VERSION 5.8 ;
BUSBITCHARS "[]" ;
DIVIDERCHAR "/" ;
UNITS
    DATABASE MICRONS 1000 ;
END UNITS

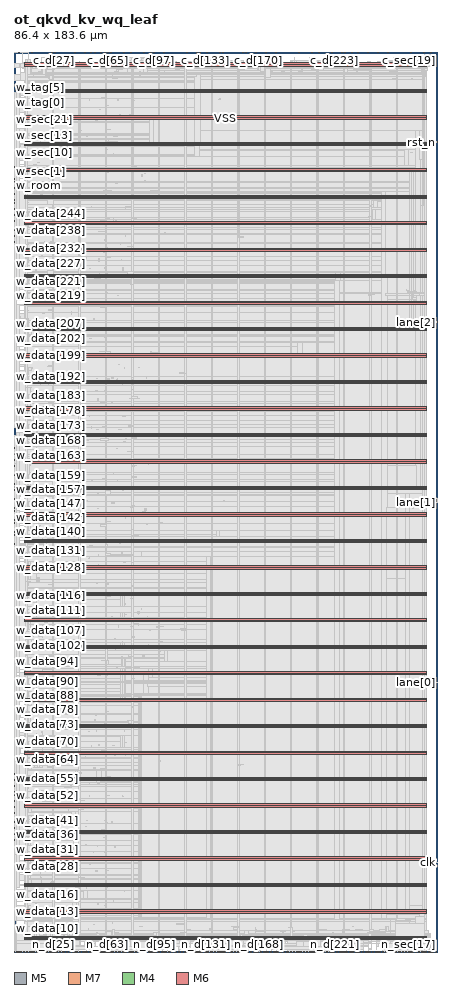
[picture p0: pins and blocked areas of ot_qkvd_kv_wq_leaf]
MACRO ot_qkvd_kv_wq_leaf
  FOREIGN ot_qkvd_kv_wq_leaf 0 0 ;
  CLASS BLOCK ;
  SIZE 86.4 BY 183.6 ;
  PIN c_d[0]
    DIRECTION INPUT ;
    USE SIGNAL ;
    PORT
      LAYER M5 ;
        RECT  0.144 183.516 0.168 183.6 ;
    END
  END c_d[0]
  PIN c_d[100]
    DIRECTION INPUT ;
    USE SIGNAL ;
    PORT
      LAYER M7 ;
        RECT  29.44 183.53 29.472 183.6 ;
    END
  END c_d[100]
  PIN c_d[101]
    DIRECTION INPUT ;
    USE SIGNAL ;
    PORT
      LAYER M7 ;
        RECT  29.696 183.53 29.728 183.6 ;
    END
  END c_d[101]
  PIN c_d[102]
    DIRECTION INPUT ;
    USE SIGNAL ;
    PORT
      LAYER M7 ;
        RECT  30.016 183.53 30.048 183.6 ;
    END
  END c_d[102]
  PIN c_d[103]
    DIRECTION INPUT ;
    USE SIGNAL ;
    PORT
      LAYER M7 ;
        RECT  30.272 183.53 30.304 183.6 ;
    END
  END c_d[103]
  PIN c_d[104]
    DIRECTION INPUT ;
    USE SIGNAL ;
    PORT
      LAYER M7 ;
        RECT  30.592 183.53 30.624 183.6 ;
    END
  END c_d[104]
  PIN c_d[105]
    DIRECTION INPUT ;
    USE SIGNAL ;
    PORT
      LAYER M7 ;
        RECT  30.912 183.53 30.944 183.6 ;
    END
  END c_d[105]
  PIN c_d[106]
    DIRECTION INPUT ;
    USE SIGNAL ;
    PORT
      LAYER M7 ;
        RECT  31.168 183.53 31.2 183.6 ;
    END
  END c_d[106]
  PIN c_d[107]
    DIRECTION INPUT ;
    USE SIGNAL ;
    PORT
      LAYER M7 ;
        RECT  31.488 183.53 31.52 183.6 ;
    END
  END c_d[107]
  PIN c_d[108]
    DIRECTION INPUT ;
    USE SIGNAL ;
    PORT
      LAYER M7 ;
        RECT  31.744 183.53 31.776 183.6 ;
    END
  END c_d[108]
  PIN c_d[109]
    DIRECTION INPUT ;
    USE SIGNAL ;
    PORT
      LAYER M7 ;
        RECT  32.064 183.53 32.096 183.6 ;
    END
  END c_d[109]
  PIN c_d[10]
    DIRECTION INPUT ;
    USE SIGNAL ;
    PORT
      LAYER M5 ;
        RECT  3.072 183.516 3.096 183.6 ;
    END
  END c_d[10]
  PIN c_d[110]
    DIRECTION INPUT ;
    USE SIGNAL ;
    PORT
      LAYER M7 ;
        RECT  32.32 183.53 32.352 183.6 ;
    END
  END c_d[110]
  PIN c_d[111]
    DIRECTION INPUT ;
    USE SIGNAL ;
    PORT
      LAYER M7 ;
        RECT  32.64 183.53 32.672 183.6 ;
    END
  END c_d[111]
  PIN c_d[112]
    DIRECTION INPUT ;
    USE SIGNAL ;
    PORT
      LAYER M7 ;
        RECT  32.96 183.53 32.992 183.6 ;
    END
  END c_d[112]
  PIN c_d[113]
    DIRECTION INPUT ;
    USE SIGNAL ;
    PORT
      LAYER M7 ;
        RECT  33.216 183.53 33.248 183.6 ;
    END
  END c_d[113]
  PIN c_d[114]
    DIRECTION INPUT ;
    USE SIGNAL ;
    PORT
      LAYER M7 ;
        RECT  33.536 183.53 33.568 183.6 ;
    END
  END c_d[114]
  PIN c_d[115]
    DIRECTION INPUT ;
    USE SIGNAL ;
    PORT
      LAYER M7 ;
        RECT  33.792 183.53 33.824 183.6 ;
    END
  END c_d[115]
  PIN c_d[116]
    DIRECTION INPUT ;
    USE SIGNAL ;
    PORT
      LAYER M7 ;
        RECT  34.112 183.53 34.144 183.6 ;
    END
  END c_d[116]
  PIN c_d[117]
    DIRECTION INPUT ;
    USE SIGNAL ;
    PORT
      LAYER M7 ;
        RECT  34.368 183.53 34.4 183.6 ;
    END
  END c_d[117]
  PIN c_d[118]
    DIRECTION INPUT ;
    USE SIGNAL ;
    PORT
      LAYER M7 ;
        RECT  34.688 183.53 34.72 183.6 ;
    END
  END c_d[118]
  PIN c_d[119]
    DIRECTION INPUT ;
    USE SIGNAL ;
    PORT
      LAYER M7 ;
        RECT  35.008 183.53 35.04 183.6 ;
    END
  END c_d[119]
  PIN c_d[11]
    DIRECTION INPUT ;
    USE SIGNAL ;
    PORT
      LAYER M5 ;
        RECT  3.36 183.516 3.384 183.6 ;
    END
  END c_d[11]
  PIN c_d[120]
    DIRECTION INPUT ;
    USE SIGNAL ;
    PORT
      LAYER M7 ;
        RECT  35.264 183.53 35.296 183.6 ;
    END
  END c_d[120]
  PIN c_d[121]
    DIRECTION INPUT ;
    USE SIGNAL ;
    PORT
      LAYER M7 ;
        RECT  35.584 183.53 35.616 183.6 ;
    END
  END c_d[121]
  PIN c_d[122]
    DIRECTION INPUT ;
    USE SIGNAL ;
    PORT
      LAYER M7 ;
        RECT  35.84 183.53 35.872 183.6 ;
    END
  END c_d[122]
  PIN c_d[123]
    DIRECTION INPUT ;
    USE SIGNAL ;
    PORT
      LAYER M7 ;
        RECT  36.16 183.53 36.192 183.6 ;
    END
  END c_d[123]
  PIN c_d[124]
    DIRECTION INPUT ;
    USE SIGNAL ;
    PORT
      LAYER M7 ;
        RECT  36.48 183.53 36.512 183.6 ;
    END
  END c_d[124]
  PIN c_d[125]
    DIRECTION INPUT ;
    USE SIGNAL ;
    PORT
      LAYER M7 ;
        RECT  36.736 183.53 36.768 183.6 ;
    END
  END c_d[125]
  PIN c_d[126]
    DIRECTION INPUT ;
    USE SIGNAL ;
    PORT
      LAYER M7 ;
        RECT  37.056 183.53 37.088 183.6 ;
    END
  END c_d[126]
  PIN c_d[127]
    DIRECTION INPUT ;
    USE SIGNAL ;
    PORT
      LAYER M7 ;
        RECT  37.312 183.53 37.344 183.6 ;
    END
  END c_d[127]
  PIN c_d[128]
    DIRECTION INPUT ;
    USE SIGNAL ;
    PORT
      LAYER M5 ;
        RECT  37.632 183.516 37.656 183.6 ;
    END
  END c_d[128]
  PIN c_d[129]
    DIRECTION INPUT ;
    USE SIGNAL ;
    PORT
      LAYER M5 ;
        RECT  37.92 183.516 37.944 183.6 ;
    END
  END c_d[129]
  PIN c_d[12]
    DIRECTION INPUT ;
    USE SIGNAL ;
    PORT
      LAYER M5 ;
        RECT  3.648 183.516 3.672 183.6 ;
    END
  END c_d[12]
  PIN c_d[130]
    DIRECTION INPUT ;
    USE SIGNAL ;
    PORT
      LAYER M5 ;
        RECT  38.208 183.516 38.232 183.6 ;
    END
  END c_d[130]
  PIN c_d[131]
    DIRECTION INPUT ;
    USE SIGNAL ;
    PORT
      LAYER M5 ;
        RECT  38.496 183.516 38.52 183.6 ;
    END
  END c_d[131]
  PIN c_d[132]
    DIRECTION INPUT ;
    USE SIGNAL ;
    PORT
      LAYER M5 ;
        RECT  38.784 183.516 38.808 183.6 ;
    END
  END c_d[132]
  PIN c_d[133]
    DIRECTION INPUT ;
    USE SIGNAL ;
    PORT
      LAYER M5 ;
        RECT  39.072 183.516 39.096 183.6 ;
    END
  END c_d[133]
  PIN c_d[134]
    DIRECTION INPUT ;
    USE SIGNAL ;
    PORT
      LAYER M5 ;
        RECT  39.36 183.516 39.384 183.6 ;
    END
  END c_d[134]
  PIN c_d[135]
    DIRECTION INPUT ;
    USE SIGNAL ;
    PORT
      LAYER M5 ;
        RECT  39.696 183.516 39.72 183.6 ;
    END
  END c_d[135]
  PIN c_d[136]
    DIRECTION INPUT ;
    USE SIGNAL ;
    PORT
      LAYER M5 ;
        RECT  39.984 183.516 40.008 183.6 ;
    END
  END c_d[136]
  PIN c_d[137]
    DIRECTION INPUT ;
    USE SIGNAL ;
    PORT
      LAYER M5 ;
        RECT  40.272 183.516 40.296 183.6 ;
    END
  END c_d[137]
  PIN c_d[138]
    DIRECTION INPUT ;
    USE SIGNAL ;
    PORT
      LAYER M5 ;
        RECT  40.56 183.516 40.584 183.6 ;
    END
  END c_d[138]
  PIN c_d[139]
    DIRECTION INPUT ;
    USE SIGNAL ;
    PORT
      LAYER M5 ;
        RECT  40.848 183.516 40.872 183.6 ;
    END
  END c_d[139]
  PIN c_d[13]
    DIRECTION INPUT ;
    USE SIGNAL ;
    PORT
      LAYER M5 ;
        RECT  3.936 183.516 3.96 183.6 ;
    END
  END c_d[13]
  PIN c_d[140]
    DIRECTION INPUT ;
    USE SIGNAL ;
    PORT
      LAYER M5 ;
        RECT  41.136 183.516 41.16 183.6 ;
    END
  END c_d[140]
  PIN c_d[141]
    DIRECTION INPUT ;
    USE SIGNAL ;
    PORT
      LAYER M5 ;
        RECT  41.424 183.516 41.448 183.6 ;
    END
  END c_d[141]
  PIN c_d[142]
    DIRECTION INPUT ;
    USE SIGNAL ;
    PORT
      LAYER M5 ;
        RECT  41.712 183.516 41.736 183.6 ;
    END
  END c_d[142]
  PIN c_d[143]
    DIRECTION INPUT ;
    USE SIGNAL ;
    PORT
      LAYER M5 ;
        RECT  42 183.516 42.024 183.6 ;
    END
  END c_d[143]
  PIN c_d[144]
    DIRECTION INPUT ;
    USE SIGNAL ;
    PORT
      LAYER M5 ;
        RECT  42.288 183.516 42.312 183.6 ;
    END
  END c_d[144]
  PIN c_d[145]
    DIRECTION INPUT ;
    USE SIGNAL ;
    PORT
      LAYER M5 ;
        RECT  42.624 183.516 42.648 183.6 ;
    END
  END c_d[145]
  PIN c_d[146]
    DIRECTION INPUT ;
    USE SIGNAL ;
    PORT
      LAYER M5 ;
        RECT  42.912 183.516 42.936 183.6 ;
    END
  END c_d[146]
  PIN c_d[147]
    DIRECTION INPUT ;
    USE SIGNAL ;
    PORT
      LAYER M5 ;
        RECT  43.2 183.516 43.224 183.6 ;
    END
  END c_d[147]
  PIN c_d[148]
    DIRECTION INPUT ;
    USE SIGNAL ;
    PORT
      LAYER M5 ;
        RECT  43.488 183.516 43.512 183.6 ;
    END
  END c_d[148]
  PIN c_d[149]
    DIRECTION INPUT ;
    USE SIGNAL ;
    PORT
      LAYER M5 ;
        RECT  43.776 183.516 43.8 183.6 ;
    END
  END c_d[149]
  PIN c_d[14]
    DIRECTION INPUT ;
    USE SIGNAL ;
    PORT
      LAYER M5 ;
        RECT  4.224 183.516 4.248 183.6 ;
    END
  END c_d[14]
  PIN c_d[150]
    DIRECTION INPUT ;
    USE SIGNAL ;
    PORT
      LAYER M5 ;
        RECT  44.064 183.516 44.088 183.6 ;
    END
  END c_d[150]
  PIN c_d[151]
    DIRECTION INPUT ;
    USE SIGNAL ;
    PORT
      LAYER M5 ;
        RECT  44.352 183.516 44.376 183.6 ;
    END
  END c_d[151]
  PIN c_d[152]
    DIRECTION INPUT ;
    USE SIGNAL ;
    PORT
      LAYER M5 ;
        RECT  44.64 183.516 44.664 183.6 ;
    END
  END c_d[152]
  PIN c_d[153]
    DIRECTION INPUT ;
    USE SIGNAL ;
    PORT
      LAYER M5 ;
        RECT  44.928 183.516 44.952 183.6 ;
    END
  END c_d[153]
  PIN c_d[154]
    DIRECTION INPUT ;
    USE SIGNAL ;
    PORT
      LAYER M5 ;
        RECT  45.216 183.516 45.24 183.6 ;
    END
  END c_d[154]
  PIN c_d[155]
    DIRECTION INPUT ;
    USE SIGNAL ;
    PORT
      LAYER M5 ;
        RECT  45.552 183.516 45.576 183.6 ;
    END
  END c_d[155]
  PIN c_d[156]
    DIRECTION INPUT ;
    USE SIGNAL ;
    PORT
      LAYER M5 ;
        RECT  45.84 183.516 45.864 183.6 ;
    END
  END c_d[156]
  PIN c_d[157]
    DIRECTION INPUT ;
    USE SIGNAL ;
    PORT
      LAYER M5 ;
        RECT  46.128 183.516 46.152 183.6 ;
    END
  END c_d[157]
  PIN c_d[158]
    DIRECTION INPUT ;
    USE SIGNAL ;
    PORT
      LAYER M5 ;
        RECT  46.416 183.516 46.44 183.6 ;
    END
  END c_d[158]
  PIN c_d[159]
    DIRECTION INPUT ;
    USE SIGNAL ;
    PORT
      LAYER M5 ;
        RECT  46.704 183.516 46.728 183.6 ;
    END
  END c_d[159]
  PIN c_d[15]
    DIRECTION INPUT ;
    USE SIGNAL ;
    PORT
      LAYER M5 ;
        RECT  4.512 183.516 4.536 183.6 ;
    END
  END c_d[15]
  PIN c_d[160]
    DIRECTION INPUT ;
    USE SIGNAL ;
    PORT
      LAYER M7 ;
        RECT  46.976 183.53 47.008 183.6 ;
    END
  END c_d[160]
  PIN c_d[161]
    DIRECTION INPUT ;
    USE SIGNAL ;
    PORT
      LAYER M7 ;
        RECT  47.296 183.53 47.328 183.6 ;
    END
  END c_d[161]
  PIN c_d[162]
    DIRECTION INPUT ;
    USE SIGNAL ;
    PORT
      LAYER M7 ;
        RECT  47.552 183.53 47.584 183.6 ;
    END
  END c_d[162]
  PIN c_d[163]
    DIRECTION INPUT ;
    USE SIGNAL ;
    PORT
      LAYER M7 ;
        RECT  47.872 183.53 47.904 183.6 ;
    END
  END c_d[163]
  PIN c_d[164]
    DIRECTION INPUT ;
    USE SIGNAL ;
    PORT
      LAYER M7 ;
        RECT  48.192 183.53 48.224 183.6 ;
    END
  END c_d[164]
  PIN c_d[165]
    DIRECTION INPUT ;
    USE SIGNAL ;
    PORT
      LAYER M7 ;
        RECT  48.448 183.53 48.48 183.6 ;
    END
  END c_d[165]
  PIN c_d[166]
    DIRECTION INPUT ;
    USE SIGNAL ;
    PORT
      LAYER M7 ;
        RECT  48.768 183.53 48.8 183.6 ;
    END
  END c_d[166]
  PIN c_d[167]
    DIRECTION INPUT ;
    USE SIGNAL ;
    PORT
      LAYER M7 ;
        RECT  49.024 183.53 49.056 183.6 ;
    END
  END c_d[167]
  PIN c_d[168]
    DIRECTION INPUT ;
    USE SIGNAL ;
    PORT
      LAYER M7 ;
        RECT  49.344 183.53 49.376 183.6 ;
    END
  END c_d[168]
  PIN c_d[169]
    DIRECTION INPUT ;
    USE SIGNAL ;
    PORT
      LAYER M7 ;
        RECT  49.6 183.53 49.632 183.6 ;
    END
  END c_d[169]
  PIN c_d[16]
    DIRECTION INPUT ;
    USE SIGNAL ;
    PORT
      LAYER M5 ;
        RECT  4.8 183.516 4.824 183.6 ;
    END
  END c_d[16]
  PIN c_d[170]
    DIRECTION INPUT ;
    USE SIGNAL ;
    PORT
      LAYER M7 ;
        RECT  49.92 183.53 49.952 183.6 ;
    END
  END c_d[170]
  PIN c_d[171]
    DIRECTION INPUT ;
    USE SIGNAL ;
    PORT
      LAYER M7 ;
        RECT  50.24 183.53 50.272 183.6 ;
    END
  END c_d[171]
  PIN c_d[172]
    DIRECTION INPUT ;
    USE SIGNAL ;
    PORT
      LAYER M7 ;
        RECT  50.496 183.53 50.528 183.6 ;
    END
  END c_d[172]
  PIN c_d[173]
    DIRECTION INPUT ;
    USE SIGNAL ;
    PORT
      LAYER M7 ;
        RECT  50.816 183.53 50.848 183.6 ;
    END
  END c_d[173]
  PIN c_d[174]
    DIRECTION INPUT ;
    USE SIGNAL ;
    PORT
      LAYER M7 ;
        RECT  51.072 183.53 51.104 183.6 ;
    END
  END c_d[174]
  PIN c_d[175]
    DIRECTION INPUT ;
    USE SIGNAL ;
    PORT
      LAYER M7 ;
        RECT  51.392 183.53 51.424 183.6 ;
    END
  END c_d[175]
  PIN c_d[176]
    DIRECTION INPUT ;
    USE SIGNAL ;
    PORT
      LAYER M7 ;
        RECT  51.648 183.53 51.68 183.6 ;
    END
  END c_d[176]
  PIN c_d[177]
    DIRECTION INPUT ;
    USE SIGNAL ;
    PORT
      LAYER M7 ;
        RECT  51.968 183.53 52 183.6 ;
    END
  END c_d[177]
  PIN c_d[178]
    DIRECTION INPUT ;
    USE SIGNAL ;
    PORT
      LAYER M7 ;
        RECT  52.288 183.53 52.32 183.6 ;
    END
  END c_d[178]
  PIN c_d[179]
    DIRECTION INPUT ;
    USE SIGNAL ;
    PORT
      LAYER M7 ;
        RECT  52.544 183.53 52.576 183.6 ;
    END
  END c_d[179]
  PIN c_d[17]
    DIRECTION INPUT ;
    USE SIGNAL ;
    PORT
      LAYER M5 ;
        RECT  5.136 183.516 5.16 183.6 ;
    END
  END c_d[17]
  PIN c_d[180]
    DIRECTION INPUT ;
    USE SIGNAL ;
    PORT
      LAYER M7 ;
        RECT  52.864 183.53 52.896 183.6 ;
    END
  END c_d[180]
  PIN c_d[181]
    DIRECTION INPUT ;
    USE SIGNAL ;
    PORT
      LAYER M7 ;
        RECT  53.12 183.53 53.152 183.6 ;
    END
  END c_d[181]
  PIN c_d[182]
    DIRECTION INPUT ;
    USE SIGNAL ;
    PORT
      LAYER M7 ;
        RECT  53.44 183.53 53.472 183.6 ;
    END
  END c_d[182]
  PIN c_d[183]
    DIRECTION INPUT ;
    USE SIGNAL ;
    PORT
      LAYER M7 ;
        RECT  53.76 183.53 53.792 183.6 ;
    END
  END c_d[183]
  PIN c_d[184]
    DIRECTION INPUT ;
    USE SIGNAL ;
    PORT
      LAYER M7 ;
        RECT  54.016 183.53 54.048 183.6 ;
    END
  END c_d[184]
  PIN c_d[185]
    DIRECTION INPUT ;
    USE SIGNAL ;
    PORT
      LAYER M7 ;
        RECT  54.336 183.53 54.368 183.6 ;
    END
  END c_d[185]
  PIN c_d[186]
    DIRECTION INPUT ;
    USE SIGNAL ;
    PORT
      LAYER M7 ;
        RECT  54.592 183.53 54.624 183.6 ;
    END
  END c_d[186]
  PIN c_d[187]
    DIRECTION INPUT ;
    USE SIGNAL ;
    PORT
      LAYER M7 ;
        RECT  54.912 183.53 54.944 183.6 ;
    END
  END c_d[187]
  PIN c_d[188]
    DIRECTION INPUT ;
    USE SIGNAL ;
    PORT
      LAYER M7 ;
        RECT  55.168 183.53 55.2 183.6 ;
    END
  END c_d[188]
  PIN c_d[189]
    DIRECTION INPUT ;
    USE SIGNAL ;
    PORT
      LAYER M7 ;
        RECT  55.488 183.53 55.52 183.6 ;
    END
  END c_d[189]
  PIN c_d[18]
    DIRECTION INPUT ;
    USE SIGNAL ;
    PORT
      LAYER M5 ;
        RECT  5.424 183.516 5.448 183.6 ;
    END
  END c_d[18]
  PIN c_d[190]
    DIRECTION INPUT ;
    USE SIGNAL ;
    PORT
      LAYER M7 ;
        RECT  55.808 183.53 55.84 183.6 ;
    END
  END c_d[190]
  PIN c_d[191]
    DIRECTION INPUT ;
    USE SIGNAL ;
    PORT
      LAYER M7 ;
        RECT  56.064 183.53 56.096 183.6 ;
    END
  END c_d[191]
  PIN c_d[192]
    DIRECTION INPUT ;
    USE SIGNAL ;
    PORT
      LAYER M5 ;
        RECT  56.352 183.516 56.376 183.6 ;
    END
  END c_d[192]
  PIN c_d[193]
    DIRECTION INPUT ;
    USE SIGNAL ;
    PORT
      LAYER M5 ;
        RECT  56.64 183.516 56.664 183.6 ;
    END
  END c_d[193]
  PIN c_d[194]
    DIRECTION INPUT ;
    USE SIGNAL ;
    PORT
      LAYER M5 ;
        RECT  56.976 183.516 57 183.6 ;
    END
  END c_d[194]
  PIN c_d[195]
    DIRECTION INPUT ;
    USE SIGNAL ;
    PORT
      LAYER M5 ;
        RECT  57.264 183.516 57.288 183.6 ;
    END
  END c_d[195]
  PIN c_d[196]
    DIRECTION INPUT ;
    USE SIGNAL ;
    PORT
      LAYER M5 ;
        RECT  57.552 183.516 57.576 183.6 ;
    END
  END c_d[196]
  PIN c_d[197]
    DIRECTION INPUT ;
    USE SIGNAL ;
    PORT
      LAYER M5 ;
        RECT  57.84 183.516 57.864 183.6 ;
    END
  END c_d[197]
  PIN c_d[198]
    DIRECTION INPUT ;
    USE SIGNAL ;
    PORT
      LAYER M5 ;
        RECT  58.128 183.516 58.152 183.6 ;
    END
  END c_d[198]
  PIN c_d[199]
    DIRECTION INPUT ;
    USE SIGNAL ;
    PORT
      LAYER M5 ;
        RECT  58.416 183.516 58.44 183.6 ;
    END
  END c_d[199]
  PIN c_d[19]
    DIRECTION INPUT ;
    USE SIGNAL ;
    PORT
      LAYER M5 ;
        RECT  5.712 183.516 5.736 183.6 ;
    END
  END c_d[19]
  PIN c_d[1]
    DIRECTION INPUT ;
    USE SIGNAL ;
    PORT
      LAYER M5 ;
        RECT  0.432 183.516 0.456 183.6 ;
    END
  END c_d[1]
  PIN c_d[200]
    DIRECTION INPUT ;
    USE SIGNAL ;
    PORT
      LAYER M5 ;
        RECT  58.704 183.516 58.728 183.6 ;
    END
  END c_d[200]
  PIN c_d[201]
    DIRECTION INPUT ;
    USE SIGNAL ;
    PORT
      LAYER M5 ;
        RECT  58.992 183.516 59.016 183.6 ;
    END
  END c_d[201]
  PIN c_d[202]
    DIRECTION INPUT ;
    USE SIGNAL ;
    PORT
      LAYER M5 ;
        RECT  59.28 183.516 59.304 183.6 ;
    END
  END c_d[202]
  PIN c_d[203]
    DIRECTION INPUT ;
    USE SIGNAL ;
    PORT
      LAYER M5 ;
        RECT  59.568 183.516 59.592 183.6 ;
    END
  END c_d[203]
  PIN c_d[204]
    DIRECTION INPUT ;
    USE SIGNAL ;
    PORT
      LAYER M5 ;
        RECT  59.904 183.516 59.928 183.6 ;
    END
  END c_d[204]
  PIN c_d[205]
    DIRECTION INPUT ;
    USE SIGNAL ;
    PORT
      LAYER M5 ;
        RECT  60.192 183.516 60.216 183.6 ;
    END
  END c_d[205]
  PIN c_d[206]
    DIRECTION INPUT ;
    USE SIGNAL ;
    PORT
      LAYER M5 ;
        RECT  60.48 183.516 60.504 183.6 ;
    END
  END c_d[206]
  PIN c_d[207]
    DIRECTION INPUT ;
    USE SIGNAL ;
    PORT
      LAYER M5 ;
        RECT  60.768 183.516 60.792 183.6 ;
    END
  END c_d[207]
  PIN c_d[208]
    DIRECTION INPUT ;
    USE SIGNAL ;
    PORT
      LAYER M5 ;
        RECT  61.056 183.516 61.08 183.6 ;
    END
  END c_d[208]
  PIN c_d[209]
    DIRECTION INPUT ;
    USE SIGNAL ;
    PORT
      LAYER M5 ;
        RECT  61.344 183.516 61.368 183.6 ;
    END
  END c_d[209]
  PIN c_d[20]
    DIRECTION INPUT ;
    USE SIGNAL ;
    PORT
      LAYER M5 ;
        RECT  6 183.516 6.024 183.6 ;
    END
  END c_d[20]
  PIN c_d[210]
    DIRECTION INPUT ;
    USE SIGNAL ;
    PORT
      LAYER M5 ;
        RECT  61.632 183.516 61.656 183.6 ;
    END
  END c_d[210]
  PIN c_d[211]
    DIRECTION INPUT ;
    USE SIGNAL ;
    PORT
      LAYER M5 ;
        RECT  61.92 183.516 61.944 183.6 ;
    END
  END c_d[211]
  PIN c_d[212]
    DIRECTION INPUT ;
    USE SIGNAL ;
    PORT
      LAYER M5 ;
        RECT  62.208 183.516 62.232 183.6 ;
    END
  END c_d[212]
  PIN c_d[213]
    DIRECTION INPUT ;
    USE SIGNAL ;
    PORT
      LAYER M5 ;
        RECT  62.496 183.516 62.52 183.6 ;
    END
  END c_d[213]
  PIN c_d[214]
    DIRECTION INPUT ;
    USE SIGNAL ;
    PORT
      LAYER M5 ;
        RECT  62.832 183.516 62.856 183.6 ;
    END
  END c_d[214]
  PIN c_d[215]
    DIRECTION INPUT ;
    USE SIGNAL ;
    PORT
      LAYER M5 ;
        RECT  63.12 183.516 63.144 183.6 ;
    END
  END c_d[215]
  PIN c_d[216]
    DIRECTION INPUT ;
    USE SIGNAL ;
    PORT
      LAYER M5 ;
        RECT  63.408 183.516 63.432 183.6 ;
    END
  END c_d[216]
  PIN c_d[217]
    DIRECTION INPUT ;
    USE SIGNAL ;
    PORT
      LAYER M5 ;
        RECT  63.696 183.516 63.72 183.6 ;
    END
  END c_d[217]
  PIN c_d[218]
    DIRECTION INPUT ;
    USE SIGNAL ;
    PORT
      LAYER M5 ;
        RECT  63.984 183.516 64.008 183.6 ;
    END
  END c_d[218]
  PIN c_d[219]
    DIRECTION INPUT ;
    USE SIGNAL ;
    PORT
      LAYER M5 ;
        RECT  64.272 183.516 64.296 183.6 ;
    END
  END c_d[219]
  PIN c_d[21]
    DIRECTION INPUT ;
    USE SIGNAL ;
    PORT
      LAYER M5 ;
        RECT  6.288 183.516 6.312 183.6 ;
    END
  END c_d[21]
  PIN c_d[220]
    DIRECTION INPUT ;
    USE SIGNAL ;
    PORT
      LAYER M5 ;
        RECT  64.56 183.516 64.584 183.6 ;
    END
  END c_d[220]
  PIN c_d[221]
    DIRECTION INPUT ;
    USE SIGNAL ;
    PORT
      LAYER M5 ;
        RECT  64.848 183.516 64.872 183.6 ;
    END
  END c_d[221]
  PIN c_d[222]
    DIRECTION INPUT ;
    USE SIGNAL ;
    PORT
      LAYER M5 ;
        RECT  65.136 183.516 65.16 183.6 ;
    END
  END c_d[222]
  PIN c_d[223]
    DIRECTION INPUT ;
    USE SIGNAL ;
    PORT
      LAYER M5 ;
        RECT  65.424 183.516 65.448 183.6 ;
    END
  END c_d[223]
  PIN c_d[224]
    DIRECTION INPUT ;
    USE SIGNAL ;
    PORT
      LAYER M7 ;
        RECT  65.728 183.53 65.76 183.6 ;
    END
  END c_d[224]
  PIN c_d[225]
    DIRECTION INPUT ;
    USE SIGNAL ;
    PORT
      LAYER M7 ;
        RECT  66.048 183.53 66.08 183.6 ;
    END
  END c_d[225]
  PIN c_d[226]
    DIRECTION INPUT ;
    USE SIGNAL ;
    PORT
      LAYER M7 ;
        RECT  66.304 183.53 66.336 183.6 ;
    END
  END c_d[226]
  PIN c_d[227]
    DIRECTION INPUT ;
    USE SIGNAL ;
    PORT
      LAYER M7 ;
        RECT  66.624 183.53 66.656 183.6 ;
    END
  END c_d[227]
  PIN c_d[228]
    DIRECTION INPUT ;
    USE SIGNAL ;
    PORT
      LAYER M7 ;
        RECT  66.88 183.53 66.912 183.6 ;
    END
  END c_d[228]
  PIN c_d[229]
    DIRECTION INPUT ;
    USE SIGNAL ;
    PORT
      LAYER M7 ;
        RECT  67.2 183.53 67.232 183.6 ;
    END
  END c_d[229]
  PIN c_d[22]
    DIRECTION INPUT ;
    USE SIGNAL ;
    PORT
      LAYER M5 ;
        RECT  6.576 183.516 6.6 183.6 ;
    END
  END c_d[22]
  PIN c_d[230]
    DIRECTION INPUT ;
    USE SIGNAL ;
    PORT
      LAYER M7 ;
        RECT  67.52 183.53 67.552 183.6 ;
    END
  END c_d[230]
  PIN c_d[231]
    DIRECTION INPUT ;
    USE SIGNAL ;
    PORT
      LAYER M7 ;
        RECT  67.776 183.53 67.808 183.6 ;
    END
  END c_d[231]
  PIN c_d[232]
    DIRECTION INPUT ;
    USE SIGNAL ;
    PORT
      LAYER M7 ;
        RECT  68.096 183.53 68.128 183.6 ;
    END
  END c_d[232]
  PIN c_d[233]
    DIRECTION INPUT ;
    USE SIGNAL ;
    PORT
      LAYER M7 ;
        RECT  68.352 183.53 68.384 183.6 ;
    END
  END c_d[233]
  PIN c_d[234]
    DIRECTION INPUT ;
    USE SIGNAL ;
    PORT
      LAYER M7 ;
        RECT  68.672 183.53 68.704 183.6 ;
    END
  END c_d[234]
  PIN c_d[235]
    DIRECTION INPUT ;
    USE SIGNAL ;
    PORT
      LAYER M7 ;
        RECT  68.928 183.53 68.96 183.6 ;
    END
  END c_d[235]
  PIN c_d[236]
    DIRECTION INPUT ;
    USE SIGNAL ;
    PORT
      LAYER M7 ;
        RECT  69.248 183.53 69.28 183.6 ;
    END
  END c_d[236]
  PIN c_d[237]
    DIRECTION INPUT ;
    USE SIGNAL ;
    PORT
      LAYER M7 ;
        RECT  69.568 183.53 69.6 183.6 ;
    END
  END c_d[237]
  PIN c_d[238]
    DIRECTION INPUT ;
    USE SIGNAL ;
    PORT
      LAYER M7 ;
        RECT  69.824 183.53 69.856 183.6 ;
    END
  END c_d[238]
  PIN c_d[239]
    DIRECTION INPUT ;
    USE SIGNAL ;
    PORT
      LAYER M7 ;
        RECT  70.144 183.53 70.176 183.6 ;
    END
  END c_d[239]
  PIN c_d[23]
    DIRECTION INPUT ;
    USE SIGNAL ;
    PORT
      LAYER M5 ;
        RECT  6.864 183.516 6.888 183.6 ;
    END
  END c_d[23]
  PIN c_d[240]
    DIRECTION INPUT ;
    USE SIGNAL ;
    PORT
      LAYER M7 ;
        RECT  70.4 183.53 70.432 183.6 ;
    END
  END c_d[240]
  PIN c_d[241]
    DIRECTION INPUT ;
    USE SIGNAL ;
    PORT
      LAYER M7 ;
        RECT  70.72 183.53 70.752 183.6 ;
    END
  END c_d[241]
  PIN c_d[242]
    DIRECTION INPUT ;
    USE SIGNAL ;
    PORT
      LAYER M7 ;
        RECT  71.04 183.53 71.072 183.6 ;
    END
  END c_d[242]
  PIN c_d[243]
    DIRECTION INPUT ;
    USE SIGNAL ;
    PORT
      LAYER M7 ;
        RECT  71.296 183.53 71.328 183.6 ;
    END
  END c_d[243]
  PIN c_d[244]
    DIRECTION INPUT ;
    USE SIGNAL ;
    PORT
      LAYER M7 ;
        RECT  71.616 183.53 71.648 183.6 ;
    END
  END c_d[244]
  PIN c_d[245]
    DIRECTION INPUT ;
    USE SIGNAL ;
    PORT
      LAYER M7 ;
        RECT  71.872 183.53 71.904 183.6 ;
    END
  END c_d[245]
  PIN c_d[246]
    DIRECTION INPUT ;
    USE SIGNAL ;
    PORT
      LAYER M7 ;
        RECT  72.192 183.53 72.224 183.6 ;
    END
  END c_d[246]
  PIN c_d[247]
    DIRECTION INPUT ;
    USE SIGNAL ;
    PORT
      LAYER M7 ;
        RECT  72.448 183.53 72.48 183.6 ;
    END
  END c_d[247]
  PIN c_d[248]
    DIRECTION INPUT ;
    USE SIGNAL ;
    PORT
      LAYER M7 ;
        RECT  72.768 183.53 72.8 183.6 ;
    END
  END c_d[248]
  PIN c_d[249]
    DIRECTION INPUT ;
    USE SIGNAL ;
    PORT
      LAYER M7 ;
        RECT  73.088 183.53 73.12 183.6 ;
    END
  END c_d[249]
  PIN c_d[24]
    DIRECTION INPUT ;
    USE SIGNAL ;
    PORT
      LAYER M5 ;
        RECT  7.152 183.516 7.176 183.6 ;
    END
  END c_d[24]
  PIN c_d[250]
    DIRECTION INPUT ;
    USE SIGNAL ;
    PORT
      LAYER M7 ;
        RECT  73.344 183.53 73.376 183.6 ;
    END
  END c_d[250]
  PIN c_d[251]
    DIRECTION INPUT ;
    USE SIGNAL ;
    PORT
      LAYER M7 ;
        RECT  73.664 183.53 73.696 183.6 ;
    END
  END c_d[251]
  PIN c_d[252]
    DIRECTION INPUT ;
    USE SIGNAL ;
    PORT
      LAYER M7 ;
        RECT  73.92 183.53 73.952 183.6 ;
    END
  END c_d[252]
  PIN c_d[253]
    DIRECTION INPUT ;
    USE SIGNAL ;
    PORT
      LAYER M7 ;
        RECT  74.24 183.53 74.272 183.6 ;
    END
  END c_d[253]
  PIN c_d[254]
    DIRECTION INPUT ;
    USE SIGNAL ;
    PORT
      LAYER M7 ;
        RECT  74.496 183.53 74.528 183.6 ;
    END
  END c_d[254]
  PIN c_d[255]
    DIRECTION INPUT ;
    USE SIGNAL ;
    PORT
      LAYER M7 ;
        RECT  74.816 183.53 74.848 183.6 ;
    END
  END c_d[255]
  PIN c_d[25]
    DIRECTION INPUT ;
    USE SIGNAL ;
    PORT
      LAYER M5 ;
        RECT  7.44 183.516 7.464 183.6 ;
    END
  END c_d[25]
  PIN c_d[26]
    DIRECTION INPUT ;
    USE SIGNAL ;
    PORT
      LAYER M5 ;
        RECT  7.728 183.516 7.752 183.6 ;
    END
  END c_d[26]
  PIN c_d[27]
    DIRECTION INPUT ;
    USE SIGNAL ;
    PORT
      LAYER M5 ;
        RECT  8.064 183.516 8.088 183.6 ;
    END
  END c_d[27]
  PIN c_d[28]
    DIRECTION INPUT ;
    USE SIGNAL ;
    PORT
      LAYER M5 ;
        RECT  8.352 183.516 8.376 183.6 ;
    END
  END c_d[28]
  PIN c_d[29]
    DIRECTION INPUT ;
    USE SIGNAL ;
    PORT
      LAYER M5 ;
        RECT  8.64 183.516 8.664 183.6 ;
    END
  END c_d[29]
  PIN c_d[2]
    DIRECTION INPUT ;
    USE SIGNAL ;
    PORT
      LAYER M5 ;
        RECT  0.72 183.516 0.744 183.6 ;
    END
  END c_d[2]
  PIN c_d[30]
    DIRECTION INPUT ;
    USE SIGNAL ;
    PORT
      LAYER M5 ;
        RECT  8.928 183.516 8.952 183.6 ;
    END
  END c_d[30]
  PIN c_d[31]
    DIRECTION INPUT ;
    USE SIGNAL ;
    PORT
      LAYER M5 ;
        RECT  9.216 183.516 9.24 183.6 ;
    END
  END c_d[31]
  PIN c_d[32]
    DIRECTION INPUT ;
    USE SIGNAL ;
    PORT
      LAYER M7 ;
        RECT  9.472 183.53 9.504 183.6 ;
    END
  END c_d[32]
  PIN c_d[33]
    DIRECTION INPUT ;
    USE SIGNAL ;
    PORT
      LAYER M7 ;
        RECT  9.792 183.53 9.824 183.6 ;
    END
  END c_d[33]
  PIN c_d[34]
    DIRECTION INPUT ;
    USE SIGNAL ;
    PORT
      LAYER M7 ;
        RECT  10.112 183.53 10.144 183.6 ;
    END
  END c_d[34]
  PIN c_d[35]
    DIRECTION INPUT ;
    USE SIGNAL ;
    PORT
      LAYER M7 ;
        RECT  10.368 183.53 10.4 183.6 ;
    END
  END c_d[35]
  PIN c_d[36]
    DIRECTION INPUT ;
    USE SIGNAL ;
    PORT
      LAYER M7 ;
        RECT  10.688 183.53 10.72 183.6 ;
    END
  END c_d[36]
  PIN c_d[37]
    DIRECTION INPUT ;
    USE SIGNAL ;
    PORT
      LAYER M7 ;
        RECT  10.944 183.53 10.976 183.6 ;
    END
  END c_d[37]
  PIN c_d[38]
    DIRECTION INPUT ;
    USE SIGNAL ;
    PORT
      LAYER M7 ;
        RECT  11.264 183.53 11.296 183.6 ;
    END
  END c_d[38]
  PIN c_d[39]
    DIRECTION INPUT ;
    USE SIGNAL ;
    PORT
      LAYER M7 ;
        RECT  11.584 183.53 11.616 183.6 ;
    END
  END c_d[39]
  PIN c_d[3]
    DIRECTION INPUT ;
    USE SIGNAL ;
    PORT
      LAYER M5 ;
        RECT  1.008 183.516 1.032 183.6 ;
    END
  END c_d[3]
  PIN c_d[40]
    DIRECTION INPUT ;
    USE SIGNAL ;
    PORT
      LAYER M7 ;
        RECT  11.84 183.53 11.872 183.6 ;
    END
  END c_d[40]
  PIN c_d[41]
    DIRECTION INPUT ;
    USE SIGNAL ;
    PORT
      LAYER M7 ;
        RECT  12.16 183.53 12.192 183.6 ;
    END
  END c_d[41]
  PIN c_d[42]
    DIRECTION INPUT ;
    USE SIGNAL ;
    PORT
      LAYER M7 ;
        RECT  12.416 183.53 12.448 183.6 ;
    END
  END c_d[42]
  PIN c_d[43]
    DIRECTION INPUT ;
    USE SIGNAL ;
    PORT
      LAYER M7 ;
        RECT  12.736 183.53 12.768 183.6 ;
    END
  END c_d[43]
  PIN c_d[44]
    DIRECTION INPUT ;
    USE SIGNAL ;
    PORT
      LAYER M7 ;
        RECT  12.992 183.53 13.024 183.6 ;
    END
  END c_d[44]
  PIN c_d[45]
    DIRECTION INPUT ;
    USE SIGNAL ;
    PORT
      LAYER M7 ;
        RECT  13.312 183.53 13.344 183.6 ;
    END
  END c_d[45]
  PIN c_d[46]
    DIRECTION INPUT ;
    USE SIGNAL ;
    PORT
      LAYER M7 ;
        RECT  13.632 183.53 13.664 183.6 ;
    END
  END c_d[46]
  PIN c_d[47]
    DIRECTION INPUT ;
    USE SIGNAL ;
    PORT
      LAYER M7 ;
        RECT  13.888 183.53 13.92 183.6 ;
    END
  END c_d[47]
  PIN c_d[48]
    DIRECTION INPUT ;
    USE SIGNAL ;
    PORT
      LAYER M7 ;
        RECT  14.208 183.53 14.24 183.6 ;
    END
  END c_d[48]
  PIN c_d[49]
    DIRECTION INPUT ;
    USE SIGNAL ;
    PORT
      LAYER M7 ;
        RECT  14.464 183.53 14.496 183.6 ;
    END
  END c_d[49]
  PIN c_d[4]
    DIRECTION INPUT ;
    USE SIGNAL ;
    PORT
      LAYER M5 ;
        RECT  1.296 183.516 1.32 183.6 ;
    END
  END c_d[4]
  PIN c_d[50]
    DIRECTION INPUT ;
    USE SIGNAL ;
    PORT
      LAYER M7 ;
        RECT  14.784 183.53 14.816 183.6 ;
    END
  END c_d[50]
  PIN c_d[51]
    DIRECTION INPUT ;
    USE SIGNAL ;
    PORT
      LAYER M7 ;
        RECT  15.04 183.53 15.072 183.6 ;
    END
  END c_d[51]
  PIN c_d[52]
    DIRECTION INPUT ;
    USE SIGNAL ;
    PORT
      LAYER M7 ;
        RECT  15.36 183.53 15.392 183.6 ;
    END
  END c_d[52]
  PIN c_d[53]
    DIRECTION INPUT ;
    USE SIGNAL ;
    PORT
      LAYER M7 ;
        RECT  15.68 183.53 15.712 183.6 ;
    END
  END c_d[53]
  PIN c_d[54]
    DIRECTION INPUT ;
    USE SIGNAL ;
    PORT
      LAYER M7 ;
        RECT  15.936 183.53 15.968 183.6 ;
    END
  END c_d[54]
  PIN c_d[55]
    DIRECTION INPUT ;
    USE SIGNAL ;
    PORT
      LAYER M7 ;
        RECT  16.256 183.53 16.288 183.6 ;
    END
  END c_d[55]
  PIN c_d[56]
    DIRECTION INPUT ;
    USE SIGNAL ;
    PORT
      LAYER M7 ;
        RECT  16.512 183.53 16.544 183.6 ;
    END
  END c_d[56]
  PIN c_d[57]
    DIRECTION INPUT ;
    USE SIGNAL ;
    PORT
      LAYER M7 ;
        RECT  16.832 183.53 16.864 183.6 ;
    END
  END c_d[57]
  PIN c_d[58]
    DIRECTION INPUT ;
    USE SIGNAL ;
    PORT
      LAYER M7 ;
        RECT  17.088 183.53 17.12 183.6 ;
    END
  END c_d[58]
  PIN c_d[59]
    DIRECTION INPUT ;
    USE SIGNAL ;
    PORT
      LAYER M7 ;
        RECT  17.408 183.53 17.44 183.6 ;
    END
  END c_d[59]
  PIN c_d[5]
    DIRECTION INPUT ;
    USE SIGNAL ;
    PORT
      LAYER M5 ;
        RECT  1.584 183.516 1.608 183.6 ;
    END
  END c_d[5]
  PIN c_d[60]
    DIRECTION INPUT ;
    USE SIGNAL ;
    PORT
      LAYER M7 ;
        RECT  17.728 183.53 17.76 183.6 ;
    END
  END c_d[60]
  PIN c_d[61]
    DIRECTION INPUT ;
    USE SIGNAL ;
    PORT
      LAYER M7 ;
        RECT  17.984 183.53 18.016 183.6 ;
    END
  END c_d[61]
  PIN c_d[62]
    DIRECTION INPUT ;
    USE SIGNAL ;
    PORT
      LAYER M7 ;
        RECT  18.304 183.53 18.336 183.6 ;
    END
  END c_d[62]
  PIN c_d[63]
    DIRECTION INPUT ;
    USE SIGNAL ;
    PORT
      LAYER M7 ;
        RECT  18.56 183.53 18.592 183.6 ;
    END
  END c_d[63]
  PIN c_d[64]
    DIRECTION INPUT ;
    USE SIGNAL ;
    PORT
      LAYER M5 ;
        RECT  18.864 183.516 18.888 183.6 ;
    END
  END c_d[64]
  PIN c_d[65]
    DIRECTION INPUT ;
    USE SIGNAL ;
    PORT
      LAYER M5 ;
        RECT  19.152 183.516 19.176 183.6 ;
    END
  END c_d[65]
  PIN c_d[66]
    DIRECTION INPUT ;
    USE SIGNAL ;
    PORT
      LAYER M5 ;
        RECT  19.488 183.516 19.512 183.6 ;
    END
  END c_d[66]
  PIN c_d[67]
    DIRECTION INPUT ;
    USE SIGNAL ;
    PORT
      LAYER M5 ;
        RECT  19.776 183.516 19.8 183.6 ;
    END
  END c_d[67]
  PIN c_d[68]
    DIRECTION INPUT ;
    USE SIGNAL ;
    PORT
      LAYER M5 ;
        RECT  20.064 183.516 20.088 183.6 ;
    END
  END c_d[68]
  PIN c_d[69]
    DIRECTION INPUT ;
    USE SIGNAL ;
    PORT
      LAYER M5 ;
        RECT  20.352 183.516 20.376 183.6 ;
    END
  END c_d[69]
  PIN c_d[6]
    DIRECTION INPUT ;
    USE SIGNAL ;
    PORT
      LAYER M5 ;
        RECT  1.872 183.516 1.896 183.6 ;
    END
  END c_d[6]
  PIN c_d[70]
    DIRECTION INPUT ;
    USE SIGNAL ;
    PORT
      LAYER M5 ;
        RECT  20.64 183.516 20.664 183.6 ;
    END
  END c_d[70]
  PIN c_d[71]
    DIRECTION INPUT ;
    USE SIGNAL ;
    PORT
      LAYER M5 ;
        RECT  20.928 183.516 20.952 183.6 ;
    END
  END c_d[71]
  PIN c_d[72]
    DIRECTION INPUT ;
    USE SIGNAL ;
    PORT
      LAYER M5 ;
        RECT  21.216 183.516 21.24 183.6 ;
    END
  END c_d[72]
  PIN c_d[73]
    DIRECTION INPUT ;
    USE SIGNAL ;
    PORT
      LAYER M5 ;
        RECT  21.504 183.516 21.528 183.6 ;
    END
  END c_d[73]
  PIN c_d[74]
    DIRECTION INPUT ;
    USE SIGNAL ;
    PORT
      LAYER M5 ;
        RECT  21.792 183.516 21.816 183.6 ;
    END
  END c_d[74]
  PIN c_d[75]
    DIRECTION INPUT ;
    USE SIGNAL ;
    PORT
      LAYER M5 ;
        RECT  22.08 183.516 22.104 183.6 ;
    END
  END c_d[75]
  PIN c_d[76]
    DIRECTION INPUT ;
    USE SIGNAL ;
    PORT
      LAYER M5 ;
        RECT  22.416 183.516 22.44 183.6 ;
    END
  END c_d[76]
  PIN c_d[77]
    DIRECTION INPUT ;
    USE SIGNAL ;
    PORT
      LAYER M5 ;
        RECT  22.704 183.516 22.728 183.6 ;
    END
  END c_d[77]
  PIN c_d[78]
    DIRECTION INPUT ;
    USE SIGNAL ;
    PORT
      LAYER M5 ;
        RECT  22.992 183.516 23.016 183.6 ;
    END
  END c_d[78]
  PIN c_d[79]
    DIRECTION INPUT ;
    USE SIGNAL ;
    PORT
      LAYER M5 ;
        RECT  23.28 183.516 23.304 183.6 ;
    END
  END c_d[79]
  PIN c_d[7]
    DIRECTION INPUT ;
    USE SIGNAL ;
    PORT
      LAYER M5 ;
        RECT  2.208 183.516 2.232 183.6 ;
    END
  END c_d[7]
  PIN c_d[80]
    DIRECTION INPUT ;
    USE SIGNAL ;
    PORT
      LAYER M5 ;
        RECT  23.568 183.516 23.592 183.6 ;
    END
  END c_d[80]
  PIN c_d[81]
    DIRECTION INPUT ;
    USE SIGNAL ;
    PORT
      LAYER M5 ;
        RECT  23.856 183.516 23.88 183.6 ;
    END
  END c_d[81]
  PIN c_d[82]
    DIRECTION INPUT ;
    USE SIGNAL ;
    PORT
      LAYER M5 ;
        RECT  24.144 183.516 24.168 183.6 ;
    END
  END c_d[82]
  PIN c_d[83]
    DIRECTION INPUT ;
    USE SIGNAL ;
    PORT
      LAYER M5 ;
        RECT  24.432 183.516 24.456 183.6 ;
    END
  END c_d[83]
  PIN c_d[84]
    DIRECTION INPUT ;
    USE SIGNAL ;
    PORT
      LAYER M5 ;
        RECT  24.72 183.516 24.744 183.6 ;
    END
  END c_d[84]
  PIN c_d[85]
    DIRECTION INPUT ;
    USE SIGNAL ;
    PORT
      LAYER M5 ;
        RECT  25.008 183.516 25.032 183.6 ;
    END
  END c_d[85]
  PIN c_d[86]
    DIRECTION INPUT ;
    USE SIGNAL ;
    PORT
      LAYER M5 ;
        RECT  25.344 183.516 25.368 183.6 ;
    END
  END c_d[86]
  PIN c_d[87]
    DIRECTION INPUT ;
    USE SIGNAL ;
    PORT
      LAYER M5 ;
        RECT  25.632 183.516 25.656 183.6 ;
    END
  END c_d[87]
  PIN c_d[88]
    DIRECTION INPUT ;
    USE SIGNAL ;
    PORT
      LAYER M5 ;
        RECT  25.92 183.516 25.944 183.6 ;
    END
  END c_d[88]
  PIN c_d[89]
    DIRECTION INPUT ;
    USE SIGNAL ;
    PORT
      LAYER M5 ;
        RECT  26.208 183.516 26.232 183.6 ;
    END
  END c_d[89]
  PIN c_d[8]
    DIRECTION INPUT ;
    USE SIGNAL ;
    PORT
      LAYER M5 ;
        RECT  2.496 183.516 2.52 183.6 ;
    END
  END c_d[8]
  PIN c_d[90]
    DIRECTION INPUT ;
    USE SIGNAL ;
    PORT
      LAYER M5 ;
        RECT  26.496 183.516 26.52 183.6 ;
    END
  END c_d[90]
  PIN c_d[91]
    DIRECTION INPUT ;
    USE SIGNAL ;
    PORT
      LAYER M5 ;
        RECT  26.784 183.516 26.808 183.6 ;
    END
  END c_d[91]
  PIN c_d[92]
    DIRECTION INPUT ;
    USE SIGNAL ;
    PORT
      LAYER M5 ;
        RECT  27.072 183.516 27.096 183.6 ;
    END
  END c_d[92]
  PIN c_d[93]
    DIRECTION INPUT ;
    USE SIGNAL ;
    PORT
      LAYER M5 ;
        RECT  27.36 183.516 27.384 183.6 ;
    END
  END c_d[93]
  PIN c_d[94]
    DIRECTION INPUT ;
    USE SIGNAL ;
    PORT
      LAYER M5 ;
        RECT  27.648 183.516 27.672 183.6 ;
    END
  END c_d[94]
  PIN c_d[95]
    DIRECTION INPUT ;
    USE SIGNAL ;
    PORT
      LAYER M5 ;
        RECT  27.936 183.516 27.96 183.6 ;
    END
  END c_d[95]
  PIN c_d[96]
    DIRECTION INPUT ;
    USE SIGNAL ;
    PORT
      LAYER M7 ;
        RECT  28.224 183.53 28.256 183.6 ;
    END
  END c_d[96]
  PIN c_d[97]
    DIRECTION INPUT ;
    USE SIGNAL ;
    PORT
      LAYER M7 ;
        RECT  28.544 183.53 28.576 183.6 ;
    END
  END c_d[97]
  PIN c_d[98]
    DIRECTION INPUT ;
    USE SIGNAL ;
    PORT
      LAYER M7 ;
        RECT  28.864 183.53 28.896 183.6 ;
    END
  END c_d[98]
  PIN c_d[99]
    DIRECTION INPUT ;
    USE SIGNAL ;
    PORT
      LAYER M7 ;
        RECT  29.12 183.53 29.152 183.6 ;
    END
  END c_d[99]
  PIN c_d[9]
    DIRECTION INPUT ;
    USE SIGNAL ;
    PORT
      LAYER M5 ;
        RECT  2.784 183.516 2.808 183.6 ;
    END
  END c_d[9]
  PIN c_lane[0]
    DIRECTION INPUT ;
    USE SIGNAL ;
    PORT
      LAYER M5 ;
        RECT  75.12 183.516 75.144 183.6 ;
    END
  END c_lane[0]
  PIN c_lane[1]
    DIRECTION INPUT ;
    USE SIGNAL ;
    PORT
      LAYER M5 ;
        RECT  75.408 183.516 75.432 183.6 ;
    END
  END c_lane[1]
  PIN c_lane[2]
    DIRECTION INPUT ;
    USE SIGNAL ;
    PORT
      LAYER M5 ;
        RECT  75.696 183.516 75.72 183.6 ;
    END
  END c_lane[2]
  PIN c_sec[0]
    DIRECTION INPUT ;
    USE SIGNAL ;
    PORT
      LAYER M5 ;
        RECT  75.984 183.516 76.008 183.6 ;
    END
  END c_sec[0]
  PIN c_sec[10]
    DIRECTION INPUT ;
    USE SIGNAL ;
    PORT
      LAYER M5 ;
        RECT  78.912 183.516 78.936 183.6 ;
    END
  END c_sec[10]
  PIN c_sec[11]
    DIRECTION INPUT ;
    USE SIGNAL ;
    PORT
      LAYER M5 ;
        RECT  79.2 183.516 79.224 183.6 ;
    END
  END c_sec[11]
  PIN c_sec[12]
    DIRECTION INPUT ;
    USE SIGNAL ;
    PORT
      LAYER M5 ;
        RECT  79.488 183.516 79.512 183.6 ;
    END
  END c_sec[12]
  PIN c_sec[13]
    DIRECTION INPUT ;
    USE SIGNAL ;
    PORT
      LAYER M5 ;
        RECT  79.776 183.516 79.8 183.6 ;
    END
  END c_sec[13]
  PIN c_sec[14]
    DIRECTION INPUT ;
    USE SIGNAL ;
    PORT
      LAYER M5 ;
        RECT  80.112 183.516 80.136 183.6 ;
    END
  END c_sec[14]
  PIN c_sec[15]
    DIRECTION INPUT ;
    USE SIGNAL ;
    PORT
      LAYER M5 ;
        RECT  80.4 183.516 80.424 183.6 ;
    END
  END c_sec[15]
  PIN c_sec[16]
    DIRECTION INPUT ;
    USE SIGNAL ;
    PORT
      LAYER M5 ;
        RECT  80.688 183.516 80.712 183.6 ;
    END
  END c_sec[16]
  PIN c_sec[17]
    DIRECTION INPUT ;
    USE SIGNAL ;
    PORT
      LAYER M5 ;
        RECT  80.976 183.516 81 183.6 ;
    END
  END c_sec[17]
  PIN c_sec[18]
    DIRECTION INPUT ;
    USE SIGNAL ;
    PORT
      LAYER M5 ;
        RECT  81.264 183.516 81.288 183.6 ;
    END
  END c_sec[18]
  PIN c_sec[19]
    DIRECTION INPUT ;
    USE SIGNAL ;
    PORT
      LAYER M5 ;
        RECT  81.552 183.516 81.576 183.6 ;
    END
  END c_sec[19]
  PIN c_sec[1]
    DIRECTION INPUT ;
    USE SIGNAL ;
    PORT
      LAYER M5 ;
        RECT  76.272 183.516 76.296 183.6 ;
    END
  END c_sec[1]
  PIN c_sec[20]
    DIRECTION INPUT ;
    USE SIGNAL ;
    PORT
      LAYER M5 ;
        RECT  81.84 183.516 81.864 183.6 ;
    END
  END c_sec[20]
  PIN c_sec[21]
    DIRECTION INPUT ;
    USE SIGNAL ;
    PORT
      LAYER M5 ;
        RECT  82.128 183.516 82.152 183.6 ;
    END
  END c_sec[21]
  PIN c_sec[22]
    DIRECTION INPUT ;
    USE SIGNAL ;
    PORT
      LAYER M5 ;
        RECT  82.416 183.516 82.44 183.6 ;
    END
  END c_sec[22]
  PIN c_sec[23]
    DIRECTION INPUT ;
    USE SIGNAL ;
    PORT
      LAYER M5 ;
        RECT  82.704 183.516 82.728 183.6 ;
    END
  END c_sec[23]
  PIN c_sec[2]
    DIRECTION INPUT ;
    USE SIGNAL ;
    PORT
      LAYER M5 ;
        RECT  76.56 183.516 76.584 183.6 ;
    END
  END c_sec[2]
  PIN c_sec[3]
    DIRECTION INPUT ;
    USE SIGNAL ;
    PORT
      LAYER M5 ;
        RECT  76.848 183.516 76.872 183.6 ;
    END
  END c_sec[3]
  PIN c_sec[4]
    DIRECTION INPUT ;
    USE SIGNAL ;
    PORT
      LAYER M5 ;
        RECT  77.184 183.516 77.208 183.6 ;
    END
  END c_sec[4]
  PIN c_sec[5]
    DIRECTION INPUT ;
    USE SIGNAL ;
    PORT
      LAYER M5 ;
        RECT  77.472 183.516 77.496 183.6 ;
    END
  END c_sec[5]
  PIN c_sec[6]
    DIRECTION INPUT ;
    USE SIGNAL ;
    PORT
      LAYER M5 ;
        RECT  77.76 183.516 77.784 183.6 ;
    END
  END c_sec[6]
  PIN c_sec[7]
    DIRECTION INPUT ;
    USE SIGNAL ;
    PORT
      LAYER M5 ;
        RECT  78.048 183.516 78.072 183.6 ;
    END
  END c_sec[7]
  PIN c_sec[8]
    DIRECTION INPUT ;
    USE SIGNAL ;
    PORT
      LAYER M5 ;
        RECT  78.336 183.516 78.36 183.6 ;
    END
  END c_sec[8]
  PIN c_sec[9]
    DIRECTION INPUT ;
    USE SIGNAL ;
    PORT
      LAYER M5 ;
        RECT  78.624 183.516 78.648 183.6 ;
    END
  END c_sec[9]
  PIN c_tag[0]
    DIRECTION INPUT ;
    USE SIGNAL ;
    PORT
      LAYER M5 ;
        RECT  83.04 183.516 83.064 183.6 ;
    END
  END c_tag[0]
  PIN c_tag[1]
    DIRECTION INPUT ;
    USE SIGNAL ;
    PORT
      LAYER M5 ;
        RECT  83.328 183.516 83.352 183.6 ;
    END
  END c_tag[1]
  PIN c_tag[2]
    DIRECTION INPUT ;
    USE SIGNAL ;
    PORT
      LAYER M5 ;
        RECT  83.616 183.516 83.64 183.6 ;
    END
  END c_tag[2]
  PIN c_tag[3]
    DIRECTION INPUT ;
    USE SIGNAL ;
    PORT
      LAYER M5 ;
        RECT  83.904 183.516 83.928 183.6 ;
    END
  END c_tag[3]
  PIN c_tag[4]
    DIRECTION INPUT ;
    USE SIGNAL ;
    PORT
      LAYER M5 ;
        RECT  84.192 183.516 84.216 183.6 ;
    END
  END c_tag[4]
  PIN c_tag[5]
    DIRECTION INPUT ;
    USE SIGNAL ;
    PORT
      LAYER M7 ;
        RECT  84.48 183.53 84.512 183.6 ;
    END
  END c_tag[5]
  PIN c_tag[6]
    DIRECTION INPUT ;
    USE SIGNAL ;
    PORT
      LAYER M7 ;
        RECT  84.8 183.53 84.832 183.6 ;
    END
  END c_tag[6]
  PIN c_tag[7]
    DIRECTION INPUT ;
    USE SIGNAL ;
    PORT
      LAYER M7 ;
        RECT  85.056 183.53 85.088 183.6 ;
    END
  END c_tag[7]
  PIN c_tag[8]
    DIRECTION INPUT ;
    USE SIGNAL ;
    PORT
      LAYER M7 ;
        RECT  85.376 183.53 85.408 183.6 ;
    END
  END c_tag[8]
  PIN c_v
    DIRECTION INPUT ;
    USE SIGNAL ;
    PORT
      LAYER M7 ;
        RECT  85.632 183.53 85.664 183.6 ;
    END
  END c_v
  PIN clk
    DIRECTION INPUT ;
    USE SIGNAL ;
    PORT
      LAYER M4 ;
        RECT  86.316 18.336 86.4 18.36 ;
    END
  END clk
  PIN dn_bad
    DIRECTION INPUT ;
    USE SIGNAL ;
    PORT
      LAYER M5 ;
        RECT  0.144 0 0.168 0.084 ;
    END
  END dn_bad
  PIN dn_v
    DIRECTION INPUT ;
    USE SIGNAL ;
    PORT
      LAYER M5 ;
        RECT  0.432 0 0.456 0.084 ;
    END
  END dn_v
  PIN dp_bad
    DIRECTION OUTPUT ;
    USE SIGNAL ;
    PORT
      LAYER M7 ;
        RECT  85.952 183.53 85.984 183.6 ;
    END
  END dp_bad
  PIN dp_v
    DIRECTION OUTPUT ;
    USE SIGNAL ;
    PORT
      LAYER M7 ;
        RECT  86.208 183.53 86.24 183.6 ;
    END
  END dp_v
  PIN lane[0]
    DIRECTION INPUT ;
    USE SIGNAL ;
    PORT
      LAYER M4 ;
        RECT  86.316 55.056 86.4 55.08 ;
    END
  END lane[0]
  PIN lane[1]
    DIRECTION INPUT ;
    USE SIGNAL ;
    PORT
      LAYER M4 ;
        RECT  86.316 91.776 86.4 91.8 ;
    END
  END lane[1]
  PIN lane[2]
    DIRECTION INPUT ;
    USE SIGNAL ;
    PORT
      LAYER M4 ;
        RECT  86.316 128.496 86.4 128.52 ;
    END
  END lane[2]
  PIN n_d[0]
    DIRECTION OUTPUT ;
    USE SIGNAL ;
    PORT
      LAYER M5 ;
        RECT  0.72 0 0.744 0.084 ;
    END
  END n_d[0]
  PIN n_d[100]
    DIRECTION OUTPUT ;
    USE SIGNAL ;
    PORT
      LAYER M7 ;
        RECT  30.016 0 30.048 0.07 ;
    END
  END n_d[100]
  PIN n_d[101]
    DIRECTION OUTPUT ;
    USE SIGNAL ;
    PORT
      LAYER M7 ;
        RECT  30.272 0 30.304 0.07 ;
    END
  END n_d[101]
  PIN n_d[102]
    DIRECTION OUTPUT ;
    USE SIGNAL ;
    PORT
      LAYER M7 ;
        RECT  30.592 0 30.624 0.07 ;
    END
  END n_d[102]
  PIN n_d[103]
    DIRECTION OUTPUT ;
    USE SIGNAL ;
    PORT
      LAYER M7 ;
        RECT  30.912 0 30.944 0.07 ;
    END
  END n_d[103]
  PIN n_d[104]
    DIRECTION OUTPUT ;
    USE SIGNAL ;
    PORT
      LAYER M7 ;
        RECT  31.168 0 31.2 0.07 ;
    END
  END n_d[104]
  PIN n_d[105]
    DIRECTION OUTPUT ;
    USE SIGNAL ;
    PORT
      LAYER M7 ;
        RECT  31.488 0 31.52 0.07 ;
    END
  END n_d[105]
  PIN n_d[106]
    DIRECTION OUTPUT ;
    USE SIGNAL ;
    PORT
      LAYER M7 ;
        RECT  31.744 0 31.776 0.07 ;
    END
  END n_d[106]
  PIN n_d[107]
    DIRECTION OUTPUT ;
    USE SIGNAL ;
    PORT
      LAYER M7 ;
        RECT  32.064 0 32.096 0.07 ;
    END
  END n_d[107]
  PIN n_d[108]
    DIRECTION OUTPUT ;
    USE SIGNAL ;
    PORT
      LAYER M7 ;
        RECT  32.32 0 32.352 0.07 ;
    END
  END n_d[108]
  PIN n_d[109]
    DIRECTION OUTPUT ;
    USE SIGNAL ;
    PORT
      LAYER M7 ;
        RECT  32.64 0 32.672 0.07 ;
    END
  END n_d[109]
  PIN n_d[10]
    DIRECTION OUTPUT ;
    USE SIGNAL ;
    PORT
      LAYER M5 ;
        RECT  3.648 0 3.672 0.084 ;
    END
  END n_d[10]
  PIN n_d[110]
    DIRECTION OUTPUT ;
    USE SIGNAL ;
    PORT
      LAYER M7 ;
        RECT  32.96 0 32.992 0.07 ;
    END
  END n_d[110]
  PIN n_d[111]
    DIRECTION OUTPUT ;
    USE SIGNAL ;
    PORT
      LAYER M7 ;
        RECT  33.216 0 33.248 0.07 ;
    END
  END n_d[111]
  PIN n_d[112]
    DIRECTION OUTPUT ;
    USE SIGNAL ;
    PORT
      LAYER M7 ;
        RECT  33.536 0 33.568 0.07 ;
    END
  END n_d[112]
  PIN n_d[113]
    DIRECTION OUTPUT ;
    USE SIGNAL ;
    PORT
      LAYER M7 ;
        RECT  33.792 0 33.824 0.07 ;
    END
  END n_d[113]
  PIN n_d[114]
    DIRECTION OUTPUT ;
    USE SIGNAL ;
    PORT
      LAYER M7 ;
        RECT  34.112 0 34.144 0.07 ;
    END
  END n_d[114]
  PIN n_d[115]
    DIRECTION OUTPUT ;
    USE SIGNAL ;
    PORT
      LAYER M7 ;
        RECT  34.368 0 34.4 0.07 ;
    END
  END n_d[115]
  PIN n_d[116]
    DIRECTION OUTPUT ;
    USE SIGNAL ;
    PORT
      LAYER M7 ;
        RECT  34.688 0 34.72 0.07 ;
    END
  END n_d[116]
  PIN n_d[117]
    DIRECTION OUTPUT ;
    USE SIGNAL ;
    PORT
      LAYER M7 ;
        RECT  35.008 0 35.04 0.07 ;
    END
  END n_d[117]
  PIN n_d[118]
    DIRECTION OUTPUT ;
    USE SIGNAL ;
    PORT
      LAYER M7 ;
        RECT  35.264 0 35.296 0.07 ;
    END
  END n_d[118]
  PIN n_d[119]
    DIRECTION OUTPUT ;
    USE SIGNAL ;
    PORT
      LAYER M7 ;
        RECT  35.584 0 35.616 0.07 ;
    END
  END n_d[119]
  PIN n_d[11]
    DIRECTION OUTPUT ;
    USE SIGNAL ;
    PORT
      LAYER M5 ;
        RECT  3.936 0 3.96 0.084 ;
    END
  END n_d[11]
  PIN n_d[120]
    DIRECTION OUTPUT ;
    USE SIGNAL ;
    PORT
      LAYER M7 ;
        RECT  35.84 0 35.872 0.07 ;
    END
  END n_d[120]
  PIN n_d[121]
    DIRECTION OUTPUT ;
    USE SIGNAL ;
    PORT
      LAYER M7 ;
        RECT  36.16 0 36.192 0.07 ;
    END
  END n_d[121]
  PIN n_d[122]
    DIRECTION OUTPUT ;
    USE SIGNAL ;
    PORT
      LAYER M7 ;
        RECT  36.48 0 36.512 0.07 ;
    END
  END n_d[122]
  PIN n_d[123]
    DIRECTION OUTPUT ;
    USE SIGNAL ;
    PORT
      LAYER M7 ;
        RECT  36.736 0 36.768 0.07 ;
    END
  END n_d[123]
  PIN n_d[124]
    DIRECTION OUTPUT ;
    USE SIGNAL ;
    PORT
      LAYER M7 ;
        RECT  37.056 0 37.088 0.07 ;
    END
  END n_d[124]
  PIN n_d[125]
    DIRECTION OUTPUT ;
    USE SIGNAL ;
    PORT
      LAYER M7 ;
        RECT  37.312 0 37.344 0.07 ;
    END
  END n_d[125]
  PIN n_d[126]
    DIRECTION OUTPUT ;
    USE SIGNAL ;
    PORT
      LAYER M5 ;
        RECT  37.632 0 37.656 0.084 ;
    END
  END n_d[126]
  PIN n_d[127]
    DIRECTION OUTPUT ;
    USE SIGNAL ;
    PORT
      LAYER M5 ;
        RECT  37.92 0 37.944 0.084 ;
    END
  END n_d[127]
  PIN n_d[128]
    DIRECTION OUTPUT ;
    USE SIGNAL ;
    PORT
      LAYER M5 ;
        RECT  38.208 0 38.232 0.084 ;
    END
  END n_d[128]
  PIN n_d[129]
    DIRECTION OUTPUT ;
    USE SIGNAL ;
    PORT
      LAYER M5 ;
        RECT  38.496 0 38.52 0.084 ;
    END
  END n_d[129]
  PIN n_d[12]
    DIRECTION OUTPUT ;
    USE SIGNAL ;
    PORT
      LAYER M5 ;
        RECT  4.224 0 4.248 0.084 ;
    END
  END n_d[12]
  PIN n_d[130]
    DIRECTION OUTPUT ;
    USE SIGNAL ;
    PORT
      LAYER M5 ;
        RECT  38.784 0 38.808 0.084 ;
    END
  END n_d[130]
  PIN n_d[131]
    DIRECTION OUTPUT ;
    USE SIGNAL ;
    PORT
      LAYER M5 ;
        RECT  39.072 0 39.096 0.084 ;
    END
  END n_d[131]
  PIN n_d[132]
    DIRECTION OUTPUT ;
    USE SIGNAL ;
    PORT
      LAYER M5 ;
        RECT  39.36 0 39.384 0.084 ;
    END
  END n_d[132]
  PIN n_d[133]
    DIRECTION OUTPUT ;
    USE SIGNAL ;
    PORT
      LAYER M5 ;
        RECT  39.696 0 39.72 0.084 ;
    END
  END n_d[133]
  PIN n_d[134]
    DIRECTION OUTPUT ;
    USE SIGNAL ;
    PORT
      LAYER M5 ;
        RECT  39.984 0 40.008 0.084 ;
    END
  END n_d[134]
  PIN n_d[135]
    DIRECTION OUTPUT ;
    USE SIGNAL ;
    PORT
      LAYER M5 ;
        RECT  40.272 0 40.296 0.084 ;
    END
  END n_d[135]
  PIN n_d[136]
    DIRECTION OUTPUT ;
    USE SIGNAL ;
    PORT
      LAYER M5 ;
        RECT  40.56 0 40.584 0.084 ;
    END
  END n_d[136]
  PIN n_d[137]
    DIRECTION OUTPUT ;
    USE SIGNAL ;
    PORT
      LAYER M5 ;
        RECT  40.848 0 40.872 0.084 ;
    END
  END n_d[137]
  PIN n_d[138]
    DIRECTION OUTPUT ;
    USE SIGNAL ;
    PORT
      LAYER M5 ;
        RECT  41.136 0 41.16 0.084 ;
    END
  END n_d[138]
  PIN n_d[139]
    DIRECTION OUTPUT ;
    USE SIGNAL ;
    PORT
      LAYER M5 ;
        RECT  41.424 0 41.448 0.084 ;
    END
  END n_d[139]
  PIN n_d[13]
    DIRECTION OUTPUT ;
    USE SIGNAL ;
    PORT
      LAYER M5 ;
        RECT  4.512 0 4.536 0.084 ;
    END
  END n_d[13]
  PIN n_d[140]
    DIRECTION OUTPUT ;
    USE SIGNAL ;
    PORT
      LAYER M5 ;
        RECT  41.712 0 41.736 0.084 ;
    END
  END n_d[140]
  PIN n_d[141]
    DIRECTION OUTPUT ;
    USE SIGNAL ;
    PORT
      LAYER M5 ;
        RECT  42 0 42.024 0.084 ;
    END
  END n_d[141]
  PIN n_d[142]
    DIRECTION OUTPUT ;
    USE SIGNAL ;
    PORT
      LAYER M5 ;
        RECT  42.288 0 42.312 0.084 ;
    END
  END n_d[142]
  PIN n_d[143]
    DIRECTION OUTPUT ;
    USE SIGNAL ;
    PORT
      LAYER M5 ;
        RECT  42.624 0 42.648 0.084 ;
    END
  END n_d[143]
  PIN n_d[144]
    DIRECTION OUTPUT ;
    USE SIGNAL ;
    PORT
      LAYER M5 ;
        RECT  42.912 0 42.936 0.084 ;
    END
  END n_d[144]
  PIN n_d[145]
    DIRECTION OUTPUT ;
    USE SIGNAL ;
    PORT
      LAYER M5 ;
        RECT  43.2 0 43.224 0.084 ;
    END
  END n_d[145]
  PIN n_d[146]
    DIRECTION OUTPUT ;
    USE SIGNAL ;
    PORT
      LAYER M5 ;
        RECT  43.488 0 43.512 0.084 ;
    END
  END n_d[146]
  PIN n_d[147]
    DIRECTION OUTPUT ;
    USE SIGNAL ;
    PORT
      LAYER M5 ;
        RECT  43.776 0 43.8 0.084 ;
    END
  END n_d[147]
  PIN n_d[148]
    DIRECTION OUTPUT ;
    USE SIGNAL ;
    PORT
      LAYER M5 ;
        RECT  44.064 0 44.088 0.084 ;
    END
  END n_d[148]
  PIN n_d[149]
    DIRECTION OUTPUT ;
    USE SIGNAL ;
    PORT
      LAYER M5 ;
        RECT  44.352 0 44.376 0.084 ;
    END
  END n_d[149]
  PIN n_d[14]
    DIRECTION OUTPUT ;
    USE SIGNAL ;
    PORT
      LAYER M5 ;
        RECT  4.8 0 4.824 0.084 ;
    END
  END n_d[14]
  PIN n_d[150]
    DIRECTION OUTPUT ;
    USE SIGNAL ;
    PORT
      LAYER M5 ;
        RECT  44.64 0 44.664 0.084 ;
    END
  END n_d[150]
  PIN n_d[151]
    DIRECTION OUTPUT ;
    USE SIGNAL ;
    PORT
      LAYER M5 ;
        RECT  44.928 0 44.952 0.084 ;
    END
  END n_d[151]
  PIN n_d[152]
    DIRECTION OUTPUT ;
    USE SIGNAL ;
    PORT
      LAYER M5 ;
        RECT  45.216 0 45.24 0.084 ;
    END
  END n_d[152]
  PIN n_d[153]
    DIRECTION OUTPUT ;
    USE SIGNAL ;
    PORT
      LAYER M5 ;
        RECT  45.552 0 45.576 0.084 ;
    END
  END n_d[153]
  PIN n_d[154]
    DIRECTION OUTPUT ;
    USE SIGNAL ;
    PORT
      LAYER M5 ;
        RECT  45.84 0 45.864 0.084 ;
    END
  END n_d[154]
  PIN n_d[155]
    DIRECTION OUTPUT ;
    USE SIGNAL ;
    PORT
      LAYER M5 ;
        RECT  46.128 0 46.152 0.084 ;
    END
  END n_d[155]
  PIN n_d[156]
    DIRECTION OUTPUT ;
    USE SIGNAL ;
    PORT
      LAYER M5 ;
        RECT  46.416 0 46.44 0.084 ;
    END
  END n_d[156]
  PIN n_d[157]
    DIRECTION OUTPUT ;
    USE SIGNAL ;
    PORT
      LAYER M5 ;
        RECT  46.704 0 46.728 0.084 ;
    END
  END n_d[157]
  PIN n_d[158]
    DIRECTION OUTPUT ;
    USE SIGNAL ;
    PORT
      LAYER M7 ;
        RECT  46.976 0 47.008 0.07 ;
    END
  END n_d[158]
  PIN n_d[159]
    DIRECTION OUTPUT ;
    USE SIGNAL ;
    PORT
      LAYER M7 ;
        RECT  47.296 0 47.328 0.07 ;
    END
  END n_d[159]
  PIN n_d[15]
    DIRECTION OUTPUT ;
    USE SIGNAL ;
    PORT
      LAYER M5 ;
        RECT  5.136 0 5.16 0.084 ;
    END
  END n_d[15]
  PIN n_d[160]
    DIRECTION OUTPUT ;
    USE SIGNAL ;
    PORT
      LAYER M7 ;
        RECT  47.552 0 47.584 0.07 ;
    END
  END n_d[160]
  PIN n_d[161]
    DIRECTION OUTPUT ;
    USE SIGNAL ;
    PORT
      LAYER M7 ;
        RECT  47.872 0 47.904 0.07 ;
    END
  END n_d[161]
  PIN n_d[162]
    DIRECTION OUTPUT ;
    USE SIGNAL ;
    PORT
      LAYER M7 ;
        RECT  48.192 0 48.224 0.07 ;
    END
  END n_d[162]
  PIN n_d[163]
    DIRECTION OUTPUT ;
    USE SIGNAL ;
    PORT
      LAYER M7 ;
        RECT  48.448 0 48.48 0.07 ;
    END
  END n_d[163]
  PIN n_d[164]
    DIRECTION OUTPUT ;
    USE SIGNAL ;
    PORT
      LAYER M7 ;
        RECT  48.768 0 48.8 0.07 ;
    END
  END n_d[164]
  PIN n_d[165]
    DIRECTION OUTPUT ;
    USE SIGNAL ;
    PORT
      LAYER M7 ;
        RECT  49.024 0 49.056 0.07 ;
    END
  END n_d[165]
  PIN n_d[166]
    DIRECTION OUTPUT ;
    USE SIGNAL ;
    PORT
      LAYER M7 ;
        RECT  49.344 0 49.376 0.07 ;
    END
  END n_d[166]
  PIN n_d[167]
    DIRECTION OUTPUT ;
    USE SIGNAL ;
    PORT
      LAYER M7 ;
        RECT  49.6 0 49.632 0.07 ;
    END
  END n_d[167]
  PIN n_d[168]
    DIRECTION OUTPUT ;
    USE SIGNAL ;
    PORT
      LAYER M7 ;
        RECT  49.92 0 49.952 0.07 ;
    END
  END n_d[168]
  PIN n_d[169]
    DIRECTION OUTPUT ;
    USE SIGNAL ;
    PORT
      LAYER M7 ;
        RECT  50.24 0 50.272 0.07 ;
    END
  END n_d[169]
  PIN n_d[16]
    DIRECTION OUTPUT ;
    USE SIGNAL ;
    PORT
      LAYER M5 ;
        RECT  5.424 0 5.448 0.084 ;
    END
  END n_d[16]
  PIN n_d[170]
    DIRECTION OUTPUT ;
    USE SIGNAL ;
    PORT
      LAYER M7 ;
        RECT  50.496 0 50.528 0.07 ;
    END
  END n_d[170]
  PIN n_d[171]
    DIRECTION OUTPUT ;
    USE SIGNAL ;
    PORT
      LAYER M7 ;
        RECT  50.816 0 50.848 0.07 ;
    END
  END n_d[171]
  PIN n_d[172]
    DIRECTION OUTPUT ;
    USE SIGNAL ;
    PORT
      LAYER M7 ;
        RECT  51.072 0 51.104 0.07 ;
    END
  END n_d[172]
  PIN n_d[173]
    DIRECTION OUTPUT ;
    USE SIGNAL ;
    PORT
      LAYER M7 ;
        RECT  51.392 0 51.424 0.07 ;
    END
  END n_d[173]
  PIN n_d[174]
    DIRECTION OUTPUT ;
    USE SIGNAL ;
    PORT
      LAYER M7 ;
        RECT  51.648 0 51.68 0.07 ;
    END
  END n_d[174]
  PIN n_d[175]
    DIRECTION OUTPUT ;
    USE SIGNAL ;
    PORT
      LAYER M7 ;
        RECT  51.968 0 52 0.07 ;
    END
  END n_d[175]
  PIN n_d[176]
    DIRECTION OUTPUT ;
    USE SIGNAL ;
    PORT
      LAYER M7 ;
        RECT  52.288 0 52.32 0.07 ;
    END
  END n_d[176]
  PIN n_d[177]
    DIRECTION OUTPUT ;
    USE SIGNAL ;
    PORT
      LAYER M7 ;
        RECT  52.544 0 52.576 0.07 ;
    END
  END n_d[177]
  PIN n_d[178]
    DIRECTION OUTPUT ;
    USE SIGNAL ;
    PORT
      LAYER M7 ;
        RECT  52.864 0 52.896 0.07 ;
    END
  END n_d[178]
  PIN n_d[179]
    DIRECTION OUTPUT ;
    USE SIGNAL ;
    PORT
      LAYER M7 ;
        RECT  53.12 0 53.152 0.07 ;
    END
  END n_d[179]
  PIN n_d[17]
    DIRECTION OUTPUT ;
    USE SIGNAL ;
    PORT
      LAYER M5 ;
        RECT  5.712 0 5.736 0.084 ;
    END
  END n_d[17]
  PIN n_d[180]
    DIRECTION OUTPUT ;
    USE SIGNAL ;
    PORT
      LAYER M7 ;
        RECT  53.44 0 53.472 0.07 ;
    END
  END n_d[180]
  PIN n_d[181]
    DIRECTION OUTPUT ;
    USE SIGNAL ;
    PORT
      LAYER M7 ;
        RECT  53.76 0 53.792 0.07 ;
    END
  END n_d[181]
  PIN n_d[182]
    DIRECTION OUTPUT ;
    USE SIGNAL ;
    PORT
      LAYER M7 ;
        RECT  54.016 0 54.048 0.07 ;
    END
  END n_d[182]
  PIN n_d[183]
    DIRECTION OUTPUT ;
    USE SIGNAL ;
    PORT
      LAYER M7 ;
        RECT  54.336 0 54.368 0.07 ;
    END
  END n_d[183]
  PIN n_d[184]
    DIRECTION OUTPUT ;
    USE SIGNAL ;
    PORT
      LAYER M7 ;
        RECT  54.592 0 54.624 0.07 ;
    END
  END n_d[184]
  PIN n_d[185]
    DIRECTION OUTPUT ;
    USE SIGNAL ;
    PORT
      LAYER M7 ;
        RECT  54.912 0 54.944 0.07 ;
    END
  END n_d[185]
  PIN n_d[186]
    DIRECTION OUTPUT ;
    USE SIGNAL ;
    PORT
      LAYER M7 ;
        RECT  55.168 0 55.2 0.07 ;
    END
  END n_d[186]
  PIN n_d[187]
    DIRECTION OUTPUT ;
    USE SIGNAL ;
    PORT
      LAYER M7 ;
        RECT  55.488 0 55.52 0.07 ;
    END
  END n_d[187]
  PIN n_d[188]
    DIRECTION OUTPUT ;
    USE SIGNAL ;
    PORT
      LAYER M7 ;
        RECT  55.808 0 55.84 0.07 ;
    END
  END n_d[188]
  PIN n_d[189]
    DIRECTION OUTPUT ;
    USE SIGNAL ;
    PORT
      LAYER M7 ;
        RECT  56.064 0 56.096 0.07 ;
    END
  END n_d[189]
  PIN n_d[18]
    DIRECTION OUTPUT ;
    USE SIGNAL ;
    PORT
      LAYER M5 ;
        RECT  6 0 6.024 0.084 ;
    END
  END n_d[18]
  PIN n_d[190]
    DIRECTION OUTPUT ;
    USE SIGNAL ;
    PORT
      LAYER M5 ;
        RECT  56.352 0 56.376 0.084 ;
    END
  END n_d[190]
  PIN n_d[191]
    DIRECTION OUTPUT ;
    USE SIGNAL ;
    PORT
      LAYER M5 ;
        RECT  56.64 0 56.664 0.084 ;
    END
  END n_d[191]
  PIN n_d[192]
    DIRECTION OUTPUT ;
    USE SIGNAL ;
    PORT
      LAYER M5 ;
        RECT  56.976 0 57 0.084 ;
    END
  END n_d[192]
  PIN n_d[193]
    DIRECTION OUTPUT ;
    USE SIGNAL ;
    PORT
      LAYER M5 ;
        RECT  57.264 0 57.288 0.084 ;
    END
  END n_d[193]
  PIN n_d[194]
    DIRECTION OUTPUT ;
    USE SIGNAL ;
    PORT
      LAYER M5 ;
        RECT  57.552 0 57.576 0.084 ;
    END
  END n_d[194]
  PIN n_d[195]
    DIRECTION OUTPUT ;
    USE SIGNAL ;
    PORT
      LAYER M5 ;
        RECT  57.84 0 57.864 0.084 ;
    END
  END n_d[195]
  PIN n_d[196]
    DIRECTION OUTPUT ;
    USE SIGNAL ;
    PORT
      LAYER M5 ;
        RECT  58.128 0 58.152 0.084 ;
    END
  END n_d[196]
  PIN n_d[197]
    DIRECTION OUTPUT ;
    USE SIGNAL ;
    PORT
      LAYER M5 ;
        RECT  58.416 0 58.44 0.084 ;
    END
  END n_d[197]
  PIN n_d[198]
    DIRECTION OUTPUT ;
    USE SIGNAL ;
    PORT
      LAYER M5 ;
        RECT  58.704 0 58.728 0.084 ;
    END
  END n_d[198]
  PIN n_d[199]
    DIRECTION OUTPUT ;
    USE SIGNAL ;
    PORT
      LAYER M5 ;
        RECT  58.992 0 59.016 0.084 ;
    END
  END n_d[199]
  PIN n_d[19]
    DIRECTION OUTPUT ;
    USE SIGNAL ;
    PORT
      LAYER M5 ;
        RECT  6.288 0 6.312 0.084 ;
    END
  END n_d[19]
  PIN n_d[1]
    DIRECTION OUTPUT ;
    USE SIGNAL ;
    PORT
      LAYER M5 ;
        RECT  1.008 0 1.032 0.084 ;
    END
  END n_d[1]
  PIN n_d[200]
    DIRECTION OUTPUT ;
    USE SIGNAL ;
    PORT
      LAYER M5 ;
        RECT  59.28 0 59.304 0.084 ;
    END
  END n_d[200]
  PIN n_d[201]
    DIRECTION OUTPUT ;
    USE SIGNAL ;
    PORT
      LAYER M5 ;
        RECT  59.568 0 59.592 0.084 ;
    END
  END n_d[201]
  PIN n_d[202]
    DIRECTION OUTPUT ;
    USE SIGNAL ;
    PORT
      LAYER M5 ;
        RECT  59.904 0 59.928 0.084 ;
    END
  END n_d[202]
  PIN n_d[203]
    DIRECTION OUTPUT ;
    USE SIGNAL ;
    PORT
      LAYER M5 ;
        RECT  60.192 0 60.216 0.084 ;
    END
  END n_d[203]
  PIN n_d[204]
    DIRECTION OUTPUT ;
    USE SIGNAL ;
    PORT
      LAYER M5 ;
        RECT  60.48 0 60.504 0.084 ;
    END
  END n_d[204]
  PIN n_d[205]
    DIRECTION OUTPUT ;
    USE SIGNAL ;
    PORT
      LAYER M5 ;
        RECT  60.768 0 60.792 0.084 ;
    END
  END n_d[205]
  PIN n_d[206]
    DIRECTION OUTPUT ;
    USE SIGNAL ;
    PORT
      LAYER M5 ;
        RECT  61.056 0 61.08 0.084 ;
    END
  END n_d[206]
  PIN n_d[207]
    DIRECTION OUTPUT ;
    USE SIGNAL ;
    PORT
      LAYER M5 ;
        RECT  61.344 0 61.368 0.084 ;
    END
  END n_d[207]
  PIN n_d[208]
    DIRECTION OUTPUT ;
    USE SIGNAL ;
    PORT
      LAYER M5 ;
        RECT  61.632 0 61.656 0.084 ;
    END
  END n_d[208]
  PIN n_d[209]
    DIRECTION OUTPUT ;
    USE SIGNAL ;
    PORT
      LAYER M5 ;
        RECT  61.92 0 61.944 0.084 ;
    END
  END n_d[209]
  PIN n_d[20]
    DIRECTION OUTPUT ;
    USE SIGNAL ;
    PORT
      LAYER M5 ;
        RECT  6.576 0 6.6 0.084 ;
    END
  END n_d[20]
  PIN n_d[210]
    DIRECTION OUTPUT ;
    USE SIGNAL ;
    PORT
      LAYER M5 ;
        RECT  62.208 0 62.232 0.084 ;
    END
  END n_d[210]
  PIN n_d[211]
    DIRECTION OUTPUT ;
    USE SIGNAL ;
    PORT
      LAYER M5 ;
        RECT  62.496 0 62.52 0.084 ;
    END
  END n_d[211]
  PIN n_d[212]
    DIRECTION OUTPUT ;
    USE SIGNAL ;
    PORT
      LAYER M5 ;
        RECT  62.832 0 62.856 0.084 ;
    END
  END n_d[212]
  PIN n_d[213]
    DIRECTION OUTPUT ;
    USE SIGNAL ;
    PORT
      LAYER M5 ;
        RECT  63.12 0 63.144 0.084 ;
    END
  END n_d[213]
  PIN n_d[214]
    DIRECTION OUTPUT ;
    USE SIGNAL ;
    PORT
      LAYER M5 ;
        RECT  63.408 0 63.432 0.084 ;
    END
  END n_d[214]
  PIN n_d[215]
    DIRECTION OUTPUT ;
    USE SIGNAL ;
    PORT
      LAYER M5 ;
        RECT  63.696 0 63.72 0.084 ;
    END
  END n_d[215]
  PIN n_d[216]
    DIRECTION OUTPUT ;
    USE SIGNAL ;
    PORT
      LAYER M5 ;
        RECT  63.984 0 64.008 0.084 ;
    END
  END n_d[216]
  PIN n_d[217]
    DIRECTION OUTPUT ;
    USE SIGNAL ;
    PORT
      LAYER M5 ;
        RECT  64.272 0 64.296 0.084 ;
    END
  END n_d[217]
  PIN n_d[218]
    DIRECTION OUTPUT ;
    USE SIGNAL ;
    PORT
      LAYER M5 ;
        RECT  64.56 0 64.584 0.084 ;
    END
  END n_d[218]
  PIN n_d[219]
    DIRECTION OUTPUT ;
    USE SIGNAL ;
    PORT
      LAYER M5 ;
        RECT  64.848 0 64.872 0.084 ;
    END
  END n_d[219]
  PIN n_d[21]
    DIRECTION OUTPUT ;
    USE SIGNAL ;
    PORT
      LAYER M5 ;
        RECT  6.864 0 6.888 0.084 ;
    END
  END n_d[21]
  PIN n_d[220]
    DIRECTION OUTPUT ;
    USE SIGNAL ;
    PORT
      LAYER M5 ;
        RECT  65.136 0 65.16 0.084 ;
    END
  END n_d[220]
  PIN n_d[221]
    DIRECTION OUTPUT ;
    USE SIGNAL ;
    PORT
      LAYER M5 ;
        RECT  65.424 0 65.448 0.084 ;
    END
  END n_d[221]
  PIN n_d[222]
    DIRECTION OUTPUT ;
    USE SIGNAL ;
    PORT
      LAYER M7 ;
        RECT  65.728 0 65.76 0.07 ;
    END
  END n_d[222]
  PIN n_d[223]
    DIRECTION OUTPUT ;
    USE SIGNAL ;
    PORT
      LAYER M7 ;
        RECT  66.048 0 66.08 0.07 ;
    END
  END n_d[223]
  PIN n_d[224]
    DIRECTION OUTPUT ;
    USE SIGNAL ;
    PORT
      LAYER M7 ;
        RECT  66.304 0 66.336 0.07 ;
    END
  END n_d[224]
  PIN n_d[225]
    DIRECTION OUTPUT ;
    USE SIGNAL ;
    PORT
      LAYER M7 ;
        RECT  66.624 0 66.656 0.07 ;
    END
  END n_d[225]
  PIN n_d[226]
    DIRECTION OUTPUT ;
    USE SIGNAL ;
    PORT
      LAYER M7 ;
        RECT  66.88 0 66.912 0.07 ;
    END
  END n_d[226]
  PIN n_d[227]
    DIRECTION OUTPUT ;
    USE SIGNAL ;
    PORT
      LAYER M7 ;
        RECT  67.2 0 67.232 0.07 ;
    END
  END n_d[227]
  PIN n_d[228]
    DIRECTION OUTPUT ;
    USE SIGNAL ;
    PORT
      LAYER M7 ;
        RECT  67.52 0 67.552 0.07 ;
    END
  END n_d[228]
  PIN n_d[229]
    DIRECTION OUTPUT ;
    USE SIGNAL ;
    PORT
      LAYER M7 ;
        RECT  67.776 0 67.808 0.07 ;
    END
  END n_d[229]
  PIN n_d[22]
    DIRECTION OUTPUT ;
    USE SIGNAL ;
    PORT
      LAYER M5 ;
        RECT  7.152 0 7.176 0.084 ;
    END
  END n_d[22]
  PIN n_d[230]
    DIRECTION OUTPUT ;
    USE SIGNAL ;
    PORT
      LAYER M7 ;
        RECT  68.096 0 68.128 0.07 ;
    END
  END n_d[230]
  PIN n_d[231]
    DIRECTION OUTPUT ;
    USE SIGNAL ;
    PORT
      LAYER M7 ;
        RECT  68.352 0 68.384 0.07 ;
    END
  END n_d[231]
  PIN n_d[232]
    DIRECTION OUTPUT ;
    USE SIGNAL ;
    PORT
      LAYER M7 ;
        RECT  68.672 0 68.704 0.07 ;
    END
  END n_d[232]
  PIN n_d[233]
    DIRECTION OUTPUT ;
    USE SIGNAL ;
    PORT
      LAYER M7 ;
        RECT  68.928 0 68.96 0.07 ;
    END
  END n_d[233]
  PIN n_d[234]
    DIRECTION OUTPUT ;
    USE SIGNAL ;
    PORT
      LAYER M7 ;
        RECT  69.248 0 69.28 0.07 ;
    END
  END n_d[234]
  PIN n_d[235]
    DIRECTION OUTPUT ;
    USE SIGNAL ;
    PORT
      LAYER M7 ;
        RECT  69.568 0 69.6 0.07 ;
    END
  END n_d[235]
  PIN n_d[236]
    DIRECTION OUTPUT ;
    USE SIGNAL ;
    PORT
      LAYER M7 ;
        RECT  69.824 0 69.856 0.07 ;
    END
  END n_d[236]
  PIN n_d[237]
    DIRECTION OUTPUT ;
    USE SIGNAL ;
    PORT
      LAYER M7 ;
        RECT  70.144 0 70.176 0.07 ;
    END
  END n_d[237]
  PIN n_d[238]
    DIRECTION OUTPUT ;
    USE SIGNAL ;
    PORT
      LAYER M7 ;
        RECT  70.4 0 70.432 0.07 ;
    END
  END n_d[238]
  PIN n_d[239]
    DIRECTION OUTPUT ;
    USE SIGNAL ;
    PORT
      LAYER M7 ;
        RECT  70.72 0 70.752 0.07 ;
    END
  END n_d[239]
  PIN n_d[23]
    DIRECTION OUTPUT ;
    USE SIGNAL ;
    PORT
      LAYER M5 ;
        RECT  7.44 0 7.464 0.084 ;
    END
  END n_d[23]
  PIN n_d[240]
    DIRECTION OUTPUT ;
    USE SIGNAL ;
    PORT
      LAYER M7 ;
        RECT  71.04 0 71.072 0.07 ;
    END
  END n_d[240]
  PIN n_d[241]
    DIRECTION OUTPUT ;
    USE SIGNAL ;
    PORT
      LAYER M7 ;
        RECT  71.296 0 71.328 0.07 ;
    END
  END n_d[241]
  PIN n_d[242]
    DIRECTION OUTPUT ;
    USE SIGNAL ;
    PORT
      LAYER M7 ;
        RECT  71.616 0 71.648 0.07 ;
    END
  END n_d[242]
  PIN n_d[243]
    DIRECTION OUTPUT ;
    USE SIGNAL ;
    PORT
      LAYER M7 ;
        RECT  71.872 0 71.904 0.07 ;
    END
  END n_d[243]
  PIN n_d[244]
    DIRECTION OUTPUT ;
    USE SIGNAL ;
    PORT
      LAYER M7 ;
        RECT  72.192 0 72.224 0.07 ;
    END
  END n_d[244]
  PIN n_d[245]
    DIRECTION OUTPUT ;
    USE SIGNAL ;
    PORT
      LAYER M7 ;
        RECT  72.448 0 72.48 0.07 ;
    END
  END n_d[245]
  PIN n_d[246]
    DIRECTION OUTPUT ;
    USE SIGNAL ;
    PORT
      LAYER M7 ;
        RECT  72.768 0 72.8 0.07 ;
    END
  END n_d[246]
  PIN n_d[247]
    DIRECTION OUTPUT ;
    USE SIGNAL ;
    PORT
      LAYER M7 ;
        RECT  73.088 0 73.12 0.07 ;
    END
  END n_d[247]
  PIN n_d[248]
    DIRECTION OUTPUT ;
    USE SIGNAL ;
    PORT
      LAYER M7 ;
        RECT  73.344 0 73.376 0.07 ;
    END
  END n_d[248]
  PIN n_d[249]
    DIRECTION OUTPUT ;
    USE SIGNAL ;
    PORT
      LAYER M7 ;
        RECT  73.664 0 73.696 0.07 ;
    END
  END n_d[249]
  PIN n_d[24]
    DIRECTION OUTPUT ;
    USE SIGNAL ;
    PORT
      LAYER M5 ;
        RECT  7.728 0 7.752 0.084 ;
    END
  END n_d[24]
  PIN n_d[250]
    DIRECTION OUTPUT ;
    USE SIGNAL ;
    PORT
      LAYER M7 ;
        RECT  73.92 0 73.952 0.07 ;
    END
  END n_d[250]
  PIN n_d[251]
    DIRECTION OUTPUT ;
    USE SIGNAL ;
    PORT
      LAYER M7 ;
        RECT  74.24 0 74.272 0.07 ;
    END
  END n_d[251]
  PIN n_d[252]
    DIRECTION OUTPUT ;
    USE SIGNAL ;
    PORT
      LAYER M7 ;
        RECT  74.496 0 74.528 0.07 ;
    END
  END n_d[252]
  PIN n_d[253]
    DIRECTION OUTPUT ;
    USE SIGNAL ;
    PORT
      LAYER M7 ;
        RECT  74.816 0 74.848 0.07 ;
    END
  END n_d[253]
  PIN n_d[254]
    DIRECTION OUTPUT ;
    USE SIGNAL ;
    PORT
      LAYER M5 ;
        RECT  75.12 0 75.144 0.084 ;
    END
  END n_d[254]
  PIN n_d[255]
    DIRECTION OUTPUT ;
    USE SIGNAL ;
    PORT
      LAYER M5 ;
        RECT  75.408 0 75.432 0.084 ;
    END
  END n_d[255]
  PIN n_d[25]
    DIRECTION OUTPUT ;
    USE SIGNAL ;
    PORT
      LAYER M5 ;
        RECT  8.064 0 8.088 0.084 ;
    END
  END n_d[25]
  PIN n_d[26]
    DIRECTION OUTPUT ;
    USE SIGNAL ;
    PORT
      LAYER M5 ;
        RECT  8.352 0 8.376 0.084 ;
    END
  END n_d[26]
  PIN n_d[27]
    DIRECTION OUTPUT ;
    USE SIGNAL ;
    PORT
      LAYER M5 ;
        RECT  8.64 0 8.664 0.084 ;
    END
  END n_d[27]
  PIN n_d[28]
    DIRECTION OUTPUT ;
    USE SIGNAL ;
    PORT
      LAYER M5 ;
        RECT  8.928 0 8.952 0.084 ;
    END
  END n_d[28]
  PIN n_d[29]
    DIRECTION OUTPUT ;
    USE SIGNAL ;
    PORT
      LAYER M5 ;
        RECT  9.216 0 9.24 0.084 ;
    END
  END n_d[29]
  PIN n_d[2]
    DIRECTION OUTPUT ;
    USE SIGNAL ;
    PORT
      LAYER M5 ;
        RECT  1.296 0 1.32 0.084 ;
    END
  END n_d[2]
  PIN n_d[30]
    DIRECTION OUTPUT ;
    USE SIGNAL ;
    PORT
      LAYER M7 ;
        RECT  9.472 0 9.504 0.07 ;
    END
  END n_d[30]
  PIN n_d[31]
    DIRECTION OUTPUT ;
    USE SIGNAL ;
    PORT
      LAYER M7 ;
        RECT  9.792 0 9.824 0.07 ;
    END
  END n_d[31]
  PIN n_d[32]
    DIRECTION OUTPUT ;
    USE SIGNAL ;
    PORT
      LAYER M7 ;
        RECT  10.112 0 10.144 0.07 ;
    END
  END n_d[32]
  PIN n_d[33]
    DIRECTION OUTPUT ;
    USE SIGNAL ;
    PORT
      LAYER M7 ;
        RECT  10.368 0 10.4 0.07 ;
    END
  END n_d[33]
  PIN n_d[34]
    DIRECTION OUTPUT ;
    USE SIGNAL ;
    PORT
      LAYER M7 ;
        RECT  10.688 0 10.72 0.07 ;
    END
  END n_d[34]
  PIN n_d[35]
    DIRECTION OUTPUT ;
    USE SIGNAL ;
    PORT
      LAYER M7 ;
        RECT  10.944 0 10.976 0.07 ;
    END
  END n_d[35]
  PIN n_d[36]
    DIRECTION OUTPUT ;
    USE SIGNAL ;
    PORT
      LAYER M7 ;
        RECT  11.264 0 11.296 0.07 ;
    END
  END n_d[36]
  PIN n_d[37]
    DIRECTION OUTPUT ;
    USE SIGNAL ;
    PORT
      LAYER M7 ;
        RECT  11.584 0 11.616 0.07 ;
    END
  END n_d[37]
  PIN n_d[38]
    DIRECTION OUTPUT ;
    USE SIGNAL ;
    PORT
      LAYER M7 ;
        RECT  11.84 0 11.872 0.07 ;
    END
  END n_d[38]
  PIN n_d[39]
    DIRECTION OUTPUT ;
    USE SIGNAL ;
    PORT
      LAYER M7 ;
        RECT  12.16 0 12.192 0.07 ;
    END
  END n_d[39]
  PIN n_d[3]
    DIRECTION OUTPUT ;
    USE SIGNAL ;
    PORT
      LAYER M5 ;
        RECT  1.584 0 1.608 0.084 ;
    END
  END n_d[3]
  PIN n_d[40]
    DIRECTION OUTPUT ;
    USE SIGNAL ;
    PORT
      LAYER M7 ;
        RECT  12.416 0 12.448 0.07 ;
    END
  END n_d[40]
  PIN n_d[41]
    DIRECTION OUTPUT ;
    USE SIGNAL ;
    PORT
      LAYER M7 ;
        RECT  12.736 0 12.768 0.07 ;
    END
  END n_d[41]
  PIN n_d[42]
    DIRECTION OUTPUT ;
    USE SIGNAL ;
    PORT
      LAYER M7 ;
        RECT  12.992 0 13.024 0.07 ;
    END
  END n_d[42]
  PIN n_d[43]
    DIRECTION OUTPUT ;
    USE SIGNAL ;
    PORT
      LAYER M7 ;
        RECT  13.312 0 13.344 0.07 ;
    END
  END n_d[43]
  PIN n_d[44]
    DIRECTION OUTPUT ;
    USE SIGNAL ;
    PORT
      LAYER M7 ;
        RECT  13.632 0 13.664 0.07 ;
    END
  END n_d[44]
  PIN n_d[45]
    DIRECTION OUTPUT ;
    USE SIGNAL ;
    PORT
      LAYER M7 ;
        RECT  13.888 0 13.92 0.07 ;
    END
  END n_d[45]
  PIN n_d[46]
    DIRECTION OUTPUT ;
    USE SIGNAL ;
    PORT
      LAYER M7 ;
        RECT  14.208 0 14.24 0.07 ;
    END
  END n_d[46]
  PIN n_d[47]
    DIRECTION OUTPUT ;
    USE SIGNAL ;
    PORT
      LAYER M7 ;
        RECT  14.464 0 14.496 0.07 ;
    END
  END n_d[47]
  PIN n_d[48]
    DIRECTION OUTPUT ;
    USE SIGNAL ;
    PORT
      LAYER M7 ;
        RECT  14.784 0 14.816 0.07 ;
    END
  END n_d[48]
  PIN n_d[49]
    DIRECTION OUTPUT ;
    USE SIGNAL ;
    PORT
      LAYER M7 ;
        RECT  15.04 0 15.072 0.07 ;
    END
  END n_d[49]
  PIN n_d[4]
    DIRECTION OUTPUT ;
    USE SIGNAL ;
    PORT
      LAYER M5 ;
        RECT  1.872 0 1.896 0.084 ;
    END
  END n_d[4]
  PIN n_d[50]
    DIRECTION OUTPUT ;
    USE SIGNAL ;
    PORT
      LAYER M7 ;
        RECT  15.36 0 15.392 0.07 ;
    END
  END n_d[50]
  PIN n_d[51]
    DIRECTION OUTPUT ;
    USE SIGNAL ;
    PORT
      LAYER M7 ;
        RECT  15.68 0 15.712 0.07 ;
    END
  END n_d[51]
  PIN n_d[52]
    DIRECTION OUTPUT ;
    USE SIGNAL ;
    PORT
      LAYER M7 ;
        RECT  15.936 0 15.968 0.07 ;
    END
  END n_d[52]
  PIN n_d[53]
    DIRECTION OUTPUT ;
    USE SIGNAL ;
    PORT
      LAYER M7 ;
        RECT  16.256 0 16.288 0.07 ;
    END
  END n_d[53]
  PIN n_d[54]
    DIRECTION OUTPUT ;
    USE SIGNAL ;
    PORT
      LAYER M7 ;
        RECT  16.512 0 16.544 0.07 ;
    END
  END n_d[54]
  PIN n_d[55]
    DIRECTION OUTPUT ;
    USE SIGNAL ;
    PORT
      LAYER M7 ;
        RECT  16.832 0 16.864 0.07 ;
    END
  END n_d[55]
  PIN n_d[56]
    DIRECTION OUTPUT ;
    USE SIGNAL ;
    PORT
      LAYER M7 ;
        RECT  17.088 0 17.12 0.07 ;
    END
  END n_d[56]
  PIN n_d[57]
    DIRECTION OUTPUT ;
    USE SIGNAL ;
    PORT
      LAYER M7 ;
        RECT  17.408 0 17.44 0.07 ;
    END
  END n_d[57]
  PIN n_d[58]
    DIRECTION OUTPUT ;
    USE SIGNAL ;
    PORT
      LAYER M7 ;
        RECT  17.728 0 17.76 0.07 ;
    END
  END n_d[58]
  PIN n_d[59]
    DIRECTION OUTPUT ;
    USE SIGNAL ;
    PORT
      LAYER M7 ;
        RECT  17.984 0 18.016 0.07 ;
    END
  END n_d[59]
  PIN n_d[5]
    DIRECTION OUTPUT ;
    USE SIGNAL ;
    PORT
      LAYER M5 ;
        RECT  2.208 0 2.232 0.084 ;
    END
  END n_d[5]
  PIN n_d[60]
    DIRECTION OUTPUT ;
    USE SIGNAL ;
    PORT
      LAYER M7 ;
        RECT  18.304 0 18.336 0.07 ;
    END
  END n_d[60]
  PIN n_d[61]
    DIRECTION OUTPUT ;
    USE SIGNAL ;
    PORT
      LAYER M7 ;
        RECT  18.56 0 18.592 0.07 ;
    END
  END n_d[61]
  PIN n_d[62]
    DIRECTION OUTPUT ;
    USE SIGNAL ;
    PORT
      LAYER M5 ;
        RECT  18.864 0 18.888 0.084 ;
    END
  END n_d[62]
  PIN n_d[63]
    DIRECTION OUTPUT ;
    USE SIGNAL ;
    PORT
      LAYER M5 ;
        RECT  19.152 0 19.176 0.084 ;
    END
  END n_d[63]
  PIN n_d[64]
    DIRECTION OUTPUT ;
    USE SIGNAL ;
    PORT
      LAYER M5 ;
        RECT  19.488 0 19.512 0.084 ;
    END
  END n_d[64]
  PIN n_d[65]
    DIRECTION OUTPUT ;
    USE SIGNAL ;
    PORT
      LAYER M5 ;
        RECT  19.776 0 19.8 0.084 ;
    END
  END n_d[65]
  PIN n_d[66]
    DIRECTION OUTPUT ;
    USE SIGNAL ;
    PORT
      LAYER M5 ;
        RECT  20.064 0 20.088 0.084 ;
    END
  END n_d[66]
  PIN n_d[67]
    DIRECTION OUTPUT ;
    USE SIGNAL ;
    PORT
      LAYER M5 ;
        RECT  20.352 0 20.376 0.084 ;
    END
  END n_d[67]
  PIN n_d[68]
    DIRECTION OUTPUT ;
    USE SIGNAL ;
    PORT
      LAYER M5 ;
        RECT  20.64 0 20.664 0.084 ;
    END
  END n_d[68]
  PIN n_d[69]
    DIRECTION OUTPUT ;
    USE SIGNAL ;
    PORT
      LAYER M5 ;
        RECT  20.928 0 20.952 0.084 ;
    END
  END n_d[69]
  PIN n_d[6]
    DIRECTION OUTPUT ;
    USE SIGNAL ;
    PORT
      LAYER M5 ;
        RECT  2.496 0 2.52 0.084 ;
    END
  END n_d[6]
  PIN n_d[70]
    DIRECTION OUTPUT ;
    USE SIGNAL ;
    PORT
      LAYER M5 ;
        RECT  21.216 0 21.24 0.084 ;
    END
  END n_d[70]
  PIN n_d[71]
    DIRECTION OUTPUT ;
    USE SIGNAL ;
    PORT
      LAYER M5 ;
        RECT  21.504 0 21.528 0.084 ;
    END
  END n_d[71]
  PIN n_d[72]
    DIRECTION OUTPUT ;
    USE SIGNAL ;
    PORT
      LAYER M5 ;
        RECT  21.792 0 21.816 0.084 ;
    END
  END n_d[72]
  PIN n_d[73]
    DIRECTION OUTPUT ;
    USE SIGNAL ;
    PORT
      LAYER M5 ;
        RECT  22.08 0 22.104 0.084 ;
    END
  END n_d[73]
  PIN n_d[74]
    DIRECTION OUTPUT ;
    USE SIGNAL ;
    PORT
      LAYER M5 ;
        RECT  22.416 0 22.44 0.084 ;
    END
  END n_d[74]
  PIN n_d[75]
    DIRECTION OUTPUT ;
    USE SIGNAL ;
    PORT
      LAYER M5 ;
        RECT  22.704 0 22.728 0.084 ;
    END
  END n_d[75]
  PIN n_d[76]
    DIRECTION OUTPUT ;
    USE SIGNAL ;
    PORT
      LAYER M5 ;
        RECT  22.992 0 23.016 0.084 ;
    END
  END n_d[76]
  PIN n_d[77]
    DIRECTION OUTPUT ;
    USE SIGNAL ;
    PORT
      LAYER M5 ;
        RECT  23.28 0 23.304 0.084 ;
    END
  END n_d[77]
  PIN n_d[78]
    DIRECTION OUTPUT ;
    USE SIGNAL ;
    PORT
      LAYER M5 ;
        RECT  23.568 0 23.592 0.084 ;
    END
  END n_d[78]
  PIN n_d[79]
    DIRECTION OUTPUT ;
    USE SIGNAL ;
    PORT
      LAYER M5 ;
        RECT  23.856 0 23.88 0.084 ;
    END
  END n_d[79]
  PIN n_d[7]
    DIRECTION OUTPUT ;
    USE SIGNAL ;
    PORT
      LAYER M5 ;
        RECT  2.784 0 2.808 0.084 ;
    END
  END n_d[7]
  PIN n_d[80]
    DIRECTION OUTPUT ;
    USE SIGNAL ;
    PORT
      LAYER M5 ;
        RECT  24.144 0 24.168 0.084 ;
    END
  END n_d[80]
  PIN n_d[81]
    DIRECTION OUTPUT ;
    USE SIGNAL ;
    PORT
      LAYER M5 ;
        RECT  24.432 0 24.456 0.084 ;
    END
  END n_d[81]
  PIN n_d[82]
    DIRECTION OUTPUT ;
    USE SIGNAL ;
    PORT
      LAYER M5 ;
        RECT  24.72 0 24.744 0.084 ;
    END
  END n_d[82]
  PIN n_d[83]
    DIRECTION OUTPUT ;
    USE SIGNAL ;
    PORT
      LAYER M5 ;
        RECT  25.008 0 25.032 0.084 ;
    END
  END n_d[83]
  PIN n_d[84]
    DIRECTION OUTPUT ;
    USE SIGNAL ;
    PORT
      LAYER M5 ;
        RECT  25.344 0 25.368 0.084 ;
    END
  END n_d[84]
  PIN n_d[85]
    DIRECTION OUTPUT ;
    USE SIGNAL ;
    PORT
      LAYER M5 ;
        RECT  25.632 0 25.656 0.084 ;
    END
  END n_d[85]
  PIN n_d[86]
    DIRECTION OUTPUT ;
    USE SIGNAL ;
    PORT
      LAYER M5 ;
        RECT  25.92 0 25.944 0.084 ;
    END
  END n_d[86]
  PIN n_d[87]
    DIRECTION OUTPUT ;
    USE SIGNAL ;
    PORT
      LAYER M5 ;
        RECT  26.208 0 26.232 0.084 ;
    END
  END n_d[87]
  PIN n_d[88]
    DIRECTION OUTPUT ;
    USE SIGNAL ;
    PORT
      LAYER M5 ;
        RECT  26.496 0 26.52 0.084 ;
    END
  END n_d[88]
  PIN n_d[89]
    DIRECTION OUTPUT ;
    USE SIGNAL ;
    PORT
      LAYER M5 ;
        RECT  26.784 0 26.808 0.084 ;
    END
  END n_d[89]
  PIN n_d[8]
    DIRECTION OUTPUT ;
    USE SIGNAL ;
    PORT
      LAYER M5 ;
        RECT  3.072 0 3.096 0.084 ;
    END
  END n_d[8]
  PIN n_d[90]
    DIRECTION OUTPUT ;
    USE SIGNAL ;
    PORT
      LAYER M5 ;
        RECT  27.072 0 27.096 0.084 ;
    END
  END n_d[90]
  PIN n_d[91]
    DIRECTION OUTPUT ;
    USE SIGNAL ;
    PORT
      LAYER M5 ;
        RECT  27.36 0 27.384 0.084 ;
    END
  END n_d[91]
  PIN n_d[92]
    DIRECTION OUTPUT ;
    USE SIGNAL ;
    PORT
      LAYER M5 ;
        RECT  27.648 0 27.672 0.084 ;
    END
  END n_d[92]
  PIN n_d[93]
    DIRECTION OUTPUT ;
    USE SIGNAL ;
    PORT
      LAYER M5 ;
        RECT  27.936 0 27.96 0.084 ;
    END
  END n_d[93]
  PIN n_d[94]
    DIRECTION OUTPUT ;
    USE SIGNAL ;
    PORT
      LAYER M7 ;
        RECT  28.224 0 28.256 0.07 ;
    END
  END n_d[94]
  PIN n_d[95]
    DIRECTION OUTPUT ;
    USE SIGNAL ;
    PORT
      LAYER M7 ;
        RECT  28.544 0 28.576 0.07 ;
    END
  END n_d[95]
  PIN n_d[96]
    DIRECTION OUTPUT ;
    USE SIGNAL ;
    PORT
      LAYER M7 ;
        RECT  28.864 0 28.896 0.07 ;
    END
  END n_d[96]
  PIN n_d[97]
    DIRECTION OUTPUT ;
    USE SIGNAL ;
    PORT
      LAYER M7 ;
        RECT  29.12 0 29.152 0.07 ;
    END
  END n_d[97]
  PIN n_d[98]
    DIRECTION OUTPUT ;
    USE SIGNAL ;
    PORT
      LAYER M7 ;
        RECT  29.44 0 29.472 0.07 ;
    END
  END n_d[98]
  PIN n_d[99]
    DIRECTION OUTPUT ;
    USE SIGNAL ;
    PORT
      LAYER M7 ;
        RECT  29.696 0 29.728 0.07 ;
    END
  END n_d[99]
  PIN n_d[9]
    DIRECTION OUTPUT ;
    USE SIGNAL ;
    PORT
      LAYER M5 ;
        RECT  3.36 0 3.384 0.084 ;
    END
  END n_d[9]
  PIN n_lane[0]
    DIRECTION OUTPUT ;
    USE SIGNAL ;
    PORT
      LAYER M5 ;
        RECT  75.696 0 75.72 0.084 ;
    END
  END n_lane[0]
  PIN n_lane[1]
    DIRECTION OUTPUT ;
    USE SIGNAL ;
    PORT
      LAYER M5 ;
        RECT  75.984 0 76.008 0.084 ;
    END
  END n_lane[1]
  PIN n_lane[2]
    DIRECTION OUTPUT ;
    USE SIGNAL ;
    PORT
      LAYER M5 ;
        RECT  76.272 0 76.296 0.084 ;
    END
  END n_lane[2]
  PIN n_sec[0]
    DIRECTION OUTPUT ;
    USE SIGNAL ;
    PORT
      LAYER M5 ;
        RECT  76.56 0 76.584 0.084 ;
    END
  END n_sec[0]
  PIN n_sec[10]
    DIRECTION OUTPUT ;
    USE SIGNAL ;
    PORT
      LAYER M5 ;
        RECT  79.488 0 79.512 0.084 ;
    END
  END n_sec[10]
  PIN n_sec[11]
    DIRECTION OUTPUT ;
    USE SIGNAL ;
    PORT
      LAYER M5 ;
        RECT  79.776 0 79.8 0.084 ;
    END
  END n_sec[11]
  PIN n_sec[12]
    DIRECTION OUTPUT ;
    USE SIGNAL ;
    PORT
      LAYER M5 ;
        RECT  80.112 0 80.136 0.084 ;
    END
  END n_sec[12]
  PIN n_sec[13]
    DIRECTION OUTPUT ;
    USE SIGNAL ;
    PORT
      LAYER M5 ;
        RECT  80.4 0 80.424 0.084 ;
    END
  END n_sec[13]
  PIN n_sec[14]
    DIRECTION OUTPUT ;
    USE SIGNAL ;
    PORT
      LAYER M5 ;
        RECT  80.688 0 80.712 0.084 ;
    END
  END n_sec[14]
  PIN n_sec[15]
    DIRECTION OUTPUT ;
    USE SIGNAL ;
    PORT
      LAYER M5 ;
        RECT  80.976 0 81 0.084 ;
    END
  END n_sec[15]
  PIN n_sec[16]
    DIRECTION OUTPUT ;
    USE SIGNAL ;
    PORT
      LAYER M5 ;
        RECT  81.264 0 81.288 0.084 ;
    END
  END n_sec[16]
  PIN n_sec[17]
    DIRECTION OUTPUT ;
    USE SIGNAL ;
    PORT
      LAYER M5 ;
        RECT  81.552 0 81.576 0.084 ;
    END
  END n_sec[17]
  PIN n_sec[18]
    DIRECTION OUTPUT ;
    USE SIGNAL ;
    PORT
      LAYER M5 ;
        RECT  81.84 0 81.864 0.084 ;
    END
  END n_sec[18]
  PIN n_sec[19]
    DIRECTION OUTPUT ;
    USE SIGNAL ;
    PORT
      LAYER M5 ;
        RECT  82.128 0 82.152 0.084 ;
    END
  END n_sec[19]
  PIN n_sec[1]
    DIRECTION OUTPUT ;
    USE SIGNAL ;
    PORT
      LAYER M5 ;
        RECT  76.848 0 76.872 0.084 ;
    END
  END n_sec[1]
  PIN n_sec[20]
    DIRECTION OUTPUT ;
    USE SIGNAL ;
    PORT
      LAYER M5 ;
        RECT  82.416 0 82.44 0.084 ;
    END
  END n_sec[20]
  PIN n_sec[21]
    DIRECTION OUTPUT ;
    USE SIGNAL ;
    PORT
      LAYER M5 ;
        RECT  82.704 0 82.728 0.084 ;
    END
  END n_sec[21]
  PIN n_sec[22]
    DIRECTION OUTPUT ;
    USE SIGNAL ;
    PORT
      LAYER M5 ;
        RECT  83.04 0 83.064 0.084 ;
    END
  END n_sec[22]
  PIN n_sec[23]
    DIRECTION OUTPUT ;
    USE SIGNAL ;
    PORT
      LAYER M5 ;
        RECT  83.328 0 83.352 0.084 ;
    END
  END n_sec[23]
  PIN n_sec[2]
    DIRECTION OUTPUT ;
    USE SIGNAL ;
    PORT
      LAYER M5 ;
        RECT  77.184 0 77.208 0.084 ;
    END
  END n_sec[2]
  PIN n_sec[3]
    DIRECTION OUTPUT ;
    USE SIGNAL ;
    PORT
      LAYER M5 ;
        RECT  77.472 0 77.496 0.084 ;
    END
  END n_sec[3]
  PIN n_sec[4]
    DIRECTION OUTPUT ;
    USE SIGNAL ;
    PORT
      LAYER M5 ;
        RECT  77.76 0 77.784 0.084 ;
    END
  END n_sec[4]
  PIN n_sec[5]
    DIRECTION OUTPUT ;
    USE SIGNAL ;
    PORT
      LAYER M5 ;
        RECT  78.048 0 78.072 0.084 ;
    END
  END n_sec[5]
  PIN n_sec[6]
    DIRECTION OUTPUT ;
    USE SIGNAL ;
    PORT
      LAYER M5 ;
        RECT  78.336 0 78.36 0.084 ;
    END
  END n_sec[6]
  PIN n_sec[7]
    DIRECTION OUTPUT ;
    USE SIGNAL ;
    PORT
      LAYER M5 ;
        RECT  78.624 0 78.648 0.084 ;
    END
  END n_sec[7]
  PIN n_sec[8]
    DIRECTION OUTPUT ;
    USE SIGNAL ;
    PORT
      LAYER M5 ;
        RECT  78.912 0 78.936 0.084 ;
    END
  END n_sec[8]
  PIN n_sec[9]
    DIRECTION OUTPUT ;
    USE SIGNAL ;
    PORT
      LAYER M5 ;
        RECT  79.2 0 79.224 0.084 ;
    END
  END n_sec[9]
  PIN n_tag[0]
    DIRECTION OUTPUT ;
    USE SIGNAL ;
    PORT
      LAYER M5 ;
        RECT  83.616 0 83.64 0.084 ;
    END
  END n_tag[0]
  PIN n_tag[1]
    DIRECTION OUTPUT ;
    USE SIGNAL ;
    PORT
      LAYER M5 ;
        RECT  83.904 0 83.928 0.084 ;
    END
  END n_tag[1]
  PIN n_tag[2]
    DIRECTION OUTPUT ;
    USE SIGNAL ;
    PORT
      LAYER M5 ;
        RECT  84.192 0 84.216 0.084 ;
    END
  END n_tag[2]
  PIN n_tag[3]
    DIRECTION OUTPUT ;
    USE SIGNAL ;
    PORT
      LAYER M7 ;
        RECT  84.48 0 84.512 0.07 ;
    END
  END n_tag[3]
  PIN n_tag[4]
    DIRECTION OUTPUT ;
    USE SIGNAL ;
    PORT
      LAYER M7 ;
        RECT  84.8 0 84.832 0.07 ;
    END
  END n_tag[4]
  PIN n_tag[5]
    DIRECTION OUTPUT ;
    USE SIGNAL ;
    PORT
      LAYER M7 ;
        RECT  85.056 0 85.088 0.07 ;
    END
  END n_tag[5]
  PIN n_tag[6]
    DIRECTION OUTPUT ;
    USE SIGNAL ;
    PORT
      LAYER M7 ;
        RECT  85.376 0 85.408 0.07 ;
    END
  END n_tag[6]
  PIN n_tag[7]
    DIRECTION OUTPUT ;
    USE SIGNAL ;
    PORT
      LAYER M7 ;
        RECT  85.632 0 85.664 0.07 ;
    END
  END n_tag[7]
  PIN n_tag[8]
    DIRECTION OUTPUT ;
    USE SIGNAL ;
    PORT
      LAYER M7 ;
        RECT  85.952 0 85.984 0.07 ;
    END
  END n_tag[8]
  PIN n_v
    DIRECTION OUTPUT ;
    USE SIGNAL ;
    PORT
      LAYER M7 ;
        RECT  86.208 0 86.24 0.07 ;
    END
  END n_v
  PIN rst_n
    DIRECTION INPUT ;
    USE SIGNAL ;
    PORT
      LAYER M4 ;
        RECT  86.316 165.216 86.4 165.24 ;
    END
  END rst_n
  PIN w_data[0]
    DIRECTION OUTPUT ;
    USE SIGNAL ;
    PORT
      LAYER M4 ;
        RECT  0 0.288 0.084 0.312 ;
    END
  END w_data[0]
  PIN w_data[100]
    DIRECTION OUTPUT ;
    USE SIGNAL ;
    PORT
      LAYER M6 ;
        RECT  0 61.312 0.07 61.344 ;
    END
  END w_data[100]
  PIN w_data[101]
    DIRECTION OUTPUT ;
    USE SIGNAL ;
    PORT
      LAYER M6 ;
        RECT  0 61.888 0.07 61.92 ;
    END
  END w_data[101]
  PIN w_data[102]
    DIRECTION OUTPUT ;
    USE SIGNAL ;
    PORT
      LAYER M6 ;
        RECT  0 62.528 0.07 62.56 ;
    END
  END w_data[102]
  PIN w_data[103]
    DIRECTION OUTPUT ;
    USE SIGNAL ;
    PORT
      LAYER M6 ;
        RECT  0 63.104 0.07 63.136 ;
    END
  END w_data[103]
  PIN w_data[104]
    DIRECTION OUTPUT ;
    USE SIGNAL ;
    PORT
      LAYER M6 ;
        RECT  0 63.744 0.07 63.776 ;
    END
  END w_data[104]
  PIN w_data[105]
    DIRECTION OUTPUT ;
    USE SIGNAL ;
    PORT
      LAYER M6 ;
        RECT  0 64.32 0.07 64.352 ;
    END
  END w_data[105]
  PIN w_data[106]
    DIRECTION OUTPUT ;
    USE SIGNAL ;
    PORT
      LAYER M6 ;
        RECT  0 64.96 0.07 64.992 ;
    END
  END w_data[106]
  PIN w_data[107]
    DIRECTION OUTPUT ;
    USE SIGNAL ;
    PORT
      LAYER M6 ;
        RECT  0 65.536 0.07 65.568 ;
    END
  END w_data[107]
  PIN w_data[108]
    DIRECTION OUTPUT ;
    USE SIGNAL ;
    PORT
      LAYER M6 ;
        RECT  0 66.176 0.07 66.208 ;
    END
  END w_data[108]
  PIN w_data[109]
    DIRECTION OUTPUT ;
    USE SIGNAL ;
    PORT
      LAYER M6 ;
        RECT  0 66.752 0.07 66.784 ;
    END
  END w_data[109]
  PIN w_data[10]
    DIRECTION OUTPUT ;
    USE SIGNAL ;
    PORT
      LAYER M4 ;
        RECT  0 6.384 0.084 6.408 ;
    END
  END w_data[10]
  PIN w_data[110]
    DIRECTION OUTPUT ;
    USE SIGNAL ;
    PORT
      LAYER M6 ;
        RECT  0 67.392 0.07 67.424 ;
    END
  END w_data[110]
  PIN w_data[111]
    DIRECTION OUTPUT ;
    USE SIGNAL ;
    PORT
      LAYER M6 ;
        RECT  0 67.968 0.07 68 ;
    END
  END w_data[111]
  PIN w_data[112]
    DIRECTION OUTPUT ;
    USE SIGNAL ;
    PORT
      LAYER M6 ;
        RECT  0 68.608 0.07 68.64 ;
    END
  END w_data[112]
  PIN w_data[113]
    DIRECTION OUTPUT ;
    USE SIGNAL ;
    PORT
      LAYER M6 ;
        RECT  0 69.184 0.07 69.216 ;
    END
  END w_data[113]
  PIN w_data[114]
    DIRECTION OUTPUT ;
    USE SIGNAL ;
    PORT
      LAYER M6 ;
        RECT  0 69.824 0.07 69.856 ;
    END
  END w_data[114]
  PIN w_data[115]
    DIRECTION OUTPUT ;
    USE SIGNAL ;
    PORT
      LAYER M6 ;
        RECT  0 70.464 0.07 70.496 ;
    END
  END w_data[115]
  PIN w_data[116]
    DIRECTION OUTPUT ;
    USE SIGNAL ;
    PORT
      LAYER M6 ;
        RECT  0 71.04 0.07 71.072 ;
    END
  END w_data[116]
  PIN w_data[117]
    DIRECTION OUTPUT ;
    USE SIGNAL ;
    PORT
      LAYER M6 ;
        RECT  0 71.68 0.07 71.712 ;
    END
  END w_data[117]
  PIN w_data[118]
    DIRECTION OUTPUT ;
    USE SIGNAL ;
    PORT
      LAYER M6 ;
        RECT  0 72.256 0.07 72.288 ;
    END
  END w_data[118]
  PIN w_data[119]
    DIRECTION OUTPUT ;
    USE SIGNAL ;
    PORT
      LAYER M6 ;
        RECT  0 72.896 0.07 72.928 ;
    END
  END w_data[119]
  PIN w_data[11]
    DIRECTION OUTPUT ;
    USE SIGNAL ;
    PORT
      LAYER M4 ;
        RECT  0 7.008 0.084 7.032 ;
    END
  END w_data[11]
  PIN w_data[120]
    DIRECTION OUTPUT ;
    USE SIGNAL ;
    PORT
      LAYER M6 ;
        RECT  0 73.472 0.07 73.504 ;
    END
  END w_data[120]
  PIN w_data[121]
    DIRECTION OUTPUT ;
    USE SIGNAL ;
    PORT
      LAYER M6 ;
        RECT  0 74.112 0.07 74.144 ;
    END
  END w_data[121]
  PIN w_data[122]
    DIRECTION OUTPUT ;
    USE SIGNAL ;
    PORT
      LAYER M6 ;
        RECT  0 74.688 0.07 74.72 ;
    END
  END w_data[122]
  PIN w_data[123]
    DIRECTION OUTPUT ;
    USE SIGNAL ;
    PORT
      LAYER M6 ;
        RECT  0 75.328 0.07 75.36 ;
    END
  END w_data[123]
  PIN w_data[124]
    DIRECTION OUTPUT ;
    USE SIGNAL ;
    PORT
      LAYER M6 ;
        RECT  0 75.904 0.07 75.936 ;
    END
  END w_data[124]
  PIN w_data[125]
    DIRECTION OUTPUT ;
    USE SIGNAL ;
    PORT
      LAYER M6 ;
        RECT  0 76.544 0.07 76.576 ;
    END
  END w_data[125]
  PIN w_data[126]
    DIRECTION OUTPUT ;
    USE SIGNAL ;
    PORT
      LAYER M6 ;
        RECT  0 77.12 0.07 77.152 ;
    END
  END w_data[126]
  PIN w_data[127]
    DIRECTION OUTPUT ;
    USE SIGNAL ;
    PORT
      LAYER M6 ;
        RECT  0 77.76 0.07 77.792 ;
    END
  END w_data[127]
  PIN w_data[128]
    DIRECTION OUTPUT ;
    USE SIGNAL ;
    PORT
      LAYER M4 ;
        RECT  0 78.384 0.084 78.408 ;
    END
  END w_data[128]
  PIN w_data[129]
    DIRECTION OUTPUT ;
    USE SIGNAL ;
    PORT
      LAYER M4 ;
        RECT  0 78.96 0.084 78.984 ;
    END
  END w_data[129]
  PIN w_data[12]
    DIRECTION OUTPUT ;
    USE SIGNAL ;
    PORT
      LAYER M4 ;
        RECT  0 7.632 0.084 7.656 ;
    END
  END w_data[12]
  PIN w_data[130]
    DIRECTION OUTPUT ;
    USE SIGNAL ;
    PORT
      LAYER M4 ;
        RECT  0 79.584 0.084 79.608 ;
    END
  END w_data[130]
  PIN w_data[131]
    DIRECTION OUTPUT ;
    USE SIGNAL ;
    PORT
      LAYER M4 ;
        RECT  0 80.208 0.084 80.232 ;
    END
  END w_data[131]
  PIN w_data[132]
    DIRECTION OUTPUT ;
    USE SIGNAL ;
    PORT
      LAYER M4 ;
        RECT  0 80.832 0.084 80.856 ;
    END
  END w_data[132]
  PIN w_data[133]
    DIRECTION OUTPUT ;
    USE SIGNAL ;
    PORT
      LAYER M4 ;
        RECT  0 81.408 0.084 81.432 ;
    END
  END w_data[133]
  PIN w_data[134]
    DIRECTION OUTPUT ;
    USE SIGNAL ;
    PORT
      LAYER M4 ;
        RECT  0 82.032 0.084 82.056 ;
    END
  END w_data[134]
  PIN w_data[135]
    DIRECTION OUTPUT ;
    USE SIGNAL ;
    PORT
      LAYER M4 ;
        RECT  0 82.656 0.084 82.68 ;
    END
  END w_data[135]
  PIN w_data[136]
    DIRECTION OUTPUT ;
    USE SIGNAL ;
    PORT
      LAYER M4 ;
        RECT  0 83.232 0.084 83.256 ;
    END
  END w_data[136]
  PIN w_data[137]
    DIRECTION OUTPUT ;
    USE SIGNAL ;
    PORT
      LAYER M4 ;
        RECT  0 83.856 0.084 83.88 ;
    END
  END w_data[137]
  PIN w_data[138]
    DIRECTION OUTPUT ;
    USE SIGNAL ;
    PORT
      LAYER M4 ;
        RECT  0 84.48 0.084 84.504 ;
    END
  END w_data[138]
  PIN w_data[139]
    DIRECTION OUTPUT ;
    USE SIGNAL ;
    PORT
      LAYER M4 ;
        RECT  0 85.056 0.084 85.08 ;
    END
  END w_data[139]
  PIN w_data[13]
    DIRECTION OUTPUT ;
    USE SIGNAL ;
    PORT
      LAYER M4 ;
        RECT  0 8.208 0.084 8.232 ;
    END
  END w_data[13]
  PIN w_data[140]
    DIRECTION OUTPUT ;
    USE SIGNAL ;
    PORT
      LAYER M4 ;
        RECT  0 85.68 0.084 85.704 ;
    END
  END w_data[140]
  PIN w_data[141]
    DIRECTION OUTPUT ;
    USE SIGNAL ;
    PORT
      LAYER M4 ;
        RECT  0 86.304 0.084 86.328 ;
    END
  END w_data[141]
  PIN w_data[142]
    DIRECTION OUTPUT ;
    USE SIGNAL ;
    PORT
      LAYER M4 ;
        RECT  0 86.928 0.084 86.952 ;
    END
  END w_data[142]
  PIN w_data[143]
    DIRECTION OUTPUT ;
    USE SIGNAL ;
    PORT
      LAYER M4 ;
        RECT  0 87.504 0.084 87.528 ;
    END
  END w_data[143]
  PIN w_data[144]
    DIRECTION OUTPUT ;
    USE SIGNAL ;
    PORT
      LAYER M4 ;
        RECT  0 88.128 0.084 88.152 ;
    END
  END w_data[144]
  PIN w_data[145]
    DIRECTION OUTPUT ;
    USE SIGNAL ;
    PORT
      LAYER M4 ;
        RECT  0 88.752 0.084 88.776 ;
    END
  END w_data[145]
  PIN w_data[146]
    DIRECTION OUTPUT ;
    USE SIGNAL ;
    PORT
      LAYER M4 ;
        RECT  0 89.328 0.084 89.352 ;
    END
  END w_data[146]
  PIN w_data[147]
    DIRECTION OUTPUT ;
    USE SIGNAL ;
    PORT
      LAYER M4 ;
        RECT  0 89.952 0.084 89.976 ;
    END
  END w_data[147]
  PIN w_data[148]
    DIRECTION OUTPUT ;
    USE SIGNAL ;
    PORT
      LAYER M4 ;
        RECT  0 90.576 0.084 90.6 ;
    END
  END w_data[148]
  PIN w_data[149]
    DIRECTION OUTPUT ;
    USE SIGNAL ;
    PORT
      LAYER M4 ;
        RECT  0 91.2 0.084 91.224 ;
    END
  END w_data[149]
  PIN w_data[14]
    DIRECTION OUTPUT ;
    USE SIGNAL ;
    PORT
      LAYER M4 ;
        RECT  0 8.832 0.084 8.856 ;
    END
  END w_data[14]
  PIN w_data[150]
    DIRECTION OUTPUT ;
    USE SIGNAL ;
    PORT
      LAYER M4 ;
        RECT  0 91.776 0.084 91.8 ;
    END
  END w_data[150]
  PIN w_data[151]
    DIRECTION OUTPUT ;
    USE SIGNAL ;
    PORT
      LAYER M4 ;
        RECT  0 92.4 0.084 92.424 ;
    END
  END w_data[151]
  PIN w_data[152]
    DIRECTION OUTPUT ;
    USE SIGNAL ;
    PORT
      LAYER M4 ;
        RECT  0 93.024 0.084 93.048 ;
    END
  END w_data[152]
  PIN w_data[153]
    DIRECTION OUTPUT ;
    USE SIGNAL ;
    PORT
      LAYER M4 ;
        RECT  0 93.6 0.084 93.624 ;
    END
  END w_data[153]
  PIN w_data[154]
    DIRECTION OUTPUT ;
    USE SIGNAL ;
    PORT
      LAYER M4 ;
        RECT  0 94.224 0.084 94.248 ;
    END
  END w_data[154]
  PIN w_data[155]
    DIRECTION OUTPUT ;
    USE SIGNAL ;
    PORT
      LAYER M4 ;
        RECT  0 94.848 0.084 94.872 ;
    END
  END w_data[155]
  PIN w_data[156]
    DIRECTION OUTPUT ;
    USE SIGNAL ;
    PORT
      LAYER M4 ;
        RECT  0 95.472 0.084 95.496 ;
    END
  END w_data[156]
  PIN w_data[157]
    DIRECTION OUTPUT ;
    USE SIGNAL ;
    PORT
      LAYER M4 ;
        RECT  0 96.048 0.084 96.072 ;
    END
  END w_data[157]
  PIN w_data[158]
    DIRECTION OUTPUT ;
    USE SIGNAL ;
    PORT
      LAYER M4 ;
        RECT  0 96.672 0.084 96.696 ;
    END
  END w_data[158]
  PIN w_data[159]
    DIRECTION OUTPUT ;
    USE SIGNAL ;
    PORT
      LAYER M4 ;
        RECT  0 97.296 0.084 97.32 ;
    END
  END w_data[159]
  PIN w_data[15]
    DIRECTION OUTPUT ;
    USE SIGNAL ;
    PORT
      LAYER M4 ;
        RECT  0 9.456 0.084 9.48 ;
    END
  END w_data[15]
  PIN w_data[160]
    DIRECTION OUTPUT ;
    USE SIGNAL ;
    PORT
      LAYER M6 ;
        RECT  0 97.856 0.07 97.888 ;
    END
  END w_data[160]
  PIN w_data[161]
    DIRECTION OUTPUT ;
    USE SIGNAL ;
    PORT
      LAYER M6 ;
        RECT  0 98.496 0.07 98.528 ;
    END
  END w_data[161]
  PIN w_data[162]
    DIRECTION OUTPUT ;
    USE SIGNAL ;
    PORT
      LAYER M6 ;
        RECT  0 99.136 0.07 99.168 ;
    END
  END w_data[162]
  PIN w_data[163]
    DIRECTION OUTPUT ;
    USE SIGNAL ;
    PORT
      LAYER M6 ;
        RECT  0 99.712 0.07 99.744 ;
    END
  END w_data[163]
  PIN w_data[164]
    DIRECTION OUTPUT ;
    USE SIGNAL ;
    PORT
      LAYER M6 ;
        RECT  0 100.352 0.07 100.384 ;
    END
  END w_data[164]
  PIN w_data[165]
    DIRECTION OUTPUT ;
    USE SIGNAL ;
    PORT
      LAYER M6 ;
        RECT  0 100.928 0.07 100.96 ;
    END
  END w_data[165]
  PIN w_data[166]
    DIRECTION OUTPUT ;
    USE SIGNAL ;
    PORT
      LAYER M6 ;
        RECT  0 101.568 0.07 101.6 ;
    END
  END w_data[166]
  PIN w_data[167]
    DIRECTION OUTPUT ;
    USE SIGNAL ;
    PORT
      LAYER M6 ;
        RECT  0 102.144 0.07 102.176 ;
    END
  END w_data[167]
  PIN w_data[168]
    DIRECTION OUTPUT ;
    USE SIGNAL ;
    PORT
      LAYER M6 ;
        RECT  0 102.784 0.07 102.816 ;
    END
  END w_data[168]
  PIN w_data[169]
    DIRECTION OUTPUT ;
    USE SIGNAL ;
    PORT
      LAYER M6 ;
        RECT  0 103.36 0.07 103.392 ;
    END
  END w_data[169]
  PIN w_data[16]
    DIRECTION OUTPUT ;
    USE SIGNAL ;
    PORT
      LAYER M4 ;
        RECT  0 10.032 0.084 10.056 ;
    END
  END w_data[16]
  PIN w_data[170]
    DIRECTION OUTPUT ;
    USE SIGNAL ;
    PORT
      LAYER M6 ;
        RECT  0 104 0.07 104.032 ;
    END
  END w_data[170]
  PIN w_data[171]
    DIRECTION OUTPUT ;
    USE SIGNAL ;
    PORT
      LAYER M6 ;
        RECT  0 104.576 0.07 104.608 ;
    END
  END w_data[171]
  PIN w_data[172]
    DIRECTION OUTPUT ;
    USE SIGNAL ;
    PORT
      LAYER M6 ;
        RECT  0 105.216 0.07 105.248 ;
    END
  END w_data[172]
  PIN w_data[173]
    DIRECTION OUTPUT ;
    USE SIGNAL ;
    PORT
      LAYER M6 ;
        RECT  0 105.792 0.07 105.824 ;
    END
  END w_data[173]
  PIN w_data[174]
    DIRECTION OUTPUT ;
    USE SIGNAL ;
    PORT
      LAYER M6 ;
        RECT  0 106.432 0.07 106.464 ;
    END
  END w_data[174]
  PIN w_data[175]
    DIRECTION OUTPUT ;
    USE SIGNAL ;
    PORT
      LAYER M6 ;
        RECT  0 107.008 0.07 107.04 ;
    END
  END w_data[175]
  PIN w_data[176]
    DIRECTION OUTPUT ;
    USE SIGNAL ;
    PORT
      LAYER M6 ;
        RECT  0 107.648 0.07 107.68 ;
    END
  END w_data[176]
  PIN w_data[177]
    DIRECTION OUTPUT ;
    USE SIGNAL ;
    PORT
      LAYER M6 ;
        RECT  0 108.224 0.07 108.256 ;
    END
  END w_data[177]
  PIN w_data[178]
    DIRECTION OUTPUT ;
    USE SIGNAL ;
    PORT
      LAYER M6 ;
        RECT  0 108.864 0.07 108.896 ;
    END
  END w_data[178]
  PIN w_data[179]
    DIRECTION OUTPUT ;
    USE SIGNAL ;
    PORT
      LAYER M6 ;
        RECT  0 109.504 0.07 109.536 ;
    END
  END w_data[179]
  PIN w_data[17]
    DIRECTION OUTPUT ;
    USE SIGNAL ;
    PORT
      LAYER M4 ;
        RECT  0 10.656 0.084 10.68 ;
    END
  END w_data[17]
  PIN w_data[180]
    DIRECTION OUTPUT ;
    USE SIGNAL ;
    PORT
      LAYER M6 ;
        RECT  0 110.08 0.07 110.112 ;
    END
  END w_data[180]
  PIN w_data[181]
    DIRECTION OUTPUT ;
    USE SIGNAL ;
    PORT
      LAYER M6 ;
        RECT  0 110.72 0.07 110.752 ;
    END
  END w_data[181]
  PIN w_data[182]
    DIRECTION OUTPUT ;
    USE SIGNAL ;
    PORT
      LAYER M6 ;
        RECT  0 111.296 0.07 111.328 ;
    END
  END w_data[182]
  PIN w_data[183]
    DIRECTION OUTPUT ;
    USE SIGNAL ;
    PORT
      LAYER M6 ;
        RECT  0 111.936 0.07 111.968 ;
    END
  END w_data[183]
  PIN w_data[184]
    DIRECTION OUTPUT ;
    USE SIGNAL ;
    PORT
      LAYER M6 ;
        RECT  0 112.512 0.07 112.544 ;
    END
  END w_data[184]
  PIN w_data[185]
    DIRECTION OUTPUT ;
    USE SIGNAL ;
    PORT
      LAYER M6 ;
        RECT  0 113.152 0.07 113.184 ;
    END
  END w_data[185]
  PIN w_data[186]
    DIRECTION OUTPUT ;
    USE SIGNAL ;
    PORT
      LAYER M6 ;
        RECT  0 113.728 0.07 113.76 ;
    END
  END w_data[186]
  PIN w_data[187]
    DIRECTION OUTPUT ;
    USE SIGNAL ;
    PORT
      LAYER M6 ;
        RECT  0 114.368 0.07 114.4 ;
    END
  END w_data[187]
  PIN w_data[188]
    DIRECTION OUTPUT ;
    USE SIGNAL ;
    PORT
      LAYER M6 ;
        RECT  0 114.944 0.07 114.976 ;
    END
  END w_data[188]
  PIN w_data[189]
    DIRECTION OUTPUT ;
    USE SIGNAL ;
    PORT
      LAYER M6 ;
        RECT  0 115.584 0.07 115.616 ;
    END
  END w_data[189]
  PIN w_data[18]
    DIRECTION OUTPUT ;
    USE SIGNAL ;
    PORT
      LAYER M4 ;
        RECT  0 11.28 0.084 11.304 ;
    END
  END w_data[18]
  PIN w_data[190]
    DIRECTION OUTPUT ;
    USE SIGNAL ;
    PORT
      LAYER M6 ;
        RECT  0 116.16 0.07 116.192 ;
    END
  END w_data[190]
  PIN w_data[191]
    DIRECTION OUTPUT ;
    USE SIGNAL ;
    PORT
      LAYER M6 ;
        RECT  0 116.8 0.07 116.832 ;
    END
  END w_data[191]
  PIN w_data[192]
    DIRECTION OUTPUT ;
    USE SIGNAL ;
    PORT
      LAYER M4 ;
        RECT  0 117.408 0.084 117.432 ;
    END
  END w_data[192]
  PIN w_data[193]
    DIRECTION OUTPUT ;
    USE SIGNAL ;
    PORT
      LAYER M4 ;
        RECT  0 118.032 0.084 118.056 ;
    END
  END w_data[193]
  PIN w_data[194]
    DIRECTION OUTPUT ;
    USE SIGNAL ;
    PORT
      LAYER M4 ;
        RECT  0 118.608 0.084 118.632 ;
    END
  END w_data[194]
  PIN w_data[195]
    DIRECTION OUTPUT ;
    USE SIGNAL ;
    PORT
      LAYER M4 ;
        RECT  0 119.232 0.084 119.256 ;
    END
  END w_data[195]
  PIN w_data[196]
    DIRECTION OUTPUT ;
    USE SIGNAL ;
    PORT
      LAYER M4 ;
        RECT  0 119.856 0.084 119.88 ;
    END
  END w_data[196]
  PIN w_data[197]
    DIRECTION OUTPUT ;
    USE SIGNAL ;
    PORT
      LAYER M4 ;
        RECT  0 120.48 0.084 120.504 ;
    END
  END w_data[197]
  PIN w_data[198]
    DIRECTION OUTPUT ;
    USE SIGNAL ;
    PORT
      LAYER M4 ;
        RECT  0 121.056 0.084 121.08 ;
    END
  END w_data[198]
  PIN w_data[199]
    DIRECTION OUTPUT ;
    USE SIGNAL ;
    PORT
      LAYER M4 ;
        RECT  0 121.68 0.084 121.704 ;
    END
  END w_data[199]
  PIN w_data[19]
    DIRECTION OUTPUT ;
    USE SIGNAL ;
    PORT
      LAYER M4 ;
        RECT  0 11.904 0.084 11.928 ;
    END
  END w_data[19]
  PIN w_data[1]
    DIRECTION OUTPUT ;
    USE SIGNAL ;
    PORT
      LAYER M4 ;
        RECT  0 0.912 0.084 0.936 ;
    END
  END w_data[1]
  PIN w_data[200]
    DIRECTION OUTPUT ;
    USE SIGNAL ;
    PORT
      LAYER M4 ;
        RECT  0 122.304 0.084 122.328 ;
    END
  END w_data[200]
  PIN w_data[201]
    DIRECTION OUTPUT ;
    USE SIGNAL ;
    PORT
      LAYER M4 ;
        RECT  0 122.88 0.084 122.904 ;
    END
  END w_data[201]
  PIN w_data[202]
    DIRECTION OUTPUT ;
    USE SIGNAL ;
    PORT
      LAYER M4 ;
        RECT  0 123.504 0.084 123.528 ;
    END
  END w_data[202]
  PIN w_data[203]
    DIRECTION OUTPUT ;
    USE SIGNAL ;
    PORT
      LAYER M4 ;
        RECT  0 124.128 0.084 124.152 ;
    END
  END w_data[203]
  PIN w_data[204]
    DIRECTION OUTPUT ;
    USE SIGNAL ;
    PORT
      LAYER M4 ;
        RECT  0 124.704 0.084 124.728 ;
    END
  END w_data[204]
  PIN w_data[205]
    DIRECTION OUTPUT ;
    USE SIGNAL ;
    PORT
      LAYER M4 ;
        RECT  0 125.328 0.084 125.352 ;
    END
  END w_data[205]
  PIN w_data[206]
    DIRECTION OUTPUT ;
    USE SIGNAL ;
    PORT
      LAYER M4 ;
        RECT  0 125.952 0.084 125.976 ;
    END
  END w_data[206]
  PIN w_data[207]
    DIRECTION OUTPUT ;
    USE SIGNAL ;
    PORT
      LAYER M4 ;
        RECT  0 126.576 0.084 126.6 ;
    END
  END w_data[207]
  PIN w_data[208]
    DIRECTION OUTPUT ;
    USE SIGNAL ;
    PORT
      LAYER M4 ;
        RECT  0 127.152 0.084 127.176 ;
    END
  END w_data[208]
  PIN w_data[209]
    DIRECTION OUTPUT ;
    USE SIGNAL ;
    PORT
      LAYER M4 ;
        RECT  0 127.776 0.084 127.8 ;
    END
  END w_data[209]
  PIN w_data[20]
    DIRECTION OUTPUT ;
    USE SIGNAL ;
    PORT
      LAYER M4 ;
        RECT  0 12.48 0.084 12.504 ;
    END
  END w_data[20]
  PIN w_data[210]
    DIRECTION OUTPUT ;
    USE SIGNAL ;
    PORT
      LAYER M4 ;
        RECT  0 128.4 0.084 128.424 ;
    END
  END w_data[210]
  PIN w_data[211]
    DIRECTION OUTPUT ;
    USE SIGNAL ;
    PORT
      LAYER M4 ;
        RECT  0 128.976 0.084 129 ;
    END
  END w_data[211]
  PIN w_data[212]
    DIRECTION OUTPUT ;
    USE SIGNAL ;
    PORT
      LAYER M4 ;
        RECT  0 129.6 0.084 129.624 ;
    END
  END w_data[212]
  PIN w_data[213]
    DIRECTION OUTPUT ;
    USE SIGNAL ;
    PORT
      LAYER M4 ;
        RECT  0 130.224 0.084 130.248 ;
    END
  END w_data[213]
  PIN w_data[214]
    DIRECTION OUTPUT ;
    USE SIGNAL ;
    PORT
      LAYER M4 ;
        RECT  0 130.848 0.084 130.872 ;
    END
  END w_data[214]
  PIN w_data[215]
    DIRECTION OUTPUT ;
    USE SIGNAL ;
    PORT
      LAYER M4 ;
        RECT  0 131.424 0.084 131.448 ;
    END
  END w_data[215]
  PIN w_data[216]
    DIRECTION OUTPUT ;
    USE SIGNAL ;
    PORT
      LAYER M4 ;
        RECT  0 132.048 0.084 132.072 ;
    END
  END w_data[216]
  PIN w_data[217]
    DIRECTION OUTPUT ;
    USE SIGNAL ;
    PORT
      LAYER M4 ;
        RECT  0 132.672 0.084 132.696 ;
    END
  END w_data[217]
  PIN w_data[218]
    DIRECTION OUTPUT ;
    USE SIGNAL ;
    PORT
      LAYER M4 ;
        RECT  0 133.248 0.084 133.272 ;
    END
  END w_data[218]
  PIN w_data[219]
    DIRECTION OUTPUT ;
    USE SIGNAL ;
    PORT
      LAYER M4 ;
        RECT  0 133.872 0.084 133.896 ;
    END
  END w_data[219]
  PIN w_data[21]
    DIRECTION OUTPUT ;
    USE SIGNAL ;
    PORT
      LAYER M4 ;
        RECT  0 13.104 0.084 13.128 ;
    END
  END w_data[21]
  PIN w_data[220]
    DIRECTION OUTPUT ;
    USE SIGNAL ;
    PORT
      LAYER M4 ;
        RECT  0 134.496 0.084 134.52 ;
    END
  END w_data[220]
  PIN w_data[221]
    DIRECTION OUTPUT ;
    USE SIGNAL ;
    PORT
      LAYER M4 ;
        RECT  0 135.12 0.084 135.144 ;
    END
  END w_data[221]
  PIN w_data[222]
    DIRECTION OUTPUT ;
    USE SIGNAL ;
    PORT
      LAYER M4 ;
        RECT  0 135.696 0.084 135.72 ;
    END
  END w_data[222]
  PIN w_data[223]
    DIRECTION OUTPUT ;
    USE SIGNAL ;
    PORT
      LAYER M4 ;
        RECT  0 136.32 0.084 136.344 ;
    END
  END w_data[223]
  PIN w_data[224]
    DIRECTION OUTPUT ;
    USE SIGNAL ;
    PORT
      LAYER M6 ;
        RECT  0 136.896 0.07 136.928 ;
    END
  END w_data[224]
  PIN w_data[225]
    DIRECTION OUTPUT ;
    USE SIGNAL ;
    PORT
      LAYER M6 ;
        RECT  0 137.536 0.07 137.568 ;
    END
  END w_data[225]
  PIN w_data[226]
    DIRECTION OUTPUT ;
    USE SIGNAL ;
    PORT
      LAYER M6 ;
        RECT  0 138.112 0.07 138.144 ;
    END
  END w_data[226]
  PIN w_data[227]
    DIRECTION OUTPUT ;
    USE SIGNAL ;
    PORT
      LAYER M6 ;
        RECT  0 138.752 0.07 138.784 ;
    END
  END w_data[227]
  PIN w_data[228]
    DIRECTION OUTPUT ;
    USE SIGNAL ;
    PORT
      LAYER M6 ;
        RECT  0 139.392 0.07 139.424 ;
    END
  END w_data[228]
  PIN w_data[229]
    DIRECTION OUTPUT ;
    USE SIGNAL ;
    PORT
      LAYER M6 ;
        RECT  0 139.968 0.07 140 ;
    END
  END w_data[229]
  PIN w_data[22]
    DIRECTION OUTPUT ;
    USE SIGNAL ;
    PORT
      LAYER M4 ;
        RECT  0 13.728 0.084 13.752 ;
    END
  END w_data[22]
  PIN w_data[230]
    DIRECTION OUTPUT ;
    USE SIGNAL ;
    PORT
      LAYER M6 ;
        RECT  0 140.608 0.07 140.64 ;
    END
  END w_data[230]
  PIN w_data[231]
    DIRECTION OUTPUT ;
    USE SIGNAL ;
    PORT
      LAYER M6 ;
        RECT  0 141.184 0.07 141.216 ;
    END
  END w_data[231]
  PIN w_data[232]
    DIRECTION OUTPUT ;
    USE SIGNAL ;
    PORT
      LAYER M6 ;
        RECT  0 141.824 0.07 141.856 ;
    END
  END w_data[232]
  PIN w_data[233]
    DIRECTION OUTPUT ;
    USE SIGNAL ;
    PORT
      LAYER M6 ;
        RECT  0 142.4 0.07 142.432 ;
    END
  END w_data[233]
  PIN w_data[234]
    DIRECTION OUTPUT ;
    USE SIGNAL ;
    PORT
      LAYER M6 ;
        RECT  0 143.04 0.07 143.072 ;
    END
  END w_data[234]
  PIN w_data[235]
    DIRECTION OUTPUT ;
    USE SIGNAL ;
    PORT
      LAYER M6 ;
        RECT  0 143.616 0.07 143.648 ;
    END
  END w_data[235]
  PIN w_data[236]
    DIRECTION OUTPUT ;
    USE SIGNAL ;
    PORT
      LAYER M6 ;
        RECT  0 144.256 0.07 144.288 ;
    END
  END w_data[236]
  PIN w_data[237]
    DIRECTION OUTPUT ;
    USE SIGNAL ;
    PORT
      LAYER M6 ;
        RECT  0 144.832 0.07 144.864 ;
    END
  END w_data[237]
  PIN w_data[238]
    DIRECTION OUTPUT ;
    USE SIGNAL ;
    PORT
      LAYER M6 ;
        RECT  0 145.472 0.07 145.504 ;
    END
  END w_data[238]
  PIN w_data[239]
    DIRECTION OUTPUT ;
    USE SIGNAL ;
    PORT
      LAYER M6 ;
        RECT  0 146.048 0.07 146.08 ;
    END
  END w_data[239]
  PIN w_data[23]
    DIRECTION OUTPUT ;
    USE SIGNAL ;
    PORT
      LAYER M4 ;
        RECT  0 14.304 0.084 14.328 ;
    END
  END w_data[23]
  PIN w_data[240]
    DIRECTION OUTPUT ;
    USE SIGNAL ;
    PORT
      LAYER M6 ;
        RECT  0 146.688 0.07 146.72 ;
    END
  END w_data[240]
  PIN w_data[241]
    DIRECTION OUTPUT ;
    USE SIGNAL ;
    PORT
      LAYER M6 ;
        RECT  0 147.264 0.07 147.296 ;
    END
  END w_data[241]
  PIN w_data[242]
    DIRECTION OUTPUT ;
    USE SIGNAL ;
    PORT
      LAYER M6 ;
        RECT  0 147.904 0.07 147.936 ;
    END
  END w_data[242]
  PIN w_data[243]
    DIRECTION OUTPUT ;
    USE SIGNAL ;
    PORT
      LAYER M6 ;
        RECT  0 148.48 0.07 148.512 ;
    END
  END w_data[243]
  PIN w_data[244]
    DIRECTION OUTPUT ;
    USE SIGNAL ;
    PORT
      LAYER M6 ;
        RECT  0 149.12 0.07 149.152 ;
    END
  END w_data[244]
  PIN w_data[245]
    DIRECTION OUTPUT ;
    USE SIGNAL ;
    PORT
      LAYER M6 ;
        RECT  0 149.76 0.07 149.792 ;
    END
  END w_data[245]
  PIN w_data[246]
    DIRECTION OUTPUT ;
    USE SIGNAL ;
    PORT
      LAYER M6 ;
        RECT  0 150.336 0.07 150.368 ;
    END
  END w_data[246]
  PIN w_data[247]
    DIRECTION OUTPUT ;
    USE SIGNAL ;
    PORT
      LAYER M6 ;
        RECT  0 150.976 0.07 151.008 ;
    END
  END w_data[247]
  PIN w_data[248]
    DIRECTION OUTPUT ;
    USE SIGNAL ;
    PORT
      LAYER M6 ;
        RECT  0 151.552 0.07 151.584 ;
    END
  END w_data[248]
  PIN w_data[249]
    DIRECTION OUTPUT ;
    USE SIGNAL ;
    PORT
      LAYER M6 ;
        RECT  0 152.192 0.07 152.224 ;
    END
  END w_data[249]
  PIN w_data[24]
    DIRECTION OUTPUT ;
    USE SIGNAL ;
    PORT
      LAYER M4 ;
        RECT  0 14.928 0.084 14.952 ;
    END
  END w_data[24]
  PIN w_data[250]
    DIRECTION OUTPUT ;
    USE SIGNAL ;
    PORT
      LAYER M6 ;
        RECT  0 152.768 0.07 152.8 ;
    END
  END w_data[250]
  PIN w_data[251]
    DIRECTION OUTPUT ;
    USE SIGNAL ;
    PORT
      LAYER M6 ;
        RECT  0 153.408 0.07 153.44 ;
    END
  END w_data[251]
  PIN w_data[252]
    DIRECTION OUTPUT ;
    USE SIGNAL ;
    PORT
      LAYER M6 ;
        RECT  0 153.984 0.07 154.016 ;
    END
  END w_data[252]
  PIN w_data[253]
    DIRECTION OUTPUT ;
    USE SIGNAL ;
    PORT
      LAYER M6 ;
        RECT  0 154.624 0.07 154.656 ;
    END
  END w_data[253]
  PIN w_data[254]
    DIRECTION OUTPUT ;
    USE SIGNAL ;
    PORT
      LAYER M6 ;
        RECT  0 155.2 0.07 155.232 ;
    END
  END w_data[254]
  PIN w_data[255]
    DIRECTION OUTPUT ;
    USE SIGNAL ;
    PORT
      LAYER M6 ;
        RECT  0 155.84 0.07 155.872 ;
    END
  END w_data[255]
  PIN w_data[25]
    DIRECTION OUTPUT ;
    USE SIGNAL ;
    PORT
      LAYER M4 ;
        RECT  0 15.552 0.084 15.576 ;
    END
  END w_data[25]
  PIN w_data[26]
    DIRECTION OUTPUT ;
    USE SIGNAL ;
    PORT
      LAYER M4 ;
        RECT  0 16.176 0.084 16.2 ;
    END
  END w_data[26]
  PIN w_data[27]
    DIRECTION OUTPUT ;
    USE SIGNAL ;
    PORT
      LAYER M4 ;
        RECT  0 16.752 0.084 16.776 ;
    END
  END w_data[27]
  PIN w_data[28]
    DIRECTION OUTPUT ;
    USE SIGNAL ;
    PORT
      LAYER M4 ;
        RECT  0 17.376 0.084 17.4 ;
    END
  END w_data[28]
  PIN w_data[29]
    DIRECTION OUTPUT ;
    USE SIGNAL ;
    PORT
      LAYER M4 ;
        RECT  0 18 0.084 18.024 ;
    END
  END w_data[29]
  PIN w_data[2]
    DIRECTION OUTPUT ;
    USE SIGNAL ;
    PORT
      LAYER M4 ;
        RECT  0 1.536 0.084 1.56 ;
    END
  END w_data[2]
  PIN w_data[30]
    DIRECTION OUTPUT ;
    USE SIGNAL ;
    PORT
      LAYER M4 ;
        RECT  0 18.576 0.084 18.6 ;
    END
  END w_data[30]
  PIN w_data[31]
    DIRECTION OUTPUT ;
    USE SIGNAL ;
    PORT
      LAYER M4 ;
        RECT  0 19.2 0.084 19.224 ;
    END
  END w_data[31]
  PIN w_data[32]
    DIRECTION OUTPUT ;
    USE SIGNAL ;
    PORT
      LAYER M6 ;
        RECT  0 19.84 0.07 19.872 ;
    END
  END w_data[32]
  PIN w_data[33]
    DIRECTION OUTPUT ;
    USE SIGNAL ;
    PORT
      LAYER M6 ;
        RECT  0 20.416 0.07 20.448 ;
    END
  END w_data[33]
  PIN w_data[34]
    DIRECTION OUTPUT ;
    USE SIGNAL ;
    PORT
      LAYER M6 ;
        RECT  0 21.056 0.07 21.088 ;
    END
  END w_data[34]
  PIN w_data[35]
    DIRECTION OUTPUT ;
    USE SIGNAL ;
    PORT
      LAYER M6 ;
        RECT  0 21.632 0.07 21.664 ;
    END
  END w_data[35]
  PIN w_data[36]
    DIRECTION OUTPUT ;
    USE SIGNAL ;
    PORT
      LAYER M6 ;
        RECT  0 22.272 0.07 22.304 ;
    END
  END w_data[36]
  PIN w_data[37]
    DIRECTION OUTPUT ;
    USE SIGNAL ;
    PORT
      LAYER M6 ;
        RECT  0 22.848 0.07 22.88 ;
    END
  END w_data[37]
  PIN w_data[38]
    DIRECTION OUTPUT ;
    USE SIGNAL ;
    PORT
      LAYER M6 ;
        RECT  0 23.488 0.07 23.52 ;
    END
  END w_data[38]
  PIN w_data[39]
    DIRECTION OUTPUT ;
    USE SIGNAL ;
    PORT
      LAYER M6 ;
        RECT  0 24.064 0.07 24.096 ;
    END
  END w_data[39]
  PIN w_data[3]
    DIRECTION OUTPUT ;
    USE SIGNAL ;
    PORT
      LAYER M4 ;
        RECT  0 2.112 0.084 2.136 ;
    END
  END w_data[3]
  PIN w_data[40]
    DIRECTION OUTPUT ;
    USE SIGNAL ;
    PORT
      LAYER M6 ;
        RECT  0 24.704 0.07 24.736 ;
    END
  END w_data[40]
  PIN w_data[41]
    DIRECTION OUTPUT ;
    USE SIGNAL ;
    PORT
      LAYER M6 ;
        RECT  0 25.28 0.07 25.312 ;
    END
  END w_data[41]
  PIN w_data[42]
    DIRECTION OUTPUT ;
    USE SIGNAL ;
    PORT
      LAYER M6 ;
        RECT  0 25.92 0.07 25.952 ;
    END
  END w_data[42]
  PIN w_data[43]
    DIRECTION OUTPUT ;
    USE SIGNAL ;
    PORT
      LAYER M6 ;
        RECT  0 26.496 0.07 26.528 ;
    END
  END w_data[43]
  PIN w_data[44]
    DIRECTION OUTPUT ;
    USE SIGNAL ;
    PORT
      LAYER M6 ;
        RECT  0 27.136 0.07 27.168 ;
    END
  END w_data[44]
  PIN w_data[45]
    DIRECTION OUTPUT ;
    USE SIGNAL ;
    PORT
      LAYER M6 ;
        RECT  0 27.712 0.07 27.744 ;
    END
  END w_data[45]
  PIN w_data[46]
    DIRECTION OUTPUT ;
    USE SIGNAL ;
    PORT
      LAYER M6 ;
        RECT  0 28.352 0.07 28.384 ;
    END
  END w_data[46]
  PIN w_data[47]
    DIRECTION OUTPUT ;
    USE SIGNAL ;
    PORT
      LAYER M6 ;
        RECT  0 28.928 0.07 28.96 ;
    END
  END w_data[47]
  PIN w_data[48]
    DIRECTION OUTPUT ;
    USE SIGNAL ;
    PORT
      LAYER M6 ;
        RECT  0 29.568 0.07 29.6 ;
    END
  END w_data[48]
  PIN w_data[49]
    DIRECTION OUTPUT ;
    USE SIGNAL ;
    PORT
      LAYER M6 ;
        RECT  0 30.208 0.07 30.24 ;
    END
  END w_data[49]
  PIN w_data[4]
    DIRECTION OUTPUT ;
    USE SIGNAL ;
    PORT
      LAYER M4 ;
        RECT  0 2.736 0.084 2.76 ;
    END
  END w_data[4]
  PIN w_data[50]
    DIRECTION OUTPUT ;
    USE SIGNAL ;
    PORT
      LAYER M6 ;
        RECT  0 30.784 0.07 30.816 ;
    END
  END w_data[50]
  PIN w_data[51]
    DIRECTION OUTPUT ;
    USE SIGNAL ;
    PORT
      LAYER M6 ;
        RECT  0 31.424 0.07 31.456 ;
    END
  END w_data[51]
  PIN w_data[52]
    DIRECTION OUTPUT ;
    USE SIGNAL ;
    PORT
      LAYER M6 ;
        RECT  0 32 0.07 32.032 ;
    END
  END w_data[52]
  PIN w_data[53]
    DIRECTION OUTPUT ;
    USE SIGNAL ;
    PORT
      LAYER M6 ;
        RECT  0 32.64 0.07 32.672 ;
    END
  END w_data[53]
  PIN w_data[54]
    DIRECTION OUTPUT ;
    USE SIGNAL ;
    PORT
      LAYER M6 ;
        RECT  0 33.216 0.07 33.248 ;
    END
  END w_data[54]
  PIN w_data[55]
    DIRECTION OUTPUT ;
    USE SIGNAL ;
    PORT
      LAYER M6 ;
        RECT  0 33.856 0.07 33.888 ;
    END
  END w_data[55]
  PIN w_data[56]
    DIRECTION OUTPUT ;
    USE SIGNAL ;
    PORT
      LAYER M6 ;
        RECT  0 34.432 0.07 34.464 ;
    END
  END w_data[56]
  PIN w_data[57]
    DIRECTION OUTPUT ;
    USE SIGNAL ;
    PORT
      LAYER M6 ;
        RECT  0 35.072 0.07 35.104 ;
    END
  END w_data[57]
  PIN w_data[58]
    DIRECTION OUTPUT ;
    USE SIGNAL ;
    PORT
      LAYER M6 ;
        RECT  0 35.648 0.07 35.68 ;
    END
  END w_data[58]
  PIN w_data[59]
    DIRECTION OUTPUT ;
    USE SIGNAL ;
    PORT
      LAYER M6 ;
        RECT  0 36.288 0.07 36.32 ;
    END
  END w_data[59]
  PIN w_data[5]
    DIRECTION OUTPUT ;
    USE SIGNAL ;
    PORT
      LAYER M4 ;
        RECT  0 3.36 0.084 3.384 ;
    END
  END w_data[5]
  PIN w_data[60]
    DIRECTION OUTPUT ;
    USE SIGNAL ;
    PORT
      LAYER M6 ;
        RECT  0 36.864 0.07 36.896 ;
    END
  END w_data[60]
  PIN w_data[61]
    DIRECTION OUTPUT ;
    USE SIGNAL ;
    PORT
      LAYER M6 ;
        RECT  0 37.504 0.07 37.536 ;
    END
  END w_data[61]
  PIN w_data[62]
    DIRECTION OUTPUT ;
    USE SIGNAL ;
    PORT
      LAYER M6 ;
        RECT  0 38.08 0.07 38.112 ;
    END
  END w_data[62]
  PIN w_data[63]
    DIRECTION OUTPUT ;
    USE SIGNAL ;
    PORT
      LAYER M6 ;
        RECT  0 38.72 0.07 38.752 ;
    END
  END w_data[63]
  PIN w_data[64]
    DIRECTION OUTPUT ;
    USE SIGNAL ;
    PORT
      LAYER M4 ;
        RECT  0 39.312 0.084 39.336 ;
    END
  END w_data[64]
  PIN w_data[65]
    DIRECTION OUTPUT ;
    USE SIGNAL ;
    PORT
      LAYER M4 ;
        RECT  0 39.936 0.084 39.96 ;
    END
  END w_data[65]
  PIN w_data[66]
    DIRECTION OUTPUT ;
    USE SIGNAL ;
    PORT
      LAYER M4 ;
        RECT  0 40.56 0.084 40.584 ;
    END
  END w_data[66]
  PIN w_data[67]
    DIRECTION OUTPUT ;
    USE SIGNAL ;
    PORT
      LAYER M4 ;
        RECT  0 41.184 0.084 41.208 ;
    END
  END w_data[67]
  PIN w_data[68]
    DIRECTION OUTPUT ;
    USE SIGNAL ;
    PORT
      LAYER M4 ;
        RECT  0 41.76 0.084 41.784 ;
    END
  END w_data[68]
  PIN w_data[69]
    DIRECTION OUTPUT ;
    USE SIGNAL ;
    PORT
      LAYER M4 ;
        RECT  0 42.384 0.084 42.408 ;
    END
  END w_data[69]
  PIN w_data[6]
    DIRECTION OUTPUT ;
    USE SIGNAL ;
    PORT
      LAYER M4 ;
        RECT  0 3.936 0.084 3.96 ;
    END
  END w_data[6]
  PIN w_data[70]
    DIRECTION OUTPUT ;
    USE SIGNAL ;
    PORT
      LAYER M4 ;
        RECT  0 43.008 0.084 43.032 ;
    END
  END w_data[70]
  PIN w_data[71]
    DIRECTION OUTPUT ;
    USE SIGNAL ;
    PORT
      LAYER M4 ;
        RECT  0 43.584 0.084 43.608 ;
    END
  END w_data[71]
  PIN w_data[72]
    DIRECTION OUTPUT ;
    USE SIGNAL ;
    PORT
      LAYER M4 ;
        RECT  0 44.208 0.084 44.232 ;
    END
  END w_data[72]
  PIN w_data[73]
    DIRECTION OUTPUT ;
    USE SIGNAL ;
    PORT
      LAYER M4 ;
        RECT  0 44.832 0.084 44.856 ;
    END
  END w_data[73]
  PIN w_data[74]
    DIRECTION OUTPUT ;
    USE SIGNAL ;
    PORT
      LAYER M4 ;
        RECT  0 45.408 0.084 45.432 ;
    END
  END w_data[74]
  PIN w_data[75]
    DIRECTION OUTPUT ;
    USE SIGNAL ;
    PORT
      LAYER M4 ;
        RECT  0 46.032 0.084 46.056 ;
    END
  END w_data[75]
  PIN w_data[76]
    DIRECTION OUTPUT ;
    USE SIGNAL ;
    PORT
      LAYER M4 ;
        RECT  0 46.656 0.084 46.68 ;
    END
  END w_data[76]
  PIN w_data[77]
    DIRECTION OUTPUT ;
    USE SIGNAL ;
    PORT
      LAYER M4 ;
        RECT  0 47.28 0.084 47.304 ;
    END
  END w_data[77]
  PIN w_data[78]
    DIRECTION OUTPUT ;
    USE SIGNAL ;
    PORT
      LAYER M4 ;
        RECT  0 47.856 0.084 47.88 ;
    END
  END w_data[78]
  PIN w_data[79]
    DIRECTION OUTPUT ;
    USE SIGNAL ;
    PORT
      LAYER M4 ;
        RECT  0 48.48 0.084 48.504 ;
    END
  END w_data[79]
  PIN w_data[7]
    DIRECTION OUTPUT ;
    USE SIGNAL ;
    PORT
      LAYER M4 ;
        RECT  0 4.56 0.084 4.584 ;
    END
  END w_data[7]
  PIN w_data[80]
    DIRECTION OUTPUT ;
    USE SIGNAL ;
    PORT
      LAYER M4 ;
        RECT  0 49.104 0.084 49.128 ;
    END
  END w_data[80]
  PIN w_data[81]
    DIRECTION OUTPUT ;
    USE SIGNAL ;
    PORT
      LAYER M4 ;
        RECT  0 49.68 0.084 49.704 ;
    END
  END w_data[81]
  PIN w_data[82]
    DIRECTION OUTPUT ;
    USE SIGNAL ;
    PORT
      LAYER M4 ;
        RECT  0 50.304 0.084 50.328 ;
    END
  END w_data[82]
  PIN w_data[83]
    DIRECTION OUTPUT ;
    USE SIGNAL ;
    PORT
      LAYER M4 ;
        RECT  0 50.928 0.084 50.952 ;
    END
  END w_data[83]
  PIN w_data[84]
    DIRECTION OUTPUT ;
    USE SIGNAL ;
    PORT
      LAYER M4 ;
        RECT  0 51.552 0.084 51.576 ;
    END
  END w_data[84]
  PIN w_data[85]
    DIRECTION OUTPUT ;
    USE SIGNAL ;
    PORT
      LAYER M4 ;
        RECT  0 52.128 0.084 52.152 ;
    END
  END w_data[85]
  PIN w_data[86]
    DIRECTION OUTPUT ;
    USE SIGNAL ;
    PORT
      LAYER M4 ;
        RECT  0 52.752 0.084 52.776 ;
    END
  END w_data[86]
  PIN w_data[87]
    DIRECTION OUTPUT ;
    USE SIGNAL ;
    PORT
      LAYER M4 ;
        RECT  0 53.376 0.084 53.4 ;
    END
  END w_data[87]
  PIN w_data[88]
    DIRECTION OUTPUT ;
    USE SIGNAL ;
    PORT
      LAYER M4 ;
        RECT  0 53.952 0.084 53.976 ;
    END
  END w_data[88]
  PIN w_data[89]
    DIRECTION OUTPUT ;
    USE SIGNAL ;
    PORT
      LAYER M4 ;
        RECT  0 54.576 0.084 54.6 ;
    END
  END w_data[89]
  PIN w_data[8]
    DIRECTION OUTPUT ;
    USE SIGNAL ;
    PORT
      LAYER M4 ;
        RECT  0 5.184 0.084 5.208 ;
    END
  END w_data[8]
  PIN w_data[90]
    DIRECTION OUTPUT ;
    USE SIGNAL ;
    PORT
      LAYER M4 ;
        RECT  0 55.2 0.084 55.224 ;
    END
  END w_data[90]
  PIN w_data[91]
    DIRECTION OUTPUT ;
    USE SIGNAL ;
    PORT
      LAYER M4 ;
        RECT  0 55.824 0.084 55.848 ;
    END
  END w_data[91]
  PIN w_data[92]
    DIRECTION OUTPUT ;
    USE SIGNAL ;
    PORT
      LAYER M4 ;
        RECT  0 56.4 0.084 56.424 ;
    END
  END w_data[92]
  PIN w_data[93]
    DIRECTION OUTPUT ;
    USE SIGNAL ;
    PORT
      LAYER M4 ;
        RECT  0 57.024 0.084 57.048 ;
    END
  END w_data[93]
  PIN w_data[94]
    DIRECTION OUTPUT ;
    USE SIGNAL ;
    PORT
      LAYER M4 ;
        RECT  0 57.648 0.084 57.672 ;
    END
  END w_data[94]
  PIN w_data[95]
    DIRECTION OUTPUT ;
    USE SIGNAL ;
    PORT
      LAYER M4 ;
        RECT  0 58.224 0.084 58.248 ;
    END
  END w_data[95]
  PIN w_data[96]
    DIRECTION OUTPUT ;
    USE SIGNAL ;
    PORT
      LAYER M6 ;
        RECT  0 58.816 0.07 58.848 ;
    END
  END w_data[96]
  PIN w_data[97]
    DIRECTION OUTPUT ;
    USE SIGNAL ;
    PORT
      LAYER M6 ;
        RECT  0 59.456 0.07 59.488 ;
    END
  END w_data[97]
  PIN w_data[98]
    DIRECTION OUTPUT ;
    USE SIGNAL ;
    PORT
      LAYER M6 ;
        RECT  0 60.096 0.07 60.128 ;
    END
  END w_data[98]
  PIN w_data[99]
    DIRECTION OUTPUT ;
    USE SIGNAL ;
    PORT
      LAYER M6 ;
        RECT  0 60.672 0.07 60.704 ;
    END
  END w_data[99]
  PIN w_data[9]
    DIRECTION OUTPUT ;
    USE SIGNAL ;
    PORT
      LAYER M4 ;
        RECT  0 5.76 0.084 5.784 ;
    END
  END w_data[9]
  PIN w_room
    DIRECTION INPUT ;
    USE SIGNAL ;
    PORT
      LAYER M4 ;
        RECT  0 156.432 0.084 156.456 ;
    END
  END w_room
  PIN w_sec[0]
    DIRECTION OUTPUT ;
    USE SIGNAL ;
    PORT
      LAYER M4 ;
        RECT  0 157.056 0.084 157.08 ;
    END
  END w_sec[0]
  PIN w_sec[10]
    DIRECTION OUTPUT ;
    USE SIGNAL ;
    PORT
      LAYER M4 ;
        RECT  0 163.152 0.084 163.176 ;
    END
  END w_sec[10]
  PIN w_sec[11]
    DIRECTION OUTPUT ;
    USE SIGNAL ;
    PORT
      LAYER M4 ;
        RECT  0 163.776 0.084 163.8 ;
    END
  END w_sec[11]
  PIN w_sec[12]
    DIRECTION OUTPUT ;
    USE SIGNAL ;
    PORT
      LAYER M4 ;
        RECT  0 164.352 0.084 164.376 ;
    END
  END w_sec[12]
  PIN w_sec[13]
    DIRECTION OUTPUT ;
    USE SIGNAL ;
    PORT
      LAYER M4 ;
        RECT  0 164.976 0.084 165 ;
    END
  END w_sec[13]
  PIN w_sec[14]
    DIRECTION OUTPUT ;
    USE SIGNAL ;
    PORT
      LAYER M4 ;
        RECT  0 165.6 0.084 165.624 ;
    END
  END w_sec[14]
  PIN w_sec[15]
    DIRECTION OUTPUT ;
    USE SIGNAL ;
    PORT
      LAYER M4 ;
        RECT  0 166.224 0.084 166.248 ;
    END
  END w_sec[15]
  PIN w_sec[16]
    DIRECTION OUTPUT ;
    USE SIGNAL ;
    PORT
      LAYER M4 ;
        RECT  0 166.8 0.084 166.824 ;
    END
  END w_sec[16]
  PIN w_sec[17]
    DIRECTION OUTPUT ;
    USE SIGNAL ;
    PORT
      LAYER M4 ;
        RECT  0 167.424 0.084 167.448 ;
    END
  END w_sec[17]
  PIN w_sec[18]
    DIRECTION OUTPUT ;
    USE SIGNAL ;
    PORT
      LAYER M4 ;
        RECT  0 168.048 0.084 168.072 ;
    END
  END w_sec[18]
  PIN w_sec[19]
    DIRECTION OUTPUT ;
    USE SIGNAL ;
    PORT
      LAYER M4 ;
        RECT  0 168.624 0.084 168.648 ;
    END
  END w_sec[19]
  PIN w_sec[1]
    DIRECTION OUTPUT ;
    USE SIGNAL ;
    PORT
      LAYER M4 ;
        RECT  0 157.68 0.084 157.704 ;
    END
  END w_sec[1]
  PIN w_sec[20]
    DIRECTION OUTPUT ;
    USE SIGNAL ;
    PORT
      LAYER M4 ;
        RECT  0 169.248 0.084 169.272 ;
    END
  END w_sec[20]
  PIN w_sec[21]
    DIRECTION OUTPUT ;
    USE SIGNAL ;
    PORT
      LAYER M4 ;
        RECT  0 169.872 0.084 169.896 ;
    END
  END w_sec[21]
  PIN w_sec[22]
    DIRECTION OUTPUT ;
    USE SIGNAL ;
    PORT
      LAYER M4 ;
        RECT  0 170.496 0.084 170.52 ;
    END
  END w_sec[22]
  PIN w_sec[23]
    DIRECTION OUTPUT ;
    USE SIGNAL ;
    PORT
      LAYER M4 ;
        RECT  0 171.072 0.084 171.096 ;
    END
  END w_sec[23]
  PIN w_sec[2]
    DIRECTION OUTPUT ;
    USE SIGNAL ;
    PORT
      LAYER M4 ;
        RECT  0 158.256 0.084 158.28 ;
    END
  END w_sec[2]
  PIN w_sec[3]
    DIRECTION OUTPUT ;
    USE SIGNAL ;
    PORT
      LAYER M4 ;
        RECT  0 158.88 0.084 158.904 ;
    END
  END w_sec[3]
  PIN w_sec[4]
    DIRECTION OUTPUT ;
    USE SIGNAL ;
    PORT
      LAYER M4 ;
        RECT  0 159.504 0.084 159.528 ;
    END
  END w_sec[4]
  PIN w_sec[5]
    DIRECTION OUTPUT ;
    USE SIGNAL ;
    PORT
      LAYER M4 ;
        RECT  0 160.128 0.084 160.152 ;
    END
  END w_sec[5]
  PIN w_sec[6]
    DIRECTION OUTPUT ;
    USE SIGNAL ;
    PORT
      LAYER M4 ;
        RECT  0 160.704 0.084 160.728 ;
    END
  END w_sec[6]
  PIN w_sec[7]
    DIRECTION OUTPUT ;
    USE SIGNAL ;
    PORT
      LAYER M4 ;
        RECT  0 161.328 0.084 161.352 ;
    END
  END w_sec[7]
  PIN w_sec[8]
    DIRECTION OUTPUT ;
    USE SIGNAL ;
    PORT
      LAYER M4 ;
        RECT  0 161.952 0.084 161.976 ;
    END
  END w_sec[8]
  PIN w_sec[9]
    DIRECTION OUTPUT ;
    USE SIGNAL ;
    PORT
      LAYER M4 ;
        RECT  0 162.528 0.084 162.552 ;
    END
  END w_sec[9]
  PIN w_tag[0]
    DIRECTION OUTPUT ;
    USE SIGNAL ;
    PORT
      LAYER M4 ;
        RECT  0 171.696 0.084 171.72 ;
    END
  END w_tag[0]
  PIN w_tag[1]
    DIRECTION OUTPUT ;
    USE SIGNAL ;
    PORT
      LAYER M4 ;
        RECT  0 172.32 0.084 172.344 ;
    END
  END w_tag[1]
  PIN w_tag[2]
    DIRECTION OUTPUT ;
    USE SIGNAL ;
    PORT
      LAYER M4 ;
        RECT  0 172.896 0.084 172.92 ;
    END
  END w_tag[2]
  PIN w_tag[3]
    DIRECTION OUTPUT ;
    USE SIGNAL ;
    PORT
      LAYER M4 ;
        RECT  0 173.52 0.084 173.544 ;
    END
  END w_tag[3]
  PIN w_tag[4]
    DIRECTION OUTPUT ;
    USE SIGNAL ;
    PORT
      LAYER M4 ;
        RECT  0 174.144 0.084 174.168 ;
    END
  END w_tag[4]
  PIN w_tag[5]
    DIRECTION OUTPUT ;
    USE SIGNAL ;
    PORT
      LAYER M4 ;
        RECT  0 174.72 0.084 174.744 ;
    END
  END w_tag[5]
  PIN w_tag[6]
    DIRECTION OUTPUT ;
    USE SIGNAL ;
    PORT
      LAYER M4 ;
        RECT  0 175.344 0.084 175.368 ;
    END
  END w_tag[6]
  PIN w_tag[7]
    DIRECTION OUTPUT ;
    USE SIGNAL ;
    PORT
      LAYER M6 ;
        RECT  0 175.936 0.07 175.968 ;
    END
  END w_tag[7]
  PIN w_tag[8]
    DIRECTION OUTPUT ;
    USE SIGNAL ;
    PORT
      LAYER M6 ;
        RECT  0 176.576 0.07 176.608 ;
    END
  END w_tag[8]
  PIN w_v
    DIRECTION OUTPUT ;
    USE SIGNAL ;
    PORT
      LAYER M6 ;
        RECT  0 177.152 0.07 177.184 ;
    END
  END w_v
  PIN wd_tag[0]
    DIRECTION INPUT ;
    USE SIGNAL ;
    PORT
      LAYER M6 ;
        RECT  0 177.792 0.07 177.824 ;
    END
  END wd_tag[0]
  PIN wd_tag[1]
    DIRECTION INPUT ;
    USE SIGNAL ;
    PORT
      LAYER M6 ;
        RECT  0 178.368 0.07 178.4 ;
    END
  END wd_tag[1]
  PIN wd_tag[2]
    DIRECTION INPUT ;
    USE SIGNAL ;
    PORT
      LAYER M6 ;
        RECT  0 179.008 0.07 179.04 ;
    END
  END wd_tag[2]
  PIN wd_tag[3]
    DIRECTION INPUT ;
    USE SIGNAL ;
    PORT
      LAYER M6 ;
        RECT  0 179.648 0.07 179.68 ;
    END
  END wd_tag[3]
  PIN wd_tag[4]
    DIRECTION INPUT ;
    USE SIGNAL ;
    PORT
      LAYER M6 ;
        RECT  0 180.224 0.07 180.256 ;
    END
  END wd_tag[4]
  PIN wd_tag[5]
    DIRECTION INPUT ;
    USE SIGNAL ;
    PORT
      LAYER M6 ;
        RECT  0 180.864 0.07 180.896 ;
    END
  END wd_tag[5]
  PIN wd_tag[6]
    DIRECTION INPUT ;
    USE SIGNAL ;
    PORT
      LAYER M6 ;
        RECT  0 181.44 0.07 181.472 ;
    END
  END wd_tag[6]
  PIN wd_tag[7]
    DIRECTION INPUT ;
    USE SIGNAL ;
    PORT
      LAYER M6 ;
        RECT  0 182.08 0.07 182.112 ;
    END
  END wd_tag[7]
  PIN wd_tag[8]
    DIRECTION INPUT ;
    USE SIGNAL ;
    PORT
      LAYER M6 ;
        RECT  0 182.656 0.07 182.688 ;
    END
  END wd_tag[8]
  PIN wd_v
    DIRECTION INPUT ;
    USE SIGNAL ;
    PORT
      LAYER M6 ;
        RECT  0 183.296 0.07 183.328 ;
    END
  END wd_v
  PIN VDD
    DIRECTION INOUT ;
    USE POWER ;
    PORT
      LAYER M6 ;
        RECT  2.16 181.113 84.24 181.401 ;
        RECT  2.16 175.713 84.24 176.001 ;
        RECT  2.16 170.313 84.24 170.601 ;
        RECT  2.16 164.913 84.24 165.201 ;
        RECT  2.16 159.513 84.24 159.801 ;
        RECT  2.16 154.113 84.24 154.401 ;
        RECT  2.16 148.713 84.24 149.001 ;
        RECT  2.16 143.313 84.24 143.601 ;
        RECT  2.16 137.913 84.24 138.201 ;
        RECT  2.16 132.513 84.24 132.801 ;
        RECT  2.16 127.113 84.24 127.401 ;
        RECT  2.16 121.713 84.24 122.001 ;
        RECT  2.16 116.313 84.24 116.601 ;
        RECT  2.16 110.913 84.24 111.201 ;
        RECT  2.16 105.513 84.24 105.801 ;
        RECT  2.16 100.113 84.24 100.401 ;
        RECT  2.16 94.713 84.24 95.001 ;
        RECT  2.16 89.313 84.24 89.601 ;
        RECT  2.16 83.913 84.24 84.201 ;
        RECT  2.16 78.513 84.24 78.801 ;
        RECT  2.16 73.113 84.24 73.401 ;
        RECT  2.16 67.713 84.24 68.001 ;
        RECT  2.16 62.313 84.24 62.601 ;
        RECT  2.16 56.913 84.24 57.201 ;
        RECT  2.16 51.513 84.24 51.801 ;
        RECT  2.16 46.113 84.24 46.401 ;
        RECT  2.16 40.713 84.24 41.001 ;
        RECT  2.16 35.313 84.24 35.601 ;
        RECT  2.16 29.913 84.24 30.201 ;
        RECT  2.16 24.513 84.24 24.801 ;
        RECT  2.16 19.113 84.24 19.401 ;
        RECT  2.16 13.713 84.24 14.001 ;
        RECT  2.16 8.313 84.24 8.601 ;
        RECT  2.16 2.913 84.24 3.201 ;
    END
  END VDD
  PIN VSS
    DIRECTION INOUT ;
    USE GROUND ;
    PORT
      LAYER M6 ;
        RECT  2.16 180.729 84.24 181.017 ;
        RECT  2.16 175.329 84.24 175.617 ;
        RECT  2.16 169.929 84.24 170.217 ;
        RECT  2.16 164.529 84.24 164.817 ;
        RECT  2.16 159.129 84.24 159.417 ;
        RECT  2.16 153.729 84.24 154.017 ;
        RECT  2.16 148.329 84.24 148.617 ;
        RECT  2.16 142.929 84.24 143.217 ;
        RECT  2.16 137.529 84.24 137.817 ;
        RECT  2.16 132.129 84.24 132.417 ;
        RECT  2.16 126.729 84.24 127.017 ;
        RECT  2.16 121.329 84.24 121.617 ;
        RECT  2.16 115.929 84.24 116.217 ;
        RECT  2.16 110.529 84.24 110.817 ;
        RECT  2.16 105.129 84.24 105.417 ;
        RECT  2.16 99.729 84.24 100.017 ;
        RECT  2.16 94.329 84.24 94.617 ;
        RECT  2.16 88.929 84.24 89.217 ;
        RECT  2.16 83.529 84.24 83.817 ;
        RECT  2.16 78.129 84.24 78.417 ;
        RECT  2.16 72.729 84.24 73.017 ;
        RECT  2.16 67.329 84.24 67.617 ;
        RECT  2.16 61.929 84.24 62.217 ;
        RECT  2.16 56.529 84.24 56.817 ;
        RECT  2.16 51.129 84.24 51.417 ;
        RECT  2.16 45.729 84.24 46.017 ;
        RECT  2.16 40.329 84.24 40.617 ;
        RECT  2.16 34.929 84.24 35.217 ;
        RECT  2.16 29.529 84.24 29.817 ;
        RECT  2.16 24.129 84.24 24.417 ;
        RECT  2.16 18.729 84.24 19.017 ;
        RECT  2.16 13.329 84.24 13.617 ;
        RECT  2.16 7.929 84.24 8.217 ;
        RECT  2.16 2.529 84.24 2.817 ;
    END
  END VSS
  OBS
    LAYER RVTN ;
     RECT  2.16 2.16 84.24 2.295 ;
     RECT  2.16 2.565 84.24 2.835 ;
     RECT  2.16 3.105 84.24 3.375 ;
     RECT  2.16 3.645 84.24 3.915 ;
     RECT  2.16 4.185 84.24 4.455 ;
     RECT  2.16 4.725 84.24 4.995 ;
     RECT  2.16 5.265 84.24 5.535 ;
     RECT  2.16 5.805 84.24 6.075 ;
     RECT  2.16 6.345 84.24 6.615 ;
     RECT  2.16 6.885 84.24 7.155 ;
     RECT  2.16 7.425 84.24 7.695 ;
     RECT  2.16 7.965 84.24 8.235 ;
     RECT  2.16 8.505 84.24 8.775 ;
     RECT  2.16 9.045 84.24 9.315 ;
     RECT  2.16 9.585 84.24 9.855 ;
     RECT  2.16 10.125 84.24 10.395 ;
     RECT  2.16 10.665 84.24 10.935 ;
     RECT  2.16 11.205 84.24 11.475 ;
     RECT  2.16 11.745 84.24 12.015 ;
     RECT  2.16 12.285 84.24 12.555 ;
     RECT  2.16 12.825 84.24 13.095 ;
     RECT  2.16 13.365 84.24 13.635 ;
     RECT  2.16 13.905 84.24 14.175 ;
     RECT  2.16 14.445 84.24 14.715 ;
     RECT  2.16 14.985 84.24 15.255 ;
     RECT  2.16 15.525 84.24 15.795 ;
     RECT  2.16 16.065 84.24 16.335 ;
     RECT  2.16 16.605 84.24 16.875 ;
     RECT  2.16 17.145 84.24 17.415 ;
     RECT  2.16 17.685 84.24 17.955 ;
     RECT  2.16 18.225 84.24 18.495 ;
     RECT  2.16 18.765 84.24 19.035 ;
     RECT  2.16 19.305 84.24 19.575 ;
     RECT  2.16 19.845 84.24 20.115 ;
     RECT  2.16 20.385 84.24 20.655 ;
     RECT  2.16 20.925 84.24 21.195 ;
     RECT  2.16 21.465 84.24 21.735 ;
     RECT  2.16 22.005 84.24 22.275 ;
     RECT  2.16 22.545 84.24 22.815 ;
     RECT  2.16 23.085 84.24 23.355 ;
     RECT  2.16 23.625 84.24 23.895 ;
     RECT  2.16 24.165 84.24 24.435 ;
     RECT  2.16 24.705 84.24 24.975 ;
     RECT  2.16 25.245 84.24 25.515 ;
     RECT  2.16 25.785 84.24 26.055 ;
     RECT  2.16 26.325 84.24 26.595 ;
     RECT  2.16 26.865 84.24 27.135 ;
     RECT  2.16 27.405 84.24 27.675 ;
     RECT  2.16 27.945 84.24 28.215 ;
     RECT  2.16 28.485 84.24 28.755 ;
     RECT  2.16 29.025 84.24 29.295 ;
     RECT  2.16 29.565 84.24 29.835 ;
     RECT  2.16 30.105 84.24 30.375 ;
     RECT  2.16 30.645 84.24 30.915 ;
     RECT  2.16 31.185 84.24 31.455 ;
     RECT  2.16 31.725 84.24 31.995 ;
     RECT  2.16 32.265 84.24 32.535 ;
     RECT  2.16 32.805 84.24 33.075 ;
     RECT  2.16 33.345 84.24 33.615 ;
     RECT  2.16 33.885 84.24 34.155 ;
     RECT  2.16 34.425 84.24 34.695 ;
     RECT  2.16 34.965 84.24 35.235 ;
     RECT  2.16 35.505 84.24 35.775 ;
     RECT  2.16 36.045 84.24 36.315 ;
     RECT  2.16 36.585 84.24 36.855 ;
     RECT  2.16 37.125 84.24 37.395 ;
     RECT  2.16 37.665 84.24 37.935 ;
     RECT  2.16 38.205 84.24 38.475 ;
     RECT  2.16 38.745 84.24 39.015 ;
     RECT  2.16 39.285 84.24 39.555 ;
     RECT  2.16 39.825 84.24 40.095 ;
     RECT  2.16 40.365 84.24 40.635 ;
     RECT  2.16 40.905 84.24 41.175 ;
     RECT  2.16 41.445 84.24 41.715 ;
     RECT  2.16 41.985 84.24 42.255 ;
     RECT  2.16 42.525 84.24 42.795 ;
     RECT  2.16 43.065 84.24 43.335 ;
     RECT  2.16 43.605 84.24 43.875 ;
     RECT  2.16 44.145 84.24 44.415 ;
     RECT  2.16 44.685 84.24 44.955 ;
     RECT  2.16 45.225 84.24 45.495 ;
     RECT  2.16 45.765 84.24 46.035 ;
     RECT  2.16 46.305 84.24 46.575 ;
     RECT  2.16 46.845 84.24 47.115 ;
     RECT  2.16 47.385 84.24 47.655 ;
     RECT  2.16 47.925 84.24 48.195 ;
     RECT  2.16 48.465 84.24 48.735 ;
     RECT  2.16 49.005 84.24 49.275 ;
     RECT  2.16 49.545 84.24 49.815 ;
     RECT  2.16 50.085 84.24 50.355 ;
     RECT  2.16 50.625 84.24 50.895 ;
     RECT  2.16 51.165 84.24 51.435 ;
     RECT  2.16 51.705 84.24 51.975 ;
     RECT  2.16 52.245 84.24 52.515 ;
     RECT  2.16 52.785 84.24 53.055 ;
     RECT  2.16 53.325 84.24 53.595 ;
     RECT  2.16 53.865 84.24 54.135 ;
     RECT  2.16 54.405 84.24 54.675 ;
     RECT  2.16 54.945 84.24 55.215 ;
     RECT  2.16 55.485 84.24 55.755 ;
     RECT  2.16 56.025 84.24 56.295 ;
     RECT  2.16 56.565 84.24 56.835 ;
     RECT  2.16 57.105 84.24 57.375 ;
     RECT  2.16 57.645 84.24 57.915 ;
     RECT  2.16 58.185 84.24 58.455 ;
     RECT  2.16 58.725 84.24 58.995 ;
     RECT  2.16 59.265 84.24 59.535 ;
     RECT  2.16 59.805 84.24 60.075 ;
     RECT  2.16 60.345 84.24 60.615 ;
     RECT  2.16 60.885 84.24 61.155 ;
     RECT  2.16 61.425 84.24 61.695 ;
     RECT  2.16 61.965 84.24 62.235 ;
     RECT  2.16 62.505 84.24 62.775 ;
     RECT  2.16 63.045 84.24 63.315 ;
     RECT  2.16 63.585 84.24 63.855 ;
     RECT  2.16 64.125 84.24 64.395 ;
     RECT  2.16 64.665 84.24 64.935 ;
     RECT  2.16 65.205 84.24 65.475 ;
     RECT  2.16 65.745 84.24 66.015 ;
     RECT  2.16 66.285 84.24 66.555 ;
     RECT  2.16 66.825 84.24 67.095 ;
     RECT  2.16 67.365 84.24 67.635 ;
     RECT  2.16 67.905 84.24 68.175 ;
     RECT  2.16 68.445 84.24 68.715 ;
     RECT  2.16 68.985 84.24 69.255 ;
     RECT  2.16 69.525 84.24 69.795 ;
     RECT  2.16 70.065 84.24 70.335 ;
     RECT  2.16 70.605 84.24 70.875 ;
     RECT  2.16 71.145 84.24 71.415 ;
     RECT  2.16 71.685 84.24 71.955 ;
     RECT  2.16 72.225 84.24 72.495 ;
     RECT  2.16 72.765 84.24 73.035 ;
     RECT  2.16 73.305 84.24 73.575 ;
     RECT  2.16 73.845 84.24 74.115 ;
     RECT  2.16 74.385 84.24 74.655 ;
     RECT  2.16 74.925 84.24 75.195 ;
     RECT  2.16 75.465 84.24 75.735 ;
     RECT  2.16 76.005 84.24 76.275 ;
     RECT  2.16 76.545 84.24 76.815 ;
     RECT  2.16 77.085 84.24 77.355 ;
     RECT  2.16 77.625 84.24 77.895 ;
     RECT  2.16 78.165 84.24 78.435 ;
     RECT  2.16 78.705 84.24 78.975 ;
     RECT  2.16 79.245 84.24 79.515 ;
     RECT  2.16 79.785 84.24 80.055 ;
     RECT  2.16 80.325 84.24 80.595 ;
     RECT  2.16 80.865 84.24 81.135 ;
     RECT  2.16 81.405 84.24 81.675 ;
     RECT  2.16 81.945 84.24 82.215 ;
     RECT  2.16 82.485 84.24 82.755 ;
     RECT  2.16 83.025 84.24 83.295 ;
     RECT  2.16 83.565 84.24 83.835 ;
     RECT  2.16 84.105 84.24 84.375 ;
     RECT  2.16 84.645 84.24 84.915 ;
     RECT  2.16 85.185 84.24 85.455 ;
     RECT  2.16 85.725 84.24 85.995 ;
     RECT  2.16 86.265 84.24 86.535 ;
     RECT  2.16 86.805 84.24 87.075 ;
     RECT  2.16 87.345 84.24 87.615 ;
     RECT  2.16 87.885 84.24 88.155 ;
     RECT  2.16 88.425 84.24 88.695 ;
     RECT  2.16 88.965 84.24 89.235 ;
     RECT  2.16 89.505 84.24 89.775 ;
     RECT  2.16 90.045 84.24 90.315 ;
     RECT  2.16 90.585 84.24 90.855 ;
     RECT  2.16 91.125 84.24 91.395 ;
     RECT  2.16 91.665 84.24 91.935 ;
     RECT  2.16 92.205 84.24 92.475 ;
     RECT  2.16 92.745 84.24 93.015 ;
     RECT  2.16 93.285 84.24 93.555 ;
     RECT  2.16 93.825 84.24 94.095 ;
     RECT  2.16 94.365 84.24 94.635 ;
     RECT  2.16 94.905 84.24 95.175 ;
     RECT  2.16 95.445 84.24 95.715 ;
     RECT  2.16 95.985 84.24 96.255 ;
     RECT  2.16 96.525 84.24 96.795 ;
     RECT  2.16 97.065 84.24 97.335 ;
     RECT  2.16 97.605 84.24 97.875 ;
     RECT  2.16 98.145 84.24 98.415 ;
     RECT  2.16 98.685 84.24 98.955 ;
     RECT  2.16 99.225 84.24 99.495 ;
     RECT  2.16 99.765 84.24 100.035 ;
     RECT  2.16 100.305 84.24 100.575 ;
     RECT  2.16 100.845 84.24 101.115 ;
     RECT  2.16 101.385 84.24 101.655 ;
     RECT  2.16 101.925 84.24 102.195 ;
     RECT  2.16 102.465 84.24 102.735 ;
     RECT  2.16 103.005 84.24 103.275 ;
     RECT  2.16 103.545 84.24 103.815 ;
     RECT  2.16 104.085 84.24 104.355 ;
     RECT  2.16 104.625 84.24 104.895 ;
     RECT  2.16 105.165 84.24 105.435 ;
     RECT  2.16 105.705 84.24 105.975 ;
     RECT  2.16 106.245 84.24 106.515 ;
     RECT  2.16 106.785 84.24 107.055 ;
     RECT  2.16 107.325 84.24 107.595 ;
     RECT  2.16 107.865 84.24 108.135 ;
     RECT  2.16 108.405 84.24 108.675 ;
     RECT  2.16 108.945 84.24 109.215 ;
     RECT  2.16 109.485 84.24 109.755 ;
     RECT  2.16 110.025 84.24 110.295 ;
     RECT  2.16 110.565 84.24 110.835 ;
     RECT  2.16 111.105 84.24 111.375 ;
     RECT  2.16 111.645 84.24 111.915 ;
     RECT  2.16 112.185 84.24 112.455 ;
     RECT  2.16 112.725 84.24 112.995 ;
     RECT  2.16 113.265 84.24 113.535 ;
     RECT  2.16 113.805 84.24 114.075 ;
     RECT  2.16 114.345 84.24 114.615 ;
     RECT  2.16 114.885 84.24 115.155 ;
     RECT  2.16 115.425 84.24 115.695 ;
     RECT  2.16 115.965 84.24 116.235 ;
     RECT  2.16 116.505 84.24 116.775 ;
     RECT  2.16 117.045 84.24 117.315 ;
     RECT  2.16 117.585 84.24 117.855 ;
     RECT  2.16 118.125 84.24 118.395 ;
     RECT  2.16 118.665 84.24 118.935 ;
     RECT  2.16 119.205 84.24 119.475 ;
     RECT  2.16 119.745 84.24 120.015 ;
     RECT  2.16 120.285 84.24 120.555 ;
     RECT  2.16 120.825 84.24 121.095 ;
     RECT  2.16 121.365 84.24 121.635 ;
     RECT  2.16 121.905 84.24 122.175 ;
     RECT  2.16 122.445 84.24 122.715 ;
     RECT  2.16 122.985 84.24 123.255 ;
     RECT  2.16 123.525 84.24 123.795 ;
     RECT  2.16 124.065 84.24 124.335 ;
     RECT  2.16 124.605 84.24 124.875 ;
     RECT  2.16 125.145 84.24 125.415 ;
     RECT  2.16 125.685 84.24 125.955 ;
     RECT  2.16 126.225 84.24 126.495 ;
     RECT  2.16 126.765 84.24 127.035 ;
     RECT  2.16 127.305 84.24 127.575 ;
     RECT  2.16 127.845 84.24 128.115 ;
     RECT  2.16 128.385 84.24 128.655 ;
     RECT  2.16 128.925 84.24 129.195 ;
     RECT  2.16 129.465 84.24 129.735 ;
     RECT  2.16 130.005 84.24 130.275 ;
     RECT  2.16 130.545 84.24 130.815 ;
     RECT  2.16 131.085 84.24 131.355 ;
     RECT  2.16 131.625 84.24 131.895 ;
     RECT  2.16 132.165 84.24 132.435 ;
     RECT  2.16 132.705 84.24 132.975 ;
     RECT  2.16 133.245 84.24 133.515 ;
     RECT  2.16 133.785 84.24 134.055 ;
     RECT  2.16 134.325 84.24 134.595 ;
     RECT  2.16 134.865 84.24 135.135 ;
     RECT  2.16 135.405 84.24 135.675 ;
     RECT  2.16 135.945 84.24 136.215 ;
     RECT  2.16 136.485 84.24 136.755 ;
     RECT  2.16 137.025 84.24 137.295 ;
     RECT  2.16 137.565 84.24 137.835 ;
     RECT  2.16 138.105 84.24 138.375 ;
     RECT  2.16 138.645 84.24 138.915 ;
     RECT  2.16 139.185 84.24 139.455 ;
     RECT  2.16 139.725 84.24 139.995 ;
     RECT  2.16 140.265 84.24 140.535 ;
     RECT  2.16 140.805 84.24 141.075 ;
     RECT  2.16 141.345 84.24 141.615 ;
     RECT  2.16 141.885 84.24 142.155 ;
     RECT  2.16 142.425 84.24 142.695 ;
     RECT  2.16 142.965 84.24 143.235 ;
     RECT  2.16 143.505 84.24 143.775 ;
     RECT  2.16 144.045 84.24 144.315 ;
     RECT  2.16 144.585 84.24 144.855 ;
     RECT  2.16 145.125 84.24 145.395 ;
     RECT  2.16 145.665 84.24 145.935 ;
     RECT  2.16 146.205 84.24 146.475 ;
     RECT  2.16 146.745 84.24 147.015 ;
     RECT  2.16 147.285 84.24 147.555 ;
     RECT  2.16 147.825 84.24 148.095 ;
     RECT  2.16 148.365 84.24 148.635 ;
     RECT  2.16 148.905 84.24 149.175 ;
     RECT  2.16 149.445 84.24 149.715 ;
     RECT  2.16 149.985 84.24 150.255 ;
     RECT  2.16 150.525 84.24 150.795 ;
     RECT  2.16 151.065 84.24 151.335 ;
     RECT  2.16 151.605 84.24 151.875 ;
     RECT  2.16 152.145 84.24 152.415 ;
     RECT  2.16 152.685 84.24 152.955 ;
     RECT  2.16 153.225 84.24 153.495 ;
     RECT  2.16 153.765 84.24 154.035 ;
     RECT  2.16 154.305 84.24 154.575 ;
     RECT  2.16 154.845 84.24 155.115 ;
     RECT  2.16 155.385 84.24 155.655 ;
     RECT  2.16 155.925 84.24 156.195 ;
     RECT  2.16 156.465 84.24 156.735 ;
     RECT  2.16 157.005 84.24 157.275 ;
     RECT  2.16 157.545 84.24 157.815 ;
     RECT  2.16 158.085 84.24 158.355 ;
     RECT  2.16 158.625 84.24 158.895 ;
     RECT  2.16 159.165 84.24 159.435 ;
     RECT  2.16 159.705 84.24 159.975 ;
     RECT  2.16 160.245 84.24 160.515 ;
     RECT  2.16 160.785 84.24 161.055 ;
     RECT  2.16 161.325 84.24 161.595 ;
     RECT  2.16 161.865 84.24 162.135 ;
     RECT  2.16 162.405 84.24 162.675 ;
     RECT  2.16 162.945 84.24 163.215 ;
     RECT  2.16 163.485 84.24 163.755 ;
     RECT  2.16 164.025 84.24 164.295 ;
     RECT  2.16 164.565 84.24 164.835 ;
     RECT  2.16 165.105 84.24 165.375 ;
     RECT  2.16 165.645 84.24 165.915 ;
     RECT  2.16 166.185 84.24 166.455 ;
     RECT  2.16 166.725 84.24 166.995 ;
     RECT  2.16 167.265 84.24 167.535 ;
     RECT  2.16 167.805 84.24 168.075 ;
     RECT  2.16 168.345 84.24 168.615 ;
     RECT  2.16 168.885 84.24 169.155 ;
     RECT  2.16 169.425 84.24 169.695 ;
     RECT  2.16 169.965 84.24 170.235 ;
     RECT  2.16 170.505 84.24 170.775 ;
     RECT  2.16 171.045 84.24 171.315 ;
     RECT  2.16 171.585 84.24 171.855 ;
     RECT  2.16 172.125 84.24 172.395 ;
     RECT  2.16 172.665 84.24 172.935 ;
     RECT  2.16 173.205 84.24 173.475 ;
     RECT  2.16 173.745 84.24 174.015 ;
     RECT  2.16 174.285 84.24 174.555 ;
     RECT  2.16 174.825 84.24 175.095 ;
     RECT  2.16 175.365 84.24 175.635 ;
     RECT  2.16 175.905 84.24 176.175 ;
     RECT  2.16 176.445 84.24 176.715 ;
     RECT  2.16 176.985 84.24 177.255 ;
     RECT  2.16 177.525 84.24 177.795 ;
     RECT  2.16 178.065 84.24 178.335 ;
     RECT  2.16 178.605 84.24 178.875 ;
     RECT  2.16 179.145 84.24 179.415 ;
     RECT  2.16 179.685 84.24 179.955 ;
     RECT  2.16 180.225 84.24 180.495 ;
     RECT  2.16 180.765 84.24 181.035 ;
     RECT  2.16 181.305 84.24 181.44 ;
    LAYER RVTP ;
     RECT  2.16 2.295 84.24 2.565 ;
     RECT  2.16 2.835 84.24 3.105 ;
     RECT  2.16 3.375 84.24 3.645 ;
     RECT  2.16 3.915 84.24 4.185 ;
     RECT  2.16 4.455 84.24 4.725 ;
     RECT  2.16 4.995 84.24 5.265 ;
     RECT  2.16 5.535 84.24 5.805 ;
     RECT  2.16 6.075 84.24 6.345 ;
     RECT  2.16 6.615 84.24 6.885 ;
     RECT  2.16 7.155 84.24 7.425 ;
     RECT  2.16 7.695 84.24 7.965 ;
     RECT  2.16 8.235 84.24 8.505 ;
     RECT  2.16 8.775 84.24 9.045 ;
     RECT  2.16 9.315 84.24 9.585 ;
     RECT  2.16 9.855 84.24 10.125 ;
     RECT  2.16 10.395 84.24 10.665 ;
     RECT  2.16 10.935 84.24 11.205 ;
     RECT  2.16 11.475 84.24 11.745 ;
     RECT  2.16 12.015 84.24 12.285 ;
     RECT  2.16 12.555 84.24 12.825 ;
     RECT  2.16 13.095 84.24 13.365 ;
     RECT  2.16 13.635 84.24 13.905 ;
     RECT  2.16 14.175 84.24 14.445 ;
     RECT  2.16 14.715 84.24 14.985 ;
     RECT  2.16 15.255 84.24 15.525 ;
     RECT  2.16 15.795 84.24 16.065 ;
     RECT  2.16 16.335 84.24 16.605 ;
     RECT  2.16 16.875 84.24 17.145 ;
     RECT  2.16 17.415 84.24 17.685 ;
     RECT  2.16 17.955 84.24 18.225 ;
     RECT  2.16 18.495 84.24 18.765 ;
     RECT  2.16 19.035 84.24 19.305 ;
     RECT  2.16 19.575 84.24 19.845 ;
     RECT  2.16 20.115 84.24 20.385 ;
     RECT  2.16 20.655 84.24 20.925 ;
     RECT  2.16 21.195 84.24 21.465 ;
     RECT  2.16 21.735 84.24 22.005 ;
     RECT  2.16 22.275 84.24 22.545 ;
     RECT  2.16 22.815 84.24 23.085 ;
     RECT  2.16 23.355 84.24 23.625 ;
     RECT  2.16 23.895 84.24 24.165 ;
     RECT  2.16 24.435 84.24 24.705 ;
     RECT  2.16 24.975 84.24 25.245 ;
     RECT  2.16 25.515 84.24 25.785 ;
     RECT  2.16 26.055 84.24 26.325 ;
     RECT  2.16 26.595 84.24 26.865 ;
     RECT  2.16 27.135 84.24 27.405 ;
     RECT  2.16 27.675 84.24 27.945 ;
     RECT  2.16 28.215 84.24 28.485 ;
     RECT  2.16 28.755 84.24 29.025 ;
     RECT  2.16 29.295 84.24 29.565 ;
     RECT  2.16 29.835 84.24 30.105 ;
     RECT  2.16 30.375 84.24 30.645 ;
     RECT  2.16 30.915 84.24 31.185 ;
     RECT  2.16 31.455 84.24 31.725 ;
     RECT  2.16 31.995 84.24 32.265 ;
     RECT  2.16 32.535 84.24 32.805 ;
     RECT  2.16 33.075 84.24 33.345 ;
     RECT  2.16 33.615 84.24 33.885 ;
     RECT  2.16 34.155 84.24 34.425 ;
     RECT  2.16 34.695 84.24 34.965 ;
     RECT  2.16 35.235 84.24 35.505 ;
     RECT  2.16 35.775 84.24 36.045 ;
     RECT  2.16 36.315 84.24 36.585 ;
     RECT  2.16 36.855 84.24 37.125 ;
     RECT  2.16 37.395 84.24 37.665 ;
     RECT  2.16 37.935 84.24 38.205 ;
     RECT  2.16 38.475 84.24 38.745 ;
     RECT  2.16 39.015 84.24 39.285 ;
     RECT  2.16 39.555 84.24 39.825 ;
     RECT  2.16 40.095 84.24 40.365 ;
     RECT  2.16 40.635 84.24 40.905 ;
     RECT  2.16 41.175 84.24 41.445 ;
     RECT  2.16 41.715 84.24 41.985 ;
     RECT  2.16 42.255 84.24 42.525 ;
     RECT  2.16 42.795 84.24 43.065 ;
     RECT  2.16 43.335 84.24 43.605 ;
     RECT  2.16 43.875 84.24 44.145 ;
     RECT  2.16 44.415 84.24 44.685 ;
     RECT  2.16 44.955 84.24 45.225 ;
     RECT  2.16 45.495 84.24 45.765 ;
     RECT  2.16 46.035 84.24 46.305 ;
     RECT  2.16 46.575 84.24 46.845 ;
     RECT  2.16 47.115 84.24 47.385 ;
     RECT  2.16 47.655 84.24 47.925 ;
     RECT  2.16 48.195 84.24 48.465 ;
     RECT  2.16 48.735 84.24 49.005 ;
     RECT  2.16 49.275 84.24 49.545 ;
     RECT  2.16 49.815 84.24 50.085 ;
     RECT  2.16 50.355 84.24 50.625 ;
     RECT  2.16 50.895 84.24 51.165 ;
     RECT  2.16 51.435 84.24 51.705 ;
     RECT  2.16 51.975 84.24 52.245 ;
     RECT  2.16 52.515 84.24 52.785 ;
     RECT  2.16 53.055 84.24 53.325 ;
     RECT  2.16 53.595 84.24 53.865 ;
     RECT  2.16 54.135 84.24 54.405 ;
     RECT  2.16 54.675 84.24 54.945 ;
     RECT  2.16 55.215 84.24 55.485 ;
     RECT  2.16 55.755 84.24 56.025 ;
     RECT  2.16 56.295 84.24 56.565 ;
     RECT  2.16 56.835 84.24 57.105 ;
     RECT  2.16 57.375 84.24 57.645 ;
     RECT  2.16 57.915 84.24 58.185 ;
     RECT  2.16 58.455 84.24 58.725 ;
     RECT  2.16 58.995 84.24 59.265 ;
     RECT  2.16 59.535 84.24 59.805 ;
     RECT  2.16 60.075 84.24 60.345 ;
     RECT  2.16 60.615 84.24 60.885 ;
     RECT  2.16 61.155 84.24 61.425 ;
     RECT  2.16 61.695 84.24 61.965 ;
     RECT  2.16 62.235 84.24 62.505 ;
     RECT  2.16 62.775 84.24 63.045 ;
     RECT  2.16 63.315 84.24 63.585 ;
     RECT  2.16 63.855 84.24 64.125 ;
     RECT  2.16 64.395 84.24 64.665 ;
     RECT  2.16 64.935 84.24 65.205 ;
     RECT  2.16 65.475 84.24 65.745 ;
     RECT  2.16 66.015 84.24 66.285 ;
     RECT  2.16 66.555 84.24 66.825 ;
     RECT  2.16 67.095 84.24 67.365 ;
     RECT  2.16 67.635 84.24 67.905 ;
     RECT  2.16 68.175 84.24 68.445 ;
     RECT  2.16 68.715 84.24 68.985 ;
     RECT  2.16 69.255 84.24 69.525 ;
     RECT  2.16 69.795 84.24 70.065 ;
     RECT  2.16 70.335 84.24 70.605 ;
     RECT  2.16 70.875 84.24 71.145 ;
     RECT  2.16 71.415 84.24 71.685 ;
     RECT  2.16 71.955 84.24 72.225 ;
     RECT  2.16 72.495 84.24 72.765 ;
     RECT  2.16 73.035 84.24 73.305 ;
     RECT  2.16 73.575 84.24 73.845 ;
     RECT  2.16 74.115 84.24 74.385 ;
     RECT  2.16 74.655 84.24 74.925 ;
     RECT  2.16 75.195 84.24 75.465 ;
     RECT  2.16 75.735 84.24 76.005 ;
     RECT  2.16 76.275 84.24 76.545 ;
     RECT  2.16 76.815 84.24 77.085 ;
     RECT  2.16 77.355 84.24 77.625 ;
     RECT  2.16 77.895 84.24 78.165 ;
     RECT  2.16 78.435 84.24 78.705 ;
     RECT  2.16 78.975 84.24 79.245 ;
     RECT  2.16 79.515 84.24 79.785 ;
     RECT  2.16 80.055 84.24 80.325 ;
     RECT  2.16 80.595 84.24 80.865 ;
     RECT  2.16 81.135 84.24 81.405 ;
     RECT  2.16 81.675 84.24 81.945 ;
     RECT  2.16 82.215 84.24 82.485 ;
     RECT  2.16 82.755 84.24 83.025 ;
     RECT  2.16 83.295 84.24 83.565 ;
     RECT  2.16 83.835 84.24 84.105 ;
     RECT  2.16 84.375 84.24 84.645 ;
     RECT  2.16 84.915 84.24 85.185 ;
     RECT  2.16 85.455 84.24 85.725 ;
     RECT  2.16 85.995 84.24 86.265 ;
     RECT  2.16 86.535 84.24 86.805 ;
     RECT  2.16 87.075 84.24 87.345 ;
     RECT  2.16 87.615 84.24 87.885 ;
     RECT  2.16 88.155 84.24 88.425 ;
     RECT  2.16 88.695 84.24 88.965 ;
     RECT  2.16 89.235 84.24 89.505 ;
     RECT  2.16 89.775 84.24 90.045 ;
     RECT  2.16 90.315 84.24 90.585 ;
     RECT  2.16 90.855 84.24 91.125 ;
     RECT  2.16 91.395 84.24 91.665 ;
     RECT  2.16 91.935 84.24 92.205 ;
     RECT  2.16 92.475 84.24 92.745 ;
     RECT  2.16 93.015 84.24 93.285 ;
     RECT  2.16 93.555 84.24 93.825 ;
     RECT  2.16 94.095 84.24 94.365 ;
     RECT  2.16 94.635 84.24 94.905 ;
     RECT  2.16 95.175 84.24 95.445 ;
     RECT  2.16 95.715 84.24 95.985 ;
     RECT  2.16 96.255 84.24 96.525 ;
     RECT  2.16 96.795 84.24 97.065 ;
     RECT  2.16 97.335 84.24 97.605 ;
     RECT  2.16 97.875 84.24 98.145 ;
     RECT  2.16 98.415 84.24 98.685 ;
     RECT  2.16 98.955 84.24 99.225 ;
     RECT  2.16 99.495 84.24 99.765 ;
     RECT  2.16 100.035 84.24 100.305 ;
     RECT  2.16 100.575 84.24 100.845 ;
     RECT  2.16 101.115 84.24 101.385 ;
     RECT  2.16 101.655 84.24 101.925 ;
     RECT  2.16 102.195 84.24 102.465 ;
     RECT  2.16 102.735 84.24 103.005 ;
     RECT  2.16 103.275 84.24 103.545 ;
     RECT  2.16 103.815 84.24 104.085 ;
     RECT  2.16 104.355 84.24 104.625 ;
     RECT  2.16 104.895 84.24 105.165 ;
     RECT  2.16 105.435 84.24 105.705 ;
     RECT  2.16 105.975 84.24 106.245 ;
     RECT  2.16 106.515 84.24 106.785 ;
     RECT  2.16 107.055 84.24 107.325 ;
     RECT  2.16 107.595 84.24 107.865 ;
     RECT  2.16 108.135 84.24 108.405 ;
     RECT  2.16 108.675 84.24 108.945 ;
     RECT  2.16 109.215 84.24 109.485 ;
     RECT  2.16 109.755 84.24 110.025 ;
     RECT  2.16 110.295 84.24 110.565 ;
     RECT  2.16 110.835 84.24 111.105 ;
     RECT  2.16 111.375 84.24 111.645 ;
     RECT  2.16 111.915 84.24 112.185 ;
     RECT  2.16 112.455 84.24 112.725 ;
     RECT  2.16 112.995 84.24 113.265 ;
     RECT  2.16 113.535 84.24 113.805 ;
     RECT  2.16 114.075 84.24 114.345 ;
     RECT  2.16 114.615 84.24 114.885 ;
     RECT  2.16 115.155 84.24 115.425 ;
     RECT  2.16 115.695 84.24 115.965 ;
     RECT  2.16 116.235 84.24 116.505 ;
     RECT  2.16 116.775 84.24 117.045 ;
     RECT  2.16 117.315 84.24 117.585 ;
     RECT  2.16 117.855 84.24 118.125 ;
     RECT  2.16 118.395 84.24 118.665 ;
     RECT  2.16 118.935 84.24 119.205 ;
     RECT  2.16 119.475 84.24 119.745 ;
     RECT  2.16 120.015 84.24 120.285 ;
     RECT  2.16 120.555 84.24 120.825 ;
     RECT  2.16 121.095 84.24 121.365 ;
     RECT  2.16 121.635 84.24 121.905 ;
     RECT  2.16 122.175 84.24 122.445 ;
     RECT  2.16 122.715 84.24 122.985 ;
     RECT  2.16 123.255 84.24 123.525 ;
     RECT  2.16 123.795 84.24 124.065 ;
     RECT  2.16 124.335 84.24 124.605 ;
     RECT  2.16 124.875 84.24 125.145 ;
     RECT  2.16 125.415 84.24 125.685 ;
     RECT  2.16 125.955 84.24 126.225 ;
     RECT  2.16 126.495 84.24 126.765 ;
     RECT  2.16 127.035 84.24 127.305 ;
     RECT  2.16 127.575 84.24 127.845 ;
     RECT  2.16 128.115 84.24 128.385 ;
     RECT  2.16 128.655 84.24 128.925 ;
     RECT  2.16 129.195 84.24 129.465 ;
     RECT  2.16 129.735 84.24 130.005 ;
     RECT  2.16 130.275 84.24 130.545 ;
     RECT  2.16 130.815 84.24 131.085 ;
     RECT  2.16 131.355 84.24 131.625 ;
     RECT  2.16 131.895 84.24 132.165 ;
     RECT  2.16 132.435 84.24 132.705 ;
     RECT  2.16 132.975 84.24 133.245 ;
     RECT  2.16 133.515 84.24 133.785 ;
     RECT  2.16 134.055 84.24 134.325 ;
     RECT  2.16 134.595 84.24 134.865 ;
     RECT  2.16 135.135 84.24 135.405 ;
     RECT  2.16 135.675 84.24 135.945 ;
     RECT  2.16 136.215 84.24 136.485 ;
     RECT  2.16 136.755 84.24 137.025 ;
     RECT  2.16 137.295 84.24 137.565 ;
     RECT  2.16 137.835 84.24 138.105 ;
     RECT  2.16 138.375 84.24 138.645 ;
     RECT  2.16 138.915 84.24 139.185 ;
     RECT  2.16 139.455 84.24 139.725 ;
     RECT  2.16 139.995 84.24 140.265 ;
     RECT  2.16 140.535 84.24 140.805 ;
     RECT  2.16 141.075 84.24 141.345 ;
     RECT  2.16 141.615 84.24 141.885 ;
     RECT  2.16 142.155 84.24 142.425 ;
     RECT  2.16 142.695 84.24 142.965 ;
     RECT  2.16 143.235 84.24 143.505 ;
     RECT  2.16 143.775 84.24 144.045 ;
     RECT  2.16 144.315 84.24 144.585 ;
     RECT  2.16 144.855 84.24 145.125 ;
     RECT  2.16 145.395 84.24 145.665 ;
     RECT  2.16 145.935 84.24 146.205 ;
     RECT  2.16 146.475 84.24 146.745 ;
     RECT  2.16 147.015 84.24 147.285 ;
     RECT  2.16 147.555 84.24 147.825 ;
     RECT  2.16 148.095 84.24 148.365 ;
     RECT  2.16 148.635 84.24 148.905 ;
     RECT  2.16 149.175 84.24 149.445 ;
     RECT  2.16 149.715 84.24 149.985 ;
     RECT  2.16 150.255 84.24 150.525 ;
     RECT  2.16 150.795 84.24 151.065 ;
     RECT  2.16 151.335 84.24 151.605 ;
     RECT  2.16 151.875 84.24 152.145 ;
     RECT  2.16 152.415 84.24 152.685 ;
     RECT  2.16 152.955 84.24 153.225 ;
     RECT  2.16 153.495 84.24 153.765 ;
     RECT  2.16 154.035 84.24 154.305 ;
     RECT  2.16 154.575 84.24 154.845 ;
     RECT  2.16 155.115 84.24 155.385 ;
     RECT  2.16 155.655 84.24 155.925 ;
     RECT  2.16 156.195 84.24 156.465 ;
     RECT  2.16 156.735 84.24 157.005 ;
     RECT  2.16 157.275 84.24 157.545 ;
     RECT  2.16 157.815 84.24 158.085 ;
     RECT  2.16 158.355 84.24 158.625 ;
     RECT  2.16 158.895 84.24 159.165 ;
     RECT  2.16 159.435 84.24 159.705 ;
     RECT  2.16 159.975 84.24 160.245 ;
     RECT  2.16 160.515 84.24 160.785 ;
     RECT  2.16 161.055 84.24 161.325 ;
     RECT  2.16 161.595 84.24 161.865 ;
     RECT  2.16 162.135 84.24 162.405 ;
     RECT  2.16 162.675 84.24 162.945 ;
     RECT  2.16 163.215 84.24 163.485 ;
     RECT  2.16 163.755 84.24 164.025 ;
     RECT  2.16 164.295 84.24 164.565 ;
     RECT  2.16 164.835 84.24 165.105 ;
     RECT  2.16 165.375 84.24 165.645 ;
     RECT  2.16 165.915 84.24 166.185 ;
     RECT  2.16 166.455 84.24 166.725 ;
     RECT  2.16 166.995 84.24 167.265 ;
     RECT  2.16 167.535 84.24 167.805 ;
     RECT  2.16 168.075 84.24 168.345 ;
     RECT  2.16 168.615 84.24 168.885 ;
     RECT  2.16 169.155 84.24 169.425 ;
     RECT  2.16 169.695 84.24 169.965 ;
     RECT  2.16 170.235 84.24 170.505 ;
     RECT  2.16 170.775 84.24 171.045 ;
     RECT  2.16 171.315 84.24 171.585 ;
     RECT  2.16 171.855 84.24 172.125 ;
     RECT  2.16 172.395 84.24 172.665 ;
     RECT  2.16 172.935 84.24 173.205 ;
     RECT  2.16 173.475 84.24 173.745 ;
     RECT  2.16 174.015 84.24 174.285 ;
     RECT  2.16 174.555 84.24 174.825 ;
     RECT  2.16 175.095 84.24 175.365 ;
     RECT  2.16 175.635 84.24 175.905 ;
     RECT  2.16 176.175 84.24 176.445 ;
     RECT  2.16 176.715 84.24 176.985 ;
     RECT  2.16 177.255 84.24 177.525 ;
     RECT  2.16 177.795 84.24 178.065 ;
     RECT  2.16 178.335 84.24 178.605 ;
     RECT  2.16 178.875 84.24 179.145 ;
     RECT  2.16 179.415 84.24 179.685 ;
     RECT  2.16 179.955 84.24 180.225 ;
     RECT  2.16 180.495 84.24 180.765 ;
     RECT  2.16 181.035 84.24 181.305 ;
    LAYER M1 ;
     RECT  2.16 2.151 84.24 181.449 ;
    LAYER M2 ;
     RECT  0.571 132.876 1.111 132.894 ;
     RECT  0.571 168.786 1.111 168.804 ;
     RECT  0.571 180.972 1.111 180.99 ;
     RECT  0.571 39.366 1.147 39.384 ;
     RECT  1.111 44.226 1.147 44.244 ;
     RECT  0.571 46.206 1.147 46.764 ;
     RECT  0.571 55.926 1.147 56.484 ;
     RECT  0.571 90.756 1.147 90.774 ;
     RECT  1.111 122.256 1.147 122.274 ;
     RECT  1.111 131.976 1.147 131.994 ;
     RECT  1.111 134.406 1.147 134.424 ;
     RECT  1.111 168.786 1.147 169.524 ;
     RECT  1.147 41.886 1.219 41.904 ;
     RECT  1.147 49.176 1.219 49.734 ;
     RECT  1.147 51.066 1.219 51.084 ;
     RECT  1.147 52.686 1.219 55.134 ;
     RECT  1.147 93.726 1.219 93.744 ;
     RECT  0.571 124.506 1.219 124.524 ;
     RECT  1.147 125.316 1.219 126.684 ;
     RECT  1.147 130.212 1.219 130.23 ;
     RECT  1.147 163.926 1.219 163.944 ;
     RECT  1.147 165.816 1.219 166.374 ;
     RECT  1.147 171.216 1.219 171.774 ;
     RECT  1.147 172.836 1.219 173.574 ;
     RECT  1.183 178.92 1.687 178.938 ;
     RECT  1.111 180.972 1.687 181.134 ;
     RECT  1.147 39.366 1.723 40.014 ;
     RECT  1.147 58.356 1.723 58.374 ;
     RECT  1.147 97.236 1.723 97.254 ;
     RECT  1.147 117.486 1.723 117.504 ;
     RECT  1.147 156.402 1.723 157.104 ;
     RECT  1.687 178.92 1.723 179.478 ;
     RECT  1.687 180.432 1.759 181.134 ;
     RECT  0.751 2.646 1.903 2.664 ;
     RECT  1.903 2.106 2.16 2.664 ;
     RECT  0.031 9.288 2.16 9.306 ;
     RECT  0.571 10.296 2.16 10.314 ;
     RECT  0.571 12.186 2.16 12.744 ;
     RECT  1.147 13.536 2.16 13.554 ;
     RECT  1.147 14.616 2.16 15.714 ;
     RECT  1.147 17.046 2.16 17.334 ;
     RECT  1.147 18.126 2.16 18.684 ;
     RECT  1.111 19.656 2.16 19.674 ;
     RECT  1.723 20.556 2.16 21.114 ;
     RECT  1.723 22.086 2.16 22.734 ;
     RECT  1.723 23.526 2.16 23.544 ;
     RECT  1.723 24.336 2.16 26.514 ;
     RECT  1.723 27.306 2.16 28.404 ;
     RECT  1.723 29.196 2.16 30.294 ;
     RECT  1.723 31.356 2.16 31.374 ;
     RECT  1.723 32.166 2.16 32.724 ;
     RECT  1.723 33.786 2.16 33.804 ;
     RECT  1.723 34.596 2.16 35.694 ;
     RECT  1.723 36.666 2.16 37.584 ;
     RECT  1.723 38.646 2.16 40.014 ;
     RECT  1.219 41.526 2.16 42.354 ;
     RECT  1.147 44.226 2.16 44.874 ;
     RECT  1.147 46.206 2.16 47.304 ;
     RECT  1.219 48.816 2.16 49.734 ;
     RECT  1.219 51.066 2.16 55.134 ;
     RECT  1.147 55.926 2.16 57.024 ;
     RECT  1.723 58.356 2.16 58.914 ;
     RECT  1.723 60.786 2.16 60.804 ;
     RECT  1.723 61.776 2.16 64.314 ;
     RECT  1.723 65.106 2.16 66.744 ;
     RECT  1.723 67.716 2.16 69.174 ;
     RECT  1.723 70.956 2.16 71.064 ;
     RECT  1.723 71.856 2.16 71.874 ;
     RECT  1.723 72.936 2.16 72.954 ;
     RECT  1.723 74.286 2.16 74.304 ;
     RECT  1.723 75.636 2.16 75.924 ;
     RECT  1.723 76.896 2.16 76.914 ;
     RECT  1.147 78.336 2.16 78.894 ;
     RECT  1.147 80.226 2.16 80.784 ;
     RECT  0.571 81.576 2.16 81.594 ;
     RECT  1.147 82.926 2.16 82.944 ;
     RECT  1.147 84.006 2.16 84.024 ;
     RECT  1.147 85.086 2.16 85.644 ;
     RECT  1.147 86.436 2.16 86.454 ;
     RECT  1.147 87.516 2.16 88.074 ;
     RECT  1.147 89.946 2.16 89.964 ;
     RECT  1.147 90.756 2.16 91.314 ;
     RECT  1.147 92.376 2.16 92.394 ;
     RECT  1.219 93.366 2.16 93.744 ;
     RECT  1.147 95.076 2.16 96.174 ;
     RECT  1.723 97.236 2.16 97.794 ;
     RECT  1.723 99.666 2.16 99.684 ;
     RECT  1.723 100.656 2.16 100.674 ;
     RECT  1.723 101.556 2.16 101.574 ;
     RECT  1.723 102.546 2.16 103.464 ;
     RECT  1.723 104.526 2.16 104.544 ;
     RECT  1.723 106.956 2.16 106.974 ;
     RECT  1.723 107.766 2.16 108.324 ;
     RECT  1.723 109.656 2.16 110.934 ;
     RECT  1.723 112.266 2.16 113.364 ;
     RECT  1.723 114.426 2.16 115.614 ;
     RECT  1.723 116.946 2.16 117.504 ;
     RECT  1.147 119.376 2.16 119.934 ;
     RECT  1.147 122.256 2.16 122.904 ;
     RECT  1.219 124.506 2.16 127.872 ;
     RECT  1.219 129.276 2.16 130.23 ;
     RECT  1.147 131.976 2.16 132.084 ;
     RECT  1.111 132.876 2.16 133.614 ;
     RECT  1.147 134.406 2.16 134.514 ;
     RECT  1.147 136.566 2.16 136.584 ;
     RECT  1.723 138.816 2.16 139.914 ;
     RECT  1.723 141.786 2.16 141.804 ;
     RECT  1.723 143.676 2.16 143.694 ;
     RECT  1.723 144.486 2.16 144.504 ;
     RECT  1.723 146.646 2.16 147.204 ;
     RECT  1.723 148.716 2.16 149.094 ;
     RECT  1.723 149.886 2.16 149.904 ;
     RECT  1.723 151.236 2.16 151.524 ;
     RECT  1.723 152.496 2.16 152.514 ;
     RECT  1.723 153.396 2.16 153.414 ;
     RECT  1.723 154.746 2.16 154.764 ;
     RECT  1.723 155.826 2.16 157.104 ;
     RECT  1.147 158.256 2.16 158.814 ;
     RECT  0.571 159.606 2.16 159.624 ;
     RECT  1.147 160.686 2.16 160.704 ;
     RECT  1.147 161.496 2.16 162.054 ;
     RECT  1.147 163.116 2.16 163.134 ;
     RECT  1.219 163.926 2.16 164.664 ;
     RECT  1.219 165.816 2.16 166.68 ;
     RECT  1.147 167.436 2.16 167.994 ;
     RECT  1.147 168.786 2.16 169.884 ;
     RECT  1.219 171.216 2.16 173.574 ;
     RECT  1.219 174.366 2.16 174.384 ;
     RECT  1.723 177.732 2.16 179.478 ;
     RECT  1.759 180.27 2.16 181.134 ;
     RECT  2.16 2.106 2.875 181.449 ;
     RECT  2.875 2.034 4.387 181.449 ;
     RECT  4.387 1.962 7.043 181.449 ;
     RECT  7.043 2.151 19.831 181.449 ;
     RECT  19.831 2.106 20.147 181.449 ;
     RECT  20.147 2.151 20.947 181.449 ;
     RECT  20.947 2.106 21.227 181.449 ;
     RECT  21.227 2.151 22.099 181.449 ;
     RECT  22.099 2.106 22.487 181.449 ;
     RECT  22.487 2.151 23.287 181.449 ;
     RECT  23.287 2.106 23.603 181.449 ;
     RECT  23.603 2.151 25.627 181.449 ;
     RECT  25.627 2.106 25.835 181.449 ;
     RECT  25.835 2.151 40.855 181.449 ;
     RECT  40.855 2.106 41.207 181.449 ;
     RECT  41.207 2.151 44.383 181.449 ;
     RECT  44.383 2.106 44.663 181.449 ;
     RECT  44.663 2.151 45.571 181.449 ;
     RECT  45.571 2.106 45.959 181.449 ;
     RECT  45.959 2.151 61.987 181.449 ;
     RECT  61.987 2.106 62.267 181.449 ;
     RECT  62.267 2.151 80.671 181.449 ;
     RECT  80.671 2.106 81.095 181.449 ;
     RECT  81.095 2.151 83.263 181.449 ;
     RECT  83.263 2.106 83.551 181.449 ;
     RECT  83.551 2.034 84.24 181.449 ;
     RECT  84.24 179.73 84.407 179.748 ;
     RECT  84.24 3.546 84.479 4.374 ;
     RECT  84.24 181.08 84.479 181.26 ;
     RECT  84.479 3.546 84.875 3.834 ;
     RECT  84.24 2.034 84.911 2.394 ;
     RECT  84.875 3.546 84.911 3.564 ;
     RECT  84.24 56.034 84.911 56.052 ;
     RECT  84.479 181.242 85.487 181.26 ;
     RECT  84.911 2.376 86.207 2.394 ;
     RECT  84.24 92.52 86.315 92.538 ;
    LAYER M3 ;
     RECT  9.216 0.043 9.234 0.091 ;
     RECT  3.78 0.091 3.798 0.283 ;
     RECT  19.8 0.091 19.818 0.571 ;
     RECT  26.46 0.091 27.558 0.571 ;
     RECT  37.908 0.091 39.762 0.571 ;
     RECT  41.472 0.091 43.11 0.571 ;
     RECT  45.504 0.091 45.522 0.571 ;
     RECT  59.184 0.091 59.454 0.571 ;
     RECT  60.624 0.091 60.642 0.571 ;
     RECT  65.34 0.091 65.358 0.571 ;
     RECT  76.248 0.091 76.266 0.571 ;
     RECT  77.328 0.091 77.346 0.571 ;
     RECT  81.756 0.091 81.774 0.571 ;
     RECT  83.376 0.091 84.222 0.571 ;
     RECT  83.088 0.571 84.834 0.667 ;
     RECT  9.216 0.091 9.666 0.907 ;
     RECT  3.024 0.571 3.042 1.147 ;
     RECT  3.78 0.283 4.482 1.147 ;
     RECT  6.588 0.571 7.29 1.147 ;
     RECT  18.144 0.619 18.162 1.147 ;
     RECT  19.368 0.571 19.818 1.147 ;
     RECT  37.908 0.571 43.686 1.147 ;
     RECT  44.82 0.571 45.522 1.147 ;
     RECT  46.692 0.091 46.71 1.147 ;
     RECT  56.808 0.091 56.826 1.147 ;
     RECT  58.032 0.091 58.338 1.147 ;
     RECT  59.184 0.571 60.642 1.147 ;
     RECT  61.38 0.091 61.974 1.147 ;
     RECT  63.072 0.091 63.63 1.147 ;
     RECT  64.836 0.571 65.358 1.147 ;
     RECT  68.292 0.619 68.31 1.147 ;
     RECT  70.56 0.619 70.578 1.147 ;
     RECT  14.4 1.147 14.418 1.195 ;
     RECT  17.676 1.147 18.162 1.195 ;
     RECT  19.044 1.147 19.854 1.195 ;
     RECT  28.296 0.091 28.314 1.195 ;
     RECT  29.664 1.147 29.682 1.195 ;
     RECT  30.816 1.147 30.834 1.195 ;
     RECT  34.272 1.147 34.29 1.195 ;
     RECT  36.648 0.619 36.666 1.195 ;
     RECT  46.692 1.147 47.322 1.195 ;
     RECT  48.456 1.147 48.474 1.195 ;
     RECT  49.68 1.147 49.698 1.195 ;
     RECT  66.24 1.147 66.258 1.195 ;
     RECT  68.184 1.147 68.31 1.195 ;
     RECT  69.228 1.147 69.246 1.195 ;
     RECT  70.56 1.147 70.722 1.195 ;
     RECT  35.748 1.147 35.766 1.243 ;
     RECT  46.692 1.195 48.654 1.243 ;
     RECT  53.388 1.147 53.406 1.243 ;
     RECT  8.316 0.091 8.334 1.531 ;
     RECT  9.216 0.907 9.702 1.531 ;
     RECT  79.056 0.571 79.074 1.723 ;
     RECT  83.088 0.667 84.87 1.723 ;
     RECT  8.316 1.531 9.702 1.771 ;
     RECT  10.836 1.147 10.854 1.771 ;
     RECT  13.176 1.147 13.194 1.771 ;
     RECT  14.4 1.195 14.742 1.771 ;
     RECT  15.696 1.147 15.714 1.771 ;
     RECT  16.524 1.147 16.542 1.771 ;
     RECT  28.296 1.195 29.97 1.771 ;
     RECT  30.816 1.195 31.158 1.771 ;
     RECT  33.372 1.195 33.39 1.771 ;
     RECT  34.272 1.195 34.614 1.771 ;
     RECT  35.712 1.243 35.766 1.771 ;
     RECT  36.648 1.195 37.134 1.771 ;
     RECT  37.908 1.147 45.594 1.771 ;
     RECT  46.692 1.243 48.834 1.771 ;
     RECT  49.68 1.195 49.806 1.771 ;
     RECT  52.164 1.195 52.182 1.771 ;
     RECT  53.352 1.243 53.406 1.771 ;
     RECT  54.216 1.147 54.234 1.771 ;
     RECT  55.44 1.147 55.458 1.771 ;
     RECT  66.24 1.195 66.438 1.771 ;
     RECT  70.56 1.195 71.226 1.771 ;
     RECT  72.072 1.195 72.09 1.771 ;
     RECT  72.936 0.619 72.954 1.771 ;
     RECT  74.304 1.147 74.322 1.771 ;
     RECT  75.6 0.571 77.994 1.771 ;
     RECT  50.688 1.771 50.706 1.867 ;
     RECT  3.78 1.147 4.554 2.029 ;
     RECT  1.908 1.147 1.926 2.059 ;
     RECT  2.736 1.147 3.042 2.059 ;
     RECT  3.78 2.029 4.662 2.101 ;
     RECT  5.508 0.571 5.778 2.101 ;
     RECT  17.676 1.195 19.854 2.101 ;
     RECT  20.844 0.571 27.558 2.101 ;
     RECT  32.976 1.771 45.594 2.101 ;
     RECT  81.756 0.571 82.35 2.101 ;
     RECT  1.908 2.059 3.042 2.129 ;
     RECT  6.588 1.147 7.362 2.143 ;
     RECT  8.316 1.771 9.954 2.143 ;
     RECT  50.652 1.867 50.706 2.143 ;
     RECT  51.552 1.771 55.458 2.143 ;
     RECT  56.556 1.147 63.63 2.143 ;
     RECT  66.24 1.771 67.014 2.143 ;
     RECT  74.016 1.771 77.994 2.143 ;
     RECT  80.676 2.101 82.35 2.191 ;
     RECT  83.088 1.723 84.906 2.191 ;
     RECT  14.4 1.771 16.542 2.219 ;
     RECT  2.304 2.129 3.042 2.227 ;
     RECT  3.78 2.101 5.778 2.227 ;
     RECT  10.728 1.771 11.358 2.227 ;
     RECT  12.132 1.147 12.15 2.227 ;
     RECT  28.296 1.771 31.158 2.227 ;
     RECT  31.896 1.771 31.914 2.227 ;
     RECT  32.976 2.101 45.954 2.227 ;
     RECT  56.415 2.143 63.63 2.227 ;
     RECT  64.368 1.147 65.502 2.227 ;
     RECT  66.24 2.143 67.305 2.227 ;
     RECT  32.868 2.227 45.954 2.251 ;
     RECT  46.692 1.771 49.806 2.251 ;
     RECT  2.304 2.227 5.778 2.263 ;
     RECT  6.588 2.143 9.954 2.263 ;
     RECT  17.676 2.101 27.558 2.263 ;
     RECT  70.56 1.771 72.954 2.263 ;
     RECT  0.108 2.107 0.126 2.285 ;
     RECT  74.016 2.143 78.105 2.299 ;
     RECT  79.056 1.723 79.722 2.299 ;
     RECT  50.652 2.143 55.458 2.335 ;
     RECT  56.376 2.227 63.63 2.335 ;
     RECT  64.368 2.227 67.305 2.335 ;
     RECT  10.728 2.227 12.15 2.371 ;
     RECT  14.58 2.219 16.542 2.371 ;
     RECT  17.46 2.263 27.558 2.371 ;
     RECT  74.016 2.299 79.722 2.371 ;
     RECT  80.676 2.191 84.906 2.371 ;
     RECT  86.184 0.571 86.202 2.399 ;
     RECT  56.376 2.335 67.305 2.413 ;
     RECT  68.184 1.195 69.678 2.413 ;
     RECT  28.296 2.227 31.914 2.461 ;
     RECT  32.868 2.251 49.806 2.461 ;
     RECT  10.728 2.371 12.438 2.497 ;
     RECT  13.176 1.771 13.626 2.497 ;
     RECT  28.296 2.461 49.806 2.605 ;
     RECT  50.652 2.335 55.638 2.605 ;
     RECT  56.376 2.413 69.678 2.605 ;
     RECT  70.488 2.263 72.954 2.605 ;
     RECT  2.304 2.263 9.954 2.641 ;
     RECT  10.692 2.497 13.626 2.641 ;
     RECT  28.296 2.605 69.678 2.641 ;
     RECT  70.452 2.605 72.954 2.641 ;
     RECT  0.756 2.299 0.774 2.669 ;
     RECT  2.304 2.641 13.626 2.759 ;
     RECT  2.304 2.759 10.278 2.795 ;
     RECT  14.58 2.371 27.558 2.875 ;
     RECT  28.296 2.641 72.954 2.875 ;
     RECT  74.016 2.371 84.906 2.911 ;
     RECT  2.34 2.795 10.278 3.029 ;
     RECT  14.58 2.875 72.954 3.145 ;
     RECT  14.544 3.145 72.954 3.181 ;
     RECT  73.728 2.911 84.906 3.181 ;
     RECT  11.016 2.759 13.626 3.343 ;
     RECT  14.544 3.181 84.906 3.343 ;
     RECT  11.016 3.343 84.906 3.569 ;
     RECT  2.376 3.029 10.278 3.649 ;
     RECT  11.016 3.569 84.87 3.649 ;
     RECT  2.376 3.649 84.87 3.749 ;
     RECT  2.415 3.749 84.87 3.839 ;
     RECT  2.415 3.839 84.474 4.379 ;
     RECT  0.108 4.555 0.126 4.685 ;
     RECT  0.108 5.755 0.126 6.235 ;
     RECT  0.036 6.235 0.126 6.269 ;
     RECT  2.415 4.379 84.222 6.283 ;
     RECT  2.268 6.283 84.222 6.719 ;
     RECT  2.268 6.719 65.394 6.809 ;
     RECT  66.348 6.719 84.222 6.809 ;
     RECT  66.348 6.809 74.934 6.845 ;
     RECT  2.268 6.809 39.366 7.115 ;
     RECT  2.268 7.115 25.326 7.385 ;
     RECT  75.924 6.809 84.222 7.655 ;
     RECT  2.268 7.385 11.898 8.131 ;
     RECT  12.636 7.385 25.326 8.131 ;
     RECT  2.268 8.131 25.326 8.339 ;
     RECT  80.676 7.655 84.222 8.699 ;
     RECT  80.676 8.699 83.862 8.735 ;
     RECT  2.415 8.339 25.326 8.843 ;
     RECT  0.036 6.269 0.054 9.311 ;
     RECT  80.676 8.735 83.79 9.419 ;
     RECT  0.108 9.451 0.126 9.581 ;
     RECT  2.415 8.843 11.898 10.021 ;
     RECT  12.672 8.843 25.326 10.021 ;
     RECT  0.576 10.027 0.594 10.319 ;
     RECT  2.415 10.021 25.326 10.661 ;
     RECT  12.672 10.661 25.326 10.859 ;
     RECT  0.108 11.179 0.126 11.309 ;
     RECT  2.415 10.661 11.898 12.325 ;
     RECT  12.672 10.859 14.202 12.325 ;
     RECT  2.415 12.325 14.202 12.631 ;
     RECT  14.976 10.859 25.326 12.631 ;
     RECT  0.576 11.899 0.594 12.749 ;
     RECT  1.152 13.099 1.17 13.559 ;
     RECT  2.415 12.631 25.326 13.631 ;
     RECT  2.415 13.631 2.697 14.755 ;
     RECT  3.528 13.631 25.326 14.755 ;
     RECT  2.415 14.755 25.326 14.909 ;
     RECT  2.415 14.909 2.697 15.691 ;
     RECT  3.42 14.909 25.326 15.691 ;
     RECT  1.152 14.299 1.17 15.719 ;
     RECT  2.415 15.691 25.326 15.863 ;
     RECT  2.415 15.863 2.697 16.171 ;
     RECT  2.304 16.171 2.697 16.259 ;
     RECT  2.415 16.259 2.697 16.951 ;
     RECT  3.528 15.863 25.326 16.951 ;
     RECT  2.415 16.951 25.326 17.105 ;
     RECT  2.415 17.105 2.697 18.121 ;
     RECT  3.42 17.105 25.326 18.121 ;
     RECT  2.415 18.121 25.326 18.221 ;
     RECT  86.22 18.235 86.238 18.365 ;
     RECT  1.152 16.747 1.17 18.689 ;
     RECT  2.415 18.221 2.697 19.309 ;
     RECT  3.42 18.221 25.326 19.309 ;
     RECT  2.415 19.309 25.326 19.381 ;
     RECT  2.304 19.381 25.326 19.535 ;
     RECT  1.116 19.195 1.134 19.679 ;
     RECT  2.415 19.535 25.326 20.443 ;
     RECT  1.728 20.443 25.326 21.659 ;
     RECT  1.728 21.659 2.697 22.711 ;
     RECT  3.42 21.659 25.326 22.711 ;
     RECT  1.728 22.711 25.326 22.739 ;
     RECT  2.304 22.739 25.326 22.811 ;
     RECT  2.304 22.811 2.697 23.512 ;
     RECT  1.728 23.512 2.697 24.043 ;
     RECT  3.528 22.811 25.326 24.043 ;
     RECT  1.728 24.043 25.326 24.467 ;
     RECT  3.42 24.467 25.326 24.701 ;
     RECT  3.528 24.701 25.326 26.249 ;
     RECT  1.728 24.467 2.697 26.599 ;
     RECT  3.528 26.249 11.826 26.599 ;
     RECT  1.728 26.599 11.826 27.059 ;
     RECT  1.728 27.059 2.697 27.841 ;
     RECT  3.528 27.059 11.826 27.841 ;
     RECT  1.728 27.841 11.826 28.481 ;
     RECT  3.528 28.481 11.826 28.651 ;
     RECT  12.6 26.249 25.326 28.651 ;
     RECT  1.728 28.481 2.697 29.263 ;
     RECT  3.528 28.651 25.326 29.263 ;
     RECT  1.728 29.263 25.326 30.299 ;
     RECT  2.415 30.299 25.326 31.351 ;
     RECT  1.728 31.351 25.326 32.729 ;
     RECT  2.415 32.729 25.326 33.781 ;
     RECT  1.728 33.781 25.326 34.187 ;
     RECT  3.42 34.187 25.326 34.655 ;
     RECT  17.676 34.655 25.326 34.799 ;
     RECT  1.728 34.187 2.697 35.131 ;
     RECT  3.42 34.655 16.902 35.131 ;
     RECT  1.728 35.131 16.902 36.931 ;
     RECT  17.748 34.799 25.326 36.931 ;
     RECT  1.728 36.931 25.326 37.193 ;
     RECT  1.728 37.193 2.79 37.589 ;
     RECT  2.415 37.589 2.79 38.101 ;
     RECT  3.528 37.193 25.326 38.101 ;
     RECT  2.415 38.101 25.326 38.641 ;
     RECT  1.728 38.641 25.326 38.717 ;
     RECT  0.576 39.307 0.594 39.389 ;
     RECT  2.376 38.717 25.326 39.487 ;
     RECT  2.304 39.487 25.326 39.659 ;
     RECT  1.152 39.931 1.17 40.019 ;
     RECT  2.415 39.659 25.326 41.251 ;
     RECT  2.304 41.251 25.326 41.405 ;
     RECT  1.224 41.179 1.242 41.549 ;
     RECT  2.415 41.405 25.326 41.639 ;
     RECT  1.152 41.755 1.17 41.909 ;
     RECT  2.415 41.639 2.697 42.331 ;
     RECT  1.224 42.331 1.242 42.413 ;
     RECT  2.412 42.331 2.697 42.457 ;
     RECT  2.304 42.457 2.697 42.629 ;
     RECT  2.415 42.629 2.697 43.003 ;
     RECT  3.42 41.639 21.762 43.003 ;
     RECT  2.415 43.003 21.762 43.951 ;
     RECT  2.304 43.951 21.762 44.105 ;
     RECT  1.116 43.579 1.134 44.203 ;
     RECT  2.415 44.105 21.762 44.221 ;
     RECT  22.5 41.639 25.326 44.221 ;
     RECT  1.116 44.203 1.17 44.249 ;
     RECT  1.152 44.249 1.17 44.879 ;
     RECT  2.415 44.221 25.326 45.391 ;
     RECT  2.304 45.391 25.326 45.437 ;
     RECT  0.576 46.027 0.594 46.769 ;
     RECT  2.415 45.437 25.326 46.913 ;
     RECT  3.42 46.913 25.326 47.075 ;
     RECT  1.152 47.272 1.17 47.309 ;
     RECT  2.415 46.913 2.697 48.433 ;
     RECT  3.456 47.075 25.326 48.433 ;
     RECT  2.415 48.433 25.326 48.541 ;
     RECT  2.304 48.541 25.326 48.695 ;
     RECT  1.224 48.475 1.242 48.839 ;
     RECT  1.152 49.099 1.17 49.739 ;
     RECT  2.415 48.695 25.326 50.333 ;
     RECT  3.528 50.333 25.326 50.891 ;
     RECT  2.415 50.333 2.697 51.061 ;
     RECT  1.152 50.923 1.17 51.089 ;
     RECT  3.528 50.891 21.798 51.205 ;
     RECT  2.415 51.061 2.754 51.331 ;
     RECT  3.492 51.205 21.798 51.331 ;
     RECT  26.064 7.115 39.366 51.359 ;
     RECT  22.644 50.891 25.326 52.051 ;
     RECT  1.224 51.547 1.242 52.157 ;
     RECT  2.304 51.331 21.798 52.213 ;
     RECT  22.608 52.051 25.326 52.213 ;
     RECT  2.304 52.213 25.326 52.249 ;
     RECT  26.1 51.359 39.366 52.249 ;
     RECT  2.304 52.249 39.366 52.313 ;
     RECT  2.304 52.313 2.697 52.349 ;
     RECT  3.528 52.313 39.366 52.589 ;
     RECT  22.644 52.589 39.366 52.817 ;
     RECT  2.415 52.349 2.697 53.221 ;
     RECT  3.528 52.589 21.798 53.221 ;
     RECT  2.304 53.221 21.798 53.699 ;
     RECT  2.304 53.699 2.754 54.095 ;
     RECT  27.36 52.817 39.366 54.187 ;
     RECT  2.415 54.095 2.754 54.571 ;
     RECT  3.528 53.699 21.798 54.571 ;
     RECT  2.415 54.571 21.798 54.671 ;
     RECT  22.644 52.817 26.514 54.751 ;
     RECT  27.252 54.187 39.366 54.751 ;
     RECT  3.528 54.671 21.798 54.877 ;
     RECT  22.644 54.751 39.366 54.877 ;
     RECT  3.528 54.877 39.366 55.175 ;
     RECT  1.152 52.681 1.17 55.229 ;
     RECT  22.644 55.175 39.366 55.319 ;
     RECT  2.415 54.671 2.697 55.831 ;
     RECT  3.528 55.175 21.798 55.831 ;
     RECT  27.36 55.319 39.366 55.949 ;
     RECT  84.888 55.051 84.906 56.057 ;
     RECT  0.576 55.819 0.594 56.489 ;
     RECT  22.644 55.319 26.442 56.767 ;
     RECT  27.36 55.949 27.486 56.767 ;
     RECT  1.152 57.001 1.17 57.053 ;
     RECT  22.644 56.767 27.486 57.811 ;
     RECT  28.332 55.949 39.366 57.811 ;
     RECT  2.415 55.831 21.798 57.847 ;
     RECT  22.644 57.811 39.366 57.847 ;
     RECT  2.415 57.847 39.366 58.253 ;
     RECT  1.152 58.219 1.17 58.379 ;
     RECT  2.415 58.253 21.87 58.649 ;
     RECT  2.415 58.649 2.697 58.843 ;
     RECT  1.728 58.843 2.697 58.919 ;
     RECT  22.644 58.253 39.366 59.261 ;
     RECT  2.304 58.919 2.697 59.639 ;
     RECT  3.42 58.649 21.87 59.971 ;
     RECT  22.644 59.261 30.654 59.971 ;
     RECT  2.415 59.639 2.697 60.091 ;
     RECT  3.42 59.971 30.654 60.091 ;
     RECT  2.415 60.091 30.654 60.715 ;
     RECT  1.728 60.715 30.654 61.465 ;
     RECT  31.392 59.261 39.366 61.465 ;
     RECT  1.728 61.465 39.366 61.529 ;
     RECT  3.492 61.529 39.366 62.033 ;
     RECT  3.492 62.033 21.798 63.049 ;
     RECT  22.572 62.033 39.366 63.049 ;
     RECT  1.728 61.529 2.697 63.661 ;
     RECT  3.492 63.049 39.366 63.661 ;
     RECT  1.728 63.661 39.366 65.813 ;
     RECT  1.728 65.813 2.697 66.793 ;
     RECT  3.456 65.813 39.366 66.793 ;
     RECT  1.728 66.793 39.366 66.893 ;
     RECT  3.456 66.893 39.366 67.909 ;
     RECT  1.728 66.893 2.697 67.981 ;
     RECT  3.42 67.909 39.366 67.981 ;
     RECT  1.728 67.981 39.366 68.207 ;
     RECT  1.728 68.207 21.798 68.285 ;
     RECT  3.456 68.285 21.798 69.187 ;
     RECT  22.572 68.207 39.366 69.187 ;
     RECT  1.728 68.285 2.697 69.197 ;
     RECT  2.415 69.197 2.697 69.223 ;
     RECT  3.456 69.187 39.366 69.223 ;
     RECT  2.415 69.223 39.366 70.439 ;
     RECT  2.415 70.439 21.798 70.507 ;
     RECT  1.728 70.507 21.798 71.879 ;
     RECT  2.415 71.879 21.798 72.841 ;
     RECT  22.572 70.439 39.366 72.841 ;
     RECT  2.415 72.841 39.366 72.907 ;
     RECT  1.728 72.907 39.366 72.959 ;
     RECT  2.268 72.959 39.366 74.155 ;
     RECT  1.728 74.155 39.366 74.309 ;
     RECT  2.415 74.309 39.366 75.355 ;
     RECT  1.728 75.355 39.366 76.073 ;
     RECT  75.924 7.655 79.866 76.271 ;
     RECT  1.728 76.073 2.697 76.919 ;
     RECT  2.415 76.919 2.697 77.131 ;
     RECT  3.456 76.073 39.366 77.131 ;
     RECT  2.415 77.131 39.366 77.971 ;
     RECT  2.304 77.971 39.366 78.125 ;
     RECT  1.152 78.331 1.17 78.989 ;
     RECT  2.415 78.125 2.697 79.591 ;
     RECT  3.456 78.125 39.366 79.591 ;
     RECT  2.415 79.591 39.366 80.671 ;
     RECT  40.104 6.809 65.394 80.671 ;
     RECT  1.152 80.203 1.17 80.861 ;
     RECT  0.576 81.403 0.594 81.599 ;
     RECT  2.415 80.671 65.394 81.743 ;
     RECT  2.415 81.743 2.697 82.027 ;
     RECT  2.304 82.027 2.697 82.139 ;
     RECT  2.415 82.139 2.697 82.561 ;
     RECT  3.456 81.743 65.394 82.561 ;
     RECT  2.415 82.561 65.394 82.679 ;
     RECT  1.152 82.651 1.17 82.949 ;
     RECT  2.415 82.679 5.958 83.191 ;
     RECT  2.304 83.191 5.958 83.261 ;
     RECT  1.152 83.851 1.17 84.029 ;
     RECT  2.415 83.261 5.958 84.173 ;
     RECT  3.456 84.173 5.958 84.181 ;
     RECT  6.696 82.679 65.394 84.181 ;
     RECT  3.456 84.181 65.394 84.839 ;
     RECT  2.415 84.173 2.697 85.225 ;
     RECT  3.456 84.839 41.238 85.225 ;
     RECT  2.415 85.225 41.238 85.927 ;
     RECT  42.012 84.839 65.394 85.927 ;
     RECT  2.415 85.927 65.394 86.063 ;
     RECT  1.152 85.051 1.17 86.459 ;
     RECT  2.415 86.063 2.697 86.923 ;
     RECT  2.304 86.923 2.697 86.999 ;
     RECT  2.415 86.999 2.697 87.511 ;
     RECT  3.456 86.063 65.394 87.511 ;
     RECT  1.152 87.499 1.17 88.157 ;
     RECT  1.152 89.941 1.17 89.981 ;
     RECT  75.996 76.271 79.866 90.653 ;
     RECT  0.576 90.571 0.594 90.779 ;
     RECT  2.415 87.511 65.394 90.923 ;
     RECT  1.152 91.195 1.17 91.319 ;
     RECT  2.415 90.923 2.697 91.831 ;
     RECT  3.456 90.923 65.394 91.831 ;
     RECT  0.108 91.771 0.126 91.901 ;
     RECT  1.152 92.371 1.17 92.429 ;
     RECT  86.292 91.771 86.31 92.543 ;
     RECT  2.415 91.831 65.394 93.091 ;
     RECT  2.304 93.091 65.394 93.245 ;
     RECT  1.224 93.019 1.242 93.389 ;
     RECT  76.176 90.653 79.866 93.595 ;
     RECT  80.676 9.419 83.697 93.595 ;
     RECT  1.152 93.595 1.17 93.749 ;
     RECT  2.415 93.245 65.394 93.821 ;
     RECT  76.176 93.595 83.697 94.289 ;
     RECT  2.415 93.821 2.697 94.981 ;
     RECT  3.456 93.821 65.394 94.981 ;
     RECT  2.415 94.981 65.394 95.021 ;
     RECT  2.415 95.021 2.697 96.061 ;
     RECT  3.42 95.021 65.394 96.061 ;
     RECT  1.152 94.843 1.17 96.179 ;
     RECT  2.415 96.061 65.394 96.323 ;
     RECT  2.415 96.323 2.697 96.667 ;
     RECT  2.304 96.667 2.697 96.719 ;
     RECT  1.152 97.231 1.17 97.325 ;
     RECT  2.415 96.719 2.697 97.411 ;
     RECT  3.456 96.323 65.394 97.411 ;
     RECT  2.415 97.411 65.394 97.771 ;
     RECT  1.728 97.771 65.394 97.853 ;
     RECT  76.176 94.289 82.134 99.149 ;
     RECT  2.415 97.853 65.394 99.643 ;
     RECT  1.728 99.643 65.394 100.679 ;
     RECT  2.415 100.679 65.394 101.551 ;
     RECT  1.728 101.551 65.394 103.073 ;
     RECT  1.728 103.073 2.697 103.469 ;
     RECT  2.415 103.469 2.697 103.981 ;
     RECT  3.42 103.073 65.394 103.981 ;
     RECT  2.415 103.981 65.394 104.521 ;
     RECT  1.728 104.521 65.394 104.573 ;
     RECT  2.304 104.573 65.394 105.389 ;
     RECT  2.304 105.389 2.697 105.935 ;
     RECT  2.376 105.935 2.697 105.965 ;
     RECT  2.415 105.965 2.697 106.951 ;
     RECT  3.492 105.389 65.394 107.095 ;
     RECT  1.728 106.951 2.697 107.563 ;
     RECT  3.456 107.095 65.394 107.563 ;
     RECT  1.728 107.563 65.394 108.329 ;
     RECT  2.415 108.329 65.394 109.531 ;
     RECT  1.728 109.531 65.394 110.363 ;
     RECT  3.42 110.363 65.394 110.399 ;
     RECT  1.728 110.363 2.697 110.939 ;
     RECT  2.415 110.939 2.697 111.307 ;
     RECT  3.492 110.399 65.394 111.307 ;
     RECT  2.415 111.307 65.394 111.883 ;
     RECT  2.304 111.883 65.394 111.979 ;
     RECT  1.728 111.979 65.394 112.289 ;
     RECT  1.728 112.289 2.697 113.369 ;
     RECT  2.415 113.369 2.697 113.701 ;
     RECT  3.492 112.289 65.394 113.701 ;
     RECT  2.415 113.701 65.394 114.313 ;
     RECT  2.304 114.313 65.394 114.379 ;
     RECT  1.728 114.379 65.394 115.619 ;
     RECT  2.415 115.619 65.394 116.189 ;
     RECT  2.415 116.189 2.697 116.827 ;
     RECT  1.728 116.827 2.697 116.969 ;
     RECT  2.415 116.969 2.697 117.391 ;
     RECT  3.492 116.189 65.394 117.391 ;
     RECT  1.152 117.403 1.17 117.509 ;
     RECT  1.152 119.227 1.17 119.939 ;
     RECT  2.415 117.391 65.394 121.981 ;
     RECT  2.304 121.981 65.394 122.099 ;
     RECT  2.304 122.099 57.906 122.135 ;
     RECT  1.116 121.675 1.134 122.279 ;
     RECT  1.152 122.299 1.17 122.909 ;
     RECT  2.415 122.135 57.906 123.533 ;
     RECT  3.492 123.533 57.906 124.375 ;
     RECT  3.456 124.375 57.906 124.411 ;
     RECT  58.752 122.099 65.394 124.411 ;
     RECT  0.576 124.123 0.594 124.529 ;
     RECT  3.456 124.411 65.394 124.529 ;
     RECT  2.415 123.533 2.697 124.573 ;
     RECT  2.376 124.573 2.697 124.681 ;
     RECT  1.224 124.573 1.242 124.733 ;
     RECT  2.304 124.681 2.697 124.835 ;
     RECT  2.415 124.835 2.697 125.653 ;
     RECT  3.492 124.529 65.394 125.653 ;
     RECT  2.415 125.653 65.394 125.761 ;
     RECT  2.304 125.761 65.394 125.879 ;
     RECT  2.304 125.879 2.697 125.923 ;
     RECT  2.232 125.923 2.697 126.059 ;
     RECT  1.152 125.311 1.17 126.689 ;
     RECT  76.176 99.149 81.918 126.689 ;
     RECT  82.908 94.289 83.697 126.697 ;
     RECT  2.415 126.059 2.697 127.075 ;
     RECT  3.492 125.879 65.394 127.075 ;
     RECT  2.415 127.075 65.394 127.111 ;
     RECT  2.304 127.111 65.394 127.337 ;
     RECT  81.54 126.689 81.918 127.651 ;
     RECT  82.656 126.697 83.697 127.651 ;
     RECT  1.224 127.147 1.242 127.877 ;
     RECT  2.304 127.337 2.697 127.949 ;
     RECT  81.54 127.651 83.697 128.381 ;
     RECT  2.415 127.949 2.697 128.395 ;
     RECT  3.492 127.337 65.394 128.395 ;
     RECT  86.292 128.347 86.31 128.525 ;
     RECT  2.415 128.395 65.394 128.821 ;
     RECT  1.224 128.971 1.242 129.629 ;
     RECT  1.152 130.207 1.17 130.253 ;
     RECT  2.304 128.821 65.394 130.505 ;
     RECT  2.415 130.505 65.394 131.701 ;
     RECT  2.304 131.701 65.394 131.855 ;
     RECT  1.116 131.419 1.134 132.043 ;
     RECT  1.116 132.043 1.17 132.089 ;
     RECT  81.54 128.381 81.918 132.871 ;
     RECT  0.576 132.667 0.594 132.899 ;
     RECT  76.176 126.689 80.766 133.045 ;
     RECT  81.54 132.871 82.098 133.045 ;
     RECT  76.176 133.045 82.098 133.085 ;
     RECT  2.415 131.855 65.394 133.321 ;
     RECT  76.176 133.085 80.766 133.861 ;
     RECT  81.54 133.085 82.098 133.861 ;
     RECT  76.176 133.861 82.098 133.901 ;
     RECT  76.176 133.901 80.766 133.963 ;
     RECT  81.504 133.901 82.098 133.963 ;
     RECT  82.908 128.381 83.697 133.963 ;
     RECT  75.852 133.963 80.766 134.249 ;
     RECT  2.304 133.321 65.394 134.285 ;
     RECT  66.42 6.845 74.934 134.401 ;
     RECT  1.116 133.243 1.134 134.429 ;
     RECT  66.42 134.401 74.97 134.477 ;
     RECT  81.504 133.963 83.697 134.477 ;
     RECT  1.152 134.485 1.17 134.525 ;
     RECT  81.504 134.477 82.17 134.789 ;
     RECT  2.415 134.285 65.394 135.031 ;
     RECT  2.304 135.031 65.394 135.149 ;
     RECT  2.415 135.149 65.394 136.291 ;
     RECT  2.304 136.291 65.394 136.489 ;
     RECT  1.152 136.315 1.17 136.589 ;
     RECT  2.304 136.489 65.43 136.687 ;
     RECT  2.304 136.687 65.466 136.921 ;
     RECT  66.42 134.477 74.934 136.921 ;
     RECT  2.304 136.921 74.934 137.057 ;
     RECT  2.304 137.057 65.61 137.129 ;
     RECT  76.176 134.249 80.766 137.911 ;
     RECT  66.6 137.057 74.934 138.145 ;
     RECT  2.415 137.129 65.61 138.685 ;
     RECT  66.528 138.145 74.934 138.685 ;
     RECT  2.415 138.685 74.934 138.763 ;
     RECT  1.728 138.763 74.934 139.997 ;
     RECT  2.415 139.997 74.934 141.151 ;
     RECT  2.304 141.151 74.934 141.781 ;
     RECT  1.728 141.781 74.934 141.821 ;
     RECT  2.415 141.821 74.934 143.611 ;
     RECT  1.728 143.611 74.934 144.509 ;
     RECT  2.304 144.509 74.934 144.797 ;
     RECT  2.415 144.797 74.934 146.281 ;
     RECT  2.304 146.281 74.934 146.641 ;
     RECT  1.728 146.641 74.934 147.293 ;
     RECT  2.415 147.293 74.934 147.749 ;
     RECT  2.415 147.749 74.898 148.441 ;
     RECT  2.304 148.441 74.898 148.507 ;
     RECT  1.728 148.507 74.898 149.369 ;
     RECT  1.728 149.369 73.062 149.909 ;
     RECT  2.415 149.909 73.062 151.003 ;
     RECT  1.728 151.003 73.062 151.375 ;
     RECT  73.8 149.369 74.898 151.375 ;
     RECT  1.728 151.375 74.898 151.907 ;
     RECT  1.728 151.907 73.422 152.519 ;
     RECT  74.16 151.907 74.898 153.031 ;
     RECT  2.415 152.519 73.422 153.301 ;
     RECT  74.16 153.031 74.934 153.301 ;
     RECT  2.415 153.301 74.934 153.391 ;
     RECT  1.728 153.391 74.934 153.437 ;
     RECT  2.304 153.437 74.934 154.651 ;
     RECT  1.728 154.651 74.934 154.769 ;
     RECT  2.415 154.769 74.934 154.885 ;
     RECT  2.415 154.885 75.042 155.047 ;
     RECT  75.852 137.911 80.766 155.047 ;
     RECT  2.415 155.047 80.766 155.821 ;
     RECT  1.728 155.821 80.766 155.885 ;
     RECT  2.415 155.885 80.766 156.901 ;
     RECT  1.152 156.397 1.17 157.109 ;
     RECT  2.304 156.901 80.766 157.235 ;
     RECT  0.108 157.675 0.126 157.805 ;
     RECT  1.152 158.251 1.17 158.909 ;
     RECT  0.576 159.499 0.594 159.629 ;
     RECT  2.415 157.235 80.766 160.015 ;
     RECT  81.54 134.789 81.918 160.015 ;
     RECT  2.415 160.015 81.918 160.439 ;
     RECT  82.908 134.477 83.697 161.635 ;
     RECT  1.152 160.681 1.17 162.059 ;
     RECT  2.415 160.439 79.722 162.329 ;
     RECT  2.415 162.329 36.846 162.523 ;
     RECT  2.304 162.523 36.846 162.599 ;
     RECT  37.8 162.329 79.722 163.409 ;
     RECT  37.872 163.409 79.722 163.795 ;
     RECT  80.532 160.439 81.918 163.795 ;
     RECT  1.152 163.111 1.17 163.949 ;
     RECT  2.415 162.599 36.846 164.371 ;
     RECT  2.304 164.371 36.846 164.489 ;
     RECT  37.872 163.795 81.918 164.489 ;
     RECT  2.304 164.489 27.63 164.525 ;
     RECT  1.224 164.347 1.242 164.669 ;
     RECT  82.692 161.635 83.697 165.073 ;
     RECT  82.656 165.073 83.697 165.149 ;
     RECT  2.415 164.525 27.63 165.721 ;
     RECT  2.34 165.721 27.63 165.875 ;
     RECT  1.152 165.595 1.17 166.379 ;
     RECT  2.415 165.875 27.63 166.657 ;
     RECT  2.376 166.657 27.63 166.801 ;
     RECT  1.224 166.657 1.242 166.829 ;
     RECT  2.304 166.801 27.63 166.955 ;
     RECT  38.016 164.489 81.918 167.659 ;
     RECT  82.692 165.149 83.697 167.659 ;
     RECT  1.152 167.419 1.17 168.077 ;
     RECT  0.576 168.619 0.594 168.809 ;
     RECT  2.415 166.955 27.63 169.231 ;
     RECT  2.304 169.231 27.63 169.385 ;
     RECT  1.116 169.243 1.134 169.529 ;
     RECT  1.152 169.861 1.17 169.901 ;
     RECT  2.415 169.385 27.63 170.401 ;
     RECT  2.412 170.401 27.63 170.437 ;
     RECT  28.368 164.489 36.846 170.437 ;
     RECT  2.412 170.437 36.846 170.525 ;
     RECT  1.152 171.067 1.17 171.779 ;
     RECT  2.415 170.525 36.846 172.201 ;
     RECT  2.304 172.201 36.846 172.355 ;
     RECT  1.224 172.315 1.242 172.499 ;
     RECT  1.152 172.831 1.17 173.579 ;
     RECT  2.415 172.355 36.846 174.091 ;
     RECT  1.224 174.139 1.242 174.389 ;
     RECT  2.304 174.091 36.846 175.517 ;
     RECT  2.415 175.517 36.846 177.295 ;
     RECT  2.376 177.295 36.846 177.565 ;
     RECT  2.34 177.565 36.846 177.727 ;
     RECT  38.016 167.659 83.697 177.997 ;
     RECT  1.728 177.727 36.846 178.403 ;
     RECT  2.34 178.403 36.846 178.645 ;
     RECT  2.34 178.645 36.954 178.681 ;
     RECT  38.016 177.997 83.754 178.681 ;
     RECT  2.34 178.681 37.242 178.915 ;
     RECT  38.016 178.681 83.862 178.915 ;
     RECT  1.188 178.915 1.206 178.973 ;
     RECT  2.34 178.915 83.862 179.185 ;
     RECT  2.34 179.185 83.97 179.221 ;
     RECT  2.34 179.221 84.042 179.339 ;
     RECT  2.34 179.339 26.514 179.455 ;
     RECT  1.692 179.455 26.514 179.501 ;
     RECT  27.288 179.339 84.042 179.725 ;
     RECT  2.34 179.501 26.514 180.265 ;
     RECT  1.764 180.265 26.514 180.301 ;
     RECT  27.288 179.725 84.402 180.301 ;
     RECT  1.764 180.301 84.402 180.427 ;
     RECT  1.692 180.427 84.402 181.075 ;
     RECT  0.576 180.967 0.594 181.111 ;
     RECT  1.692 181.075 84.474 181.111 ;
     RECT  0.576 181.111 84.474 181.181 ;
     RECT  1.764 181.181 84.474 181.229 ;
     RECT  1.764 181.229 3.726 181.265 ;
     RECT  5.688 181.229 84.474 181.265 ;
     RECT  0.576 181.181 0.594 181.277 ;
     RECT  6.552 181.265 84.474 181.277 ;
     RECT  28.872 181.277 29.79 181.337 ;
     RECT  5.688 181.265 5.742 181.409 ;
     RECT  68.364 181.277 68.382 181.421 ;
     RECT  1.764 181.265 3.402 181.457 ;
     RECT  13.215 181.277 13.374 181.457 ;
     RECT  18.615 181.277 27.954 181.457 ;
     RECT  51.015 181.277 51.174 181.457 ;
     RECT  67.215 181.277 67.554 181.457 ;
     RECT  28.872 181.337 29.754 181.517 ;
     RECT  72.18 181.277 72.774 181.565 ;
     RECT  13.356 181.457 13.374 181.613 ;
     RECT  28.872 181.517 29.574 181.613 ;
     RECT  51.156 181.457 51.174 181.613 ;
     RECT  10.944 181.277 10.962 181.757 ;
     RECT  12.132 181.277 12.15 181.757 ;
     RECT  14.724 181.277 15.39 181.757 ;
     RECT  16.236 181.277 16.254 181.757 ;
     RECT  17.424 181.277 17.442 181.757 ;
     RECT  28.872 181.613 28.89 181.757 ;
     RECT  30.924 181.277 30.942 181.757 ;
     RECT  32.652 181.277 32.994 181.757 ;
     RECT  34.38 181.277 35.586 181.757 ;
     RECT  49.932 181.277 50.274 181.757 ;
     RECT  54.036 181.277 54.054 181.757 ;
     RECT  67.536 181.457 67.554 181.757 ;
     RECT  69.588 181.277 69.606 181.757 ;
     RECT  72.18 181.565 72.198 181.757 ;
     RECT  74.232 181.277 74.25 181.757 ;
     RECT  75.132 181.277 84.474 181.757 ;
     RECT  4.5 181.229 4.518 181.853 ;
     RECT  6.552 181.277 9.234 181.853 ;
     RECT  18.936 181.457 27.954 181.853 ;
     RECT  36.468 181.277 46.746 181.853 ;
     RECT  56.376 181.277 65.502 181.853 ;
     RECT  75.132 181.757 84.402 181.853 ;
     RECT  2.88 181.457 3.402 182.093 ;
     RECT  6.552 181.853 7.182 182.381 ;
     RECT  9.216 181.853 9.234 182.381 ;
     RECT  19.476 181.853 19.494 182.381 ;
     RECT  22.716 181.853 22.734 182.381 ;
     RECT  23.58 181.853 23.598 182.381 ;
     RECT  24.444 181.853 24.462 182.381 ;
     RECT  25.308 181.853 27.378 182.381 ;
     RECT  37.62 181.853 38.574 182.381 ;
     RECT  39.996 181.853 40.014 182.381 ;
     RECT  40.86 181.853 41.562 182.381 ;
     RECT  42.588 181.853 42.93 182.381 ;
     RECT  57.276 181.853 57.294 182.381 ;
     RECT  60.192 181.853 60.21 182.381 ;
     RECT  76.284 181.853 76.302 182.381 ;
     RECT  77.472 181.853 77.49 182.381 ;
     RECT  78.336 181.853 78.354 182.381 ;
     RECT  79.2 181.853 80.406 182.381 ;
     RECT  81.252 181.853 81.27 182.381 ;
     RECT  85.464 181.237 85.482 182.381 ;
     RECT  5.688 181.409 5.706 182.429 ;
     RECT  6.552 182.381 6.57 182.429 ;
     RECT  26.208 182.381 26.766 182.429 ;
     RECT  41.544 182.381 41.562 182.429 ;
     RECT  82.548 181.853 84.042 182.429 ;
     RECT  38.124 182.381 38.574 182.477 ;
     RECT  83.736 182.429 84.042 182.525 ;
     RECT  1.764 181.457 1.782 182.957 ;
     RECT  82.548 182.429 82.566 182.957 ;
     RECT  84.024 182.525 84.042 183.005 ;
     RECT  2.88 182.093 2.898 183.485 ;
    LAYER M4 ;
     RECT  0.025 6.24 0.06 6.264 ;
     RECT  0.06 0.288 0.085 19.224 ;
     RECT  0.06 39.312 0.085 58.248 ;
     RECT  0.06 78.384 0.085 97.32 ;
     RECT  0.06 117.408 0.085 136.344 ;
     RECT  0.06 156.432 0.085 175.368 ;
     RECT  0.085 0.288 0.133 105.384 ;
     RECT  0.133 0.144 0.137 105.384 ;
     RECT  0.137 0.144 0.229 5.208 ;
     RECT  0.137 6.384 0.517 105.384 ;
     RECT  0.085 106.992 0.517 175.368 ;
     RECT  0.517 6.384 0.605 105.96 ;
     RECT  0.517 106.992 0.605 175.512 ;
     RECT  0.085 180.48 1.141 181.272 ;
     RECT  0.605 13.104 1.145 38.712 ;
     RECT  0.605 39.936 1.145 45.432 ;
     RECT  0.605 106.992 1.145 123.528 ;
     RECT  0.605 124.704 1.145 132.072 ;
     RECT  0.605 133.248 1.145 158.904 ;
     RECT  0.605 169.248 1.145 175.512 ;
     RECT  1.145 13.104 1.181 18.6 ;
     RECT  1.145 39.936 1.181 43.032 ;
     RECT  1.145 44.208 1.181 45.432 ;
     RECT  0.605 47.28 1.181 55.224 ;
     RECT  0.605 57.024 1.181 80.856 ;
     RECT  0.605 82.032 1.181 89.976 ;
     RECT  0.605 91.2 1.181 105.96 ;
     RECT  1.145 106.992 1.181 121.08 ;
     RECT  1.145 122.304 1.181 123.528 ;
     RECT  1.145 124.704 1.181 130.872 ;
     RECT  1.145 132.048 1.181 132.072 ;
     RECT  1.145 134.496 1.181 158.904 ;
     RECT  0.605 160.128 1.181 168.072 ;
     RECT  1.145 169.872 1.181 175.512 ;
     RECT  0.085 177.792 1.237 179.112 ;
     RECT  1.141 180.336 1.237 181.272 ;
     RECT  1.181 40.56 1.253 41.208 ;
     RECT  1.181 42.384 1.253 43.032 ;
     RECT  1.181 47.856 1.253 48.504 ;
     RECT  1.181 51.552 1.253 52.152 ;
     RECT  1.181 93.024 1.253 93.048 ;
     RECT  1.181 124.704 1.253 124.728 ;
     RECT  1.181 127.152 1.253 129.624 ;
     RECT  1.181 164.352 1.253 165 ;
     RECT  1.181 166.8 1.253 166.824 ;
     RECT  1.181 172.32 1.253 172.344 ;
     RECT  1.181 174.144 1.253 175.512 ;
     RECT  1.237 177.792 1.283 181.272 ;
     RECT  0.133 183.456 1.709 183.48 ;
     RECT  1.709 182.928 1.793 183.48 ;
     RECT  0.605 6.384 2.197 9.576 ;
     RECT  1.181 135.12 2.293 135.72 ;
     RECT  1.181 136.896 2.293 155.88 ;
     RECT  1.283 180.48 2.341 181.272 ;
     RECT  0.229 0.048 2.408 5.208 ;
     RECT  2.197 6.288 2.408 9.576 ;
     RECT  0.605 10.656 2.408 11.208 ;
     RECT  1.181 13.728 2.408 13.752 ;
     RECT  1.181 16.176 2.408 16.2 ;
     RECT  1.145 19.872 2.408 38.712 ;
     RECT  1.253 40.56 2.408 40.584 ;
     RECT  1.253 43.008 2.408 43.032 ;
     RECT  1.181 45.408 2.408 45.432 ;
     RECT  1.253 47.856 2.408 47.88 ;
     RECT  1.181 50.304 2.408 50.328 ;
     RECT  1.181 57.648 2.408 57.672 ;
     RECT  1.181 58.848 2.408 78.072 ;
     RECT  1.181 79.584 2.408 79.608 ;
     RECT  1.181 82.032 2.408 82.056 ;
     RECT  1.181 83.232 2.408 83.256 ;
     RECT  1.181 84.48 2.408 84.504 ;
     RECT  1.181 86.928 2.408 86.952 ;
     RECT  1.181 88.752 2.408 89.352 ;
     RECT  1.181 91.872 2.408 91.896 ;
     RECT  1.181 94.224 2.408 94.248 ;
     RECT  1.181 96.672 2.408 96.696 ;
     RECT  1.181 97.824 2.408 105.96 ;
     RECT  1.181 106.992 2.408 116.856 ;
     RECT  1.181 118.032 2.408 118.632 ;
     RECT  1.181 120.48 2.408 121.08 ;
     RECT  1.181 123.504 2.408 123.528 ;
     RECT  1.253 128.4 2.408 128.424 ;
     RECT  1.181 130.848 2.408 130.872 ;
     RECT  2.293 135.12 2.408 155.88 ;
     RECT  1.181 157.776 2.408 157.8 ;
     RECT  1.181 160.128 2.408 160.152 ;
     RECT  1.181 162.528 2.408 162.552 ;
     RECT  1.253 164.976 2.408 165 ;
     RECT  1.181 170.496 2.408 170.52 ;
     RECT  1.253 174.72 2.408 175.512 ;
     RECT  1.283 177.792 2.408 179.496 ;
     RECT  2.341 180.48 2.408 182.088 ;
     RECT  1.793 183.408 2.531 183.48 ;
     RECT  2.408 0.048 2.704 182.088 ;
     RECT  2.704 6.384 2.765 9.576 ;
     RECT  2.704 178.848 2.801 182.088 ;
     RECT  2.704 60.096 2.819 60.648 ;
     RECT  2.704 77.136 2.819 77.928 ;
     RECT  2.704 26.736 2.867 26.76 ;
     RECT  2.704 54.096 2.867 54.12 ;
     RECT  2.704 120.48 2.867 121.992 ;
     RECT  2.704 128.4 2.867 129.144 ;
     RECT  2.704 140.592 2.867 143.016 ;
     RECT  2.704 144.288 2.867 144.312 ;
     RECT  2.704 148.032 2.867 148.344 ;
     RECT  2.765 7.632 2.873 9.576 ;
     RECT  2.704 10.656 2.873 11.208 ;
     RECT  2.704 19.872 2.873 19.896 ;
     RECT  2.704 33.264 2.873 34.008 ;
     RECT  2.704 38.16 2.873 38.184 ;
     RECT  2.704 40.56 2.873 41.304 ;
     RECT  2.704 57.648 2.873 58.104 ;
     RECT  2.819 60.096 2.873 60.12 ;
     RECT  2.704 69.84 2.873 69.864 ;
     RECT  2.704 72.24 2.873 72.264 ;
     RECT  2.704 74.688 2.873 75.576 ;
     RECT  2.819 77.136 2.873 77.16 ;
     RECT  2.704 91.872 2.873 91.896 ;
     RECT  2.704 104.016 2.873 104.04 ;
     RECT  2.704 116.16 2.873 116.184 ;
     RECT  2.704 130.848 2.873 130.872 ;
     RECT  2.704 137.52 2.873 138.168 ;
     RECT  2.867 140.592 2.873 140.616 ;
     RECT  2.867 142.368 2.873 143.016 ;
     RECT  2.704 145.584 2.873 145.608 ;
     RECT  2.867 148.032 2.873 148.056 ;
     RECT  2.704 150.288 2.873 150.984 ;
     RECT  2.704 152.88 2.873 152.904 ;
     RECT  2.531 183.456 2.909 183.48 ;
     RECT  2.867 120.48 2.981 121.08 ;
     RECT  2.873 142.368 2.981 142.392 ;
     RECT  2.704 117.936 3.059 119.208 ;
     RECT  2.704 101.04 3.089 101.064 ;
     RECT  2.704 50.304 3.161 50.328 ;
     RECT  2.704 97.488 3.161 99.72 ;
     RECT  2.704 48.96 3.203 48.984 ;
     RECT  2.873 9.552 3.269 9.576 ;
     RECT  2.704 43.008 3.269 43.032 ;
     RECT  2.704 113.76 3.269 115.128 ;
     RECT  2.704 135.696 3.269 135.72 ;
     RECT  2.704 17.04 3.299 17.064 ;
     RECT  2.704 24.048 3.299 24.072 ;
     RECT  2.704 30.864 3.299 31.56 ;
     RECT  2.873 33.984 3.299 34.008 ;
     RECT  2.873 41.28 3.299 41.304 ;
     RECT  2.704 63.696 3.299 63.72 ;
     RECT  2.704 65.328 3.299 65.352 ;
     RECT  2.704 68.256 3.299 68.28 ;
     RECT  2.873 75.552 3.299 75.576 ;
     RECT  2.704 82.608 3.299 82.632 ;
     RECT  2.704 89.856 3.299 89.976 ;
     RECT  2.704 94.992 3.299 95.016 ;
     RECT  2.704 108.72 3.299 109.32 ;
     RECT  2.704 131.952 3.299 131.976 ;
     RECT  2.873 150.96 3.299 150.984 ;
     RECT  2.704 170.88 3.299 170.904 ;
     RECT  3.299 30.864 3.305 30.888 ;
     RECT  2.704 123.504 3.305 123.528 ;
     RECT  2.704 155.328 3.305 155.352 ;
     RECT  2.801 178.944 3.305 182.088 ;
     RECT  2.704 111.312 3.341 112.392 ;
     RECT  2.704 87.936 3.377 88.776 ;
     RECT  3.161 99.168 3.377 99.72 ;
     RECT  2.704 35.952 3.395 35.976 ;
     RECT  2.981 121.056 3.413 121.08 ;
     RECT  2.867 128.4 3.413 128.424 ;
     RECT  3.305 178.944 3.413 181.08 ;
     RECT  3.305 182.064 3.413 182.088 ;
     RECT  2.873 58.08 3.443 58.104 ;
     RECT  2.704 81.456 3.443 81.48 ;
     RECT  3.341 112.032 3.443 112.392 ;
     RECT  2.704 134.4 3.443 134.424 ;
     RECT  3.299 108.72 3.449 108.744 ;
     RECT  3.269 114.528 3.449 115.128 ;
     RECT  3.059 118.608 3.485 119.208 ;
     RECT  2.704 175.008 3.491 175.032 ;
     RECT  3.413 178.944 3.521 180.648 ;
     RECT  2.704 47.856 3.593 47.88 ;
     RECT  2.704 157.776 3.629 158.472 ;
     RECT  2.704 177.168 3.629 177.192 ;
     RECT  3.449 115.104 3.635 115.128 ;
     RECT  3.692 12.192 3.733 12.216 ;
     RECT  3.299 89.952 3.737 89.976 ;
     RECT  3.485 119.184 3.737 119.208 ;
     RECT  3.733 12.192 3.779 12.552 ;
     RECT  3.74 123.936 3.827 123.96 ;
     RECT  2.765 6.384 3.836 6.408 ;
     RECT  2.873 7.632 3.836 8.232 ;
     RECT  3.521 180.144 3.845 180.648 ;
     RECT  3.521 178.944 3.905 178.968 ;
     RECT  3.836 6.384 3.923 8.232 ;
     RECT  2.704 56.4 3.953 56.424 ;
     RECT  3.769 14.784 3.971 14.808 ;
     RECT  3.443 112.368 3.971 112.392 ;
     RECT  3.877 134.544 3.98 134.568 ;
     RECT  3.98 134.544 3.989 134.952 ;
     RECT  3.905 178.416 3.989 178.968 ;
     RECT  2.704 102.576 4.021 102.6 ;
     RECT  3.973 106.416 4.061 106.44 ;
     RECT  3.989 178.944 4.061 178.968 ;
     RECT  3.98 109.968 4.067 109.992 ;
     RECT  3.98 128.016 4.067 128.04 ;
     RECT  3.989 134.928 4.067 134.952 ;
     RECT  4.085 38.784 4.169 38.808 ;
     RECT  4.193 60.624 4.277 60.648 ;
     RECT  3.161 97.488 4.277 97.704 ;
     RECT  4.021 102.528 4.277 102.6 ;
     RECT  4.22 132.336 4.307 132.36 ;
     RECT  3.845 180.288 4.313 180.648 ;
     RECT  3.779 12.528 4.421 12.552 ;
     RECT  4.357 173.52 4.444 173.544 ;
     RECT  3.973 26.784 4.481 26.808 ;
     RECT  4.405 125.328 4.493 125.352 ;
     RECT  4.405 177.024 4.493 177.048 ;
     RECT  4.412 9.744 4.499 9.768 ;
     RECT  4.021 160.704 4.499 160.728 ;
     RECT  4.412 166.848 4.499 166.872 ;
     RECT  4.129 46.512 4.501 46.536 ;
     RECT  2.704 86.016 4.501 86.04 ;
     RECT  4.277 102.576 4.501 102.6 ;
     RECT  2.704 51.504 4.525 51.528 ;
     RECT  2.704 71.232 4.525 71.256 ;
     RECT  2.704 105.36 4.525 105.384 ;
     RECT  3.973 144.288 4.525 144.312 ;
     RECT  4.313 180.528 4.525 180.648 ;
     RECT  4.46 181.824 4.525 181.848 ;
     RECT  4.501 102.576 4.529 102.84 ;
     RECT  3.949 107.952 4.529 107.976 ;
     RECT  4.453 139.104 4.537 139.128 ;
     RECT  4.453 151.536 4.54 151.56 ;
     RECT  4.453 44.448 4.547 44.472 ;
     RECT  4.501 85.344 4.547 86.04 ;
     RECT  4.46 90.24 4.547 90.264 ;
     RECT  4.165 96.288 4.547 96.312 ;
     RECT  4.381 128.592 4.547 128.616 ;
     RECT  4.46 136.752 4.547 136.776 ;
     RECT  4.525 180.528 4.547 181.848 ;
     RECT  2.704 0.048 4.549 5.208 ;
     RECT  3.923 6.384 4.549 6.408 ;
     RECT  4.481 26.784 4.565 27.336 ;
     RECT  4.525 51.504 4.565 52.488 ;
     RECT  4.481 61.488 4.565 61.512 ;
     RECT  4.525 71.232 4.565 71.832 ;
     RECT  4.261 93.456 4.565 93.48 ;
     RECT  4.277 97.488 4.565 97.512 ;
     RECT  4.525 105.36 4.565 106.392 ;
     RECT  4.525 144.288 4.565 144.792 ;
     RECT  4.481 146.4 4.565 146.424 ;
     RECT  4.489 100.704 4.573 100.728 ;
     RECT  4.501 32.928 4.588 32.952 ;
     RECT  4.501 42.096 4.588 42.12 ;
     RECT  4.501 46.512 4.588 46.68 ;
     RECT  4.501 53.952 4.588 54.12 ;
     RECT  4.501 68.352 4.588 68.376 ;
     RECT  4.501 78.048 4.588 78.072 ;
     RECT  3.973 82.656 4.588 82.68 ;
     RECT  4.547 85.344 4.588 85.368 ;
     RECT  4.529 102.816 4.588 102.84 ;
     RECT  4.501 129.6 4.588 129.624 ;
     RECT  4.501 141.504 4.588 141.528 ;
     RECT  4.501 149.856 4.588 149.88 ;
     RECT  4.501 168.432 4.588 168.456 ;
     RECT  4.501 176.544 4.588 176.568 ;
     RECT  3.377 87.936 4.593 87.96 ;
     RECT  3.629 158.448 4.593 158.472 ;
     RECT  4.549 0.048 4.601 6.408 ;
     RECT  4.549 34.896 4.636 34.92 ;
     RECT  4.601 2.592 4.637 6.408 ;
     RECT  4.588 46.512 4.637 46.536 ;
     RECT  4.556 23.568 4.643 23.592 ;
     RECT  4.481 122.496 4.709 122.52 ;
     RECT  4.565 105.456 4.739 106.392 ;
     RECT  4.789 170.976 4.876 171 ;
     RECT  4.796 156.48 4.883 156.504 ;
     RECT  4.079 37.584 4.885 37.608 ;
     RECT  3.921 64.56 4.988 64.584 ;
     RECT  4.981 86.4 5.029 86.424 ;
     RECT  5.029 86.4 5.069 86.712 ;
     RECT  4.988 64.32 5.075 64.584 ;
     RECT  4.929 153.36 5.075 153.384 ;
     RECT  4.885 37.584 5.123 38.424 ;
     RECT  5.069 86.688 5.123 86.712 ;
     RECT  4.501 76.128 5.125 76.488 ;
     RECT  5.125 75.552 5.141 76.488 ;
     RECT  4.565 52.464 5.209 52.488 ;
     RECT  2.704 73.488 5.213 73.512 ;
     RECT  5.141 75.552 5.249 75.672 ;
     RECT  4.777 160.992 5.249 161.016 ;
     RECT  5.173 165.792 5.26 165.816 ;
     RECT  5.249 75.648 5.267 75.672 ;
     RECT  5.18 110.496 5.267 110.52 ;
     RECT  5.18 159.504 5.267 159.528 ;
     RECT  4.637 2.592 5.285 5.208 ;
     RECT  5.209 52.464 5.293 53.016 ;
     RECT  5.065 164.4 5.317 164.712 ;
     RECT  4.993 179.52 5.353 179.544 ;
     RECT  5.276 86.928 5.363 86.952 ;
     RECT  5.324 143.328 5.365 143.352 ;
     RECT  5.317 164.4 5.401 165.384 ;
     RECT  5.317 115.632 5.404 115.656 ;
     RECT  5.324 88.896 5.411 88.92 ;
     RECT  5.365 143.184 5.411 143.352 ;
     RECT  5.353 91.248 5.437 91.272 ;
     RECT  5.365 16.176 5.452 16.2 ;
     RECT  5.381 171.024 5.465 171.048 ;
     RECT  5.42 147.36 5.507 147.384 ;
     RECT  5.42 169.2 5.507 169.224 ;
     RECT  5.245 19.248 5.569 19.272 ;
     RECT  5.317 93.552 5.651 93.576 ;
     RECT  4.957 17.616 5.653 17.64 ;
     RECT  5.569 18.816 5.653 19.272 ;
     RECT  5.365 15.072 5.673 15.096 ;
     RECT  5.353 178.944 5.677 179.544 ;
     RECT  4.547 180.528 5.677 180.984 ;
     RECT  5.293 52.464 5.681 52.488 ;
     RECT  5.605 13.584 5.692 13.608 ;
     RECT  5.605 157.152 5.692 157.272 ;
     RECT  5.653 17.616 5.699 19.272 ;
     RECT  5.425 59.28 5.699 59.304 ;
     RECT  4.525 39.888 5.701 39.912 ;
     RECT  4.565 71.808 5.708 71.832 ;
     RECT  4.588 54.096 5.713 54.12 ;
     RECT  5.353 154.464 5.717 154.488 ;
     RECT  5.692 157.152 5.725 157.176 ;
     RECT  5.701 39.888 5.747 40.2 ;
     RECT  5.701 35.136 5.749 35.16 ;
     RECT  5.708 57.168 5.749 57.192 ;
     RECT  4.412 48.96 5.753 48.984 ;
     RECT  5.713 54.096 5.753 54.648 ;
     RECT  5.701 27.84 5.789 27.864 ;
     RECT  5.701 32.88 5.789 32.904 ;
     RECT  5.749 35.136 5.789 35.352 ;
     RECT  5.747 40.176 5.789 40.2 ;
     RECT  5.701 42.192 5.789 42.216 ;
     RECT  5.701 44.88 5.789 44.904 ;
     RECT  5.701 61.872 5.789 61.896 ;
     RECT  5.708 71.808 5.789 72.024 ;
     RECT  5.701 81.6 5.789 81.624 ;
     RECT  5.701 96.288 5.789 96.312 ;
     RECT  5.701 103.2 5.789 103.224 ;
     RECT  4.739 105.456 5.789 105.48 ;
     RECT  5.701 113.184 5.789 113.208 ;
     RECT  5.701 124.8 5.789 124.824 ;
     RECT  5.701 135.024 5.789 135.048 ;
     RECT  5.701 139.92 5.789 139.944 ;
     RECT  5.701 142.08 5.789 142.104 ;
     RECT  5.701 149.424 5.789 149.448 ;
     RECT  5.677 178.944 5.789 180.984 ;
     RECT  5.123 37.584 5.795 37.608 ;
     RECT  5.749 57.168 5.795 57.576 ;
     RECT  5.708 64.272 5.795 64.296 ;
     RECT  5.708 66.48 5.795 66.504 ;
     RECT  5.708 68.88 5.795 68.904 ;
     RECT  5.789 72 5.795 72.024 ;
     RECT  5.708 84.192 5.795 84.216 ;
     RECT  5.708 108.192 5.795 108.216 ;
     RECT  5.708 128.016 5.795 128.04 ;
     RECT  5.845 116.688 5.932 116.712 ;
     RECT  5.821 122.544 5.933 122.568 ;
     RECT  4.601 0.048 5.965 1.56 ;
     RECT  5.285 2.592 5.965 4.536 ;
     RECT  5.753 54.624 5.987 54.648 ;
     RECT  5.749 30.72 6.073 30.744 ;
     RECT  5.713 47.28 6.221 47.304 ;
     RECT  6.073 30.72 6.275 30.84 ;
     RECT  5.749 121.2 6.275 121.224 ;
     RECT  5.749 130.224 6.275 130.248 ;
     RECT  5.749 132.768 6.275 132.792 ;
     RECT  4.565 144.768 6.275 144.792 ;
     RECT  5.701 166.944 6.275 166.968 ;
     RECT  5.749 16.368 6.329 16.392 ;
     RECT  5.701 100.752 6.329 100.776 ;
     RECT  6.073 149.904 6.365 149.928 ;
     RECT  5.789 178.944 6.505 180.6 ;
     RECT  3.923 7.632 6.545 8.232 ;
     RECT  6.505 59.232 6.617 59.256 ;
     RECT  6.505 178.8 6.617 180.6 ;
     RECT  6.001 33.024 6.725 33.048 ;
     RECT  5.789 35.328 6.757 35.352 ;
     RECT  6.617 180 6.793 180.6 ;
     RECT  6.709 87.696 6.796 87.72 ;
     RECT  6.709 160.32 6.796 160.344 ;
     RECT  6.277 67.296 6.797 67.32 ;
     RECT  6.541 52.512 6.803 52.536 ;
     RECT  5.749 162.432 6.829 162.456 ;
     RECT  5.401 164.4 6.829 164.424 ;
     RECT  6.757 38.16 6.853 38.184 ;
     RECT  5.66 182.4 6.899 182.424 ;
     RECT  6.793 25.44 7.004 25.464 ;
     RECT  3.377 99.696 7.004 99.72 ;
     RECT  7.093 176.304 7.117 176.328 ;
     RECT  6.617 178.8 7.117 178.824 ;
     RECT  7.109 182.352 7.193 182.376 ;
     RECT  7.117 178.272 7.237 178.824 ;
     RECT  6.829 23.568 7.369 23.592 ;
     RECT  5.965 0.048 7.388 4.536 ;
     RECT  6.829 26.496 7.429 26.52 ;
     RECT  4.637 6.384 7.573 6.408 ;
     RECT  7.388 0.048 7.808 5.064 ;
     RECT  7.573 6.384 7.808 6.84 ;
     RECT  6.545 7.968 7.808 8.232 ;
     RECT  7.477 14.208 7.808 14.232 ;
     RECT  5.699 18.192 7.808 18.216 ;
     RECT  5.699 19.248 7.808 19.272 ;
     RECT  7.369 23.568 7.808 23.928 ;
     RECT  7.004 25.392 7.808 25.464 ;
     RECT  7.429 26.496 7.808 27 ;
     RECT  6.997 28.416 7.808 28.44 ;
     RECT  6.275 30.816 7.808 30.84 ;
     RECT  6.757 35.328 7.808 35.448 ;
     RECT  6.853 37.776 7.808 38.184 ;
     RECT  7.004 42.96 7.808 42.984 ;
     RECT  6.853 51.312 7.808 51.336 ;
     RECT  5.795 57.552 7.808 57.576 ;
     RECT  6.853 60.384 7.808 60.408 ;
     RECT  6.829 62.4 7.808 62.424 ;
     RECT  6.853 65.28 7.808 65.304 ;
     RECT  7.045 70.656 7.808 70.68 ;
     RECT  7.004 72.96 7.808 72.984 ;
     RECT  7.004 74.976 7.808 75 ;
     RECT  6.829 78.048 7.808 78.072 ;
     RECT  7.004 80.64 7.808 80.664 ;
     RECT  6.764 82.32 7.808 82.344 ;
     RECT  6.853 84.288 7.808 84.312 ;
     RECT  6.853 89.76 7.808 89.784 ;
     RECT  6.829 92.832 7.808 92.856 ;
     RECT  7.004 95.136 7.808 95.16 ;
     RECT  7.429 96.624 7.808 96.648 ;
     RECT  7.004 99.6 7.808 99.72 ;
     RECT  7.004 106.32 7.808 106.344 ;
     RECT  7.004 109.344 7.808 109.368 ;
     RECT  7.004 112.08 7.808 112.104 ;
     RECT  7.004 113.472 7.808 113.496 ;
     RECT  7.004 116.16 7.808 116.184 ;
     RECT  6.829 119.52 7.808 119.544 ;
     RECT  7.669 121.152 7.808 121.176 ;
     RECT  7.045 124.272 7.808 124.296 ;
     RECT  6.853 125.904 7.808 125.928 ;
     RECT  7.669 128.592 7.808 128.616 ;
     RECT  7.004 130.896 7.808 130.92 ;
     RECT  7.004 133.44 7.808 133.464 ;
     RECT  6.721 135.696 7.808 135.72 ;
     RECT  6.829 137.904 7.808 138.6 ;
     RECT  6.901 141.264 7.808 141.288 ;
     RECT  5.411 143.184 7.808 143.208 ;
     RECT  7.429 145.008 7.808 145.032 ;
     RECT  7.429 147.744 7.808 147.768 ;
     RECT  6.829 152.592 7.808 152.616 ;
     RECT  6.757 153.6 7.808 153.624 ;
     RECT  7.004 155.04 7.808 155.064 ;
     RECT  7.004 157.728 7.808 157.752 ;
     RECT  6.829 162.432 7.808 162.6 ;
     RECT  6.829 164.4 7.808 165.048 ;
     RECT  6.853 167.088 7.808 167.112 ;
     RECT  6.853 169.728 7.808 169.752 ;
     RECT  7.093 174.384 7.808 174.504 ;
     RECT  7.117 176.304 7.808 176.712 ;
     RECT  7.237 177.984 7.808 178.824 ;
     RECT  6.793 180 7.808 180.84 ;
     RECT  7.429 181.824 7.808 181.848 ;
     RECT  7.808 0.048 8.104 181.848 ;
     RECT  8.104 111.936 8.165 111.96 ;
     RECT  8.104 180 8.165 180.024 ;
     RECT  8.104 16.848 8.243 18.216 ;
     RECT  8.104 45.36 8.243 45.384 ;
     RECT  8.104 97.92 8.243 97.944 ;
     RECT  8.104 104.256 8.243 104.28 ;
     RECT  8.104 8.208 8.309 8.232 ;
     RECT  8.104 58.704 8.309 58.728 ;
     RECT  8.104 151.008 8.309 151.032 ;
     RECT  8.104 176.688 8.309 176.712 ;
     RECT  8.104 0.048 8.417 4.536 ;
     RECT  8.104 146.496 8.525 146.76 ;
     RECT  8.104 149.184 8.525 149.208 ;
     RECT  8.243 16.848 8.561 17.784 ;
     RECT  8.104 23.184 8.572 23.208 ;
     RECT  8.104 26.736 8.597 26.76 ;
     RECT  8.525 146.736 8.597 146.76 ;
     RECT  8.104 25.344 8.812 25.368 ;
     RECT  8.104 38.736 8.813 38.76 ;
     RECT  8.104 181.824 8.963 181.848 ;
     RECT  8.417 0.048 8.993 2.904 ;
     RECT  8.561 17.76 8.993 17.784 ;
     RECT  8.104 21.12 9.107 21.144 ;
     RECT  8.104 96.384 9.107 96.408 ;
     RECT  8.417 3.936 9.137 4.536 ;
     RECT  8.104 19.248 9.155 19.272 ;
     RECT  8.104 143.088 9.155 143.112 ;
     RECT  8.993 0.048 9.173 2.328 ;
     RECT  9.173 0.048 9.245 1.8 ;
     RECT  9.137 3.936 9.281 4.344 ;
     RECT  9.205 182.352 9.289 182.376 ;
     RECT  9.241 66.672 9.353 66.696 ;
     RECT  9.245 0.096 9.677 1.8 ;
     RECT  9.677 0.912 9.713 1.8 ;
     RECT  8.104 36.48 9.713 36.504 ;
     RECT  9.281 3.936 10.097 4.104 ;
     RECT  10.097 3.504 10.289 4.104 ;
     RECT  10.565 42.72 10.649 42.744 ;
     RECT  10.285 33.552 10.835 33.576 ;
     RECT  10.465 36.528 10.835 36.552 ;
     RECT  8.104 99.696 10.901 99.72 ;
     RECT  9.445 181.248 10.933 181.272 ;
     RECT  10.289 3.504 11.005 3.96 ;
     RECT  10.933 181.248 11.017 181.752 ;
     RECT  10.94 31.152 11.027 31.176 ;
     RECT  11.029 26.4 11.116 26.424 ;
     RECT  11.125 177.984 11.212 178.008 ;
     RECT  11.132 28.944 11.219 28.968 ;
     RECT  11.084 168.384 11.267 168.408 ;
     RECT  11.221 170.544 11.293 170.568 ;
     RECT  11.221 165.648 11.305 165.672 ;
     RECT  9.713 1.152 11.369 1.8 ;
     RECT  11.324 21.12 11.411 21.144 ;
     RECT  11.365 132.912 11.449 132.936 ;
     RECT  10.933 124.896 11.564 124.92 ;
     RECT  11.564 34.08 11.651 34.104 ;
     RECT  11.564 124.896 11.651 125.112 ;
     RECT  11.653 130.176 11.689 130.2 ;
     RECT  11.605 177.696 11.692 177.72 ;
     RECT  11.651 124.896 11.729 124.92 ;
     RECT  11.293 170.544 11.729 170.856 ;
     RECT  11.689 130.176 11.74 130.632 ;
     RECT  11.729 170.544 11.765 170.568 ;
     RECT  11.74 130.608 11.773 130.632 ;
     RECT  8.104 6.384 11.837 6.408 ;
     RECT  11.9 128.016 11.987 128.04 ;
     RECT  11.005 3.408 11.989 3.96 ;
     RECT  11.797 18.192 12.053 18.216 ;
     RECT  11.689 42.336 12.089 42.36 ;
     RECT  11.017 181.248 12.121 181.272 ;
     RECT  11.041 179.04 12.161 179.064 ;
     RECT  12.092 10.032 12.179 10.056 ;
     RECT  12.121 181.248 12.205 181.752 ;
     RECT  11.989 36.576 12.325 36.6 ;
     RECT  12.325 36.48 12.517 36.6 ;
     RECT  11.989 26.16 12.553 26.184 ;
     RECT  12.553 26.064 12.625 26.184 ;
     RECT  11.989 2.88 13.208 3.96 ;
     RECT  13.129 4.944 13.208 4.968 ;
     RECT  12.908 10.32 13.208 10.344 ;
     RECT  12.572 13.056 13.208 13.08 ;
     RECT  12.62 15.648 13.208 15.672 ;
     RECT  12.613 17.616 13.208 17.64 ;
     RECT  12.277 20.496 13.208 20.52 ;
     RECT  12.625 25.872 13.208 26.184 ;
     RECT  12.997 31.2 13.208 31.224 ;
     RECT  13.045 33.984 13.208 34.008 ;
     RECT  12.517 36.48 13.208 37.08 ;
     RECT  12.949 39.072 13.208 39.192 ;
     RECT  12.517 41.904 13.208 41.928 ;
     RECT  13.165 139.392 13.208 139.416 ;
     RECT  12.949 141.552 13.208 141.576 ;
     RECT  13.165 162.624 13.208 162.648 ;
     RECT  12.877 180.144 13.208 180.168 ;
     RECT  12.205 181.248 13.208 181.272 ;
     RECT  11.369 1.152 13.333 1.176 ;
     RECT  13.208 2.148 13.333 181.452 ;
     RECT  13.333 1.152 13.42 181.608 ;
     RECT  13.42 1.152 13.504 181.272 ;
     RECT  13.504 139.392 13.619 139.416 ;
     RECT  13.504 1.152 13.637 1.8 ;
     RECT  13.504 36.48 13.715 36.504 ;
     RECT  13.504 127.584 13.753 127.608 ;
     RECT  13.504 132.576 13.763 132.648 ;
     RECT  13.504 167.664 13.859 167.688 ;
     RECT  13.504 30.816 14.033 30.936 ;
     RECT  13.504 3.408 14.177 3.576 ;
     RECT  13.504 28.992 14.243 29.016 ;
     RECT  13.504 15.168 14.332 15.192 ;
     RECT  14.033 30.816 14.429 30.84 ;
     RECT  14.581 39.744 14.668 39.768 ;
     RECT  13.504 181.248 14.713 181.272 ;
     RECT  14.629 94.992 14.716 95.016 ;
     RECT  14.725 12.912 14.749 12.936 ;
     RECT  14.749 12.912 14.812 13.32 ;
     RECT  14.725 141.552 14.812 141.576 ;
     RECT  14.497 21.936 14.819 21.96 ;
     RECT  14.605 25.584 14.819 25.608 ;
     RECT  14.533 170.112 14.819 170.136 ;
     RECT  14.177 3.408 14.821 3.432 ;
     RECT  14.812 13.296 14.933 13.32 ;
     RECT  14.821 130.464 14.933 130.488 ;
     RECT  14.821 92.016 14.969 92.04 ;
     RECT  14.821 166.416 14.969 166.44 ;
     RECT  14.821 26.736 15.005 26.76 ;
     RECT  14.972 27.792 15.059 27.816 ;
     RECT  14.821 2.88 15.077 3.432 ;
     RECT  14.821 104.256 15.185 104.28 ;
     RECT  15.157 4.656 15.244 4.68 ;
     RECT  13.637 1.152 15.317 1.32 ;
     RECT  15.26 44.976 15.347 45 ;
     RECT  15.308 31.824 15.395 31.848 ;
     RECT  15.253 80.304 15.395 80.328 ;
     RECT  15.308 109.296 15.395 109.32 ;
     RECT  15.181 177.792 15.395 177.816 ;
     RECT  15.109 172.32 15.401 172.344 ;
     RECT  15.317 173.808 15.401 173.832 ;
     RECT  15.389 34.272 15.473 34.296 ;
     RECT  15.452 17.856 15.539 17.88 ;
     RECT  15.452 139.392 15.539 139.416 ;
     RECT  15.493 177.648 15.58 177.672 ;
     RECT  13.763 132.624 15.725 132.648 ;
     RECT  15.644 144.48 15.731 144.504 ;
     RECT  15.397 125.136 15.761 125.16 ;
     RECT  15.74 42.048 15.827 42.072 ;
     RECT  15.74 151.968 15.827 151.992 ;
     RECT  15.788 50.112 15.875 50.136 ;
     RECT  15.788 106.848 15.875 106.872 ;
     RECT  15.469 82.896 15.971 82.92 ;
     RECT  15.901 96.288 15.985 96.312 ;
     RECT  15.98 127.632 16.067 127.656 ;
     RECT  16.076 29.472 16.163 29.496 ;
     RECT  16.124 20.4 16.211 20.424 ;
     RECT  14.713 181.248 16.265 181.752 ;
     RECT  16.309 129.12 16.333 129.144 ;
     RECT  15.077 2.88 16.337 2.904 ;
     RECT  16.009 104.592 16.373 104.616 ;
     RECT  16.333 128.832 16.396 129.144 ;
     RECT  16.316 5.616 16.403 5.64 ;
     RECT  16.117 37.536 16.547 37.56 ;
     RECT  16.441 47.328 16.547 47.352 ;
     RECT  16.396 128.832 16.547 128.856 ;
     RECT  15.317 1.152 16.561 1.8 ;
     RECT  13.504 180.144 16.625 180.168 ;
     RECT  16.652 48.384 16.739 48.408 ;
     RECT  16.652 109.392 16.739 109.416 ;
     RECT  16.748 45.12 16.765 45.144 ;
     RECT  16.765 45.12 16.835 45.384 ;
     RECT  16.693 169.536 16.844 169.56 ;
     RECT  16.765 12.576 16.849 12.6 ;
     RECT  16.844 169.488 16.931 169.56 ;
     RECT  16.933 21.648 17.02 21.672 ;
     RECT  16.549 16.512 17.021 16.536 ;
     RECT  16.94 143.952 17.027 143.976 ;
     RECT  16.837 3.984 17.089 4.008 ;
     RECT  17.089 3.84 17.093 4.008 ;
     RECT  16.729 75.264 17.123 75.288 ;
     RECT  16.873 116.976 17.123 117 ;
     RECT  16.931 169.536 17.123 169.56 ;
     RECT  16.693 114.48 17.129 114.504 ;
     RECT  17.077 112.272 17.164 112.872 ;
     RECT  17.077 9.744 17.219 9.768 ;
     RECT  17.132 78.528 17.219 78.552 ;
     RECT  17.132 90.48 17.219 90.504 ;
     RECT  17.132 93.408 17.219 93.432 ;
     RECT  16.873 106.608 17.273 106.632 ;
     RECT  17.221 81.024 17.309 81.048 ;
     RECT  17.125 34.272 17.345 34.296 ;
     RECT  17.276 42.192 17.363 42.216 ;
     RECT  17.276 140.976 17.363 141 ;
     RECT  17.077 51.6 17.377 51.624 ;
     RECT  16.477 137.376 17.413 137.4 ;
     RECT  16.265 181.248 17.413 181.272 ;
     RECT  17.377 51.6 17.417 51.768 ;
     RECT  17.077 56.448 17.457 56.472 ;
     RECT  17.093 3.84 17.459 3.864 ;
     RECT  17.372 152.112 17.459 152.136 ;
     RECT  17.413 181.248 17.497 181.752 ;
     RECT  17.413 137.376 17.561 137.928 ;
     RECT  17.457 56.4 17.603 56.472 ;
     RECT  17.516 128.448 17.603 128.472 ;
     RECT  17.516 171.792 17.603 171.816 ;
     RECT  17.341 2.832 17.653 2.856 ;
     RECT  16.561 1.152 17.749 1.176 ;
     RECT  17.845 41.136 17.941 41.16 ;
     RECT  17.653 2.832 17.989 3.432 ;
     RECT  17.749 24.816 18.092 24.84 ;
     RECT  17.749 0.624 18.173 1.176 ;
     RECT  16.835 45.36 18.277 45.384 ;
     RECT  18.229 142.944 18.313 142.968 ;
     RECT  18.173 1.152 18.325 1.176 ;
     RECT  18.241 179.184 18.601 179.208 ;
     RECT  18.325 1.152 18.608 1.224 ;
     RECT  17.989 2.352 18.608 3.432 ;
     RECT  18.469 9.456 18.608 9.48 ;
     RECT  18.385 18.624 18.608 18.648 ;
     RECT  18.469 20.304 18.608 20.328 ;
     RECT  18.349 23.376 18.608 23.4 ;
     RECT  18.092 24.816 18.608 24.984 ;
     RECT  18.469 26.832 18.608 26.856 ;
     RECT  17.413 37.296 18.608 37.32 ;
     RECT  17.797 39.456 18.608 39.48 ;
     RECT  17.941 41.136 18.608 41.304 ;
     RECT  18.277 45.36 18.608 45.432 ;
     RECT  18.449 46.704 18.608 46.728 ;
     RECT  17.417 51.744 18.608 51.768 ;
     RECT  18.229 56.88 18.608 56.904 ;
     RECT  17.845 59.424 18.608 59.448 ;
     RECT  18.241 61.824 18.608 61.848 ;
     RECT  17.585 68.208 18.608 68.232 ;
     RECT  17.605 86.784 18.608 86.808 ;
     RECT  18.085 96.432 18.608 96.456 ;
     RECT  17.66 104.256 18.608 104.28 ;
     RECT  18.133 107.136 18.608 107.16 ;
     RECT  17.164 112.272 18.608 112.296 ;
     RECT  18.449 114.528 18.608 114.552 ;
     RECT  17.341 122.496 18.608 122.52 ;
     RECT  18.449 125.328 18.608 125.352 ;
     RECT  17.653 131.52 18.608 131.544 ;
     RECT  18.449 136.416 18.608 136.44 ;
     RECT  18.469 139.536 18.608 139.56 ;
     RECT  18.313 142.8 18.608 142.968 ;
     RECT  18.449 145.248 18.608 145.272 ;
     RECT  17.305 146.976 18.608 147 ;
     RECT  17.564 149.184 18.608 149.208 ;
     RECT  18.277 155.28 18.608 155.304 ;
     RECT  18.349 159.648 18.608 159.672 ;
     RECT  18.469 169.872 18.608 169.896 ;
     RECT  17.917 174.192 18.608 174.216 ;
     RECT  18.601 179.184 18.608 180.168 ;
     RECT  17.497 181.248 18.608 181.272 ;
     RECT  18.608 1.152 18.712 181.452 ;
     RECT  18.712 2.418 18.853 181.452 ;
     RECT  18.853 2.418 18.904 181.848 ;
     RECT  18.904 122.304 18.965 122.424 ;
     RECT  18.904 178.992 18.965 180.168 ;
     RECT  18.904 13.296 19.043 13.32 ;
     RECT  18.904 143.04 19.043 143.064 ;
     RECT  18.904 26.448 19.073 26.472 ;
     RECT  18.904 134.496 19.081 134.52 ;
     RECT  18.904 138.528 19.081 138.552 ;
     RECT  18.904 147.408 19.109 147.432 ;
     RECT  18.904 56.4 19.132 56.424 ;
     RECT  18.904 82.8 19.132 82.824 ;
     RECT  18.904 163.68 19.139 163.704 ;
     RECT  18.712 1.152 19.141 1.224 ;
     RECT  18.904 29.424 19.145 29.448 ;
     RECT  18.904 58.704 19.181 59.496 ;
     RECT  18.904 75.12 19.187 75.144 ;
     RECT  18.904 62.16 19.217 62.184 ;
     RECT  18.904 172.752 19.217 172.776 ;
     RECT  19.181 58.704 19.253 58.728 ;
     RECT  18.904 104.784 19.283 104.808 ;
     RECT  18.904 153.36 19.289 153.384 ;
     RECT  18.904 49.056 19.297 49.08 ;
     RECT  18.904 159.024 19.324 160.008 ;
     RECT  18.904 16.608 19.331 16.632 ;
     RECT  19.141 0.576 19.361 1.224 ;
     RECT  18.904 165.264 19.372 165.816 ;
     RECT  19.324 159.024 19.379 159.816 ;
     RECT  19.361 0.576 19.397 1.176 ;
     RECT  18.904 51.648 19.397 51.672 ;
     RECT  18.965 178.992 19.397 179.208 ;
     RECT  18.904 181.824 19.465 181.848 ;
     RECT  18.904 31.872 19.475 31.896 ;
     RECT  18.904 109.392 19.475 109.416 ;
     RECT  18.904 116.448 19.516 116.952 ;
     RECT  19.465 181.824 19.549 182.376 ;
     RECT  18.904 149.76 19.571 149.784 ;
     RECT  18.965 122.304 19.619 122.328 ;
     RECT  18.904 72.576 19.708 72.6 ;
     RECT  18.904 141.792 19.715 141.816 ;
     RECT  18.904 87.84 19.757 87.864 ;
     RECT  18.904 35.808 19.763 35.832 ;
     RECT  18.904 80.976 19.763 81.288 ;
     RECT  18.904 94.032 19.763 94.056 ;
     RECT  18.904 167.856 19.763 167.88 ;
     RECT  18.904 155.376 19.811 155.4 ;
     RECT  19.477 0.096 19.829 0.12 ;
     RECT  19.397 1.152 19.865 1.176 ;
     RECT  18.904 3.408 19.909 4.248 ;
     RECT  19.379 159.648 19.937 159.816 ;
     RECT  19.937 159.792 19.955 159.816 ;
     RECT  19.916 14.784 20.003 14.808 ;
     RECT  19.925 26.496 20.009 26.52 ;
     RECT  19.925 112.128 20.009 112.152 ;
     RECT  19.909 2.832 20.041 4.248 ;
     RECT  19.964 68.352 20.051 68.376 ;
     RECT  20.041 2.832 20.053 4.536 ;
     RECT  20.101 5.952 20.108 5.976 ;
     RECT  19.397 178.992 20.108 179.016 ;
     RECT  20.108 178.224 20.153 179.016 ;
     RECT  20.108 5.952 20.188 6.264 ;
     RECT  20.188 6.24 20.195 6.264 ;
     RECT  19.372 165.264 20.236 165.384 ;
     RECT  20.197 149.328 20.284 149.64 ;
     RECT  20.204 77.28 20.291 77.304 ;
     RECT  20.204 97.68 20.291 97.704 ;
     RECT  20.245 10.368 20.332 10.392 ;
     RECT  20.252 162.768 20.339 162.792 ;
     RECT  19.969 117.072 20.369 117.096 ;
     RECT  19.957 91.584 20.405 91.608 ;
     RECT  20.348 166.32 20.435 166.344 ;
     RECT  20.005 42.192 20.531 42.216 ;
     RECT  20.053 2.304 20.549 4.536 ;
     RECT  20.549 2.304 20.585 4.008 ;
     RECT  20.533 40.176 20.62 40.2 ;
     RECT  20.585 2.832 20.657 4.008 ;
     RECT  20.588 63.984 20.675 64.008 ;
     RECT  20.684 100.128 20.725 100.152 ;
     RECT  20.725 99.744 20.771 100.152 ;
     RECT  20.284 149.328 20.773 149.352 ;
     RECT  20.533 21.408 20.801 21.432 ;
     RECT  20.725 61.536 20.812 61.56 ;
     RECT  20.773 148.992 20.837 149.352 ;
     RECT  20.837 148.992 20.86 149.016 ;
     RECT  20.771 99.744 20.867 99.768 ;
     RECT  20.629 0.576 20.897 0.6 ;
     RECT  20.657 2.832 20.909 2.904 ;
     RECT  20.828 79.68 20.915 79.704 ;
     RECT  20.828 124.8 20.915 124.824 ;
     RECT  20.509 179.52 20.977 179.544 ;
     RECT  20.897 0.576 20.981 1.176 ;
     RECT  20.965 38.016 21.052 38.04 ;
     RECT  20.965 58.128 21.052 58.152 ;
     RECT  20.972 102.672 21.059 102.696 ;
     RECT  20.972 116.832 21.059 116.856 ;
     RECT  20.617 156.768 21.059 156.792 ;
     RECT  20.236 165.264 21.089 165.288 ;
     RECT  20.533 166.416 21.089 166.44 ;
     RECT  20.153 178.224 21.107 178.248 ;
     RECT  19.763 80.976 21.109 81 ;
     RECT  21.049 44.976 21.133 45 ;
     RECT  21.085 114.528 21.169 114.552 ;
     RECT  21.109 47.28 21.197 47.304 ;
     RECT  20.657 3.984 21.233 4.008 ;
     RECT  21.109 133.968 21.233 133.992 ;
     RECT  21.157 96.048 21.244 96.072 ;
     RECT  21.253 66.192 21.341 66.216 ;
     RECT  20.977 179.52 21.341 180.072 ;
     RECT  21.109 136.416 21.377 136.44 ;
     RECT  21.157 173.808 21.377 173.832 ;
     RECT  21.301 74.976 21.388 75 ;
     RECT  21.265 106.656 21.443 106.68 ;
     RECT  21.397 119.904 21.484 119.928 ;
     RECT  21.493 154.896 21.58 154.92 ;
     RECT  21.481 170.736 21.635 170.76 ;
     RECT  21.589 77.136 21.676 77.16 ;
     RECT  21.589 83.328 21.676 83.352 ;
     RECT  21.637 100.848 21.724 100.872 ;
     RECT  20.909 2.88 21.737 2.904 ;
     RECT  21.685 144.432 21.772 144.456 ;
     RECT  21.637 162.432 21.773 162.456 ;
     RECT  21.733 168.432 21.82 168.456 ;
     RECT  21.769 58.704 21.881 58.728 ;
     RECT  21.829 49.728 21.916 49.752 ;
     RECT  21.637 159.312 21.917 159.336 ;
     RECT  21.884 141.168 21.971 141.192 ;
     RECT  21.109 80.976 21.98 81.048 ;
     RECT  21.697 106.608 21.989 106.632 ;
     RECT  22.021 60.24 22.028 60.264 ;
     RECT  20.981 0.576 22.049 0.6 ;
     RECT  21.973 164.88 22.061 164.904 ;
     RECT  21.98 80.976 22.067 81.48 ;
     RECT  22.021 63.216 22.108 63.24 ;
     RECT  22.028 60 22.115 60.264 ;
     RECT  22.049 0.576 22.133 1.176 ;
     RECT  22.115 60.24 22.163 60.264 ;
     RECT  22.076 115.632 22.163 115.656 ;
     RECT  22.076 123.264 22.163 123.288 ;
     RECT  22.117 31.872 22.165 31.896 ;
     RECT  21.341 180.048 22.169 180.072 ;
     RECT  22.165 31.68 22.205 31.896 ;
     RECT  22.124 15.312 22.211 15.336 ;
     RECT  22.124 19.488 22.211 19.512 ;
     RECT  22.124 52.56 22.211 52.584 ;
     RECT  22.129 90.672 22.213 90.696 ;
     RECT  22.129 117.168 22.213 117.192 ;
     RECT  22.157 139.104 22.213 139.128 ;
     RECT  22.205 31.68 22.249 31.704 ;
     RECT  22.213 94.128 22.313 94.152 ;
     RECT  22.261 165.792 22.349 165.816 ;
     RECT  22.213 139.104 22.421 139.608 ;
     RECT  22.412 12.48 22.499 12.504 ;
     RECT  22.489 119.184 22.573 119.208 ;
     RECT  22.508 93.12 22.595 93.144 ;
     RECT  22.549 45.12 22.637 45.144 ;
     RECT  22.556 55.056 22.643 55.08 ;
     RECT  19.549 181.824 22.661 181.848 ;
     RECT  22.201 109.248 22.673 109.272 ;
     RECT  22.7 152.064 22.705 152.088 ;
     RECT  22.652 17.472 22.739 17.496 ;
     RECT  22.693 88.512 22.78 88.536 ;
     RECT  22.693 43.152 22.781 43.176 ;
     RECT  22.273 79.488 22.787 79.512 ;
     RECT  22.381 104.208 22.787 104.232 ;
     RECT  22.7 122.112 22.787 122.136 ;
     RECT  22.705 151.824 22.787 152.088 ;
     RECT  22.787 151.824 22.789 151.992 ;
     RECT  22.733 10.512 22.817 10.536 ;
     RECT  22.733 70.992 22.817 71.016 ;
     RECT  22.733 157.44 22.817 157.464 ;
     RECT  22.813 68.784 22.897 68.808 ;
     RECT  22.693 2.304 22.925 2.328 ;
     RECT  22.813 42.768 22.997 42.792 ;
     RECT  22.813 104.64 22.997 104.664 ;
     RECT  23.132 138.816 23.221 138.84 ;
     RECT  22.133 0.576 23.237 0.6 ;
     RECT  22.921 179.472 23.245 179.496 ;
     RECT  23.245 2.832 23.269 2.856 ;
     RECT  23.237 0.576 23.321 1.176 ;
     RECT  23.209 60.624 23.345 60.648 ;
     RECT  23.209 47.232 23.425 47.256 ;
     RECT  23.804 66.336 23.821 66.36 ;
     RECT  23.821 66.336 23.965 66.456 ;
     RECT  23.269 2.832 24.008 3.432 ;
     RECT  22.669 40.416 24.008 40.44 ;
     RECT  23.425 46.656 24.008 47.256 ;
     RECT  22.789 58.08 24.008 58.104 ;
     RECT  23.345 60.336 24.008 60.648 ;
     RECT  23.965 66.336 24.008 66.888 ;
     RECT  23.852 72.048 24.008 72.072 ;
     RECT  22.067 80.976 24.008 81 ;
     RECT  23.857 90.768 24.008 90.792 ;
     RECT  23.228 102.096 24.008 102.12 ;
     RECT  23.276 107.424 24.008 107.448 ;
     RECT  23.324 110.352 24.008 110.376 ;
     RECT  23.564 112.896 24.008 112.92 ;
     RECT  23.893 115.632 24.008 115.656 ;
     RECT  23.701 136.176 24.008 136.2 ;
     RECT  23.221 138.192 24.008 138.84 ;
     RECT  23.125 143.856 24.008 143.88 ;
     RECT  22.489 146.4 24.008 146.424 ;
     RECT  22.789 151.968 24.008 151.992 ;
     RECT  23.852 154.176 24.008 154.2 ;
     RECT  23.345 159.936 24.008 159.96 ;
     RECT  23.42 165.84 24.008 165.864 ;
     RECT  24.001 168 24.008 168.024 ;
     RECT  23.569 170.928 24.008 170.952 ;
     RECT  23.245 179.472 24.008 180.168 ;
     RECT  22.661 181.824 24.008 182.376 ;
     RECT  24.008 2.148 24.112 182.376 ;
     RECT  24.112 2.418 24.304 182.376 ;
     RECT  23.321 0.576 24.389 0.6 ;
     RECT  24.304 50.016 24.419 50.04 ;
     RECT  24.304 74.592 24.419 74.616 ;
     RECT  24.304 76.032 24.419 76.056 ;
     RECT  24.304 78.48 24.419 78.504 ;
     RECT  24.304 86.208 24.419 86.232 ;
     RECT  24.304 114.816 24.419 114.84 ;
     RECT  24.304 116.736 24.419 116.76 ;
     RECT  24.304 158.4 24.419 158.424 ;
     RECT  24.304 168 24.419 168.024 ;
     RECT  24.389 0.576 24.473 1.176 ;
     RECT  24.304 121.824 24.563 121.848 ;
     RECT  24.304 91.056 24.589 91.08 ;
     RECT  24.304 173.664 24.604 173.688 ;
     RECT  24.304 162.72 24.652 162.744 ;
     RECT  24.304 55.776 24.653 55.8 ;
     RECT  24.304 64.224 24.659 64.248 ;
     RECT  24.304 52.56 24.707 52.584 ;
     RECT  24.304 149.712 24.841 149.88 ;
     RECT  24.304 99.168 24.905 99.192 ;
     RECT  24.304 58.032 24.941 58.152 ;
     RECT  24.304 96.864 24.995 96.888 ;
     RECT  24.304 104.832 25.084 104.856 ;
     RECT  24.841 149.712 25.091 149.736 ;
     RECT  24.304 160.128 25.091 160.152 ;
     RECT  24.304 112.896 25.157 113.256 ;
     RECT  24.304 66.912 25.331 66.936 ;
     RECT  25.285 157.248 25.373 157.272 ;
     RECT  24.304 84.816 25.475 84.84 ;
     RECT  25.484 119.28 25.571 119.304 ;
     RECT  24.473 0.576 25.621 0.6 ;
     RECT  24.304 178.656 25.657 178.68 ;
     RECT  24.941 58.032 25.661 58.056 ;
     RECT  25.573 111.312 25.661 111.336 ;
     RECT  25.157 112.896 25.661 112.92 ;
     RECT  25.285 68.976 25.697 69.48 ;
     RECT  25.621 0.576 25.705 1.176 ;
     RECT  25.657 178.656 25.741 179.64 ;
     RECT  25.82 52.32 25.907 52.344 ;
     RECT  25.964 158.592 25.981 158.616 ;
     RECT  24.304 181.824 25.996 182.376 ;
     RECT  25.916 69.936 26.003 69.96 ;
     RECT  24.304 3.408 26.053 3.432 ;
     RECT  26.053 2.88 26.099 3.432 ;
     RECT  26.099 2.88 26.14 2.904 ;
     RECT  25.996 182.352 26.156 182.376 ;
     RECT  25.705 0.576 26.165 0.6 ;
     RECT  26.101 153.6 26.188 153.624 ;
     RECT  25.669 5.184 26.237 5.208 ;
     RECT  26.053 54.768 26.243 54.792 ;
     RECT  25.981 158.208 26.243 158.616 ;
     RECT  26.243 158.448 26.284 158.616 ;
     RECT  26.341 160.176 26.428 160.2 ;
     RECT  26.197 89.76 26.444 89.784 ;
     RECT  26.444 89.28 26.531 89.784 ;
     RECT  26.305 60.384 26.675 60.408 ;
     RECT  26.531 89.76 26.693 89.784 ;
     RECT  26.197 0.096 26.741 0.168 ;
     RECT  26.693 89.76 26.741 90.456 ;
     RECT  26.677 157.44 26.764 157.464 ;
     RECT  26.684 158.736 26.771 158.76 ;
     RECT  26.741 90.144 26.777 90.456 ;
     RECT  26.701 101.52 26.785 101.544 ;
     RECT  26.156 182.352 26.841 182.424 ;
     RECT  26.777 90.144 27.052 90.168 ;
     RECT  26.841 182.352 27.061 182.376 ;
     RECT  27.013 117.12 27.101 117.144 ;
     RECT  25.741 178.656 27.173 178.68 ;
     RECT  27.109 87.312 27.196 87.336 ;
     RECT  27.164 68.304 27.251 68.328 ;
     RECT  27.241 54.192 27.325 54.216 ;
     RECT  27.061 2.304 27.389 2.328 ;
     RECT  27.349 99.552 27.433 99.576 ;
     RECT  27.349 162 27.433 162.024 ;
     RECT  27.061 181.824 27.433 182.376 ;
     RECT  27.349 84.768 27.461 84.792 ;
     RECT  27.445 62.448 27.533 62.472 ;
     RECT  27.733 65.664 27.821 65.688 ;
     RECT  27.889 155.088 27.925 155.112 ;
     RECT  27.433 181.824 27.971 181.848 ;
     RECT  27.637 2.88 28.037 2.904 ;
     RECT  27.925 155.088 28.073 155.352 ;
     RECT  27.925 122.4 28.145 122.424 ;
     RECT  26.741 0.096 28.325 0.12 ;
     RECT  28.073 155.28 28.361 155.352 ;
     RECT  28.261 1.776 28.549 1.8 ;
     RECT  28.213 181.248 28.901 181.752 ;
     RECT  28.357 3.408 29.077 3.96 ;
     RECT  28.549 1.2 29.125 1.8 ;
     RECT  29.125 1.152 29.408 1.8 ;
     RECT  29.077 2.88 29.408 3.96 ;
     RECT  28.7 54.768 29.408 54.792 ;
     RECT  28.981 66.288 29.408 66.312 ;
     RECT  29.269 85.2 29.408 85.224 ;
     RECT  28.177 122.208 29.408 122.232 ;
     RECT  28.361 155.28 29.408 155.304 ;
     RECT  28.901 181.248 29.408 181.608 ;
     RECT  29.408 1.152 29.596 181.608 ;
     RECT  29.596 1.152 29.704 181.512 ;
     RECT  29.704 181.248 29.788 181.512 ;
     RECT  29.704 38.784 29.843 39 ;
     RECT  29.843 38.784 29.98 38.808 ;
     RECT  29.704 61.344 29.981 61.368 ;
     RECT  29.704 87.504 30.275 87.528 ;
     RECT  29.704 63.312 30.305 63.336 ;
     RECT  29.704 1.152 30.313 2.904 ;
     RECT  29.704 66.432 30.485 66.456 ;
     RECT  30.313 1.152 30.521 2.52 ;
     RECT  29.704 179.328 30.611 179.832 ;
     RECT  29.704 146.544 30.665 146.568 ;
     RECT  30.521 1.152 30.845 1.224 ;
     RECT  29.788 181.248 30.869 181.272 ;
     RECT  30.869 181.248 30.953 181.752 ;
     RECT  30.757 146.688 30.989 146.712 ;
     RECT  30.845 1.2 31.169 1.224 ;
     RECT  30.521 2.496 31.333 2.52 ;
     RECT  31.333 2.496 31.493 2.904 ;
     RECT  31.493 2.496 31.525 2.52 ;
     RECT  31.525 1.776 31.997 2.52 ;
     RECT  30.611 179.328 32.069 179.352 ;
     RECT  32.108 179.616 32.195 179.64 ;
     RECT  31.669 3.792 32.429 3.816 ;
     RECT  30.953 181.248 32.597 181.272 ;
     RECT  32.485 2.88 32.609 3 ;
     RECT  31.997 1.776 32.965 1.8 ;
     RECT  32.597 181.248 33.049 181.752 ;
     RECT  32.965 1.776 33.059 2.424 ;
     RECT  33.059 1.776 33.077 1.848 ;
     RECT  33.077 1.776 33.253 1.8 ;
     RECT  33.637 2.88 33.761 2.904 ;
     RECT  33.037 180.096 33.797 180.12 ;
     RECT  33.685 118.128 33.829 118.152 ;
     RECT  33.253 1.2 34.117 1.8 ;
     RECT  33.836 65.856 34.181 65.88 ;
     RECT  34.117 1.152 34.301 1.8 ;
     RECT  33.049 181.248 34.325 181.272 ;
     RECT  34.301 1.2 34.808 1.8 ;
     RECT  33.932 3.936 34.808 3.96 ;
     RECT  33.181 5.712 34.808 5.736 ;
     RECT  34.181 65.664 34.808 65.88 ;
     RECT  33.829 118.032 34.808 118.152 ;
     RECT  34.325 181.248 34.808 181.752 ;
     RECT  34.808 1.2 35.104 181.752 ;
     RECT  35.104 1.2 35.269 1.8 ;
     RECT  35.104 3.984 35.273 4.536 ;
     RECT  35.269 1.152 35.777 1.8 ;
     RECT  35.273 4.512 35.921 4.536 ;
     RECT  35.104 181.248 36.268 181.752 ;
     RECT  36.268 181.728 36.421 181.752 ;
     RECT  36.517 0.624 36.677 0.648 ;
     RECT  35.777 1.776 37.061 1.8 ;
     RECT  36.133 179.232 37.073 179.256 ;
     RECT  37.061 1.2 37.141 1.8 ;
     RECT  35.104 2.88 37.141 2.904 ;
     RECT  37.141 1.2 37.145 2.904 ;
     RECT  37.145 1.776 37.217 2.904 ;
     RECT  36.421 181.728 37.369 181.848 ;
     RECT  37.217 1.776 37.541 2.664 ;
     RECT  37.369 181.824 37.609 181.848 ;
     RECT  37.621 0.096 37.909 0.12 ;
     RECT  37.609 181.824 38.113 182.376 ;
     RECT  37.541 2.64 38.333 2.664 ;
     RECT  38.113 181.824 38.819 182.472 ;
     RECT  38.773 179.616 38.945 179.64 ;
     RECT  38.819 181.824 39.941 181.848 ;
     RECT  37.909 0.096 39.973 0.168 ;
     RECT  39.685 1.152 39.973 1.176 ;
     RECT  39.877 4.656 40.057 4.68 ;
     RECT  40.069 2.88 40.208 2.904 ;
     RECT  40.057 4.56 40.208 4.68 ;
     RECT  39.301 179.376 40.208 179.4 ;
     RECT  39.941 181.824 40.208 182.376 ;
     RECT  40.208 2.148 40.312 182.376 ;
     RECT  40.312 2.418 40.504 182.376 ;
     RECT  39.973 0.096 40.781 1.176 ;
     RECT  40.781 1.152 40.889 1.176 ;
     RECT  40.504 181.824 41.533 182.376 ;
     RECT  41.533 181.824 41.747 182.424 ;
     RECT  40.504 2.88 41.825 2.904 ;
     RECT  41.641 173.952 41.989 173.976 ;
     RECT  41.989 173.952 42.076 174.12 ;
     RECT  42.076 173.952 42.179 173.976 ;
     RECT  41.989 1.152 42.185 1.176 ;
     RECT  42.421 179.328 42.509 179.352 ;
     RECT  42.613 2.304 42.797 2.328 ;
     RECT  42.793 92.016 42.877 92.04 ;
     RECT  41.747 181.824 42.985 182.376 ;
     RECT  40.781 0.096 43.121 0.12 ;
     RECT  43.037 91.824 43.121 91.848 ;
     RECT  43.189 1.152 43.337 1.176 ;
     RECT  43.477 0.576 44.333 0.6 ;
     RECT  44.333 0.576 44.417 1.176 ;
     RECT  43.765 2.88 44.489 2.904 ;
     RECT  44.449 5.136 44.773 5.16 ;
     RECT  44.417 0.576 44.849 0.6 ;
     RECT  42.985 181.824 45.541 181.848 ;
     RECT  45.521 1.152 45.605 1.176 ;
     RECT  44.917 3.12 45.608 3.144 ;
     RECT  44.773 4.512 45.608 5.16 ;
     RECT  44.305 180.144 45.608 180.168 ;
     RECT  45.541 181.584 45.608 181.848 ;
     RECT  45.608 2.148 45.712 181.848 ;
     RECT  45.712 2.256 45.904 181.848 ;
     RECT  45.904 2.256 45.965 4.536 ;
     RECT  45.965 2.256 46.217 3.576 ;
     RECT  46.217 2.304 46.577 3.576 ;
     RECT  45.205 0.096 46.721 0.12 ;
     RECT  45.904 38.16 46.757 38.184 ;
     RECT  45.904 181.824 46.757 181.848 ;
     RECT  45.904 145.824 46.829 145.848 ;
     RECT  45.904 180 47.081 180.024 ;
     RECT  46.577 3.552 47.113 3.576 ;
     RECT  47.029 38.064 47.116 38.088 ;
     RECT  46.577 2.304 47.153 2.328 ;
     RECT  47.077 146.4 47.267 146.424 ;
     RECT  46.981 1.152 47.557 1.176 ;
     RECT  47.113 3.552 47.801 4.392 ;
     RECT  47.801 3.552 47.893 3.576 ;
     RECT  47.893 2.88 48.017 3.576 ;
     RECT  47.557 1.152 48.469 1.224 ;
     RECT  48.017 3.552 48.997 3.576 ;
     RECT  48.469 1.152 49.045 1.272 ;
     RECT  48.997 2.88 49.097 3.576 ;
     RECT  49.097 3.552 49.285 3.576 ;
     RECT  49.285 3.552 49.349 4.536 ;
     RECT  49.349 4.224 49.372 4.536 ;
     RECT  46.981 181.248 49.597 181.272 ;
     RECT  49.597 180.288 49.621 181.272 ;
     RECT  49.045 1.152 49.709 1.8 ;
     RECT  49.709 1.2 49.817 1.8 ;
     RECT  49.621 179.808 49.877 181.272 ;
     RECT  49.877 179.808 50.281 181.752 ;
     RECT  50.281 179.616 50.329 181.752 ;
     RECT  49.817 1.776 50.533 1.8 ;
     RECT  50.149 2.88 50.533 2.904 ;
     RECT  50.533 1.776 50.813 1.896 ;
     RECT  50.533 2.88 50.813 3.144 ;
     RECT  50.813 1.776 51.008 3.144 ;
     RECT  49.372 4.224 51.008 4.248 ;
     RECT  50.329 179.616 51.008 181.608 ;
     RECT  51.008 1.776 51.196 181.608 ;
     RECT  51.196 1.776 51.304 181.272 ;
     RECT  51.304 1.776 51.973 1.8 ;
     RECT  51.304 178.368 52.307 180.168 ;
     RECT  52.307 179.616 52.373 180.168 ;
     RECT  51.304 2.88 52.517 2.904 ;
     RECT  52.373 179.616 52.769 179.64 ;
     RECT  51.973 1.2 52.841 1.8 ;
     RECT  52.841 1.2 52.885 1.272 ;
     RECT  53.557 2.928 53.701 2.952 ;
     RECT  53.701 2.832 53.705 2.952 ;
     RECT  53.705 2.832 53.843 2.856 ;
     RECT  53.737 3.84 53.843 3.864 ;
     RECT  51.304 181.248 54.025 181.272 ;
     RECT  52.885 1.152 54.037 1.272 ;
     RECT  54.025 181.248 54.109 181.752 ;
     RECT  54.709 2.88 54.821 2.904 ;
     RECT  54.385 4.272 54.853 4.296 ;
     RECT  54.853 3.936 54.94 4.296 ;
     RECT  54.037 1.152 55.253 1.8 ;
     RECT  54.565 179.712 55.253 179.736 ;
     RECT  54.94 4.272 55.325 4.296 ;
     RECT  55.861 2.88 56.005 2.904 ;
     RECT  56.005 2.88 56.041 2.952 ;
     RECT  56.041 2.784 56.245 2.952 ;
     RECT  54.109 181.248 56.341 181.272 ;
     RECT  55.964 4.944 56.401 4.968 ;
     RECT  56.245 2.304 56.408 2.952 ;
     RECT  56.401 4.128 56.408 4.968 ;
     RECT  56.341 181.248 56.408 181.848 ;
     RECT  56.408 2.148 56.512 181.848 ;
     RECT  56.512 2.304 56.549 181.848 ;
     RECT  56.549 2.418 56.704 181.848 ;
     RECT  56.245 0.096 56.837 0.12 ;
     RECT  56.704 180.912 56.908 181.848 ;
     RECT  56.908 181.248 57.221 181.848 ;
     RECT  56.704 4.128 57.305 4.152 ;
     RECT  57.221 181.248 57.305 182.376 ;
     RECT  56.704 2.418 57.541 3.144 ;
     RECT  57.305 181.248 57.629 181.848 ;
     RECT  57.541 2.304 57.665 3.144 ;
     RECT  57.665 2.304 57.737 2.328 ;
     RECT  58.021 179.52 58.669 179.544 ;
     RECT  58.669 179.52 58.925 180.168 ;
     RECT  58.453 3.552 58.981 3.576 ;
     RECT  57.829 0.096 59.465 0.12 ;
     RECT  58.925 180.144 59.573 180.168 ;
     RECT  58.981 2.88 59.785 3.576 ;
     RECT  59.785 2.4 59.869 3.576 ;
     RECT  55.253 1.152 59.893 1.176 ;
     RECT  59.869 2.88 59.952 3.576 ;
     RECT  59.893 0.576 60.113 1.176 ;
     RECT  57.629 181.824 60.181 181.848 ;
     RECT  60.181 181.824 60.265 182.376 ;
     RECT  59.952 2.88 61.808 2.904 ;
     RECT  60.721 180.096 61.808 180.12 ;
     RECT  60.265 181.824 61.808 181.848 ;
     RECT  61.808 2.148 61.912 181.848 ;
     RECT  61.912 2.304 62.104 181.848 ;
     RECT  62.104 2.304 62.531 3.24 ;
     RECT  62.104 179.856 63.068 179.88 ;
     RECT  62.531 2.304 63.137 2.328 ;
     RECT  63.068 179.856 63.155 180.648 ;
     RECT  60.113 1.152 63.245 1.176 ;
     RECT  63.155 179.856 63.245 179.88 ;
     RECT  60.469 0.096 63.641 0.12 ;
     RECT  62.104 4.512 63.677 4.536 ;
     RECT  63.685 2.88 64.073 2.952 ;
     RECT  64.261 1.152 64.397 1.176 ;
     RECT  64.073 2.88 64.505 2.904 ;
     RECT  64.549 0.576 64.865 0.6 ;
     RECT  64.933 3.936 65.081 3.96 ;
     RECT  64.837 2.304 65.189 2.328 ;
     RECT  64.717 179.856 65.297 179.88 ;
     RECT  65.125 0.096 65.369 0.12 ;
     RECT  62.104 181.824 65.513 181.848 ;
     RECT  66.085 3.504 66.169 3.528 ;
     RECT  65.413 1.152 66.269 1.176 ;
     RECT  66.325 1.2 66.449 1.224 ;
     RECT  66.62 1.776 67.025 1.8 ;
     RECT  66.301 3.696 67.093 3.72 ;
     RECT  67.093 3.696 67.208 4.584 ;
     RECT  65.701 181.248 67.208 181.272 ;
     RECT  67.208 2.148 67.312 181.452 ;
     RECT  67.312 2.418 67.504 181.452 ;
     RECT  67.504 181.248 67.525 181.452 ;
     RECT  67.525 181.248 67.609 181.752 ;
     RECT  67.504 2.88 67.997 2.904 ;
     RECT  67.504 179.472 67.997 180.168 ;
     RECT  67.765 1.152 68.101 1.176 ;
     RECT  68.101 0.624 68.321 1.176 ;
     RECT  67.504 4.56 68.387 4.584 ;
     RECT  67.609 181.248 68.428 181.416 ;
     RECT  68.321 1.152 68.677 1.176 ;
     RECT  67.997 180.144 68.897 180.168 ;
     RECT  69.109 5.184 69.196 5.208 ;
     RECT  68.677 1.152 69.253 1.224 ;
     RECT  69.253 1.152 69.509 1.8 ;
     RECT  68.428 181.248 69.577 181.272 ;
     RECT  69.577 181.248 69.661 181.752 ;
     RECT  69.509 1.152 69.689 1.224 ;
     RECT  69.325 180.096 69.932 180.12 ;
     RECT  69.932 179.616 70.019 180.12 ;
     RECT  70.117 2.88 70.229 2.904 ;
     RECT  69.689 1.152 70.405 1.176 ;
     RECT  70.405 0.624 70.589 1.176 ;
     RECT  70.589 1.152 70.732 1.176 ;
     RECT  70.732 1.152 70.733 1.224 ;
     RECT  69.577 4.512 71.021 4.536 ;
     RECT  70.733 1.2 71.317 1.224 ;
     RECT  71.317 1.2 71.653 1.8 ;
     RECT  71.653 1.2 72.101 1.848 ;
     RECT  69.661 181.248 72.169 181.272 ;
     RECT  72.169 181.248 72.253 181.752 ;
     RECT  72.085 134.448 72.373 134.472 ;
     RECT  72.373 133.968 72.449 134.472 ;
     RECT  72.085 3.888 72.469 3.912 ;
     RECT  72.101 1.776 72.608 1.848 ;
     RECT  71.269 2.88 72.608 2.904 ;
     RECT  72.469 3.888 72.608 3.96 ;
     RECT  72.449 133.968 72.608 134.52 ;
     RECT  72.341 150 72.608 150.024 ;
     RECT  72.469 152.352 72.608 152.376 ;
     RECT  70.019 180.096 72.608 180.12 ;
     RECT  72.253 181.248 72.608 181.56 ;
     RECT  72.608 1.776 72.803 181.56 ;
     RECT  72.803 1.776 72.904 181.272 ;
     RECT  72.805 0.624 72.965 0.648 ;
     RECT  72.904 134.112 73.324 134.472 ;
     RECT  72.904 3.84 73.397 4.584 ;
     RECT  73.324 134.112 73.577 134.136 ;
     RECT  72.904 153.888 73.829 153.912 ;
     RECT  72.904 1.776 73.957 1.8 ;
     RECT  74.069 133.968 74.153 133.992 ;
     RECT  72.904 181.248 74.221 181.272 ;
     RECT  73.957 1.152 74.333 1.8 ;
     RECT  73.397 3.84 74.501 4.104 ;
     RECT  74.501 3.84 74.621 4.584 ;
     RECT  74.221 181.248 74.867 181.752 ;
     RECT  74.917 134.448 75.004 134.472 ;
     RECT  74.333 1.776 75.017 1.8 ;
     RECT  74.621 3.936 75.017 4.584 ;
     RECT  74.917 156.768 75.017 156.792 ;
     RECT  75.109 2.304 75.193 2.328 ;
     RECT  75.596 6.24 75.683 6.264 ;
     RECT  75.017 4.56 75.685 4.584 ;
     RECT  75.797 133.968 75.881 133.992 ;
     RECT  75.397 0.576 75.973 0.6 ;
     RECT  75.193 2.304 76.021 2.424 ;
     RECT  75.685 4.56 76.021 5.16 ;
     RECT  75.109 181.824 76.229 181.848 ;
     RECT  76.229 181.824 76.313 182.376 ;
     RECT  74.005 180.144 76.385 180.168 ;
     RECT  76.021 4.224 76.457 5.16 ;
     RECT  76.021 2.304 76.493 2.808 ;
     RECT  75.973 0.096 76.637 0.6 ;
     RECT  76.313 181.824 77.461 181.848 ;
     RECT  77.42 1.68 77.507 1.704 ;
     RECT  76.637 0.096 77.749 0.12 ;
     RECT  76.837 6.768 77.885 6.792 ;
     RECT  76.457 4.224 77.893 4.248 ;
     RECT  76.493 2.784 78.008 2.808 ;
     RECT  77.893 3.936 78.008 4.248 ;
     RECT  77.885 6.288 78.008 6.792 ;
     RECT  77.125 178.224 78.008 178.248 ;
     RECT  76.669 179.52 78.008 179.544 ;
     RECT  77.461 181.824 78.008 182.376 ;
     RECT  77.749 0.096 78.083 0.6 ;
     RECT  78.008 2.148 78.112 182.376 ;
     RECT  78.112 2.304 78.304 182.376 ;
     RECT  78.304 3.936 78.401 3.96 ;
     RECT  78.304 6.768 78.659 6.84 ;
     RECT  78.304 2.304 78.689 2.328 ;
     RECT  78.083 0.576 79.085 0.6 ;
     RECT  78.304 180.432 79.337 180.552 ;
     RECT  79.477 1.728 79.733 2.232 ;
     RECT  78.659 6.816 79.811 6.84 ;
     RECT  79.337 180.528 80.129 180.552 ;
     RECT  80.06 135.024 80.147 135.048 ;
     RECT  80.117 164.736 80.201 164.76 ;
     RECT  80.101 4.56 80.269 4.584 ;
     RECT  80.233 164.208 80.317 164.232 ;
     RECT  78.304 179.184 80.345 179.208 ;
     RECT  79.733 2.208 80.389 2.232 ;
     RECT  80.125 3.408 80.389 3.432 ;
     RECT  80.389 2.208 80.396 3.432 ;
     RECT  80.269 4.512 80.396 4.584 ;
     RECT  80.396 2.208 80.525 4.584 ;
     RECT  80.525 2.208 80.569 4.488 ;
     RECT  80.369 134.544 80.636 135 ;
     RECT  80.636 134.448 80.716 135 ;
     RECT  80.557 163.632 80.723 163.656 ;
     RECT  80.569 2.208 80.957 3.912 ;
     RECT  80.677 6.384 80.957 6.408 ;
     RECT  80.957 2.304 81.173 3.912 ;
     RECT  81.109 178.176 81.196 178.2 ;
     RECT  81.164 133.056 81.212 133.08 ;
     RECT  80.716 134.448 81.212 134.664 ;
     RECT  80.953 163.056 81.251 163.08 ;
     RECT  78.304 181.824 81.325 182.376 ;
     RECT  81.173 2.784 81.389 3.912 ;
     RECT  81.313 90.576 81.425 90.6 ;
     RECT  81.301 165.36 81.461 165.384 ;
     RECT  81.389 3.888 81.539 3.912 ;
     RECT  81.253 5.712 81.569 5.736 ;
     RECT  81.212 133.056 81.577 134.664 ;
     RECT  81.577 134.448 81.781 134.664 ;
     RECT  81.541 0.096 81.785 0.12 ;
     RECT  81.781 134.448 81.868 135 ;
     RECT  81.788 4.272 81.875 4.296 ;
     RECT  81.809 164.16 81.893 164.184 ;
     RECT  81.829 0.144 81.971 0.168 ;
     RECT  81.577 133.056 82.069 133.416 ;
     RECT  82.069 90.768 82.153 90.792 ;
     RECT  82.069 132.912 82.153 133.416 ;
     RECT  81.868 134.448 82.181 134.568 ;
     RECT  81.925 7.296 82.253 7.32 ;
     RECT  82.181 134.448 82.403 134.472 ;
     RECT  81.389 2.784 82.405 2.808 ;
     RECT  82.357 167.664 82.441 167.688 ;
     RECT  80.413 180.48 82.609 180.504 ;
     RECT  82.537 182.928 82.739 182.952 ;
     RECT  82.609 180.144 83.084 180.504 ;
     RECT  83.084 179.232 83.113 180.504 ;
     RECT  82.117 0.576 83.117 0.6 ;
     RECT  83.029 183.456 83.171 183.48 ;
     RECT  83.113 179.232 83.185 180.648 ;
     RECT  81.325 181.824 83.185 181.848 ;
     RECT  82.405 2.784 83.221 2.904 ;
     RECT  82.556 3.888 83.221 3.912 ;
     RECT  83.185 179.232 83.221 180.744 ;
     RECT  83.185 181.824 83.221 182.424 ;
     RECT  83.221 5.184 83.269 5.208 ;
     RECT  83.221 179.232 83.269 182.424 ;
     RECT  83.221 2.784 83.408 3.912 ;
     RECT  83.269 5.088 83.408 5.208 ;
     RECT  82.693 8.544 83.408 8.568 ;
     RECT  82.321 128.352 83.408 128.376 ;
     RECT  82.645 133.968 83.408 133.992 ;
     RECT  83.221 152.208 83.408 152.232 ;
     RECT  83.257 162.48 83.408 162.504 ;
     RECT  82.645 165.12 83.408 165.144 ;
     RECT  83.269 178.608 83.408 182.424 ;
     RECT  83.408 2.148 83.512 182.424 ;
     RECT  83.512 2.418 83.704 182.424 ;
     RECT  83.704 180.72 83.725 182.424 ;
     RECT  83.704 2.88 83.801 2.952 ;
     RECT  83.704 5.76 83.837 5.784 ;
     RECT  83.725 180.72 83.939 183 ;
     RECT  83.939 181.728 84.227 183 ;
     RECT  83.317 0.096 84.233 0.12 ;
     RECT  84.284 1.104 84.371 1.128 ;
     RECT  83.801 2.928 84.529 2.952 ;
     RECT  84.227 181.728 84.529 181.896 ;
     RECT  84.529 181.872 84.563 181.896 ;
     RECT  83.939 180.72 84.995 180.744 ;
     RECT  84.877 1.728 85.379 1.752 ;
     RECT  84.227 182.976 85.453 183 ;
     RECT  85.453 182.352 85.537 183 ;
     RECT  85.537 182.976 85.571 183 ;
     RECT  84.733 0.576 85.955 0.696 ;
     RECT  86.197 18.24 86.209 18.264 ;
     RECT  85.955 0.576 86.257 0.6 ;
     RECT  83.704 128.352 86.281 128.376 ;
     RECT  86.209 18.24 86.284 18.36 ;
     RECT  86.281 128.352 86.321 128.52 ;
     RECT  86.284 18.336 86.364 18.36 ;
     RECT  84.877 55.056 86.364 55.08 ;
     RECT  86.281 91.776 86.364 91.8 ;
     RECT  86.321 128.496 86.364 128.52 ;
     RECT  83.704 165.216 86.364 165.24 ;
    LAYER M5 ;
     RECT  37.632 0.016 46.728 0.053 ;
     RECT  56.352 0.016 65.448 0.053 ;
     RECT  0.144 0.016 9.24 0.131 ;
     RECT  18.864 0.016 27.96 0.131 ;
     RECT  75.12 0.016 84.216 0.131 ;
     RECT  0.144 0.131 8.952 0.179 ;
     RECT  18.864 0.131 27.672 0.179 ;
     RECT  37.056 0.053 46.728 0.179 ;
     RECT  32.496 0.053 32.52 0.181 ;
     RECT  35.904 0.053 35.928 0.501 ;
     RECT  12 0.053 13.128 0.565 ;
     RECT  14.832 0.053 14.856 0.565 ;
     RECT  15.984 0.053 16.008 0.565 ;
     RECT  17.664 0.053 17.688 0.565 ;
     RECT  18.864 0.179 25.944 0.565 ;
     RECT  29.088 0.053 29.112 0.565 ;
     RECT  30.24 0.053 30.264 0.565 ;
     RECT  31.344 0.053 31.368 0.565 ;
     RECT  33.648 0.053 33.672 0.565 ;
     RECT  35.184 0.501 35.928 0.565 ;
     RECT  37.056 0.179 37.08 0.565 ;
     RECT  39.696 0.179 46.728 0.565 ;
     RECT  47.904 0.053 47.928 0.565 ;
     RECT  49.008 0.053 49.032 0.565 ;
     RECT  50.16 0.053 50.184 0.565 ;
     RECT  52.464 0.053 52.488 0.565 ;
     RECT  53.568 0.053 53.592 0.565 ;
     RECT  54.72 0.053 54.744 0.565 ;
     RECT  55.872 0.053 65.448 0.565 ;
     RECT  67.824 0.053 67.848 0.565 ;
     RECT  70.128 0.053 70.152 0.565 ;
     RECT  71.28 0.053 71.304 0.565 ;
     RECT  72.384 0.053 72.408 0.565 ;
     RECT  85.344 0.053 86.232 0.565 ;
     RECT  17.424 0.565 25.944 0.611 ;
     RECT  75.12 0.131 83.064 0.611 ;
     RECT  84.336 0.565 86.232 0.611 ;
     RECT  35.184 0.565 37.08 0.659 ;
     RECT  72.384 0.565 72.84 0.659 ;
     RECT  84.336 0.611 85.944 0.659 ;
     RECT  85.344 0.659 85.944 0.707 ;
     RECT  84.336 0.659 84.36 1.139 ;
     RECT  27.072 0.179 27.672 1.141 ;
     RECT  29.088 0.565 31.368 1.141 ;
     RECT  32.496 0.181 32.568 1.141 ;
     RECT  33.648 0.565 34.152 1.141 ;
     RECT  35.184 0.659 35.928 1.141 ;
     RECT  37.056 0.659 37.08 1.141 ;
     RECT  51.408 0.053 51.432 1.141 ;
     RECT  52.464 0.565 65.784 1.141 ;
     RECT  67.776 0.565 68.952 1.141 ;
     RECT  70.128 0.565 71.304 1.141 ;
     RECT  72.384 0.659 72.408 1.141 ;
     RECT  11.616 0.565 16.296 1.187 ;
     RECT  17.424 0.611 25.656 1.187 ;
     RECT  39.696 0.565 50.184 1.187 ;
     RECT  51.408 1.141 66.36 1.187 ;
     RECT  73.968 0.565 73.992 1.187 ;
     RECT  12 1.187 16.296 1.235 ;
     RECT  17.664 1.187 18.888 1.235 ;
     RECT  27.072 1.141 31.368 1.235 ;
     RECT  43.776 1.187 50.184 1.235 ;
     RECT  66.336 1.187 66.36 1.235 ;
     RECT  67.776 1.141 72.408 1.235 ;
     RECT  47.904 1.235 49.08 1.283 ;
     RECT  51.408 1.187 57.576 1.283 ;
     RECT  14.496 1.235 16.296 1.331 ;
     RECT  75.12 0.611 82.728 1.715 ;
     RECT  0.432 0.179 8.952 1.717 ;
     RECT  10.416 0.565 10.44 1.717 ;
     RECT  14.832 1.331 16.296 1.717 ;
     RECT  31.344 1.235 31.368 1.717 ;
     RECT  32.496 1.141 35.928 1.717 ;
     RECT  37.056 1.141 37.128 1.717 ;
     RECT  50.16 1.235 50.184 1.717 ;
     RECT  51.408 1.283 52.584 1.717 ;
     RECT  67.776 1.235 67.848 1.717 ;
     RECT  71.28 1.235 72.408 1.717 ;
     RECT  75.12 1.715 76.872 1.717 ;
     RECT  85.344 0.707 85.368 1.763 ;
     RECT  0.432 1.717 11.016 1.811 ;
     RECT  14.832 1.717 16.536 1.811 ;
     RECT  27.072 1.235 30.312 1.811 ;
     RECT  31.344 1.717 37.368 1.811 ;
     RECT  49.008 1.283 49.08 1.811 ;
     RECT  50.16 1.717 52.584 1.811 ;
     RECT  53.568 1.283 57.576 1.811 ;
     RECT  66.672 1.717 67.848 1.811 ;
     RECT  69.264 1.235 70.152 1.811 ;
     RECT  73.68 1.717 73.704 1.811 ;
     RECT  74.832 1.717 76.872 1.811 ;
     RECT  71.28 1.717 72.504 1.859 ;
     RECT  72.384 1.859 72.504 2.137 ;
     RECT  77.904 1.715 82.728 2.137 ;
     RECT  0.432 1.811 8.952 2.339 ;
     RECT  22.704 1.187 22.728 2.339 ;
     RECT  27.072 1.811 27.672 2.339 ;
     RECT  42.624 1.187 42.648 2.339 ;
     RECT  43.776 1.235 46.728 2.339 ;
     RECT  55.872 1.811 57.576 2.339 ;
     RECT  63.696 1.187 64.872 2.339 ;
     RECT  75.12 1.811 76.872 2.339 ;
     RECT  58.992 1.187 59.016 2.351 ;
     RECT  60.192 1.187 60.216 2.351 ;
     RECT  12 1.235 13.368 2.407 ;
     RECT  17.664 1.235 18.72 2.407 ;
     RECT  40.08 1.187 40.32 2.407 ;
     RECT  41.424 1.187 41.448 2.407 ;
     RECT  77.904 2.137 83.52 2.407 ;
     RECT  31.344 1.811 33.672 2.435 ;
     RECT  58.992 2.351 60.216 2.435 ;
     RECT  75.216 2.339 75.72 2.435 ;
     RECT  2.208 2.339 8.952 2.579 ;
     RECT  17.664 2.407 18.912 2.821 ;
     RECT  20.064 1.187 20.376 2.821 ;
     RECT  23.856 1.187 25.032 2.821 ;
     RECT  53.568 1.811 53.592 2.821 ;
     RECT  54.72 1.811 54.744 2.821 ;
     RECT  77.904 2.407 83.712 2.869 ;
     RECT  2.208 2.579 6.6 2.915 ;
     RECT  7.632 2.579 8.952 2.915 ;
     RECT  12 2.407 13.512 2.915 ;
     RECT  14.832 1.811 14.856 2.915 ;
     RECT  15.984 1.811 16.008 2.915 ;
     RECT  17.424 2.821 18.912 2.915 ;
     RECT  21.504 1.187 21.528 2.915 ;
     RECT  27.648 2.339 27.672 2.915 ;
     RECT  29.088 1.811 30.264 2.915 ;
     RECT  31.344 2.435 32.568 2.915 ;
     RECT  33.648 2.435 33.672 2.915 ;
     RECT  34.8 1.811 35.928 2.915 ;
     RECT  37.056 1.811 37.08 2.915 ;
     RECT  40.08 2.407 41.448 2.915 ;
     RECT  43.776 2.339 46.152 2.915 ;
     RECT  47.904 1.283 47.928 2.915 ;
     RECT  49.008 1.811 49.032 2.915 ;
     RECT  50.16 1.811 51.432 2.915 ;
     RECT  52.464 1.811 52.488 2.915 ;
     RECT  53.568 2.821 54.744 2.915 ;
     RECT  55.872 2.339 57.288 2.915 ;
     RECT  58.992 2.435 59.016 2.915 ;
     RECT  60.192 2.435 60.216 2.915 ;
     RECT  61.344 1.187 62.52 2.915 ;
     RECT  63.696 2.339 64.008 2.915 ;
     RECT  67.2 1.811 67.848 2.915 ;
     RECT  70.128 1.811 70.152 2.915 ;
     RECT  71.28 1.859 71.304 2.915 ;
     RECT  2.208 2.915 4.248 2.963 ;
     RECT  53.568 2.915 53.832 2.963 ;
     RECT  56.016 2.915 57.288 2.963 ;
     RECT  63.696 2.915 63.72 2.963 ;
     RECT  77.904 2.869 84.504 2.963 ;
     RECT  31.92 2.915 32.568 3.011 ;
     RECT  44.928 2.915 45.912 3.155 ;
     RECT  56.4 2.963 57.288 3.155 ;
     RECT  61.8 2.915 62.52 3.371 ;
     RECT  5.424 2.915 6.6 3.443 ;
     RECT  19.92 2.821 20.376 3.443 ;
     RECT  23.28 2.821 25.032 3.443 ;
     RECT  26.064 2.869 26.088 3.443 ;
     RECT  12.432 2.915 13.512 3.445 ;
     RECT  17.424 2.915 17.448 3.445 ;
     RECT  6 3.443 6.6 3.491 ;
     RECT  10.128 3.445 10.152 3.539 ;
     RECT  12.432 3.445 13.656 3.539 ;
     RECT  66.096 3.445 66.12 3.539 ;
     RECT  11.28 3.445 11.304 3.587 ;
     RECT  12.528 3.539 13.656 3.587 ;
     RECT  59.856 3.509 59.88 3.597 ;
     RECT  31.92 3.011 31.944 3.827 ;
     RECT  72.384 2.137 72.912 3.859 ;
     RECT  16.848 3.445 17.448 3.875 ;
     RECT  53.808 2.963 53.832 3.875 ;
     RECT  34.8 2.915 35.112 3.925 ;
     RECT  75.696 2.435 75.72 3.925 ;
     RECT  33.984 3.925 35.112 3.935 ;
     RECT  72.096 3.859 73.416 3.947 ;
     RECT  12.528 3.587 13.512 4.011 ;
     RECT  33.984 3.935 35.208 4.011 ;
     RECT  72.48 3.947 73.416 4.011 ;
     RECT  4.224 2.963 4.248 4.019 ;
     RECT  6.576 3.491 6.6 4.019 ;
     RECT  16.848 3.875 16.872 4.019 ;
     RECT  34.8 4.011 35.208 4.019 ;
     RECT  72.6 4.011 73.416 4.021 ;
     RECT  74.976 3.925 75.72 4.021 ;
     RECT  72.6 4.021 75.72 4.115 ;
     RECT  54.864 3.925 54.888 4.307 ;
     RECT  7.8 2.915 8.952 4.355 ;
     RECT  67.2 2.915 67.512 4.511 ;
     RECT  67.104 4.511 68.376 4.595 ;
     RECT  72.6 4.115 73.368 4.595 ;
     RECT  74.544 4.115 75.72 4.595 ;
     RECT  40.2 2.915 40.512 4.645 ;
     RECT  15.168 4.627 15.192 4.715 ;
     RECT  39.888 4.645 40.512 4.729 ;
     RECT  7.8 4.355 8.232 4.917 ;
     RECT  56.4 3.155 56.712 4.917 ;
     RECT  49.296 4.501 49.32 4.971 ;
     RECT  56.016 4.917 56.712 5.005 ;
     RECT  45.6 3.155 45.912 5.087 ;
     RECT  7.44 4.917 8.232 5.099 ;
     RECT  4.512 5.045 4.536 5.171 ;
     RECT  44.976 5.087 45.912 5.171 ;
     RECT  75.696 4.595 75.72 5.171 ;
     RECT  69.12 5.139 69.144 5.227 ;
     RECT  25.68 5.173 25.704 5.257 ;
     RECT  4.56 5.587 4.584 5.675 ;
     RECT  16.368 5.587 16.392 5.675 ;
     RECT  77.904 2.963 83.712 5.747 ;
     RECT  20.112 5.877 20.136 5.987 ;
     RECT  20.16 6.197 20.184 6.285 ;
     RECT  75.648 6.197 75.672 6.285 ;
     RECT  2.208 2.963 2.712 6.323 ;
     RECT  77.904 5.747 80.712 6.323 ;
     RECT  78 6.323 80.712 6.419 ;
     RECT  7.8 5.099 8.232 6.767 ;
     RECT  76.848 2.339 76.872 6.803 ;
     RECT  78 6.419 79.8 6.851 ;
     RECT  3.888 7.221 3.912 7.331 ;
     RECT  81.936 5.747 83.712 7.331 ;
     RECT  7.584 6.767 8.232 7.797 ;
     RECT  5.856 7.797 5.88 7.885 ;
     RECT  6.864 7.797 8.232 8.003 ;
     RECT  82.704 7.331 83.712 8.579 ;
     RECT  18.6 2.915 18.912 9.397 ;
     RECT  18.48 9.397 18.912 9.491 ;
     RECT  17.088 9.717 17.112 9.733 ;
     RECT  4.464 9.717 4.488 9.805 ;
     RECT  17.088 9.733 17.208 9.805 ;
     RECT  17.184 9.805 17.208 9.835 ;
     RECT  12.144 10.003 12.168 10.091 ;
     RECT  13.2 4.011 13.512 10.293 ;
     RECT  12.96 10.293 13.512 10.381 ;
     RECT  20.256 10.323 20.28 10.411 ;
     RECT  22.752 10.501 22.776 10.603 ;
     RECT  22.464 12.435 22.488 12.523 ;
     RECT  3.744 12.149 3.768 12.563 ;
     RECT  16.8 12.527 16.824 12.611 ;
     RECT  13.2 10.381 13.512 13.011 ;
     RECT  12.624 13.011 13.512 13.099 ;
     RECT  14.736 12.901 14.76 13.099 ;
     RECT  18.6 9.491 18.912 13.173 ;
     RECT  18.6 13.173 19.032 13.331 ;
     RECT  7.8 8.003 8.232 14.197 ;
     RECT  7.68 14.197 8.232 14.281 ;
     RECT  3.936 14.739 3.96 14.827 ;
     RECT  19.968 14.739 19.992 14.827 ;
     RECT  5.616 13.573 5.64 15.061 ;
     RECT  5.376 15.061 5.64 15.107 ;
     RECT  13.2 13.099 13.512 15.123 ;
     RECT  13.2 15.123 14.28 15.211 ;
     RECT  22.176 15.301 22.2 15.403 ;
     RECT  13.2 15.211 13.512 15.637 ;
     RECT  12.672 15.637 13.512 15.723 ;
     RECT  18.6 13.331 18.912 16.559 ;
     RECT  16.56 16.501 16.584 16.585 ;
     RECT  18.6 16.559 19.32 16.643 ;
     RECT  2.4 6.323 2.712 17.013 ;
     RECT  13.2 15.723 13.512 17.077 ;
     RECT  2.4 17.013 3.288 17.101 ;
     RECT  22.704 17.427 22.728 17.515 ;
     RECT  5.376 15.107 5.4 17.605 ;
     RECT  5.376 17.605 5.688 17.651 ;
     RECT  12.624 17.077 13.512 17.677 ;
     RECT  15.504 17.781 15.528 17.891 ;
     RECT  7.8 14.281 8.232 18.227 ;
     RECT  86.208 18.229 86.232 18.411 ;
     RECT  18.6 16.643 18.912 18.613 ;
     RECT  18.432 18.613 18.912 18.697 ;
     RECT  5.664 17.651 5.688 18.851 ;
     RECT  9.12 19.237 9.144 19.563 ;
     RECT  22.176 19.477 22.2 19.563 ;
     RECT  0.432 2.339 0.456 19.823 ;
     RECT  18.6 18.697 18.912 20.277 ;
     RECT  18.48 20.277 18.912 20.365 ;
     RECT  16.176 20.371 16.2 20.459 ;
     RECT  12.192 19.509 12.216 20.469 ;
     RECT  13.2 17.677 13.512 20.469 ;
     RECT  12.192 20.469 13.512 20.557 ;
     RECT  7.8 18.227 8.112 21.075 ;
     RECT  12.192 20.557 12.216 21.075 ;
     RECT  7.8 21.075 9.096 21.163 ;
     RECT  11.376 21.075 12.216 21.163 ;
     RECT  20.544 21.397 20.568 21.483 ;
     RECT  16.944 21.621 16.968 21.709 ;
     RECT  14.784 21.925 14.808 22.009 ;
     RECT  7.8 21.163 8.112 23.173 ;
     RECT  7.8 23.173 8.52 23.275 ;
     RECT  18.6 20.365 18.912 23.327 ;
     RECT  18.384 23.327 18.912 23.411 ;
     RECT  7.8 23.275 8.112 23.519 ;
     RECT  2.4 17.101 2.712 23.541 ;
     RECT  6.864 23.519 8.112 23.603 ;
     RECT  4.608 23.541 4.632 23.629 ;
     RECT  2.4 23.541 3.288 24.083 ;
     RECT  18.6 23.411 18.912 24.805 ;
     RECT  17.76 24.805 18.912 24.939 ;
     RECT  18.144 24.939 18.912 25.003 ;
     RECT  12.192 21.163 12.216 25.067 ;
     RECT  7.8 23.603 8.112 25.299 ;
     RECT  7.8 25.299 8.76 25.333 ;
     RECT  7.056 25.333 8.76 25.387 ;
     RECT  7.056 25.387 8.112 25.427 ;
     RECT  14.784 25.573 14.808 25.657 ;
     RECT  12 26.149 12.024 26.233 ;
     RECT  7.8 25.427 8.112 26.421 ;
     RECT  11.04 26.389 11.064 26.475 ;
     RECT  7.8 26.421 8.52 26.485 ;
     RECT  7.392 26.485 8.52 26.569 ;
     RECT  19.968 26.485 19.992 26.569 ;
     RECT  2.4 24.083 2.712 26.707 ;
     RECT  7.44 26.569 8.52 26.771 ;
     RECT  2.4 26.707 2.856 26.795 ;
     RECT  18.6 25.003 18.912 26.805 ;
     RECT  3.984 26.613 4.008 26.819 ;
     RECT  18.48 26.805 18.912 26.893 ;
     RECT  7.44 26.771 8.112 27.051 ;
     RECT  4.512 27.301 4.536 27.435 ;
     RECT  15.024 27.781 15.048 27.883 ;
     RECT  5.712 27.381 5.736 27.947 ;
     RECT  7.8 27.051 8.112 28.371 ;
     RECT  7.008 28.371 8.112 28.459 ;
     RECT  13.2 20.557 13.512 28.981 ;
     RECT  11.184 28.917 11.208 29.005 ;
     RECT  13.2 28.981 14.232 29.065 ;
     RECT  18.6 26.893 18.912 29.365 ;
     RECT  18.6 29.365 19.032 29.459 ;
     RECT  16.128 29.365 16.152 29.507 ;
     RECT  6.24 30.675 6.264 30.709 ;
     RECT  7.8 28.459 8.112 30.709 ;
     RECT  6.24 30.709 8.112 30.763 ;
     RECT  7.056 30.763 8.112 30.851 ;
     RECT  13.2 29.065 13.512 31.157 ;
     RECT  10.992 31.123 11.016 31.211 ;
     RECT  13.008 31.157 13.512 31.245 ;
     RECT  2.4 26.795 2.712 31.507 ;
     RECT  2.4 31.507 3.288 31.595 ;
     RECT  22.176 31.669 22.2 31.753 ;
     RECT  18.6 29.459 18.912 31.827 ;
     RECT  15.36 31.813 15.384 31.915 ;
     RECT  18.6 31.827 19.464 31.915 ;
     RECT  22.128 31.827 22.152 31.915 ;
     RECT  4.512 32.917 4.536 33.003 ;
     RECT  5.712 32.869 5.736 33.003 ;
     RECT  10.8 33.503 10.824 33.525 ;
     RECT  10.8 33.525 11.64 33.587 ;
     RECT  2.4 31.595 2.712 33.939 ;
     RECT  13.2 31.245 13.512 33.939 ;
     RECT  2.4 33.939 3.288 34.027 ;
     RECT  13.056 33.939 13.512 34.027 ;
     RECT  11.616 33.587 11.64 34.115 ;
     RECT  15.408 34.223 15.432 34.307 ;
     RECT  17.136 34.223 17.16 34.307 ;
     RECT  4.56 34.805 4.584 34.931 ;
     RECT  5.712 34.805 5.736 35.171 ;
     RECT  18.6 31.915 18.912 35.797 ;
     RECT  18.6 35.797 19.752 35.883 ;
     RECT  2.4 34.027 2.712 35.893 ;
     RECT  2.4 35.893 3.384 35.987 ;
     RECT  13.2 34.027 13.512 36.435 ;
     RECT  12.336 36.435 13.704 36.523 ;
     RECT  10.8 36.517 10.824 36.601 ;
     RECT  12 36.527 12.024 36.611 ;
     RECT  13.008 36.523 13.512 37.099 ;
     RECT  18.6 35.883 18.912 37.285 ;
     RECT  17.616 37.285 18.912 37.369 ;
     RECT  16.512 37.525 16.536 37.611 ;
     RECT  7.8 30.851 8.112 37.727 ;
     RECT  5.76 37.573 5.784 37.803 ;
     RECT  6.864 37.727 8.112 37.811 ;
     RECT  20.976 37.971 21 38.059 ;
     RECT  47.04 38.005 47.064 38.099 ;
     RECT  45.6 5.171 45.912 38.111 ;
     RECT  45.6 38.111 46.2 38.195 ;
     RECT  4.128 37.573 4.152 38.389 ;
     RECT  4.128 38.389 5.112 38.473 ;
     RECT  0.096 19.823 0.456 38.763 ;
     RECT  29.4 2.915 29.712 38.773 ;
     RECT  4.128 38.473 4.152 38.819 ;
     RECT  29.4 38.773 29.928 38.857 ;
     RECT  29.4 38.857 29.832 39.019 ;
     RECT  13.2 37.099 13.512 39.061 ;
     RECT  12.96 39.061 13.512 39.147 ;
     RECT  18.6 37.369 18.912 39.413 ;
     RECT  17.808 39.413 18.912 39.501 ;
     RECT  14.592 39.699 14.616 39.787 ;
     RECT  20.544 40.147 20.568 40.235 ;
     RECT  22.8 40.181 22.824 40.451 ;
     RECT  18.6 39.501 18.912 41.125 ;
     RECT  2.4 35.987 2.712 41.235 ;
     RECT  2.4 41.235 3.288 41.323 ;
     RECT  17.856 41.125 18.912 41.323 ;
     RECT  13.2 39.147 13.512 41.875 ;
     RECT  12.528 41.875 13.512 41.963 ;
     RECT  15.792 42.003 15.816 42.091 ;
     RECT  4.512 42.067 4.536 42.155 ;
     RECT  5.712 39.877 5.736 42.227 ;
     RECT  20.496 42.143 20.52 42.227 ;
     RECT  17.328 42.165 17.352 42.253 ;
     RECT  7.8 37.811 8.112 42.741 ;
     RECT  10.608 41.909 10.632 42.795 ;
     RECT  7.056 42.741 8.112 42.995 ;
     RECT  22.704 43.141 22.728 43.243 ;
     RECT  4.512 44.437 4.536 44.523 ;
     RECT  5.712 44.469 5.736 44.915 ;
     RECT  15.312 44.947 15.336 45.035 ;
     RECT  21.072 44.965 21.096 45.049 ;
     RECT  16.8 44.981 16.824 45.155 ;
     RECT  22.56 44.981 22.584 45.155 ;
     RECT  7.8 42.995 8.112 45.301 ;
     RECT  7.8 45.301 8.232 45.395 ;
     RECT  18.6 41.323 18.912 45.397 ;
     RECT  18.48 45.397 18.912 45.483 ;
     RECT  18.6 45.483 18.912 46.675 ;
     RECT  4.512 46.611 4.536 46.699 ;
     RECT  18.48 46.675 18.912 46.763 ;
     RECT  24 3.443 24.312 47.221 ;
     RECT  23.328 47.221 24.312 47.305 ;
     RECT  21.12 47.221 21.144 47.315 ;
     RECT  16.512 47.279 16.536 47.363 ;
     RECT  16.704 48.339 16.728 48.427 ;
     RECT  2.4 41.323 2.712 48.915 ;
     RECT  2.4 48.915 3.192 49.003 ;
     RECT  4.464 48.915 4.488 49.003 ;
     RECT  18.6 46.763 18.912 49.007 ;
     RECT  18.6 49.007 19.272 49.091 ;
     RECT  21.84 49.683 21.864 49.771 ;
     RECT  24 47.305 24.312 49.973 ;
     RECT  24 49.973 24.408 50.061 ;
     RECT  15.84 50.067 15.864 50.155 ;
     RECT  7.8 45.395 8.112 50.997 ;
     RECT  6.864 50.997 8.112 51.347 ;
     RECT  4.464 50.997 4.488 51.539 ;
     RECT  17.088 50.997 17.112 51.635 ;
     RECT  25.872 52.309 25.896 52.395 ;
     RECT  24 50.061 24.312 52.533 ;
     RECT  6.768 52.463 6.792 52.547 ;
     RECT  24 52.533 24.696 52.621 ;
     RECT  22.176 52.549 22.2 52.651 ;
     RECT  5.232 52.981 5.256 53.065 ;
     RECT  2.4 49.003 2.712 54.047 ;
     RECT  2.4 54.047 2.856 54.131 ;
     RECT  4.512 53.941 4.536 54.18 ;
     RECT  27.264 54.133 27.288 54.227 ;
     RECT  5.952 54.613 5.976 54.699 ;
     RECT  29.4 39.019 29.712 54.739 ;
     RECT  26.064 54.709 26.088 54.757 ;
     RECT  26.064 54.757 26.232 54.803 ;
     RECT  28.752 54.739 29.712 54.827 ;
     RECT  26.208 54.803 26.232 54.841 ;
     RECT  22.608 55.045 22.632 55.147 ;
     RECT  24 52.621 24.312 55.727 ;
     RECT  24 55.727 24.552 55.811 ;
     RECT  17.088 56.309 17.496 56.373 ;
     RECT  18.6 49.091 18.912 56.373 ;
     RECT  2.4 54.131 2.712 56.389 ;
     RECT  17.088 56.373 17.592 56.461 ;
     RECT  18.6 56.373 19.08 56.461 ;
     RECT  17.088 56.461 17.112 56.483 ;
     RECT  18.6 56.461 18.912 56.869 ;
     RECT  18.24 56.869 18.912 57.323 ;
     RECT  5.76 57.157 5.784 57.587 ;
     RECT  24 55.811 24.312 58.021 ;
     RECT  24 58.021 25.128 58.037 ;
     RECT  23.232 58.037 25.128 58.069 ;
     RECT  22.8 58.069 25.128 58.105 ;
     RECT  2.4 56.389 3.432 58.115 ;
     RECT  22.8 58.105 24.312 58.125 ;
     RECT  22.8 58.125 22.824 58.155 ;
     RECT  20.976 58.101 21 58.189 ;
     RECT  0.432 38.763 0.456 58.799 ;
     RECT  5.664 59.231 5.688 59.315 ;
     RECT  18.6 57.323 18.912 59.375 ;
     RECT  18.192 59.375 18.912 59.381 ;
     RECT  18.192 59.381 19.032 59.459 ;
     RECT  22.08 59.989 22.104 60.213 ;
     RECT  22.032 60.213 22.104 60.229 ;
     RECT  24 58.125 24.312 60.277 ;
     RECT  22.032 60.229 22.152 60.301 ;
     RECT  22.128 60.301 22.152 60.331 ;
     RECT  7.8 51.347 8.112 60.335 ;
     RECT  23.376 60.277 24.312 60.371 ;
     RECT  6.864 60.335 8.112 60.419 ;
     RECT  26.64 60.335 26.664 60.419 ;
     RECT  2.4 58.115 2.712 60.575 ;
     RECT  2.4 60.575 2.808 60.659 ;
     RECT  4.224 60.575 4.248 60.659 ;
     RECT  29.4 54.827 29.712 61.301 ;
     RECT  29.4 61.301 29.928 61.389 ;
     RECT  4.512 61.477 4.536 61.561 ;
     RECT  20.736 61.525 20.76 61.611 ;
     RECT  7.8 60.419 8.112 61.621 ;
     RECT  18.6 59.459 19.032 61.813 ;
     RECT  18.48 61.813 19.032 61.867 ;
     RECT  18.48 61.867 18.912 61.897 ;
     RECT  5.712 61.493 5.736 61.907 ;
     RECT  6.864 61.621 8.112 62.435 ;
     RECT  27.456 61.813 27.48 62.763 ;
     RECT  29.4 61.389 29.712 63.263 ;
     RECT  22.032 63.187 22.056 63.275 ;
     RECT  29.4 63.263 30.264 63.347 ;
     RECT  2.4 60.659 2.712 63.685 ;
     RECT  20.64 63.861 20.664 64.019 ;
     RECT  24 60.371 24.312 64.213 ;
     RECT  5.76 64.245 5.784 64.275 ;
     RECT  24 64.213 24.648 64.299 ;
     RECT  5.04 64.275 5.784 64.333 ;
     RECT  2.4 63.685 3.288 64.437 ;
     RECT  2.4 64.437 4.008 64.595 ;
     RECT  5.04 64.333 5.064 64.595 ;
     RECT  7.8 62.435 8.112 65.269 ;
     RECT  6.864 65.269 8.112 65.353 ;
     RECT  2.4 64.595 3.288 65.363 ;
     RECT  34.8 4.019 35.112 65.653 ;
     RECT  27.744 65.589 27.768 65.699 ;
     RECT  34.224 65.653 35.112 65.811 ;
     RECT  33.888 65.811 35.112 65.899 ;
     RECT  29.4 63.347 29.712 66.259 ;
     RECT  24 64.299 24.312 66.325 ;
     RECT  28.992 66.259 29.712 66.347 ;
     RECT  23.856 66.325 24.312 66.411 ;
     RECT  5.76 66.421 5.784 66.515 ;
     RECT  21.264 66.165 21.288 66.667 ;
     RECT  25.296 66.677 25.32 66.987 ;
     RECT  6.288 67.189 6.312 67.331 ;
     RECT  18.6 61.897 18.912 68.149 ;
     RECT  17.616 68.149 18.912 68.243 ;
     RECT  2.4 65.363 2.712 68.245 ;
     RECT  27.216 68.277 27.24 68.365 ;
     RECT  20.016 68.149 20.04 68.387 ;
     RECT  2.4 68.245 3.288 68.395 ;
     RECT  4.512 68.307 4.536 68.395 ;
     RECT  22.848 68.755 22.872 68.843 ;
     RECT  5.76 68.853 5.784 68.941 ;
     RECT  25.296 68.789 25.32 69.491 ;
     RECT  25.968 69.907 25.992 69.995 ;
     RECT  7.8 65.353 8.112 70.611 ;
     RECT  7.104 70.611 8.112 70.699 ;
     RECT  22.752 70.943 22.776 71.027 ;
     RECT  24 66.411 24.312 72.019 ;
     RECT  5.76 71.955 5.784 72.043 ;
     RECT  23.904 72.019 24.312 72.107 ;
     RECT  7.8 70.699 8.112 72.309 ;
     RECT  18.6 68.243 18.912 72.531 ;
     RECT  18.6 72.531 19.656 72.619 ;
     RECT  7.056 72.309 8.112 72.995 ;
     RECT  24 72.107 24.312 74.581 ;
     RECT  24 74.581 24.408 74.667 ;
     RECT  7.8 72.995 8.112 74.965 ;
     RECT  18.6 72.619 18.912 74.997 ;
     RECT  7.056 74.965 8.112 75.051 ;
     RECT  21.312 74.965 21.336 75.051 ;
     RECT  18.6 74.997 19.176 75.243 ;
     RECT  17.088 75.189 17.112 75.299 ;
     RECT  2.4 68.395 2.712 75.541 ;
     RECT  5.136 75.541 5.16 75.573 ;
     RECT  4.512 75.573 5.16 75.603 ;
     RECT  2.4 75.541 3.288 75.627 ;
     RECT  4.512 75.603 5.256 75.691 ;
     RECT  24 74.667 24.312 75.957 ;
     RECT  24 75.957 24.408 76.067 ;
     RECT  21.6 77.125 21.624 77.227 ;
     RECT  20.256 77.173 20.28 77.315 ;
     RECT  2.4 75.627 2.712 77.855 ;
     RECT  2.4 77.855 2.808 77.939 ;
     RECT  7.8 75.051 8.112 78.005 ;
     RECT  0.096 58.799 0.456 78.083 ;
     RECT  4.512 75.691 4.536 78.083 ;
     RECT  6.864 78.005 8.112 78.093 ;
     RECT  24 76.067 24.312 78.469 ;
     RECT  17.184 78.517 17.208 78.955 ;
     RECT  24 78.469 24.408 79.531 ;
     RECT  22.752 79.477 22.776 79.561 ;
     RECT  20.88 79.605 20.904 79.715 ;
     RECT  15.36 80.293 15.384 80.377 ;
     RECT  7.8 78.093 8.112 80.595 ;
     RECT  7.056 80.595 8.112 80.683 ;
     RECT  18.6 75.243 18.912 80.949 ;
     RECT  24 79.531 24.312 80.949 ;
     RECT  23.904 80.949 24.312 81.037 ;
     RECT  17.232 80.949 17.256 81.059 ;
     RECT  21.12 80.949 21.144 81.059 ;
     RECT  18.6 80.949 19.752 81.36 ;
     RECT  2.4 77.939 2.712 81.445 ;
     RECT  22.032 81.427 22.056 81.515 ;
     RECT  25.92 80.949 25.944 81.515 ;
     RECT  2.4 81.445 3.432 81.529 ;
     RECT  5.712 80.949 5.736 81.635 ;
     RECT  7.8 80.683 8.112 82.309 ;
     RECT  6.816 82.309 8.112 82.411 ;
     RECT  2.4 81.529 2.712 82.579 ;
     RECT  2.4 82.579 3.288 82.607 ;
     RECT  2.4 82.607 4.008 82.645 ;
     RECT  2.4 82.645 4.536 82.667 ;
     RECT  3.984 82.667 4.536 82.697 ;
     RECT  4.512 82.697 4.536 82.731 ;
     RECT  18.6 81.36 18.912 82.789 ;
     RECT  15.936 82.847 15.96 82.931 ;
     RECT  18.6 82.789 19.08 83.051 ;
     RECT  21.6 83.283 21.624 83.371 ;
     RECT  7.8 82.411 8.112 84.277 ;
     RECT  5.76 84.181 5.784 84.331 ;
     RECT  6.864 84.277 8.112 84.361 ;
     RECT  24 81.037 24.312 84.805 ;
     RECT  25.44 84.789 25.464 84.805 ;
     RECT  27.36 84.757 27.384 84.843 ;
     RECT  24 84.805 25.464 84.877 ;
     RECT  24 84.877 25.128 84.907 ;
     RECT  29.4 66.347 29.712 85.173 ;
     RECT  29.28 85.173 29.712 85.261 ;
     RECT  4.512 85.301 4.536 86.059 ;
     RECT  24 84.907 24.408 86.243 ;
     RECT  4.992 86.325 5.016 86.435 ;
     RECT  5.088 86.639 5.112 86.723 ;
     RECT  18.6 83.051 18.912 86.773 ;
     RECT  5.328 86.917 5.352 87.019 ;
     RECT  17.616 86.773 18.912 87.211 ;
     RECT  29.4 85.261 29.712 87.349 ;
     RECT  27.12 87.301 27.144 87.403 ;
     RECT  29.4 87.349 30.264 87.539 ;
     RECT  6.72 87.685 6.744 87.787 ;
     RECT  18.6 87.211 18.912 87.791 ;
     RECT  18.6 87.791 19.416 87.875 ;
     RECT  4.512 87.925 4.536 88.043 ;
     RECT  22.704 88.373 22.728 88.555 ;
     RECT  5.376 88.757 5.4 88.931 ;
     RECT  7.8 84.361 8.112 89.711 ;
     RECT  26.496 89.269 26.52 89.711 ;
     RECT  6.864 89.711 8.112 89.795 ;
     RECT  26.208 89.711 26.52 89.795 ;
     RECT  2.4 82.667 2.712 89.845 ;
     RECT  2.4 89.845 3.288 90.283 ;
     RECT  4.512 90.195 4.536 90.283 ;
     RECT  26.736 90.072 27 90.475 ;
     RECT  26.736 90.475 26.76 90.505 ;
     RECT  17.184 90.421 17.208 90.515 ;
     RECT  22.176 90.613 22.2 90.707 ;
     RECT  24 86.243 24.312 90.719 ;
     RECT  23.904 90.719 24.312 90.803 ;
     RECT  82.08 90.719 82.104 90.803 ;
     RECT  24 90.803 24.312 91.045 ;
     RECT  24 91.045 24.552 91.129 ;
     RECT  5.376 91.189 5.4 91.283 ;
     RECT  19.968 91.573 19.992 91.657 ;
     RECT  43.056 91.813 43.08 91.897 ;
     RECT  14.832 92.005 14.856 92.089 ;
     RECT  42.816 92.005 42.84 92.089 ;
     RECT  7.8 89.795 8.112 92.821 ;
     RECT  6.864 92.821 8.112 92.907 ;
     RECT  22.56 93.075 22.584 93.163 ;
     RECT  18.6 87.875 18.912 93.429 ;
     RECT  17.184 93.397 17.208 93.483 ;
     RECT  4.272 93.407 4.296 93.491 ;
     RECT  5.616 93.493 5.64 93.587 ;
     RECT  18.6 93.429 19.752 94.123 ;
     RECT  22.224 94.069 22.248 94.163 ;
     RECT  2.4 90.283 2.712 94.981 ;
     RECT  7.8 92.907 8.112 95.125 ;
     RECT  2.4 94.981 3.288 95.147 ;
     RECT  7.056 95.125 8.112 95.157 ;
     RECT  7.056 95.157 9.096 95.211 ;
     RECT  14.64 94.981 14.664 95.211 ;
     RECT  21.168 96.019 21.192 96.107 ;
     RECT  4.512 96.239 4.536 96.323 ;
     RECT  5.712 96.117 5.736 96.333 ;
     RECT  18.6 94.123 18.912 96.373 ;
     RECT  7.8 95.211 9.096 96.419 ;
     RECT  15.936 96.277 15.96 96.427 ;
     RECT  18.096 96.373 18.912 96.555 ;
     RECT  7.8 96.419 8.112 96.595 ;
     RECT  7.44 96.595 8.112 96.683 ;
     RECT  24 91.129 24.312 96.821 ;
     RECT  24 96.821 24.984 96.909 ;
     RECT  20.256 97.669 20.28 97.771 ;
     RECT  0.432 78.083 0.456 97.813 ;
     RECT  7.8 96.683 8.112 97.909 ;
     RECT  7.8 97.909 8.232 97.993 ;
     RECT  24 96.909 24.312 99.119 ;
     RECT  24 99.119 24.552 99.203 ;
     RECT  7.8 97.993 8.112 99.573 ;
     RECT  27.36 99.541 27.384 99.627 ;
     RECT  7.056 99.573 8.112 99.661 ;
     RECT  0.096 97.813 0.456 99.731 ;
     RECT  20.832 99.573 20.856 99.779 ;
     RECT  20.736 100.117 20.76 100.523 ;
     RECT  4.512 100.693 4.536 100.779 ;
     RECT  5.712 100.725 5.736 100.813 ;
     RECT  21.648 100.819 21.672 100.907 ;
     RECT  26.736 101.471 26.76 101.555 ;
     RECT  24 99.203 24.312 102.069 ;
     RECT  23.28 102.069 24.312 102.157 ;
     RECT  21.024 102.645 21.048 102.733 ;
     RECT  4.512 102.805 4.536 103.147 ;
     RECT  5.712 103.093 5.736 103.235 ;
     RECT  7.8 99.661 8.112 104.211 ;
     RECT  22.752 104.159 22.776 104.243 ;
     RECT  18.6 96.555 18.912 104.245 ;
     RECT  7.8 104.211 8.232 104.299 ;
     RECT  17.712 104.245 18.912 104.309 ;
     RECT  14.832 104.245 14.856 104.329 ;
     RECT  24 102.157 24.312 104.787 ;
     RECT  17.712 104.309 19.272 104.811 ;
     RECT  18.6 104.811 19.272 104.819 ;
     RECT  24 104.787 25.032 104.875 ;
     RECT  0.096 99.731 0.12 105.395 ;
     RECT  0.528 105.781 0.552 105.971 ;
     RECT  7.8 104.299 8.112 106.309 ;
     RECT  4.704 106.357 4.728 106.405 ;
     RECT  7.056 106.309 8.112 106.411 ;
     RECT  3.984 106.405 4.728 106.489 ;
     RECT  4.704 106.489 4.728 106.539 ;
     RECT  21.408 106.607 21.432 106.691 ;
     RECT  18.6 104.819 18.912 107.091 ;
     RECT  15.84 106.837 15.864 107.179 ;
     RECT  18.144 107.091 18.912 107.179 ;
     RECT  24 104.875 24.312 107.189 ;
     RECT  23.328 107.189 24.312 107.499 ;
     RECT  5.76 108.181 5.784 108.267 ;
     RECT  2.4 95.147 2.712 109.267 ;
     RECT  4.032 107.941 4.056 109.267 ;
     RECT  7.8 106.411 8.112 109.301 ;
     RECT  2.4 109.267 4.056 109.355 ;
     RECT  18.6 107.179 18.912 109.365 ;
     RECT  15.36 109.285 15.384 109.419 ;
     RECT  16.704 109.365 16.728 109.453 ;
     RECT  18.6 109.365 19.464 109.453 ;
     RECT  7.056 109.301 8.112 109.483 ;
     RECT  4.032 109.355 4.056 110.029 ;
     RECT  24 107.499 24.312 110.341 ;
     RECT  23.376 110.341 24.312 110.443 ;
     RECT  5.232 110.389 5.256 110.531 ;
     RECT  25.584 111.285 25.608 111.373 ;
     RECT  2.4 109.355 2.712 112.021 ;
     RECT  7.8 109.483 8.112 112.053 ;
     RECT  18.6 109.453 18.912 112.117 ;
     RECT  7.056 112.053 8.112 112.141 ;
     RECT  19.968 112.117 19.992 112.201 ;
     RECT  17.616 112.117 18.912 112.261 ;
     RECT  17.088 112.261 18.912 112.307 ;
     RECT  2.4 112.021 3.432 112.309 ;
     RECT  2.4 112.309 3.96 112.403 ;
     RECT  17.088 112.307 17.112 112.883 ;
     RECT  24 110.443 24.312 112.885 ;
     RECT  23.616 112.885 25.128 112.969 ;
     RECT  5.712 113.141 5.736 113.229 ;
     RECT  24 112.969 25.128 113.267 ;
     RECT  7.8 112.141 8.112 113.427 ;
     RECT  7.056 113.427 8.112 114.027 ;
     RECT  18.6 112.307 18.912 114.485 ;
     RECT  17.088 114.451 17.112 114.539 ;
     RECT  21.12 114.479 21.144 114.563 ;
     RECT  18.48 114.485 18.912 114.573 ;
     RECT  24 113.267 24.312 114.741 ;
     RECT  24 114.741 24.408 114.851 ;
     RECT  2.4 112.403 2.712 115.061 ;
     RECT  2.4 115.061 3.624 115.149 ;
     RECT  24 114.851 24.312 115.603 ;
     RECT  7.8 114.027 8.112 115.637 ;
     RECT  5.328 115.603 5.352 115.691 ;
     RECT  22.128 115.603 22.152 115.691 ;
     RECT  23.904 115.603 24.312 115.691 ;
     RECT  7.056 115.637 8.112 116.195 ;
     RECT  18.6 114.573 18.912 116.437 ;
     RECT  24 115.691 24.312 116.691 ;
     RECT  5.856 116.677 5.88 116.779 ;
     RECT  18.6 116.437 19.464 116.779 ;
     RECT  0.096 106.981 0.12 116.867 ;
     RECT  21.024 116.725 21.048 116.907 ;
     RECT  18.6 116.779 19.176 117.035 ;
     RECT  17.088 116.965 17.112 117.049 ;
     RECT  24 116.691 24.408 117.163 ;
     RECT  27.024 117.075 27.048 117.163 ;
     RECT  22.176 117.109 22.2 117.203 ;
     RECT  2.4 115.149 2.712 117.907 ;
     RECT  34.8 65.899 35.112 117.983 ;
     RECT  2.4 117.907 3.048 117.995 ;
     RECT  33.84 117.983 35.112 118.067 ;
     RECT  33.696 118.069 33.72 118.163 ;
     RECT  3.696 119.135 3.72 119.219 ;
     RECT  22.512 119.135 22.536 119.219 ;
     RECT  25.536 119.157 25.56 119.339 ;
     RECT  7.8 116.195 8.112 119.509 ;
     RECT  7.056 119.509 8.112 119.595 ;
     RECT  21.408 119.861 21.432 119.949 ;
     RECT  7.8 119.595 8.112 121.107 ;
     RECT  7.68 121.107 8.112 121.195 ;
     RECT  6.24 121.141 6.264 121.235 ;
     RECT  24 117.163 24.312 121.813 ;
     RECT  2.4 117.995 2.712 121.957 ;
     RECT  18.6 117.035 18.912 122.101 ;
     RECT  2.4 121.957 2.856 122.155 ;
     RECT  24 121.813 24.552 122.155 ;
     RECT  22.752 122.101 22.776 122.185 ;
     RECT  18.6 122.101 19.608 122.451 ;
     RECT  27.936 122.389 27.96 122.475 ;
     RECT  4.512 122.451 4.536 122.539 ;
     RECT  17.616 122.451 19.608 122.539 ;
     RECT  22.128 123.219 22.152 123.307 ;
     RECT  3.792 123.893 3.816 123.981 ;
     RECT  7.8 121.195 8.112 124.261 ;
     RECT  7.104 124.261 8.112 124.345 ;
     RECT  20.88 124.725 20.904 124.835 ;
     RECT  5.712 124.789 5.736 124.907 ;
     RECT  11.616 125.077 11.64 125.163 ;
     RECT  15.408 125.087 15.432 125.171 ;
     RECT  18.6 122.539 18.912 125.279 ;
     RECT  18.48 125.279 18.912 125.363 ;
     RECT  4.416 125.301 4.44 125.389 ;
     RECT  7.8 124.345 8.112 125.855 ;
     RECT  6.864 125.855 8.112 125.939 ;
     RECT  13.2 41.963 13.512 127.573 ;
     RECT  13.2 127.573 13.704 127.659 ;
     RECT  16.032 127.605 16.056 127.693 ;
     RECT  4.032 127.989 4.056 128.077 ;
     RECT  5.76 127.989 5.784 128.077 ;
     RECT  11.952 127.605 11.976 128.235 ;
     RECT  17.568 128.403 17.592 128.491 ;
     RECT  7.8 125.939 8.112 128.581 ;
     RECT  7.68 128.581 8.112 128.683 ;
     RECT  16.512 128.821 16.536 128.905 ;
     RECT  2.4 122.155 2.712 129.109 ;
     RECT  2.4 129.109 2.856 129.195 ;
     RECT  16.32 129.109 16.344 129.195 ;
     RECT  4.512 128.543 4.536 129.635 ;
     RECT  11.664 130.101 11.688 130.211 ;
     RECT  6.24 130.213 6.264 130.297 ;
     RECT  14.832 130.453 14.856 130.539 ;
     RECT  11.712 130.549 11.736 130.643 ;
     RECT  7.8 128.683 8.112 130.885 ;
     RECT  7.056 130.885 8.112 130.987 ;
     RECT  18.6 125.363 18.912 131.445 ;
     RECT  17.664 131.445 18.912 131.555 ;
     RECT  2.4 129.195 2.712 131.923 ;
     RECT  13.2 127.659 13.512 131.957 ;
     RECT  2.4 131.923 3.288 132.011 ;
     RECT  4.272 131.957 4.296 132.371 ;
     RECT  13.2 131.957 13.752 132.611 ;
     RECT  6.24 132.757 6.264 132.971 ;
     RECT  11.376 132.901 11.4 132.985 ;
     RECT  82.08 132.901 82.104 133.011 ;
     RECT  81.216 133.011 82.104 133.099 ;
     RECT  7.8 130.987 8.112 133.395 ;
     RECT  81.264 133.099 82.104 133.427 ;
     RECT  7.056 133.395 8.112 133.483 ;
     RECT  72.6 4.595 72.912 133.919 ;
     RECT  83.232 8.579 83.712 133.919 ;
     RECT  21.12 133.919 21.144 134.003 ;
     RECT  74.112 133.919 74.136 134.003 ;
     RECT  75.84 133.919 75.864 134.003 ;
     RECT  72.384 133.919 72.912 134.063 ;
     RECT  72.384 134.063 73.56 134.147 ;
     RECT  2.4 132.011 2.712 134.261 ;
     RECT  72.384 134.147 73.272 134.419 ;
     RECT  81.264 133.427 81.528 134.419 ;
     RECT  82.656 133.919 83.712 134.419 ;
     RECT  18.6 131.555 18.912 134.447 ;
     RECT  2.4 134.261 3.432 134.453 ;
     RECT  2.4 134.453 4.056 134.507 ;
     RECT  72.096 134.419 73.272 134.507 ;
     RECT  74.928 134.419 74.952 134.507 ;
     RECT  80.688 134.419 83.712 134.507 ;
     RECT  80.688 134.507 82.104 134.517 ;
     RECT  18.6 134.447 19.032 134.531 ;
     RECT  72.48 134.507 72.912 134.531 ;
     RECT  80.4 134.517 82.104 134.605 ;
     RECT  80.4 134.605 81.816 134.675 ;
     RECT  80.4 134.675 80.664 134.995 ;
     RECT  4.032 134.507 4.056 135.019 ;
     RECT  80.112 134.995 80.664 135.019 ;
     RECT  81.792 134.675 81.816 135.019 ;
     RECT  5.712 134.965 5.736 135.059 ;
     RECT  80.112 135.019 80.136 135.083 ;
     RECT  7.8 133.483 8.112 135.647 ;
     RECT  6.816 135.647 8.112 135.731 ;
     RECT  24 122.155 24.312 136.147 ;
     RECT  2.4 134.507 2.712 136.223 ;
     RECT  23.712 136.147 24.312 136.235 ;
     RECT  2.304 136.223 2.712 136.307 ;
     RECT  18.6 134.531 18.912 136.373 ;
     RECT  21.12 136.367 21.144 136.451 ;
     RECT  18.48 136.373 18.912 136.461 ;
     RECT  4.512 136.723 4.536 136.811 ;
     RECT  17.472 137.397 17.496 137.485 ;
     RECT  7.8 135.731 8.112 137.893 ;
     RECT  24 136.235 24.312 138.181 ;
     RECT  18.6 136.461 18.912 138.485 ;
     RECT  17.424 137.893 17.448 138.539 ;
     RECT  18.6 138.485 19.032 138.573 ;
     RECT  23.232 138.181 24.312 138.741 ;
     RECT  23.184 138.741 24.312 138.851 ;
     RECT  6.864 137.893 8.112 138.987 ;
     RECT  4.464 139.055 4.488 139.139 ;
     RECT  22.176 139.055 22.2 139.139 ;
     RECT  13.2 132.611 13.512 139.347 ;
     RECT  13.2 139.347 13.608 139.435 ;
     RECT  15.504 139.347 15.528 139.435 ;
     RECT  18.6 138.573 18.912 139.525 ;
     RECT  18.48 139.525 18.912 139.627 ;
     RECT  22.224 139.573 22.248 139.657 ;
     RECT  5.712 139.893 5.736 139.981 ;
     RECT  7.8 138.987 8.112 141.215 ;
     RECT  21.936 141.139 21.96 141.227 ;
     RECT  6.912 141.215 8.112 141.299 ;
     RECT  17.328 140.917 17.352 141.419 ;
     RECT  2.4 136.307 2.712 141.541 ;
     RECT  13.2 139.435 13.512 141.541 ;
     RECT  4.512 141.429 4.536 141.611 ;
     RECT  14.736 141.365 14.76 141.611 ;
     RECT  2.4 141.541 2.856 141.625 ;
     RECT  13.056 141.541 13.512 141.625 ;
     RECT  18.6 139.627 18.912 141.749 ;
     RECT  18.6 141.749 19.704 141.837 ;
     RECT  5.712 142.005 5.736 142.115 ;
     RECT  18.6 141.837 18.912 142.751 ;
     RECT  18.48 142.751 18.912 142.773 ;
     RECT  18.24 142.773 18.912 142.979 ;
     RECT  18.6 142.979 18.912 143.029 ;
     RECT  9.12 142.773 9.144 143.123 ;
     RECT  5.376 143.173 5.4 143.723 ;
     RECT  18.6 143.029 19.032 143.723 ;
     RECT  24 138.851 24.312 143.827 ;
     RECT  23.136 143.827 24.312 143.915 ;
     RECT  16.992 143.925 17.016 144.013 ;
     RECT  2.4 141.625 2.712 144.239 ;
     RECT  2.4 144.239 2.856 144.323 ;
     RECT  3.984 144.239 4.008 144.323 ;
     RECT  21.696 144.403 21.72 144.491 ;
     RECT  15.696 144.437 15.72 144.525 ;
     RECT  7.8 141.299 8.112 144.949 ;
     RECT  6.24 144.757 6.264 145.003 ;
     RECT  7.44 144.949 8.112 145.043 ;
     RECT  18.6 143.723 18.912 145.237 ;
     RECT  18.48 145.237 18.912 145.323 ;
     RECT  45.6 38.195 45.912 145.813 ;
     RECT  45.6 145.813 46.776 145.899 ;
     RECT  22.752 145.909 22.776 146.435 ;
     RECT  4.512 146.389 4.536 146.475 ;
     RECT  47.232 146.389 47.256 146.475 ;
     RECT  29.4 87.539 29.712 146.485 ;
     RECT  29.4 146.485 30.504 146.579 ;
     RECT  30.768 146.677 30.792 146.761 ;
     RECT  18.6 145.323 18.912 146.965 ;
     RECT  17.616 146.965 18.912 147.051 ;
     RECT  18.6 147.051 18.912 147.359 ;
     RECT  18.6 147.359 19.032 147.443 ;
     RECT  5.472 147.061 5.496 147.691 ;
     RECT  7.8 145.043 8.112 147.695 ;
     RECT  7.44 147.695 8.112 147.779 ;
     RECT  2.4 144.323 2.712 148.213 ;
     RECT  2.4 148.213 2.856 148.355 ;
     RECT  20.784 148.981 20.808 149.163 ;
     RECT  18.6 147.443 18.912 149.173 ;
     RECT  17.616 149.173 18.912 149.291 ;
     RECT  5.712 149.365 5.736 149.459 ;
     RECT  20.208 149.279 20.232 149.651 ;
     RECT  24 143.915 24.312 149.663 ;
     RECT  18.6 149.291 18.912 149.715 ;
     RECT  24 149.663 25.08 149.747 ;
     RECT  18.6 149.715 19.56 149.803 ;
     RECT  4.512 149.813 4.536 149.901 ;
     RECT  24 149.747 24.792 149.931 ;
     RECT  72.6 134.531 72.912 149.941 ;
     RECT  72.384 149.941 72.912 150.035 ;
     RECT  2.4 148.355 2.712 150.901 ;
     RECT  7.8 147.779 8.112 150.959 ;
     RECT  2.4 150.901 3.288 150.995 ;
     RECT  7.8 150.959 8.232 151.043 ;
     RECT  4.464 151.477 4.488 151.571 ;
     RECT  22.752 151.775 22.776 152.137 ;
     RECT  15.792 151.957 15.816 152.171 ;
     RECT  17.424 152.083 17.448 152.171 ;
     RECT  72.6 150.035 72.912 152.181 ;
     RECT  83.232 134.507 83.712 152.243 ;
     RECT  72.48 152.181 72.912 152.387 ;
     RECT  7.8 151.043 8.112 152.565 ;
     RECT  18.6 149.803 18.912 153.311 ;
     RECT  5.04 153.333 5.064 153.349 ;
     RECT  18.6 153.311 19.032 153.395 ;
     RECT  4.944 153.349 5.064 153.421 ;
     RECT  4.944 153.421 4.968 153.451 ;
     RECT  6.864 152.565 8.112 153.589 ;
     RECT  24 149.931 24.312 153.589 ;
     RECT  72.6 152.387 72.912 153.589 ;
     RECT  26.112 153.555 26.136 153.643 ;
     RECT  6.816 153.589 8.112 153.673 ;
     RECT  72.6 153.589 73.56 153.923 ;
     RECT  23.904 153.589 24.312 154.211 ;
     RECT  21.504 154.885 21.528 154.987 ;
     RECT  7.8 153.673 8.112 155.029 ;
     RECT  7.056 155.029 8.112 155.115 ;
     RECT  18.6 153.395 18.912 155.231 ;
     RECT  29.4 146.579 29.712 155.231 ;
     RECT  18.48 155.231 18.912 155.315 ;
     RECT  28.464 155.231 29.712 155.315 ;
     RECT  18.6 155.315 18.912 155.347 ;
     RECT  27.936 155.317 27.96 155.401 ;
     RECT  18.6 155.347 19.8 155.435 ;
     RECT  0.096 136.885 0.12 155.891 ;
     RECT  4.848 156.435 4.872 156.523 ;
     RECT  21.024 156.719 21.048 156.803 ;
     RECT  74.928 156.719 74.952 156.803 ;
     RECT  5.616 157.141 5.688 157.227 ;
     RECT  5.616 157.227 5.64 157.291 ;
     RECT  25.296 157.237 25.32 157.429 ;
     RECT  26.688 157.395 26.712 157.429 ;
     RECT  25.296 157.429 26.712 157.483 ;
     RECT  22.752 157.429 22.776 157.513 ;
     RECT  7.8 155.115 8.112 157.685 ;
     RECT  7.056 157.685 8.112 157.773 ;
     RECT  24 154.211 24.312 158.355 ;
     RECT  24 158.355 24.408 158.443 ;
     RECT  4.512 157.877 4.536 158.483 ;
     RECT  26.208 157.483 26.232 158.547 ;
     RECT  26.016 158.547 26.232 158.635 ;
     RECT  26.736 158.725 26.76 158.827 ;
     RECT  18.6 155.435 18.912 158.965 ;
     RECT  21.648 158.965 21.672 159.347 ;
     RECT  18.6 158.965 19.368 159.781 ;
     RECT  24 158.443 24.312 159.925 ;
     RECT  18.6 159.781 19.944 159.979 ;
     RECT  23.376 159.925 24.312 160.009 ;
     RECT  18.6 159.979 19.272 160.043 ;
     RECT  24 160.009 24.312 160.117 ;
     RECT  24 160.117 25.08 160.201 ;
     RECT  26.352 160.117 26.376 160.211 ;
     RECT  6.72 160.275 6.744 160.363 ;
     RECT  5.232 159.493 5.256 160.659 ;
     RECT  4.464 160.659 5.256 160.747 ;
     RECT  27.36 161.951 27.384 162.035 ;
     RECT  6.72 161.909 6.744 162.467 ;
     RECT  83.28 152.243 83.712 162.515 ;
     RECT  21.648 162.421 21.672 162.539 ;
     RECT  7.8 157.773 8.112 162.565 ;
     RECT  24 160.201 24.312 162.709 ;
     RECT  24 162.709 24.6 162.795 ;
     RECT  20.304 162.757 20.328 162.859 ;
     RECT  81.216 162.997 81.24 163.091 ;
     RECT  18.6 160.043 18.912 163.637 ;
     RECT  80.688 163.573 80.712 163.667 ;
     RECT  18.6 163.637 19.128 163.725 ;
     RECT  81.84 164.149 81.864 164.233 ;
     RECT  80.256 164.149 80.28 164.243 ;
     RECT  80.16 164.405 80.184 164.771 ;
     RECT  6.864 162.565 8.112 165.059 ;
     RECT  5.184 164.677 5.208 165.301 ;
     RECT  21.984 164.869 22.008 165.365 ;
     RECT  5.184 165.301 5.352 165.395 ;
     RECT  81.312 165.301 81.336 165.395 ;
     RECT  20.16 165.331 20.184 165.419 ;
     RECT  21.984 165.365 22.296 165.419 ;
     RECT  18.6 163.725 18.912 165.749 ;
     RECT  24 162.795 24.312 165.813 ;
     RECT  22.272 165.419 22.296 165.827 ;
     RECT  11.232 165.637 11.256 165.867 ;
     RECT  5.184 165.395 5.208 165.888 ;
     RECT  23.472 165.813 24.312 165.901 ;
     RECT  18.6 165.749 19.32 165.931 ;
     RECT  20.4 166.261 20.424 166.355 ;
     RECT  14.832 166.367 14.856 166.451 ;
     RECT  20.544 166.367 20.568 166.451 ;
     RECT  4.464 166.837 4.488 167.019 ;
     RECT  5.712 166.933 6.264 167.019 ;
     RECT  6.24 167.019 6.264 167.029 ;
     RECT  7.8 165.059 8.112 167.029 ;
     RECT  6.24 167.029 8.112 167.083 ;
     RECT  6.864 167.083 8.112 167.123 ;
     RECT  13.2 141.625 13.512 167.605 ;
     RECT  24 165.901 24.312 167.605 ;
     RECT  13.2 167.605 13.848 167.699 ;
     RECT  82.368 167.605 82.392 167.699 ;
     RECT  18.6 165.931 18.912 167.733 ;
     RECT  18.6 167.733 19.752 167.915 ;
     RECT  24 167.605 24.408 168.035 ;
     RECT  11.232 168.309 11.256 168.339 ;
     RECT  11.136 168.339 11.256 168.419 ;
     RECT  11.136 168.419 11.16 168.427 ;
     RECT  4.512 168.403 4.536 168.491 ;
     RECT  21.744 168.403 21.768 168.491 ;
     RECT  5.472 169.171 5.496 169.259 ;
     RECT  17.088 169.461 17.112 169.477 ;
     RECT  16.896 169.477 17.112 169.571 ;
     RECT  7.8 167.123 8.112 169.717 ;
     RECT  18.6 167.915 18.912 169.781 ;
     RECT  6.864 169.717 8.112 169.801 ;
     RECT  16.896 169.571 16.92 169.835 ;
     RECT  18.48 169.781 18.912 169.907 ;
     RECT  14.544 169.781 14.568 170.101 ;
     RECT  14.544 170.101 14.808 170.147 ;
     RECT  14.784 170.147 14.808 170.731 ;
     RECT  21.6 170.677 21.624 170.771 ;
     RECT  2.4 150.995 2.712 170.869 ;
     RECT  24 168.035 24.312 170.917 ;
     RECT  4.8 170.933 4.824 170.975 ;
     RECT  2.4 170.869 3.288 170.987 ;
     RECT  23.904 170.917 24.312 171.001 ;
     RECT  4.8 170.975 5.448 171.021 ;
     RECT  5.424 171.021 5.448 171.059 ;
     RECT  17.568 171.765 17.592 171.853 ;
     RECT  15.12 172.277 15.144 172.365 ;
     RECT  18.6 169.907 18.912 172.703 ;
     RECT  18.6 172.703 19.032 172.787 ;
     RECT  4.368 173.509 4.392 173.611 ;
     RECT  24 171.001 24.312 173.621 ;
     RECT  24 173.621 24.552 173.867 ;
     RECT  15.36 173.797 15.384 173.881 ;
     RECT  21.168 173.797 21.192 173.881 ;
     RECT  42.144 173.941 42.168 174.025 ;
     RECT  42 174.069 42.024 174.157 ;
     RECT  18.6 172.787 18.912 174.181 ;
     RECT  18.192 174.181 18.912 174.265 ;
     RECT  7.8 169.801 8.112 174.373 ;
     RECT  2.4 170.987 2.712 174.965 ;
     RECT  2.4 174.965 3.48 175.053 ;
     RECT  0.528 175.477 0.552 175.979 ;
     RECT  7.104 174.373 8.112 176.339 ;
     RECT  4.512 176.533 4.536 176.619 ;
     RECT  2.4 175.053 2.712 177.013 ;
     RECT  4.416 176.979 4.44 177.067 ;
     RECT  2.4 177.013 3.384 177.141 ;
     RECT  2.4 177.141 3.96 177.229 ;
     RECT  15.504 177.589 15.528 177.683 ;
     RECT  11.616 177.653 11.64 177.741 ;
     RECT  7.8 176.339 8.112 177.939 ;
     RECT  11.136 177.939 11.16 178.027 ;
     RECT  21.072 178.165 21.096 178.195 ;
     RECT  78 6.851 78.312 178.195 ;
     RECT  20.16 178.195 21.096 178.259 ;
     RECT  15.36 177.781 15.384 178.283 ;
     RECT  20.16 178.259 20.184 178.283 ;
     RECT  77.136 178.195 78.312 178.283 ;
     RECT  81.12 178.165 81.144 178.283 ;
     RECT  51 2.915 51.312 178.357 ;
     RECT  24 173.867 24.312 178.421 ;
     RECT  3.936 177.229 3.96 178.451 ;
     RECT  83.4 162.515 83.712 178.597 ;
     RECT  24 178.421 25.128 178.691 ;
     RECT  7.248 177.939 8.112 178.835 ;
     RECT  0.096 177.781 0.12 178.837 ;
     RECT  0.096 178.837 0.552 178.933 ;
     RECT  2.4 177.229 2.712 178.981 ;
     RECT  0.096 178.933 1.176 179.051 ;
     RECT  11.472 178.997 11.496 179.085 ;
     RECT  2.304 178.981 2.712 179.221 ;
     RECT  83.28 178.597 83.712 179.221 ;
     RECT  29.4 155.315 29.712 179.317 ;
     RECT  42.432 179.253 42.456 179.363 ;
     RECT  1.152 179.051 1.176 179.461 ;
     RECT  25.68 179.567 25.704 179.651 ;
     RECT  38.784 179.567 38.808 179.651 ;
     RECT  32.16 179.573 32.184 179.661 ;
     RECT  69.984 179.573 70.008 179.661 ;
     RECT  29.4 179.317 30.6 179.843 ;
     RECT  49.632 179.765 49.656 179.947 ;
     RECT  2.304 179.221 3.384 180.133 ;
     RECT  51 178.357 52.296 180.179 ;
     RECT  2.304 180.133 3.672 180.277 ;
     RECT  0.096 179.051 0.12 180.517 ;
     RECT  1.152 179.461 1.272 180.517 ;
     RECT  2.304 180.277 4.248 180.565 ;
     RECT  6 180.133 6.024 180.565 ;
     RECT  56.4 5.005 56.712 180.597 ;
     RECT  63.12 180.597 63.144 180.685 ;
     RECT  0.096 180.517 1.272 180.805 ;
     RECT  2.304 180.565 6.6 180.805 ;
     RECT  13.2 167.699 13.512 181.237 ;
     RECT  18.6 174.265 18.912 181.237 ;
     RECT  29.4 179.843 29.712 181.237 ;
     RECT  34.8 118.067 35.112 181.237 ;
     RECT  51 180.179 51.312 181.237 ;
     RECT  56.4 180.597 56.856 181.237 ;
     RECT  67.2 4.595 67.512 181.237 ;
     RECT  72.6 153.923 72.912 181.237 ;
     RECT  83.136 179.221 83.712 181.237 ;
     RECT  84.96 180.709 84.984 181.291 ;
     RECT  0.096 180.805 6.6 181.483 ;
     RECT  9.456 181.237 18.912 181.547 ;
     RECT  28.224 181.237 36.216 181.547 ;
     RECT  46.992 181.237 57.576 181.547 ;
     RECT  65.712 181.237 74.856 181.547 ;
     RECT  28.224 181.547 29.736 181.561 ;
     RECT  45.6 145.899 45.912 181.573 ;
     RECT  72.192 181.547 72.792 181.611 ;
     RECT  13.344 181.547 13.368 181.675 ;
     RECT  28.224 181.561 29.544 181.675 ;
     RECT  49.92 181.547 51.144 181.675 ;
     RECT  34.368 181.547 36.216 181.717 ;
     RECT  83.136 181.237 83.928 181.717 ;
     RECT  10.944 181.547 10.968 181.803 ;
     RECT  12.144 181.547 12.168 181.803 ;
     RECT  14.784 181.547 16.248 181.803 ;
     RECT  17.424 181.547 17.448 181.803 ;
     RECT  28.224 181.675 28.872 181.803 ;
     RECT  30.912 181.547 30.936 181.803 ;
     RECT  32.64 181.547 33 181.803 ;
     RECT  34.368 181.717 37.32 181.803 ;
     RECT  49.92 181.675 50.28 181.803 ;
     RECT  54.048 181.547 54.072 181.803 ;
     RECT  67.536 181.547 67.56 181.803 ;
     RECT  69.6 181.547 69.624 181.803 ;
     RECT  72.192 181.611 72.216 181.803 ;
     RECT  74.256 181.547 74.856 181.803 ;
     RECT  0.432 181.483 6.6 181.813 ;
     RECT  7.8 178.835 8.112 181.813 ;
     RECT  18.864 181.547 18.912 181.813 ;
     RECT  24 178.691 24.312 181.813 ;
     RECT  36.432 181.803 37.32 181.813 ;
     RECT  40.2 4.729 40.512 181.813 ;
     RECT  45.552 181.573 45.912 181.813 ;
     RECT  56.352 181.547 57.576 181.813 ;
     RECT  61.8 3.371 62.112 181.813 ;
     RECT  78 178.283 78.312 181.813 ;
     RECT  83.136 181.717 84.552 181.813 ;
     RECT  18.864 181.813 25.944 182.341 ;
     RECT  27.072 181.813 27.96 182.341 ;
     RECT  75.12 181.813 84.552 182.341 ;
     RECT  75.12 182.341 85.512 182.931 ;
     RECT  75.12 182.931 85.56 182.955 ;
     RECT  85.488 182.955 85.56 183.019 ;
     RECT  0.432 181.813 9.24 183.445 ;
     RECT  36.432 181.813 46.728 183.531 ;
     RECT  75.12 182.955 84.456 183.531 ;
     RECT  85.488 183.019 85.512 183.531 ;
     RECT  0.144 183.445 9.24 183.568 ;
     RECT  18.864 182.341 27.96 183.568 ;
     RECT  37.632 183.531 46.728 183.568 ;
     RECT  56.352 181.813 65.448 183.568 ;
     RECT  75.12 183.531 84.216 183.568 ;
    LAYER M6 ;
     RECT  0.016 19.84 0.131 38.752 ;
     RECT  0.016 58.816 0.131 77.792 ;
     RECT  0.016 97.856 0.131 116.832 ;
     RECT  0.016 136.896 0.131 155.872 ;
     RECT  0.016 175.936 0.131 183.328 ;
     RECT  0.131 105.792 0.563 106.464 ;
     RECT  0.131 175.936 0.563 177.184 ;
     RECT  0.131 179.008 0.563 180.256 ;
     RECT  0.563 180.224 1.187 180.256 ;
     RECT  0.131 182.08 1.763 183.328 ;
     RECT  0.563 106.432 2.16 106.464 ;
     RECT  0.563 176.576 2.16 177.184 ;
     RECT  1.763 182.08 2.16 182.112 ;
     RECT  2.16 137.529 2.293 138.201 ;
     RECT  2.16 180.729 2.387 182.112 ;
     RECT  2.293 136.256 2.603 138.201 ;
     RECT  2.16 78.129 2.773 78.801 ;
     RECT  2.16 121.329 2.821 122.001 ;
     RECT  2.16 142.929 2.821 143.601 ;
     RECT  2.16 148.329 2.821 149.001 ;
     RECT  2.16 34.929 3.234 35.601 ;
     RECT  2.16 24.129 3.253 24.801 ;
     RECT  3.234 33.984 3.253 35.601 ;
     RECT  2.16 40.329 3.253 41.001 ;
     RECT  2.16 67.329 3.253 68.001 ;
     RECT  2.16 83.529 3.253 84.201 ;
     RECT  2.16 88.929 3.253 89.601 ;
     RECT  2.16 94.329 3.253 95.001 ;
     RECT  2.16 110.529 3.253 111.201 ;
     RECT  2.16 132.129 3.253 132.801 ;
     RECT  2.16 169.929 3.253 170.601 ;
     RECT  3.234 31.552 3.307 31.584 ;
     RECT  3.253 32.96 3.307 35.601 ;
     RECT  3.307 34.816 3.349 35.601 ;
     RECT  3.253 82.624 3.397 84.201 ;
     RECT  2.549 134.272 3.397 134.304 ;
     RECT  2.16 175.329 3.426 177.184 ;
     RECT  3.349 34.816 3.435 35.936 ;
     RECT  3.397 134.272 3.443 134.496 ;
     RECT  3.426 174.976 3.499 177.184 ;
     RECT  2.16 115.929 3.589 116.601 ;
     RECT  3.013 117.952 3.685 117.984 ;
     RECT  2.16 13.329 3.733 14.001 ;
     RECT  3.589 115.072 3.755 116.601 ;
     RECT  3.685 117.952 3.755 119.2 ;
     RECT  2.16 7.929 3.877 8.601 ;
     RECT  3.733 12.16 3.925 14.001 ;
     RECT  3.253 109.312 3.925 111.201 ;
     RECT  3.499 175.329 3.925 177.184 ;
     RECT  2.821 26.752 3.973 26.784 ;
     RECT  2.821 142.929 4.019 144.288 ;
     RECT  3.253 94.329 4.021 95.136 ;
     RECT  2.16 126.729 4.021 127.401 ;
     RECT  2.821 129.152 4.021 129.184 ;
     RECT  3.443 134.464 4.021 134.496 ;
     RECT  2.821 148.224 4.021 149.001 ;
     RECT  3.253 150.912 4.021 150.944 ;
     RECT  3.925 109.312 4.067 112.352 ;
     RECT  4.021 134.464 4.067 135.008 ;
     RECT  3.973 26.624 4.075 26.784 ;
     RECT  4.021 148.224 4.075 151.52 ;
     RECT  3.877 7.232 4.213 8.601 ;
     RECT  4.021 94.329 4.213 96.288 ;
     RECT  2.821 121.329 4.213 122.144 ;
     RECT  3.781 123.904 4.213 123.936 ;
     RECT  2.773 60.608 4.259 60.64 ;
     RECT  3.925 12.16 4.267 14.816 ;
     RECT  4.213 123.904 4.267 125.344 ;
     RECT  4.213 93.44 4.307 96.288 ;
     RECT  3.445 173.568 4.403 173.6 ;
     RECT  4.267 124.864 4.451 125.344 ;
     RECT  3.925 175.329 4.451 178.016 ;
     RECT  2.16 51.129 4.453 51.801 ;
     RECT  2.603 137.529 4.453 138.201 ;
     RECT  2.16 159.129 4.453 159.801 ;
     RECT  2.16 45.729 4.455 46.401 ;
     RECT  3.253 40.329 4.469 41.312 ;
     RECT  4.455 44.48 4.469 46.401 ;
     RECT  4.021 126.729 4.469 129.184 ;
     RECT  4.453 137.529 4.469 139.104 ;
     RECT  4.075 151.488 4.499 151.52 ;
     RECT  4.469 5.632 4.501 5.664 ;
     RECT  2.16 61.929 4.501 62.601 ;
     RECT  3.397 81.472 4.501 84.201 ;
     RECT  3.253 88.929 4.501 90.272 ;
     RECT  2.16 99.729 4.501 100.401 ;
     RECT  2.821 141.568 4.501 141.6 ;
     RECT  4.453 159.129 4.501 160.736 ;
     RECT  4.213 7.232 4.523 9.76 ;
     RECT  3.157 48.96 4.523 48.992 ;
     RECT  4.453 51.008 4.523 51.801 ;
     RECT  3.253 131.968 4.523 132.801 ;
     RECT  4.501 81.472 4.533 86.048 ;
     RECT  4.469 44.48 4.547 46.688 ;
     RECT  2.821 54.08 4.547 54.112 ;
     RECT  2.773 77.888 4.547 78.801 ;
     RECT  4.213 121.329 4.547 122.528 ;
     RECT  4.469 126.729 4.547 129.568 ;
     RECT  4.469 136.768 4.547 139.104 ;
     RECT  4.075 148.329 4.547 149.856 ;
     RECT  4.451 175.329 4.547 176.608 ;
     RECT  4.533 81.472 4.587 86.368 ;
     RECT  4.501 5.056 4.595 5.664 ;
     RECT  2.16 105.129 4.693 106.464 ;
     RECT  2.16 153.729 4.933 154.401 ;
     RECT  4.587 86.336 5.027 86.368 ;
     RECT  3.253 64.448 5.029 64.48 ;
     RECT  4.933 153.408 5.029 154.401 ;
     RECT  4.837 156.48 5.045 156.512 ;
     RECT  4.501 157.888 5.045 160.736 ;
     RECT  5.045 156.48 5.099 160.736 ;
     RECT  2.16 164.529 5.109 165.201 ;
     RECT  4.453 166.976 5.109 167.008 ;
     RECT  3.253 75.584 5.171 75.616 ;
     RECT  5.109 164.529 5.219 167.008 ;
     RECT  4.523 51.129 5.221 51.801 ;
     RECT  2.16 56.529 5.237 57.201 ;
     RECT  4.067 109.952 5.237 112.352 ;
     RECT  5.221 51.129 5.291 53.024 ;
     RECT  5.221 75.648 5.291 75.68 ;
     RECT  5.077 86.656 5.291 86.688 ;
     RECT  5.237 109.952 5.291 113.184 ;
     RECT  4.501 88 5.317 90.272 ;
     RECT  4.019 142.929 5.346 143.601 ;
     RECT  5.219 164.529 5.363 165.344 ;
     RECT  5.317 86.976 5.365 90.272 ;
     RECT  3.253 17.024 5.411 17.056 ;
     RECT  3.253 169.929 5.413 170.976 ;
     RECT  5.365 86.976 5.419 91.232 ;
     RECT  5.346 142.929 5.419 143.712 ;
     RECT  5.029 153.344 5.419 154.401 ;
     RECT  4.501 146.432 5.429 146.464 ;
     RECT  4.547 148.329 5.429 149.408 ;
     RECT  4.501 168.448 5.429 168.48 ;
     RECT  5.413 169.929 5.429 171.04 ;
     RECT  5.419 91.2 5.434 91.232 ;
     RECT  5.429 146.432 5.483 149.408 ;
     RECT  5.429 168.448 5.483 171.04 ;
     RECT  5.483 147.072 5.507 149.408 ;
     RECT  5.483 169.216 5.507 170.601 ;
     RECT  4.307 94.329 5.605 96.288 ;
     RECT  5.605 93.504 5.621 96.288 ;
     RECT  4.267 13.329 5.651 14.816 ;
     RECT  5.099 157.184 5.651 157.28 ;
     RECT  5.621 92.864 5.675 96.288 ;
     RECT  5.507 147.52 5.675 149.408 ;
     RECT  5.237 56.32 5.685 57.201 ;
     RECT  4.547 137.529 5.685 139.104 ;
     RECT  4.501 141.44 5.685 141.6 ;
     RECT  5.419 142.929 5.685 143.601 ;
     RECT  4.501 27.392 5.701 27.424 ;
     RECT  4.587 81.472 5.701 81.504 ;
     RECT  5.029 64.32 5.73 64.544 ;
     RECT  3.253 67.329 5.73 68.384 ;
     RECT  5.653 59.264 5.739 59.296 ;
     RECT  5.675 147.648 5.739 149.408 ;
     RECT  3.307 32.96 5.747 32.992 ;
     RECT  3.435 34.816 5.747 35.601 ;
     RECT  4.469 40.329 5.747 42.144 ;
     RECT  4.547 44.48 5.747 46.401 ;
     RECT  5.701 80.96 5.747 81.504 ;
     RECT  4.501 99.729 5.747 100.768 ;
     RECT  4.501 103.104 5.747 103.136 ;
     RECT  5.291 113.152 5.747 113.184 ;
     RECT  4.067 134.976 5.747 135.008 ;
     RECT  5.739 147.712 5.747 149.408 ;
     RECT  5.219 166.976 5.747 167.008 ;
     RECT  5.077 38.4 5.749 38.432 ;
     RECT  5.73 64.256 5.749 64.544 ;
     RECT  5.73 66.432 5.749 68.384 ;
     RECT  2.16 72.729 5.749 73.401 ;
     RECT  4.451 124.864 5.749 124.896 ;
     RECT  4.547 126.729 5.749 128.608 ;
     RECT  5.685 137.529 5.758 139.936 ;
     RECT  5.685 141.248 5.758 143.601 ;
     RECT  5.749 64.256 5.803 68.896 ;
     RECT  5.749 124.864 5.803 128.608 ;
     RECT  4.523 7.929 5.845 8.601 ;
     RECT  3.755 115.648 5.845 116.601 ;
     RECT  5.675 94.329 5.941 96.288 ;
     RECT  5.685 56.32 5.995 57.312 ;
     RECT  5.803 65.28 5.995 68.896 ;
     RECT  4.693 105.129 5.995 106.528 ;
     RECT  5.941 54.656 6.01 54.688 ;
     RECT  2.16 29.529 6.229 30.201 ;
     RECT  4.547 121.329 6.229 122.001 ;
     RECT  4.523 132.129 6.229 132.801 ;
     RECT  5.995 67.2 6.323 68.001 ;
     RECT  5.099 159.129 6.709 160.736 ;
     RECT  5.419 87.744 6.755 89.76 ;
     RECT  5.291 51.129 6.757 51.801 ;
     RECT  6.709 159.129 6.763 161.952 ;
     RECT  6.757 51.129 6.773 52.512 ;
     RECT  4.587 83.529 6.773 84.32 ;
     RECT  6.763 161.92 6.778 161.952 ;
     RECT  5.419 153.729 6.805 154.401 ;
     RECT  6.773 51.008 6.827 52.512 ;
     RECT  5.701 27.392 6.837 27.936 ;
     RECT  6.229 29.529 6.837 30.752 ;
     RECT  4.501 61.504 6.837 62.601 ;
     RECT  6.773 82.368 6.851 84.32 ;
     RECT  4.547 78.129 6.853 78.801 ;
     RECT  6.805 153.6 6.853 154.401 ;
     RECT  6.837 27.008 6.891 30.752 ;
     RECT  3.253 23.552 6.899 24.801 ;
     RECT  5.749 37.76 6.899 38.432 ;
     RECT  6.827 51.008 6.899 51.801 ;
     RECT  5.995 65.28 6.899 65.312 ;
     RECT  6.851 83.529 6.899 84.32 ;
     RECT  6.755 88.929 6.899 89.76 ;
     RECT  5.675 92.864 6.899 92.896 ;
     RECT  5.803 125.888 6.899 128.608 ;
     RECT  5.758 137.529 6.899 138.976 ;
     RECT  6.229 167.04 6.899 167.072 ;
     RECT  5.507 169.728 6.899 170.601 ;
     RECT  6.837 60.352 6.91 62.601 ;
     RECT  6.91 61.632 6.933 62.601 ;
     RECT  5.758 141.248 6.947 141.28 ;
     RECT  6.853 152.576 6.955 154.401 ;
     RECT  5.749 108.224 7.022 108.256 ;
     RECT  5.291 110.529 7.022 111.201 ;
     RECT  5.845 7.808 7.029 8.601 ;
     RECT  7.022 108.224 7.029 111.201 ;
     RECT  6.891 28.416 7.043 30.752 ;
     RECT  6.899 24.129 7.045 24.801 ;
     RECT  5.747 80.96 7.045 80.992 ;
     RECT  5.747 99.729 7.045 100.401 ;
     RECT  7.029 113.472 7.045 113.504 ;
     RECT  6.229 130.24 7.045 130.272 ;
     RECT  6.229 132.129 7.045 132.96 ;
     RECT  6.955 153.6 7.045 154.401 ;
     RECT  5.651 157.184 7.045 157.216 ;
     RECT  5.941 94.329 7.083 96.672 ;
     RECT  7.043 29.529 7.091 30.752 ;
     RECT  7.029 108.224 7.102 112.096 ;
     RECT  7.045 113.472 7.102 114.016 ;
     RECT  5.749 72 7.147 73.401 ;
     RECT  7.045 75.008 7.147 75.04 ;
     RECT  6.853 78.016 7.147 78.801 ;
     RECT  7.045 80.64 7.147 80.992 ;
     RECT  5.995 105.129 7.147 106.4 ;
     RECT  7.102 108.224 7.147 111.201 ;
     RECT  7.102 113.984 7.147 114.016 ;
     RECT  5.845 115.648 7.147 116.768 ;
     RECT  7.045 119.552 7.147 119.584 ;
     RECT  7.045 130.24 7.147 133.472 ;
     RECT  6.805 135.68 7.147 135.712 ;
     RECT  7.045 153.6 7.147 155.104 ;
     RECT  7.045 157.184 7.147 157.728 ;
     RECT  7.093 70.656 7.162 70.688 ;
     RECT  7.093 124.288 7.162 124.32 ;
     RECT  7.045 24.129 7.381 25.376 ;
     RECT  6.891 27.008 7.381 27.04 ;
     RECT  4.595 5.056 7.429 5.088 ;
     RECT  7.429 4.928 7.475 5.088 ;
     RECT  7.381 24.129 7.475 27.04 ;
     RECT  7.083 96.64 7.475 96.672 ;
     RECT  6.229 144.96 7.475 144.992 ;
     RECT  5.747 147.712 7.475 149.001 ;
     RECT  7.029 6.784 7.619 8.601 ;
     RECT  6.899 126.729 7.65 128.608 ;
     RECT  5.651 13.329 7.669 14.001 ;
     RECT  6.229 121.152 7.715 122.001 ;
     RECT  7.65 126.729 7.723 128.672 ;
     RECT  7.147 105.129 8.151 105.801 ;
     RECT  5.747 45.729 8.181 46.401 ;
     RECT  7.045 99.584 8.235 100.401 ;
     RECT  7.989 97.92 8.243 97.952 ;
     RECT  6.901 150.976 8.243 151.008 ;
     RECT  8.181 45.312 8.254 46.401 ;
     RECT  7.475 24.129 8.485 26.528 ;
     RECT  8.485 23.232 8.771 26.528 ;
     RECT  2.16 18.729 9.109 19.401 ;
     RECT  5.758 142.929 9.109 143.601 ;
     RECT  7.669 13.329 9.131 14.24 ;
     RECT  9.061 21.12 9.131 21.152 ;
     RECT  8.771 23.232 9.131 24.801 ;
     RECT  2.387 180.729 9.445 181.401 ;
     RECT  2.16 2.529 9.461 3.201 ;
     RECT  9.461 1.728 10.094 3.201 ;
     RECT  10.094 1.728 10.357 3.488 ;
     RECT  5.747 40.329 10.597 41.001 ;
     RECT  7.045 42.752 10.597 42.784 ;
     RECT  10.597 40.329 10.643 42.784 ;
     RECT  5.747 34.929 10.789 35.601 ;
     RECT  9.445 180.729 10.933 181.536 ;
     RECT  7.091 29.529 10.981 30.201 ;
     RECT  10.357 0.576 11.027 3.488 ;
     RECT  4.547 175.329 11.125 176.001 ;
     RECT  4.451 177.984 11.125 178.016 ;
     RECT  10.981 29.529 11.173 31.2 ;
     RECT  11.106 168.384 11.178 168.416 ;
     RECT  11.178 168.32 11.179 168.416 ;
     RECT  8.771 26.432 11.189 26.528 ;
     RECT  5.363 164.529 11.189 165.201 ;
     RECT  11.173 28.928 11.243 31.2 ;
     RECT  11.189 164.529 11.267 165.856 ;
     RECT  11.179 168.32 11.267 168.352 ;
     RECT  7.147 130.24 11.317 130.272 ;
     RECT  7.147 132.129 11.317 132.801 ;
     RECT  9.109 18.729 11.381 19.552 ;
     RECT  11.365 21.12 11.381 21.152 ;
     RECT  11.317 132.129 11.411 132.96 ;
     RECT  11.381 18.729 11.435 21.152 ;
     RECT  11.125 175.329 11.461 178.016 ;
     RECT  10.789 33.536 11.605 33.568 ;
     RECT  10.789 34.929 11.605 36.576 ;
     RECT  11.461 175.329 11.627 179.04 ;
     RECT  11.605 33.536 11.651 36.576 ;
     RECT  11.627 177.664 11.651 178.016 ;
     RECT  7.723 126.729 11.701 128.608 ;
     RECT  11.317 130.112 11.701 130.272 ;
     RECT  11.701 126.729 11.77 130.592 ;
     RECT  11.027 0.576 11.829 0.608 ;
     RECT  11.77 126.729 11.987 130.144 ;
     RECT  11.189 26.176 12.035 26.528 ;
     RECT  9.131 24.129 12.181 24.801 ;
     RECT  10.933 180.729 12.203 181.792 ;
     RECT  12.035 26.496 12.213 26.528 ;
     RECT  12.181 24.129 12.267 25.056 ;
     RECT  12.213 26.496 12.267 26.784 ;
     RECT  6.899 38.4 12.267 38.432 ;
     RECT  12.267 26.752 12.395 26.784 ;
     RECT  11.027 2.529 12.469 3.488 ;
     RECT  7.475 4.928 12.469 4.96 ;
     RECT  12.469 2.529 12.523 4.96 ;
     RECT  11.435 18.729 12.597 20.512 ;
     RECT  9.131 13.329 12.613 14.001 ;
     RECT  12.597 17.6 12.613 20.512 ;
     RECT  12.613 17.088 12.651 20.512 ;
     RECT  12.613 13.056 12.661 14.001 ;
     RECT  12.642 15.68 12.661 15.712 ;
     RECT  12.651 17.088 12.67 19.401 ;
     RECT  12.661 13.056 12.715 15.712 ;
     RECT  12.67 17.088 12.715 17.12 ;
     RECT  7.619 7.929 12.789 8.601 ;
     RECT  12.133 10.048 12.789 10.08 ;
     RECT  12.789 7.929 12.917 10.08 ;
     RECT  10.643 40.329 12.917 41.952 ;
     RECT  12.917 7.929 12.971 10.336 ;
     RECT  12.917 39.104 12.971 41.952 ;
     RECT  12.971 10.304 12.995 10.336 ;
     RECT  12.971 39.104 12.995 41.184 ;
     RECT  11.651 33.984 12.997 36.576 ;
     RECT  11.243 29.529 13.043 31.2 ;
     RECT  9.109 142.784 13.045 143.601 ;
     RECT  12.997 33.984 13.099 37.088 ;
     RECT  11.829 0.064 13.139 0.608 ;
     RECT  13.139 0.576 13.301 0.608 ;
     RECT  12.523 2.529 13.301 4.704 ;
     RECT  13.301 0.576 13.379 4.704 ;
     RECT  12.203 180.729 13.379 181.664 ;
     RECT  6.899 137.529 13.573 138.201 ;
     RECT  13.379 2.529 13.69 4.704 ;
     RECT  13.099 34.24 13.715 36.512 ;
     RECT  11.987 126.729 13.715 127.648 ;
     RECT  11.411 132.129 13.717 132.801 ;
     RECT  11.987 129.152 13.749 130.144 ;
     RECT  13.749 129.152 13.803 130.528 ;
     RECT  13.717 131.968 13.803 132.801 ;
     RECT  13.043 29.529 14.197 30.201 ;
     RECT  12.715 13.056 14.291 15.2 ;
     RECT  11.267 164.529 14.517 165.201 ;
     RECT  13.813 167.616 14.517 167.648 ;
     RECT  6.899 169.929 14.517 170.601 ;
     RECT  14.517 164.529 14.571 167.648 ;
     RECT  14.517 169.792 14.59 170.601 ;
     RECT  12.995 39.744 14.627 41.184 ;
     RECT  13.045 141.568 14.725 143.601 ;
     RECT  13.379 180.729 14.754 181.536 ;
     RECT  14.291 13.056 14.771 14.001 ;
     RECT  14.725 141.376 14.771 143.601 ;
     RECT  13.379 0.576 14.773 1.184 ;
     RECT  12.267 24.129 14.773 24.928 ;
     RECT  14.59 169.929 14.773 170.601 ;
     RECT  7.083 94.329 14.827 95.2 ;
     RECT  14.773 92.032 14.867 92.064 ;
     RECT  8.151 104.256 14.867 105.801 ;
     RECT  13.803 130.496 14.867 130.528 ;
     RECT  14.571 164.529 14.867 166.432 ;
     RECT  14.773 169.929 14.891 170.72 ;
     RECT  14.197 28.992 14.901 30.201 ;
     RECT  14.773 24.129 14.955 25.632 ;
     RECT  14.901 27.84 15.083 30.201 ;
     RECT  14.837 172.288 15.155 172.32 ;
     RECT  8.254 45.729 15.301 46.401 ;
     RECT  14.773 0.064 15.349 1.184 ;
     RECT  13.69 2.529 15.349 3.201 ;
     RECT  7.147 110.529 15.349 111.201 ;
     RECT  11.651 177.984 15.349 178.016 ;
     RECT  15.349 173.824 15.418 173.856 ;
     RECT  13.715 34.24 15.443 35.601 ;
     RECT  11.605 125.12 15.443 125.152 ;
     RECT  12.67 18.729 15.493 19.401 ;
     RECT  15.349 177.6 15.539 178.272 ;
     RECT  14.771 142.784 15.685 143.601 ;
     RECT  14.627 40.329 15.781 41.184 ;
     RECT  6.899 51.129 15.829 51.801 ;
     RECT  6.899 83.529 15.925 84.201 ;
     RECT  15.493 17.792 15.989 19.401 ;
     RECT  13.715 126.729 16.021 127.401 ;
     RECT  15.989 16.512 16.165 19.401 ;
     RECT  16.165 16.512 16.299 20.448 ;
     RECT  13.803 129.152 16.355 129.184 ;
     RECT  13.69 4.672 16.357 4.704 ;
     RECT  16.299 18.729 16.501 20.448 ;
     RECT  14.773 21.952 16.501 21.984 ;
     RECT  15.301 44.992 16.501 46.401 ;
     RECT  16.021 126.729 16.501 127.648 ;
     RECT  16.501 18.729 16.555 21.984 ;
     RECT  15.349 0.064 16.57 3.201 ;
     RECT  16.299 16.512 16.595 16.544 ;
     RECT  16.501 44.992 16.619 47.328 ;
     RECT  16.674 48.384 16.747 48.416 ;
     RECT  12.971 7.929 16.757 8.601 ;
     RECT  14.771 13.329 16.789 14.001 ;
     RECT  16.357 4.672 16.811 5.664 ;
     RECT  16.57 2.529 16.814 3.201 ;
     RECT  16.811 4.672 16.814 4.704 ;
     RECT  16.757 7.929 16.821 9.76 ;
     RECT  16.789 12.544 16.875 14.001 ;
     RECT  16.814 2.529 16.883 4.704 ;
     RECT  14.891 169.929 16.885 170.601 ;
     RECT  15.685 142.784 17.003 144.48 ;
     RECT  17.003 142.784 17.027 143.968 ;
     RECT  15.829 50.112 17.067 51.801 ;
     RECT  15.443 34.929 17.077 35.601 ;
     RECT  7.147 115.929 17.077 116.768 ;
     RECT  16.885 169.792 17.077 170.601 ;
     RECT  17.067 51.008 17.123 51.801 ;
     RECT  15.349 31.872 17.131 31.904 ;
     RECT  17.077 34.24 17.171 35.601 ;
     RECT  7.147 78.129 17.173 78.801 ;
     RECT  6.899 88.929 17.173 89.601 ;
     RECT  14.827 94.329 17.173 95.001 ;
     RECT  15.349 80.32 17.205 80.352 ;
     RECT  17.173 88.929 17.205 90.464 ;
     RECT  16.821 7.929 17.219 9.824 ;
     RECT  17.173 78.129 17.259 78.944 ;
     RECT  17.205 80.32 17.259 81.312 ;
     RECT  15.925 82.88 17.259 84.201 ;
     RECT  17.205 88.929 17.259 91.616 ;
     RECT  17.259 80.96 17.278 81.312 ;
     RECT  15.781 40.329 17.317 42.08 ;
     RECT  14.771 141.376 17.317 141.408 ;
     RECT  17.317 140.928 17.363 141.408 ;
     RECT  16.619 44.992 17.387 46.401 ;
     RECT  17.363 140.928 17.387 140.96 ;
     RECT  13.573 137.529 17.442 139.424 ;
     RECT  14.754 180.729 17.459 181.792 ;
     RECT  7.475 148.329 17.461 149.001 ;
     RECT  17.077 169.472 17.557 170.601 ;
     RECT  17.317 40.329 17.589 42.208 ;
     RECT  13.803 132.129 17.589 132.801 ;
     RECT  16.501 37.568 17.605 37.6 ;
     RECT  6.323 67.329 17.605 68.001 ;
     RECT  15.349 109.376 17.605 111.201 ;
     RECT  7.715 121.329 17.605 122.001 ;
     RECT  17.461 148.329 17.605 149.152 ;
     RECT  17.605 37.312 17.643 37.6 ;
     RECT  17.589 39.424 17.643 42.208 ;
     RECT  16.501 126.729 17.643 128.864 ;
     RECT  16.57 0.064 17.699 0.608 ;
     RECT  14.867 105.129 17.701 105.801 ;
     RECT  17.643 39.424 17.843 41.312 ;
     RECT  16.883 2.529 17.966 3.201 ;
     RECT  17.843 40.329 18.027 41.312 ;
     RECT  5.995 56.32 18.027 57.201 ;
     RECT  17.966 2.304 18.035 3.201 ;
     RECT  15.925 96.384 18.085 96.416 ;
     RECT  18.085 96.384 18.131 96.544 ;
     RECT  14.955 24.129 18.133 24.928 ;
     RECT  15.829 107.136 18.179 107.168 ;
     RECT  11.627 175.329 18.181 176.001 ;
     RECT  18.027 56.384 18.21 57.201 ;
     RECT  16.555 21.632 18.229 21.664 ;
     RECT  17.605 147.008 18.229 147.04 ;
     RECT  17.605 148.329 18.229 149.28 ;
     RECT  15.781 152.128 18.229 152.16 ;
     RECT  7.147 153.729 18.229 154.401 ;
     RECT  18.21 56.384 18.283 57.312 ;
     RECT  18.229 152.128 18.283 154.401 ;
     RECT  17.699 0.576 18.293 0.608 ;
     RECT  18.133 24.129 18.35 24.992 ;
     RECT  18.293 0.576 18.371 1.184 ;
     RECT  18.229 21.504 18.41 21.664 ;
     RECT  18.35 23.36 18.419 24.992 ;
     RECT  16.555 18.729 18.421 19.401 ;
     RECT  18.41 21.44 18.421 21.664 ;
     RECT  17.387 45.44 18.469 46.401 ;
     RECT  6.933 61.929 18.469 62.601 ;
     RECT  17.442 137.408 18.469 139.424 ;
     RECT  18.283 153.344 18.469 154.401 ;
     RECT  18.421 18.624 18.475 21.664 ;
     RECT  18.469 145.28 18.485 145.312 ;
     RECT  18.229 147.008 18.485 149.344 ;
     RECT  18.475 18.624 18.49 21.472 ;
     RECT  18.49 18.729 18.515 21.472 ;
     RECT  18.485 145.28 18.539 149.344 ;
     RECT  17.459 180.729 18.603 181.536 ;
     RECT  18.371 0.576 18.611 0.608 ;
     RECT  18.469 26.816 18.613 26.848 ;
     RECT  18.419 24.129 18.667 24.992 ;
     RECT  18.613 26.496 18.667 26.848 ;
     RECT  18.539 145.28 18.667 145.952 ;
     RECT  17.589 131.456 18.731 132.801 ;
     RECT  17.557 169.472 18.741 171.808 ;
     RECT  18.741 169.472 18.795 172.768 ;
     RECT  17.219 7.929 18.869 9.44 ;
     RECT  16.875 13.329 18.869 14.001 ;
     RECT  18.469 61.824 18.997 62.601 ;
     RECT  17.027 142.784 18.997 143.601 ;
     RECT  15.083 29.376 19.043 30.201 ;
     RECT  18.677 134.464 19.043 134.496 ;
     RECT  18.469 136.384 19.043 139.616 ;
     RECT  18.539 147.392 19.043 149.344 ;
     RECT  18.469 153.344 19.043 155.296 ;
     RECT  18.795 172.736 19.043 172.768 ;
     RECT  18.181 59.392 19.061 59.424 ;
     RECT  14.867 164.529 19.093 165.201 ;
     RECT  18.283 56.384 19.115 57.201 ;
     RECT  17.259 83.008 19.115 84.201 ;
     RECT  17.077 75.2 19.141 75.232 ;
     RECT  19.141 75.008 19.187 75.232 ;
     RECT  17.077 115.929 19.187 117.024 ;
     RECT  17.205 87.168 19.189 87.2 ;
     RECT  17.259 88.929 19.189 89.601 ;
     RECT  17.701 104.768 19.237 105.801 ;
     RECT  6.763 159.129 19.237 159.801 ;
     RECT  19.189 87.168 19.243 89.601 ;
     RECT  18.469 45.44 19.253 46.752 ;
     RECT  19.093 163.648 19.253 165.201 ;
     RECT  19.253 163.648 19.285 165.792 ;
     RECT  19.237 49.024 19.307 49.056 ;
     RECT  19.237 159.129 19.307 160.032 ;
     RECT  19.285 163.648 19.307 165.92 ;
     RECT  18.869 13.184 19.317 14.001 ;
     RECT  19.307 159.129 19.333 159.968 ;
     RECT  19.317 13.184 19.371 14.816 ;
     RECT  19.285 16.576 19.371 16.608 ;
     RECT  18.795 169.472 19.371 170.601 ;
     RECT  19.243 87.808 19.427 89.601 ;
     RECT  17.171 34.929 19.445 35.601 ;
     RECT  17.605 109.376 19.499 112.16 ;
     RECT  19.043 148.329 19.509 149.344 ;
     RECT  19.043 153.729 19.509 155.296 ;
     RECT  19.509 148.329 19.582 149.792 ;
     RECT  17.605 121.329 19.619 122.528 ;
     RECT  7.147 72.729 19.621 73.401 ;
     RECT  18.997 142.784 19.669 143.712 ;
     RECT  19.621 72.576 19.691 73.401 ;
     RECT  17.278 81.28 19.717 81.312 ;
     RECT  18.741 167.744 19.717 167.776 ;
     RECT  19.717 80.96 19.763 81.312 ;
     RECT  17.173 93.44 19.763 95.001 ;
     RECT  19.717 167.744 19.763 167.904 ;
     RECT  19.445 34.929 19.774 35.872 ;
     RECT  19.509 153.729 19.819 155.424 ;
     RECT  19.763 167.872 19.957 167.904 ;
     RECT  19.333 158.976 19.966 159.968 ;
     RECT  19.371 13.329 20.003 14.816 ;
     RECT  18.667 26.496 20.003 26.528 ;
     RECT  17.259 91.584 20.003 91.616 ;
     RECT  19.499 110.529 20.003 112.16 ;
     RECT  17.605 67.329 20.005 68.192 ;
     RECT  16.883 4.672 20.085 4.704 ;
     RECT  20.085 4.672 20.13 5.92 ;
     RECT  20.13 4.672 20.139 6.24 ;
     RECT  15.539 178.24 20.149 178.272 ;
     RECT  18.603 180.729 20.149 181.401 ;
     RECT  20.139 5.184 20.203 6.24 ;
     RECT  18.869 7.929 20.203 10.4 ;
     RECT  20.149 177.856 20.203 178.272 ;
     RECT  19.582 148.329 20.243 149.344 ;
     RECT  17.259 78.129 20.245 78.801 ;
     RECT  18.131 96.512 20.245 96.544 ;
     RECT  20.203 10.368 20.291 10.4 ;
     RECT  19.893 162.816 20.341 162.848 ;
     RECT  19.307 164.529 20.341 165.92 ;
     RECT  20.341 162.496 20.395 162.848 ;
     RECT  19.957 167.872 20.395 168.48 ;
     RECT  20.203 177.856 20.459 178.208 ;
     RECT  19.763 94.08 20.469 95.001 ;
     RECT  20.245 96.512 20.469 97.76 ;
     RECT  18.027 40.329 20.485 41.12 ;
     RECT  20.485 40.329 20.514 42.208 ;
     RECT  20.469 94.08 20.523 97.76 ;
     RECT  17.077 114.496 20.533 114.528 ;
     RECT  18.515 21.44 20.579 21.472 ;
     RECT  20.341 164.529 20.579 166.432 ;
     RECT  20.514 40.192 20.587 42.208 ;
     RECT  18.997 61.568 20.629 62.601 ;
     RECT  8.235 99.729 20.706 100.401 ;
     RECT  19.115 56.529 20.789 57.201 ;
     RECT  19.061 59.392 20.789 60.064 ;
     RECT  18.469 125.312 20.789 125.344 ;
     RECT  18.731 132.129 20.789 132.801 ;
     RECT  20.706 99.729 20.821 100.512 ;
     RECT  20.789 56.529 20.843 60.256 ;
     RECT  20.789 124.736 20.843 125.344 ;
     RECT  20.245 77.184 20.869 78.801 ;
     RECT  20.523 97.728 20.907 97.76 ;
     RECT  20.821 99.584 20.907 100.512 ;
     RECT  17.643 37.312 20.965 37.344 ;
     RECT  20.629 61.568 20.971 63.904 ;
     RECT  20.843 124.736 20.971 124.768 ;
     RECT  20.965 37.312 21.035 38.048 ;
     RECT  20.907 99.729 21.045 100.512 ;
     RECT  19.253 45.44 21.061 47.264 ;
     RECT  21.013 102.656 21.099 102.688 ;
     RECT  19.819 153.729 21.099 155.296 ;
     RECT  21.013 156.736 21.099 156.768 ;
     RECT  18.181 174.208 21.109 176.001 ;
     RECT  21.061 44.992 21.155 47.264 ;
     RECT  20.789 132.129 21.155 133.984 ;
     RECT  19.043 136.384 21.155 138.201 ;
     RECT  20.869 77.184 21.163 79.648 ;
     RECT  19.763 80.96 21.163 80.992 ;
     RECT  21.109 173.824 21.163 176.001 ;
     RECT  20.459 178.176 21.163 178.208 ;
     RECT  20.533 113.216 21.201 114.528 ;
     RECT  20.523 94.08 21.203 96.096 ;
     RECT  21.163 173.824 21.203 173.856 ;
     RECT  17.909 65.664 21.237 65.696 ;
     RECT  20.005 67.329 21.237 68.32 ;
     RECT  20.971 61.929 21.291 63.904 ;
     RECT  19.187 75.008 21.347 75.04 ;
     RECT  21.237 65.664 21.355 68.32 ;
     RECT  19.237 104.32 21.397 105.801 ;
     RECT  21.397 104.32 21.483 106.656 ;
     RECT  21.397 119.872 21.483 119.904 ;
     RECT  21.099 153.729 21.539 154.976 ;
     RECT  19.371 169.929 21.589 170.601 ;
     RECT  21.163 77.184 21.635 78.801 ;
     RECT  19.115 83.328 21.635 84.201 ;
     RECT  19.669 141.76 21.666 143.712 ;
     RECT  21.589 169.929 21.675 170.72 ;
     RECT  21.045 99.729 21.683 100.896 ;
     RECT  20.395 162.496 21.683 162.528 ;
     RECT  21.666 141.76 21.739 144.48 ;
     RECT  20.395 168.448 21.779 168.48 ;
     RECT  17.123 51.129 21.813 51.801 ;
     RECT  21.813 49.728 21.886 49.76 ;
     RECT  21.739 141.76 21.925 143.904 ;
     RECT  19.187 115.929 21.941 116.896 ;
     RECT  17.643 128.832 21.995 128.864 ;
     RECT  21.925 141.184 21.995 143.904 ;
     RECT  21.291 61.929 22.067 63.264 ;
     RECT  21.941 115.929 22.091 118.112 ;
     RECT  20.843 60.032 22.117 60.256 ;
     RECT  19.619 121.329 22.117 122.144 ;
     RECT  21.155 137.529 22.133 138.201 ;
     RECT  19.043 139.584 22.133 139.616 ;
     RECT  18.515 18.729 22.165 19.401 ;
     RECT  19.429 31.872 22.165 31.904 ;
     RECT  19.427 88.929 22.165 89.601 ;
     RECT  22.117 121.329 22.187 123.296 ;
     RECT  22.133 137.529 22.259 139.616 ;
     RECT  22.165 31.68 22.315 31.904 ;
     RECT  20.003 13.329 22.453 14.001 ;
     RECT  21.635 83.529 22.453 84.201 ;
     RECT  22.091 115.648 22.501 118.112 ;
     RECT  22.021 81.472 22.507 81.504 ;
     RECT  21.203 94.08 22.549 95.001 ;
     RECT  21.813 51.129 22.571 52.64 ;
     RECT  22.501 115.648 22.571 119.2 ;
     RECT  22.165 88.929 22.581 90.656 ;
     RECT  22.549 93.12 22.635 95.001 ;
     RECT  22.581 88.929 22.645 91.104 ;
     RECT  22.165 18.729 22.693 19.552 ;
     RECT  22.645 88.512 22.693 91.104 ;
     RECT  21.155 44.992 22.699 46.401 ;
     RECT  22.517 55.104 22.709 55.136 ;
     RECT  20.843 56.529 22.709 58.144 ;
     RECT  22.645 43.2 22.739 43.232 ;
     RECT  21.635 78.129 22.741 78.801 ;
     RECT  21.483 104.32 22.741 105.801 ;
     RECT  22.453 12.48 22.763 14.001 ;
     RECT  22.165 15.36 22.763 15.392 ;
     RECT  22.693 17.472 22.763 19.552 ;
     RECT  22.709 55.104 22.763 58.144 ;
     RECT  22.693 88.384 22.763 91.104 ;
     RECT  22.741 70.976 22.773 71.008 ;
     RECT  22.709 10.56 22.787 10.592 ;
     RECT  18.667 145.92 22.787 145.952 ;
     RECT  20.587 40.192 22.835 41.12 ;
     RECT  22.763 55.744 22.835 58.144 ;
     RECT  21.355 67.329 22.837 68.001 ;
     RECT  22.773 70.592 22.901 71.008 ;
     RECT  19.691 72.729 22.901 73.401 ;
     RECT  22.901 70.592 22.955 73.401 ;
     RECT  21.995 142.784 23.171 143.904 ;
     RECT  21.683 99.729 23.285 100.401 ;
     RECT  22.699 45.44 23.317 46.401 ;
     RECT  23.285 107.2 23.317 107.232 ;
     RECT  20.003 110.529 23.319 111.201 ;
     RECT  23.269 102.08 23.339 102.112 ;
     RECT  22.741 104.192 23.339 105.801 ;
     RECT  19.966 158.976 23.342 159.801 ;
     RECT  23.317 107.2 23.363 107.488 ;
     RECT  23.363 107.456 23.403 107.488 ;
     RECT  22.117 60.032 23.411 60.32 ;
     RECT  23.342 158.976 23.411 159.968 ;
     RECT  20.579 164.529 23.461 165.408 ;
     RECT  22.741 157.44 23.477 157.472 ;
     RECT  23.411 158.976 23.477 159.801 ;
     RECT  21.201 113.216 23.605 113.248 ;
     RECT  23.349 136.192 23.747 136.224 ;
     RECT  21.355 65.664 23.845 65.696 ;
     RECT  22.837 67.329 23.845 68.832 ;
     RECT  21.539 153.729 23.893 154.401 ;
     RECT  21.675 169.929 23.893 170.601 ;
     RECT  23.461 164.529 24.107 165.856 ;
     RECT  22.571 51.129 24.117 51.801 ;
     RECT  22.955 72.064 24.117 73.401 ;
     RECT  24.117 72.064 24.171 74.656 ;
     RECT  22.571 115.648 24.354 118.112 ;
     RECT  23.317 45.44 24.363 47.264 ;
     RECT  24.117 49.984 24.419 52.576 ;
     RECT  24.171 72.729 24.419 74.656 ;
     RECT  24.117 75.968 24.419 76 ;
     RECT  22.741 78.129 24.419 79.52 ;
     RECT  23.477 157.44 24.419 159.801 ;
     RECT  24.053 167.616 24.419 167.648 ;
     RECT  24.354 114.752 24.427 118.112 ;
     RECT  23.319 110.4 24.437 111.201 ;
     RECT  24.437 110.4 24.491 111.328 ;
     RECT  24.501 173.632 24.517 173.664 ;
     RECT  23.893 169.929 24.555 170.976 ;
     RECT  22.835 55.744 24.563 58.08 ;
     RECT  22.763 88.929 24.563 91.104 ;
     RECT  23.285 99.136 24.563 100.401 ;
     RECT  20.149 179.584 24.565 181.401 ;
     RECT  24.517 173.632 24.574 173.856 ;
     RECT  24.053 162.752 24.611 162.784 ;
     RECT  24.574 173.824 24.619 173.856 ;
     RECT  24.613 64.256 24.683 64.288 ;
     RECT  20.243 148.329 24.757 149.28 ;
     RECT  22.741 151.808 24.811 152.096 ;
     RECT  24.757 148.329 24.826 149.92 ;
     RECT  23.339 104.832 25.043 105.801 ;
     RECT  24.419 159.129 25.045 159.801 ;
     RECT  24.563 56.529 25.139 58.08 ;
     RECT  22.453 83.529 25.139 84.896 ;
     RECT  23.605 112.896 25.139 113.248 ;
     RECT  24.565 178.432 25.139 181.401 ;
     RECT  23.845 65.664 25.331 68.832 ;
     RECT  25.331 65.664 25.342 68.001 ;
     RECT  24.427 115.929 25.525 118.112 ;
     RECT  22.187 121.329 25.589 122.144 ;
     RECT  24.491 110.529 25.619 111.328 ;
     RECT  25.525 115.929 25.643 119.328 ;
     RECT  20.203 5.184 25.715 5.216 ;
     RECT  23.893 80.96 25.909 80.992 ;
     RECT  23.893 153.6 25.909 154.401 ;
     RECT  25.909 80.96 25.978 81.504 ;
     RECT  24.419 157.44 26.005 157.472 ;
     RECT  25.045 159.129 26.005 160.16 ;
     RECT  23.411 60.032 26.027 60.064 ;
     RECT  25.957 69.952 26.027 69.984 ;
     RECT  25.978 80.96 26.027 80.992 ;
     RECT  24.419 51.129 26.091 52.576 ;
     RECT  26.005 157.44 26.091 160.16 ;
     RECT  25.909 153.6 26.147 155.36 ;
     RECT  26.03 54.72 26.197 54.752 ;
     RECT  24.563 99.729 26.229 100.401 ;
     RECT  26.091 157.44 26.723 157.472 ;
     RECT  26.229 99.584 26.725 100.401 ;
     RECT  24.949 96.832 26.795 96.864 ;
     RECT  26.725 99.584 26.795 101.536 ;
     RECT  26.091 158.784 26.795 160.16 ;
     RECT  25.643 115.929 27.059 118.112 ;
     RECT  22.315 31.68 27.115 31.712 ;
     RECT  25.139 83.529 27.189 84.832 ;
     RECT  25.342 67.329 27.205 68.001 ;
     RECT  26.197 54.72 27.253 54.816 ;
     RECT  24.363 45.44 27.307 46.401 ;
     RECT  27.253 54.144 27.322 54.816 ;
     RECT  26.795 99.584 27.395 100.401 ;
     RECT  26.741 161.984 27.395 162.016 ;
     RECT  22.067 61.929 27.426 62.601 ;
     RECT  27.426 61.824 27.445 62.601 ;
     RECT  25.342 65.664 27.445 65.696 ;
     RECT  26.629 60.352 27.499 60.384 ;
     RECT  27.445 61.824 27.514 62.752 ;
     RECT  27.445 65.6 27.637 65.696 ;
     RECT  27.205 67.329 27.637 68.32 ;
     RECT  27.637 65.6 27.691 68.32 ;
     RECT  27.691 65.6 27.779 68.001 ;
     RECT  25.589 121.329 27.971 122.464 ;
     RECT  26.147 153.729 27.971 155.36 ;
     RECT  25.139 179.584 28.194 181.401 ;
     RECT  18.035 2.529 28.213 3.201 ;
     RECT  28.213 1.728 28.307 3.201 ;
     RECT  27.514 61.824 28.725 62.601 ;
     RECT  27.322 54.784 28.798 54.816 ;
     RECT  28.194 179.584 28.837 181.536 ;
     RECT  28.526 1.152 28.853 1.184 ;
     RECT  28.837 179.584 28.907 181.792 ;
     RECT  27.779 65.664 29.027 68.001 ;
     RECT  27.189 83.529 29.315 85.216 ;
     RECT  28.907 179.584 29.555 181.664 ;
     RECT  27.061 38.784 29.797 38.816 ;
     RECT  29.797 38.784 29.813 39.008 ;
     RECT  29.813 38.144 29.867 39.008 ;
     RECT  22.835 40.329 29.867 41.12 ;
     RECT  29.867 38.144 29.939 38.816 ;
     RECT  28.725 61.312 30.133 62.601 ;
     RECT  30.133 61.312 30.187 63.328 ;
     RECT  26.037 146.688 30.197 146.72 ;
     RECT  23.171 142.784 30.251 143.601 ;
     RECT  28.853 0.064 30.254 1.184 ;
     RECT  28.307 2.529 30.254 3.201 ;
     RECT  30.187 61.929 30.275 63.328 ;
     RECT  27.061 87.36 30.275 87.392 ;
     RECT  30.197 145.856 30.803 146.72 ;
     RECT  29.555 179.584 30.901 181.536 ;
     RECT  30.901 179.584 30.97 181.792 ;
     RECT  30.254 0.064 30.995 3.201 ;
     RECT  30.995 0.064 32.309 0.096 ;
     RECT  30.97 179.584 32.629 181.536 ;
     RECT  27.061 4.8 32.821 4.832 ;
     RECT  32.821 4.672 32.875 4.832 ;
     RECT  32.629 179.584 33.011 181.792 ;
     RECT  32.309 0.064 33.205 0.224 ;
     RECT  30.995 1.728 33.205 3.201 ;
     RECT  33.205 0.064 33.683 3.201 ;
     RECT  27.059 118.08 33.731 118.112 ;
     RECT  24.563 88.929 33.781 90.784 ;
     RECT  29.027 65.664 33.877 65.696 ;
     RECT  33.829 118.016 33.899 118.048 ;
     RECT  33.877 65.664 33.963 65.888 ;
     RECT  33.683 0.512 33.973 3.201 ;
     RECT  32.875 4.672 33.973 4.704 ;
     RECT  33.845 114.56 34.027 114.592 ;
     RECT  33.781 88.929 34.219 92 ;
     RECT  33.963 65.664 34.259 65.696 ;
     RECT  33.011 179.584 34.357 181.536 ;
     RECT  33.973 0.512 35.219 4.704 ;
     RECT  35.219 0.512 35.829 3.201 ;
     RECT  35.829 0.064 37.091 3.201 ;
     RECT  36.421 183.488 37.099 183.52 ;
     RECT  37.091 1.152 37.139 3.201 ;
     RECT  34.357 179.584 37.355 181.792 ;
     RECT  37.139 1.728 37.379 3.201 ;
     RECT  37.355 179.584 38.819 181.401 ;
     RECT  35.219 4.672 39.923 4.704 ;
     RECT  21.163 175.329 41.973 176.001 ;
     RECT  22.259 137.529 42.027 138.784 ;
     RECT  41.973 174.08 42.046 176.001 ;
     RECT  41.973 179.264 42.467 179.296 ;
     RECT  22.763 18.729 42.805 19.401 ;
     RECT  34.219 88.929 42.805 91.872 ;
     RECT  42.805 88.929 42.874 92.064 ;
     RECT  42.874 88.929 43.091 91.872 ;
     RECT  29.939 38.144 46.211 38.176 ;
     RECT  44.965 5.12 46.773 5.152 ;
     RECT  30.803 145.856 46.787 145.888 ;
     RECT  46.773 4.544 46.827 5.152 ;
     RECT  42.133 173.952 46.965 173.984 ;
     RECT  42.046 175.329 46.965 176.001 ;
     RECT  38.819 180.729 46.965 181.401 ;
     RECT  46.773 38.016 47.075 38.048 ;
     RECT  46.965 173.888 47.211 176.001 ;
     RECT  47.211 173.888 47.275 173.92 ;
     RECT  46.958 0.576 47.285 0.608 ;
     RECT  47.221 146.432 47.29 146.464 ;
     RECT  47.285 0.064 47.534 0.608 ;
     RECT  47.534 0.064 49.013 1.184 ;
     RECT  37.379 2.529 49.013 3.201 ;
     RECT  46.827 4.544 49.285 4.576 ;
     RECT  49.285 4.544 49.331 4.96 ;
     RECT  49.013 0.064 49.667 3.201 ;
     RECT  46.965 179.776 49.667 181.536 ;
     RECT  49.667 179.904 49.909 181.536 ;
     RECT  49.909 179.904 50.291 181.792 ;
     RECT  50.291 179.904 51.155 181.664 ;
     RECT  49.667 0.064 51.95 0.096 ;
     RECT  49.667 1.728 51.95 3.201 ;
     RECT  51.95 0.064 52.595 3.201 ;
     RECT  52.595 0.064 54.005 1.184 ;
     RECT  52.595 2.529 54.005 3.201 ;
     RECT  51.155 179.904 54.005 181.536 ;
     RECT  54.005 179.904 54.083 181.792 ;
     RECT  54.005 0.064 55.235 3.201 ;
     RECT  55.235 0.064 55.907 0.608 ;
     RECT  55.907 0.192 56.051 0.608 ;
     RECT  56.051 0.576 56.147 0.608 ;
     RECT  54.083 179.904 56.147 181.536 ;
     RECT  56.147 179.904 56.811 181.401 ;
     RECT  55.235 2.529 59.797 3.201 ;
     RECT  59.797 2.368 59.829 3.201 ;
     RECT  59.829 2.368 59.883 3.552 ;
     RECT  59.883 2.529 59.902 3.552 ;
     RECT  59.902 2.529 62.485 3.201 ;
     RECT  49.331 4.928 62.645 4.96 ;
     RECT  62.485 2.529 62.699 3.36 ;
     RECT  62.645 4.928 62.699 5.216 ;
     RECT  56.811 180.608 65.701 181.401 ;
     RECT  65.717 0.576 65.795 0.608 ;
     RECT  62.699 2.529 66.037 3.201 ;
     RECT  66.037 2.529 66.131 3.488 ;
     RECT  66.293 1.152 66.371 1.184 ;
     RECT  66.131 2.529 66.613 3.201 ;
     RECT  66.613 1.728 66.947 3.201 ;
     RECT  62.699 5.184 67.093 5.216 ;
     RECT  65.701 180.608 67.502 181.536 ;
     RECT  67.502 180.608 67.571 181.792 ;
     RECT  67.509 0.064 67.765 0.096 ;
     RECT  67.765 0.064 67.859 0.608 ;
     RECT  67.093 4.544 68.41 5.216 ;
     RECT  67.859 0.576 68.654 0.608 ;
     RECT  68.654 0.576 69.23 1.184 ;
     RECT  66.947 2.529 69.23 3.201 ;
     RECT  69.23 0.576 69.299 3.201 ;
     RECT  67.571 180.608 69.557 181.536 ;
     RECT  69.557 180.608 69.635 181.792 ;
     RECT  69.299 0.576 69.813 1.184 ;
     RECT  69.635 180.608 69.973 181.536 ;
     RECT  69.973 179.584 70.059 181.536 ;
     RECT  69.813 0.064 71.285 1.184 ;
     RECT  69.299 2.529 71.285 3.201 ;
     RECT  24.826 148.329 71.989 149.728 ;
     RECT  71.285 0.064 72.085 3.201 ;
     RECT  68.41 5.184 72.085 5.216 ;
     RECT  21.155 132.129 72.117 132.801 ;
     RECT  71.989 134.464 72.117 134.496 ;
     RECT  70.059 180.729 72.181 181.536 ;
     RECT  72.181 180.729 72.25 181.792 ;
     RECT  72.085 0.064 72.419 5.216 ;
     RECT  71.989 148.329 72.419 149.984 ;
     RECT  24.811 152.064 72.469 152.096 ;
     RECT  72.419 148.329 72.555 149.728 ;
     RECT  72.469 152.064 72.555 152.224 ;
     RECT  72.25 180.729 72.811 181.6 ;
     RECT  27.971 153.729 73.269 155.296 ;
     RECT  72.117 132.129 73.323 134.496 ;
     RECT  72.555 152.064 73.323 152.096 ;
     RECT  73.323 132.129 73.571 134.112 ;
     RECT  73.269 153.6 73.571 155.296 ;
     RECT  72.419 0.576 74.003 5.216 ;
     RECT  72.811 180.729 74.222 181.536 ;
     RECT  74.222 180.729 74.291 181.792 ;
     RECT  74.003 1.728 74.867 5.216 ;
     RECT  73.571 132.129 74.869 133.984 ;
     RECT  74.291 180.729 74.878 181.536 ;
     RECT  73.571 153.729 74.923 155.296 ;
     RECT  74.869 132.129 74.963 134.496 ;
     RECT  74.869 156.736 74.963 156.768 ;
     RECT  74.867 2.368 75.243 5.216 ;
     RECT  75.243 2.368 75.251 3.616 ;
     RECT  75.243 5.184 75.637 5.216 ;
     RECT  75.637 5.184 75.819 6.24 ;
     RECT  74.963 132.129 75.875 133.984 ;
     RECT  24.107 164.529 80.117 165.201 ;
     RECT  80.101 135.04 80.171 135.072 ;
     RECT  80.117 164.416 80.245 165.201 ;
     RECT  75.251 2.529 80.293 3.616 ;
     RECT  80.245 134.976 80.309 135.008 ;
     RECT  75.875 132.129 80.437 132.801 ;
     RECT  80.309 134.528 80.437 135.008 ;
     RECT  80.293 2.529 80.555 4.576 ;
     RECT  80.245 164.16 80.677 165.201 ;
     RECT  70.005 178.24 81.155 178.272 ;
     RECT  80.677 163.584 81.205 165.201 ;
     RECT  81.205 163.008 81.269 165.201 ;
     RECT  81.269 163.008 81.274 165.344 ;
     RECT  81.274 164.16 81.347 165.344 ;
     RECT  80.437 132.129 81.835 135.008 ;
     RECT  81.347 164.16 81.875 165.201 ;
     RECT  80.555 2.529 81.899 4.32 ;
     RECT  43.091 88.929 82.115 90.784 ;
     RECT  81.835 132.129 82.115 134.56 ;
     RECT  82.115 132.129 82.411 134.496 ;
     RECT  82.357 167.616 82.426 167.648 ;
     RECT  81.899 2.529 82.667 3.936 ;
     RECT  82.411 132.129 82.691 133.984 ;
     RECT  74.878 180.729 83.893 181.401 ;
     RECT  82.667 2.529 84.24 3.201 ;
     RECT  20.203 7.929 84.24 8.601 ;
     RECT  22.763 13.329 84.24 14.001 ;
     RECT  42.805 18.368 84.24 19.401 ;
     RECT  18.667 24.129 84.24 24.801 ;
     RECT  19.043 29.529 84.24 30.201 ;
     RECT  19.774 34.929 84.24 35.601 ;
     RECT  29.867 40.329 84.24 41.001 ;
     RECT  27.307 45.729 84.24 46.401 ;
     RECT  26.091 51.129 84.24 51.801 ;
     RECT  25.139 56.529 84.24 57.201 ;
     RECT  30.275 61.929 84.24 62.601 ;
     RECT  29.027 67.329 84.24 68.001 ;
     RECT  24.419 72.729 84.24 73.401 ;
     RECT  24.419 78.129 84.24 78.801 ;
     RECT  29.315 83.529 84.24 84.201 ;
     RECT  82.115 88.929 84.24 89.601 ;
     RECT  22.635 94.329 84.24 95.001 ;
     RECT  27.395 99.729 84.24 100.401 ;
     RECT  25.043 105.129 84.24 105.801 ;
     RECT  25.619 110.529 84.24 111.201 ;
     RECT  27.059 115.929 84.24 116.601 ;
     RECT  27.971 121.329 84.24 122.001 ;
     RECT  17.643 126.729 84.24 127.401 ;
     RECT  82.691 132.129 84.24 132.801 ;
     RECT  42.027 137.529 84.24 138.201 ;
     RECT  30.251 142.929 84.24 143.601 ;
     RECT  72.555 148.329 84.24 149.001 ;
     RECT  74.923 153.729 84.24 154.401 ;
     RECT  26.795 159.129 84.24 159.801 ;
     RECT  81.875 164.529 84.24 165.201 ;
     RECT  24.555 169.929 84.24 170.601 ;
     RECT  47.211 175.329 84.24 176.001 ;
     RECT  83.893 180.729 84.24 181.536 ;
     RECT  84.24 181.248 84.469 181.536 ;
     RECT  84.469 181.248 84.517 181.792 ;
     RECT  84.421 183.488 84.517 183.52 ;
     RECT  84.24 2.88 84.538 2.912 ;
     RECT  84.517 181.248 84.538 183.52 ;
     RECT  84.325 0.704 84.757 0.736 ;
     RECT  84.538 181.248 84.843 181.536 ;
     RECT  84.757 0.576 85.099 0.736 ;
     RECT  84.538 182.912 85.419 183.52 ;
     RECT  85.419 182.976 85.675 183.52 ;
     RECT  85.675 182.976 85.995 183.008 ;
     RECT  84.24 18.368 86.243 18.4 ;
     RECT  84.843 181.248 86.251 181.28 ;
     RECT  85.333 0.064 86.266 0.096 ;
    LAYER M7 ;
     RECT  84.48 0.035 86.24 0.107 ;
     RECT  9.472 0.035 18.592 0.619 ;
     RECT  46.976 0.035 56.096 0.619 ;
     RECT  65.728 0.035 74.848 0.619 ;
     RECT  84.48 0.107 85.088 0.747 ;
     RECT  9.472 0.619 18.336 1.195 ;
     RECT  28.224 0.035 37.344 1.195 ;
     RECT  47.552 0.619 55.2 1.195 ;
     RECT  66.048 0.619 74.848 1.195 ;
     RECT  9.472 1.195 13.664 1.771 ;
     RECT  15.36 1.195 18.016 1.771 ;
     RECT  28.224 1.195 28.256 1.771 ;
     RECT  30.272 1.195 37.344 1.771 ;
     RECT  49.024 1.195 52.576 1.771 ;
     RECT  54.016 1.195 55.2 1.771 ;
     RECT  66.048 1.195 69.28 1.771 ;
     RECT  71.296 1.195 74.848 1.771 ;
     RECT  16.832 1.771 18.016 2.347 ;
     RECT  50.816 1.771 50.848 2.347 ;
     RECT  73.088 1.771 74.848 2.357 ;
     RECT  84.48 0.747 84.512 2.923 ;
     RECT  10.112 1.771 13.664 3.499 ;
     RECT  16.832 2.347 16.864 3.499 ;
     RECT  66.048 1.771 68.384 3.499 ;
     RECT  59.84 2.357 59.872 3.563 ;
     RECT  73.088 2.357 75.232 3.573 ;
     RECT  73.088 3.573 75.808 3.893 ;
     RECT  80.896 3.317 80.928 3.893 ;
     RECT  80.448 3.893 82.656 4.533 ;
     RECT  67.2 3.499 68.384 4.587 ;
     RECT  72.128 3.893 75.808 4.587 ;
     RECT  33.024 1.771 33.056 4.661 ;
     RECT  32.832 4.661 33.056 4.715 ;
     RECT  32.832 4.715 32.864 4.843 ;
     RECT  12.48 3.499 12.832 4.917 ;
     RECT  62.656 3.317 62.688 5.227 ;
     RECT  20.096 4.661 20.128 5.931 ;
     RECT  75.008 4.587 75.808 6.251 ;
     RECT  7.04 6.773 7.072 7.851 ;
     RECT  20.16 6.197 20.192 9.397 ;
     RECT  18.88 9.397 20.192 9.451 ;
     RECT  4.48 5.621 4.512 9.717 ;
     RECT  12.16 4.917 12.832 9.717 ;
     RECT  4.224 9.717 4.512 9.771 ;
     RECT  16.768 5.621 16.8 9.781 ;
     RECT  16.768 9.781 16.864 9.782 ;
     RECT  4.224 9.771 4.256 12.203 ;
     RECT  16.832 9.782 16.864 12.587 ;
     RECT  12.16 9.717 12.96 13.099 ;
     RECT  18.88 9.451 18.912 13.173 ;
     RECT  18.88 13.173 19.36 13.227 ;
     RECT  19.328 13.227 19.36 16.619 ;
     RECT  12.16 13.099 12.704 17.131 ;
     RECT  16 16.501 16.032 17.781 ;
     RECT  16 17.781 16.288 17.835 ;
     RECT  22.72 10.549 22.752 19.509 ;
     RECT  22.272 19.509 22.752 19.563 ;
     RECT  16.256 17.835 16.288 20.405 ;
     RECT  16.256 20.405 16.544 20.459 ;
     RECT  12.16 17.131 12.64 20.469 ;
     RECT  11.392 20.469 12.64 20.523 ;
     RECT  11.392 20.523 11.424 21.163 ;
     RECT  18.432 18.613 18.464 21.493 ;
     RECT  18.24 21.493 18.464 21.675 ;
     RECT  16.512 20.459 16.544 21.995 ;
     RECT  9.088 14.197 9.12 23.221 ;
     RECT  8.704 23.221 9.12 23.275 ;
     RECT  18.368 21.675 18.4 23.403 ;
     RECT  12.224 25.013 12.256 26.165 ;
     RECT  8.704 23.275 8.736 26.475 ;
     RECT  11.2 26.165 12.256 26.741 ;
     RECT  4.032 26.613 4.064 26.795 ;
     RECT  14.912 25.589 14.944 27.829 ;
     RECT  14.912 27.829 15.072 27.883 ;
     RECT  15.04 27.883 15.072 29.419 ;
     RECT  18.624 24.949 18.656 29.419 ;
     RECT  6.848 26.997 6.88 30.763 ;
     RECT  11.2 26.741 12.384 31.211 ;
     RECT  22.272 19.563 22.304 31.915 ;
     RECT  11.392 31.211 12.384 33.579 ;
     RECT  12.352 33.579 12.384 33.973 ;
     RECT  17.088 29.365 17.12 34.283 ;
     RECT  3.264 31.541 3.296 34.805 ;
     RECT  3.264 34.805 3.424 34.859 ;
     RECT  19.456 31.861 19.488 35.829 ;
     RECT  19.456 35.829 19.744 35.883 ;
     RECT  3.392 34.859 3.424 35.947 ;
     RECT  12.352 33.973 13.088 36.469 ;
     RECT  12.224 36.469 13.088 37.099 ;
     RECT  19.712 35.883 19.744 37.301 ;
     RECT  19.712 37.301 21.024 37.355 ;
     RECT  46.784 4.533 46.816 38.059 ;
     RECT  12.224 37.099 12.256 39.093 ;
     RECT  20.992 37.355 21.024 40.181 ;
     RECT  20.544 40.181 21.024 40.235 ;
     RECT  17.6 37.557 17.632 41.077 ;
     RECT  29.824 38.133 29.856 41.131 ;
     RECT  12.224 39.093 12.96 41.195 ;
     RECT  12.928 41.195 12.96 41.963 ;
     RECT  17.6 41.077 18.016 42.037 ;
     RECT  20.544 40.235 20.576 42.219 ;
     RECT  4.48 41.269 4.512 44.523 ;
     RECT  17.344 42.037 18.016 44.981 ;
     RECT  16.576 44.981 18.016 45.035 ;
     RECT  22.656 43.189 22.688 45.035 ;
     RECT  8.192 42.741 8.224 45.355 ;
     RECT  27.072 4.789 27.104 45.429 ;
     RECT  27.072 45.429 27.296 45.483 ;
     RECT  17.984 45.035 18.016 46.709 ;
     RECT  16.576 45.035 16.608 47.339 ;
     RECT  17.984 46.709 19.296 48.373 ;
     RECT  16.704 48.373 19.296 49.067 ;
     RECT  24.32 47.221 24.352 49.973 ;
     RECT  24.128 49.973 24.352 50.027 ;
     RECT  16.704 49.067 18.016 50.155 ;
     RECT  4.48 46.645 4.512 51.051 ;
     RECT  17.024 50.155 18.016 51.051 ;
     RECT  27.264 45.483 27.296 52.341 ;
     RECT  6.784 50.997 6.816 52.523 ;
     RECT  24.128 50.027 24.16 52.587 ;
     RECT  21.824 49.717 21.856 52.597 ;
     RECT  21.824 52.597 22.56 52.651 ;
     RECT  26.048 52.341 27.296 54.187 ;
     RECT  5.248 52.981 5.28 54.645 ;
     RECT  26.048 54.187 26.08 54.763 ;
     RECT  22.528 52.651 22.56 55.093 ;
     RECT  22.528 55.093 22.752 55.147 ;
     RECT  17.984 51.051 18.016 56.362 ;
     RECT  5.248 54.645 5.984 56.363 ;
     RECT  17.92 56.362 18.016 56.373 ;
     RECT  5.376 56.363 5.984 57.323 ;
     RECT  22.72 55.147 22.752 58.155 ;
     RECT  5.376 57.323 5.728 59.307 ;
     RECT  17.92 56.373 19.104 60.075 ;
     RECT  20.8 58.101 20.832 60.267 ;
     RECT  28.736 54.773 28.768 60.341 ;
     RECT  27.456 60.341 28.768 61.355 ;
     RECT  6.848 60.341 6.88 61.675 ;
     RECT  5.376 59.307 5.408 61.813 ;
     RECT  30.144 61.301 30.176 63.339 ;
     RECT  20.928 61.557 20.96 63.861 ;
     RECT  20.928 63.861 21.28 63.915 ;
     RECT  5.376 61.813 5.792 64.309 ;
     RECT  27.456 61.355 27.488 65.589 ;
     RECT  27.456 65.589 27.68 65.643 ;
     RECT  17.92 60.075 17.952 65.707 ;
     RECT  21.248 63.915 21.28 66.219 ;
     RECT  24.64 64.245 24.672 66.357 ;
     RECT  25.984 60.021 26.016 66.357 ;
     RECT  24.64 66.357 26.016 66.411 ;
     RECT  5.248 64.309 5.792 66.421 ;
     RECT  25.024 66.411 26.016 66.731 ;
     RECT  21.312 66.613 21.344 68.331 ;
     RECT  27.648 65.643 27.68 68.331 ;
     RECT  25.28 66.731 26.016 68.843 ;
     RECT  5.248 66.421 5.984 68.907 ;
     RECT  22.912 68.789 22.944 70.581 ;
     RECT  22.784 70.581 22.944 70.763 ;
     RECT  22.912 70.763 22.944 72.053 ;
     RECT  22.912 72.053 24.16 72.107 ;
     RECT  7.104 70.645 7.136 72.363 ;
     RECT  19.648 72.565 19.68 75.051 ;
     RECT  24.128 72.107 24.16 76.011 ;
     RECT  7.104 74.997 7.136 81.003 ;
     RECT  21.12 74.997 21.152 81.003 ;
     RECT  25.984 68.843 26.016 81.003 ;
     RECT  5.248 68.907 5.28 82.677 ;
     RECT  17.216 78.901 17.248 83.051 ;
     RECT  6.784 82.357 6.816 84.331 ;
     RECT  25.92 81.461 25.952 84.789 ;
     RECT  22.464 81.461 22.496 84.853 ;
     RECT  22.464 84.853 22.752 84.907 ;
     RECT  4.544 82.677 5.28 86.379 ;
     RECT  5.248 86.379 5.28 86.699 ;
     RECT  19.072 82.997 19.104 87.157 ;
     RECT  19.072 87.157 19.232 87.211 ;
     RECT  25.92 84.789 27.232 87.403 ;
     RECT  19.2 87.211 19.232 87.851 ;
     RECT  22.72 84.907 22.752 88.427 ;
     RECT  25.92 87.403 27.104 89.771 ;
     RECT  26.496 89.771 27.104 90.155 ;
     RECT  22.656 88.501 22.688 90.667 ;
     RECT  26.496 90.155 26.784 90.795 ;
     RECT  5.376 86.965 5.408 91.243 ;
     RECT  17.216 87.157 17.248 91.627 ;
     RECT  33.92 65.845 33.952 91.765 ;
     RECT  33.792 91.765 33.952 91.829 ;
     RECT  33.792 91.829 34.208 92.011 ;
     RECT  42.816 18.357 42.848 92.075 ;
     RECT  5.632 92.853 5.664 93.547 ;
     RECT  4.224 93.429 4.256 95.093 ;
     RECT  4.032 95.093 4.256 95.147 ;
     RECT  14.784 92.021 14.816 95.211 ;
     RECT  7.04 95.157 7.072 96.171 ;
     RECT  4.032 95.147 4.064 96.299 ;
     RECT  26.752 90.795 26.784 96.821 ;
     RECT  26.24 96.821 26.784 96.875 ;
     RECT  20.48 94.069 20.512 97.717 ;
     RECT  20.48 97.717 20.896 97.771 ;
     RECT  22.592 91.061 22.624 99.125 ;
     RECT  8 97.909 8.032 99.573 ;
     RECT  26.24 96.875 26.272 99.573 ;
     RECT  8 99.573 8.224 99.627 ;
     RECT  26.24 99.573 26.784 99.627 ;
     RECT  20.864 97.771 20.896 100.469 ;
     RECT  20.736 100.469 20.896 100.853 ;
     RECT  26.752 99.627 26.784 101.547 ;
     RECT  8.192 99.627 8.224 104.299 ;
     RECT  20.736 100.853 21.088 104.309 ;
     RECT  22.592 99.125 23.328 104.309 ;
     RECT  5.952 96.629 5.984 106.357 ;
     RECT  5.696 106.357 7.136 106.539 ;
     RECT  20.736 104.309 23.328 106.667 ;
     RECT  22.592 106.667 23.328 107.445 ;
     RECT  5.888 106.539 7.136 109.355 ;
     RECT  20.736 106.667 20.768 109.365 ;
     RECT  16.512 107.125 16.544 109.419 ;
     RECT  5.888 109.355 7.072 109.941 ;
     RECT  22.592 107.445 23.392 110.389 ;
     RECT  22.592 110.389 24.48 110.443 ;
     RECT  24.448 110.443 24.48 111.339 ;
     RECT  19.456 109.365 20.768 112.171 ;
     RECT  5.248 109.941 7.072 113.195 ;
     RECT  5.888 113.195 7.072 113.973 ;
     RECT  20.544 112.171 20.768 114.485 ;
     RECT  33.984 92.011 34.016 114.549 ;
     RECT  33.856 114.549 34.016 114.603 ;
     RECT  20.544 114.485 21.152 115.637 ;
     RECT  22.592 110.443 22.624 115.637 ;
     RECT  5.888 113.973 7.136 115.691 ;
     RECT  20.544 115.637 22.624 115.691 ;
     RECT  5.888 115.691 5.92 116.779 ;
     RECT  20.544 115.691 22.176 116.779 ;
     RECT  24.384 112.885 24.416 116.779 ;
     RECT  21.44 116.779 22.176 117.109 ;
     RECT  33.856 114.603 33.888 118.059 ;
     RECT  3.712 115.061 3.744 119.211 ;
     RECT  21.44 117.109 22.56 119.211 ;
     RECT  25.536 117.109 25.568 119.211 ;
     RECT  21.44 119.211 22.176 122.101 ;
     RECT  25.6 119.285 25.632 122.475 ;
     RECT  7.104 119.541 7.136 124.331 ;
     RECT  20.928 122.101 22.176 124.725 ;
     RECT  11.392 116.725 11.424 125.109 ;
     RECT  4.224 122.101 4.256 125.355 ;
     RECT  5.76 124.853 5.792 127.989 ;
     RECT  4.48 127.989 5.792 128.043 ;
     RECT  11.392 125.109 11.936 128.619 ;
     RECT  11.584 128.619 11.936 129.195 ;
     RECT  11.584 129.195 11.744 130.101 ;
     RECT  7.68 128.629 7.712 130.229 ;
     RECT  7.104 130.229 7.712 130.283 ;
     RECT  11.328 130.101 11.744 130.603 ;
     RECT  17.6 127.605 17.632 131.445 ;
     RECT  17.6 131.445 18.72 131.499 ;
     RECT  4.48 128.043 4.512 132.011 ;
     RECT  13.76 130.101 13.792 132.011 ;
     RECT  11.328 130.603 11.36 132.971 ;
     RECT  20.8 124.725 22.176 133.995 ;
     RECT  72.128 4.587 73.44 133.995 ;
     RECT  75.008 6.251 75.04 133.995 ;
     RECT  80.32 4.533 82.656 133.995 ;
     RECT  72.128 133.995 73.312 134.453 ;
     RECT  80.32 133.995 82.4 134.965 ;
     RECT  80.256 134.965 82.4 135.029 ;
     RECT  7.104 130.283 7.136 135.723 ;
     RECT  21.696 133.995 22.176 136.181 ;
     RECT  2.56 134.261 2.592 136.299 ;
     RECT  18.688 131.499 18.72 136.427 ;
     RECT  17.472 137.397 17.504 138.485 ;
     RECT  21.696 136.181 23.392 138.795 ;
     RECT  4.48 136.757 4.512 138.933 ;
     RECT  4.48 138.933 5.728 139.115 ;
     RECT  21.696 138.795 22.176 139.115 ;
     RECT  21.696 139.115 21.728 141.173 ;
     RECT  17.344 138.485 17.504 141.365 ;
     RECT  5.696 139.115 5.728 142.059 ;
     RECT  19.52 139.573 19.552 143.669 ;
     RECT  21.696 141.173 21.984 143.669 ;
     RECT  19.52 143.669 21.984 143.915 ;
     RECT  16.96 141.365 17.504 144.491 ;
     RECT  17.472 144.491 17.504 145.269 ;
     RECT  19.52 143.915 21.728 145.269 ;
     RECT  30.208 142.773 30.24 145.845 ;
     RECT  30.208 145.845 30.496 145.899 ;
     RECT  17.472 145.269 21.728 145.963 ;
     RECT  5.376 143.669 5.408 146.421 ;
     RECT  30.464 145.899 30.496 146.539 ;
     RECT  5.376 146.421 5.472 147.509 ;
     RECT  5.376 147.509 5.664 147.637 ;
     RECT  17.472 145.963 20.448 149.163 ;
     RECT  5.376 147.637 5.728 149.419 ;
     RECT  26.048 146.677 26.08 149.877 ;
     RECT  72 134.453 73.312 149.995 ;
     RECT  4.032 148.213 4.064 151.531 ;
     RECT  24.768 149.877 26.08 151.797 ;
     RECT  24.512 151.797 26.08 151.851 ;
     RECT  72.512 149.995 73.312 152.235 ;
     RECT  6.912 150.965 6.944 152.619 ;
     RECT  18.24 149.163 20.448 153.387 ;
     RECT  5.376 149.419 5.408 153.397 ;
     RECT  5.312 153.397 5.408 153.398 ;
     RECT  26.048 151.851 26.08 153.589 ;
     RECT  24.512 151.851 24.544 153.643 ;
     RECT  73.28 152.235 73.312 153.643 ;
     RECT  18.816 153.387 20.448 154.933 ;
     RECT  18.816 154.933 21.088 155.307 ;
     RECT  25.92 153.589 26.08 155.317 ;
     RECT  25.92 155.317 26.208 155.371 ;
     RECT  19.52 155.307 21.088 155.435 ;
     RECT  5.312 153.398 5.344 156.469 ;
     RECT  19.776 155.435 21.088 156.779 ;
     RECT  74.88 134.453 74.912 156.779 ;
     RECT  26.048 155.371 26.208 157.483 ;
     RECT  7.104 153.589 7.136 157.739 ;
     RECT  5.056 156.469 5.344 157.931 ;
     RECT  26.048 157.483 26.08 158.773 ;
     RECT  23.488 158.389 23.52 158.965 ;
     RECT  23.36 158.965 23.52 159.019 ;
     RECT  23.36 159.019 23.392 159.979 ;
     RECT  19.776 156.779 20.448 159.989 ;
     RECT  6.72 160.309 6.752 161.963 ;
     RECT  26.048 158.773 26.784 162.027 ;
     RECT  80.128 135.029 82.4 164.459 ;
     RECT  5.312 157.931 5.344 165.355 ;
     RECT  81.28 164.459 82.4 165.355 ;
     RECT  19.264 159.989 20.448 165.803 ;
     RECT  5.12 165.813 5.152 166.965 ;
     RECT  5.12 166.965 5.472 167.019 ;
     RECT  24.064 162.741 24.096 167.659 ;
     RECT  82.368 165.355 82.4 167.659 ;
     RECT  19.328 165.803 20.448 167.733 ;
     RECT  11.2 165.813 11.232 168.362 ;
     RECT  11.136 168.362 11.232 168.363 ;
     RECT  18.752 167.733 20.448 168.437 ;
     RECT  18.752 168.437 21.664 169.515 ;
     RECT  14.528 166.389 14.56 169.835 ;
     RECT  20.416 169.515 21.664 170.731 ;
     RECT  5.44 167.019 5.472 171.051 ;
     RECT  14.848 170.677 14.88 172.331 ;
     RECT  18.752 169.515 18.784 172.779 ;
     RECT  3.968 170.933 4 173.557 ;
     RECT  3.456 173.557 4 173.611 ;
     RECT  24.512 170.933 24.544 173.675 ;
     RECT  20.416 170.731 20.448 173.813 ;
     RECT  47.232 146.421 47.264 173.877 ;
     RECT  46.976 173.877 47.264 173.942 ;
     RECT  46.976 173.942 47.2 174.123 ;
     RECT  3.456 173.611 3.488 177.195 ;
     RECT  11.136 168.363 11.168 177.269 ;
     RECT  11.136 177.269 11.616 177.323 ;
     RECT  15.36 173.813 15.392 177.643 ;
     RECT  20.416 173.813 21.152 177.845 ;
     RECT  20.16 177.845 21.152 178.219 ;
     RECT  24.576 173.813 24.608 178.475 ;
     RECT  11.584 177.323 11.616 179.051 ;
     RECT  41.984 138.741 42.016 179.307 ;
     RECT  20.16 178.219 20.192 179.627 ;
     RECT  26.048 162.027 26.08 179.627 ;
     RECT  46.976 174.123 47.008 179.819 ;
     RECT  56.768 179.893 56.8 180.651 ;
     RECT  70.016 178.229 70.048 181.493 ;
     RECT  28.224 181.493 36.192 181.749 ;
     RECT  84.8 181.493 84.832 181.749 ;
     RECT  84.48 181.749 84.832 182.901 ;
     RECT  86.208 181.237 86.24 182.901 ;
     RECT  9.472 181.493 18.592 183.556 ;
     RECT  28.224 181.749 37.344 183.556 ;
     RECT  46.976 181.493 56.096 183.556 ;
     RECT  65.728 181.493 74.848 183.556 ;
     RECT  84.48 182.901 86.24 183.556 ;
  END
END ot_qkvd_kv_wq_leaf
END LIBRARY
